VERSION 5.8 ;
BUSBITCHARS "[]" ;
DIVIDERCHAR "/" ;
UNITS
    DATABASE MICRONS 1000 ;
END UNITS

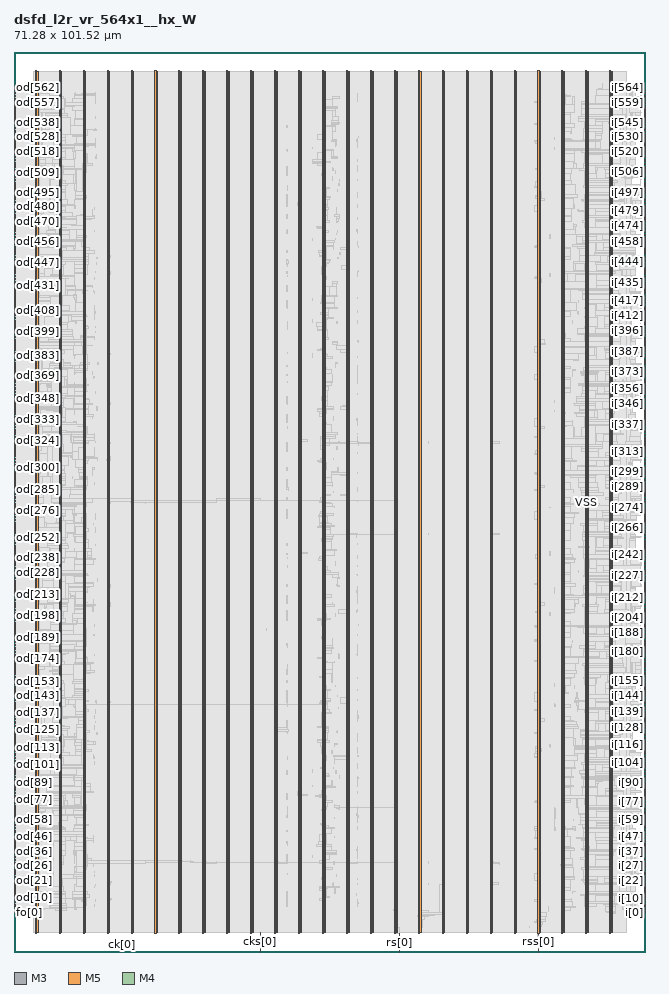
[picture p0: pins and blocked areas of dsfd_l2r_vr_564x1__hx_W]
MACRO dsfd_l2r_vr_564x1__hx_W
  FOREIGN dsfd_l2r_vr_564x1__hx_W 0 0 ;
  CLASS BLOCK ;
  SIZE 71.28 BY 101.52 ;
  PIN ck[0]
    DIRECTION INPUT ;
    USE SIGNAL ;
    PORT
      LAYER M3 ;
        RECT  12.132 0 12.15 0.144 ;
    END
    PORT
      LAYER M3 ;
        RECT  12.132 0.108 12.15 0.173 ;
    END
  END ck[0]
  PIN cks[0]
    DIRECTION INPUT ;
    USE SIGNAL ;
    PORT
      LAYER M5 ;
        RECT  27.792 0 27.816 0.192 ;
    END
    PORT
      LAYER M5 ;
        RECT  27.792 0.144 27.816 2.151 ;
    END
  END cks[0]
  PIN fo[0]
    DIRECTION OUTPUT ;
    USE SIGNAL ;
    PORT
      LAYER M4 ;
        RECT  0 4.416 0.192 4.44 ;
    END
  END fo[0]
  PIN i[0]
    DIRECTION INPUT ;
    USE SIGNAL ;
    PORT
      LAYER M4 ;
        RECT  71.088 4.416 71.28 4.44 ;
    END
  END i[0]
  PIN i[100]
    DIRECTION INPUT ;
    USE SIGNAL ;
    PORT
      LAYER M4 ;
        RECT  71.088 20.784 71.28 20.808 ;
    END
  END i[100]
  PIN i[101]
    DIRECTION INPUT ;
    USE SIGNAL ;
    PORT
      LAYER M4 ;
        RECT  71.088 20.928 71.28 20.952 ;
    END
  END i[101]
  PIN i[102]
    DIRECTION INPUT ;
    USE SIGNAL ;
    PORT
      LAYER M4 ;
        RECT  71.088 21.072 71.28 21.096 ;
    END
  END i[102]
  PIN i[103]
    DIRECTION INPUT ;
    USE SIGNAL ;
    PORT
      LAYER M4 ;
        RECT  71.088 21.264 71.28 21.288 ;
    END
  END i[103]
  PIN i[104]
    DIRECTION INPUT ;
    USE SIGNAL ;
    PORT
      LAYER M4 ;
        RECT  71.088 21.408 71.28 21.432 ;
    END
  END i[104]
  PIN i[105]
    DIRECTION INPUT ;
    USE SIGNAL ;
    PORT
      LAYER M4 ;
        RECT  71.088 21.6 71.28 21.624 ;
    END
  END i[105]
  PIN i[106]
    DIRECTION INPUT ;
    USE SIGNAL ;
    PORT
      LAYER M4 ;
        RECT  71.088 21.744 71.28 21.768 ;
    END
  END i[106]
  PIN i[107]
    DIRECTION INPUT ;
    USE SIGNAL ;
    PORT
      LAYER M4 ;
        RECT  71.088 21.888 71.28 21.912 ;
    END
  END i[107]
  PIN i[108]
    DIRECTION INPUT ;
    USE SIGNAL ;
    PORT
      LAYER M4 ;
        RECT  71.088 22.08 71.28 22.104 ;
    END
  END i[108]
  PIN i[109]
    DIRECTION INPUT ;
    USE SIGNAL ;
    PORT
      LAYER M4 ;
        RECT  71.088 22.224 71.28 22.248 ;
    END
  END i[109]
  PIN i[10]
    DIRECTION INPUT ;
    USE SIGNAL ;
    PORT
      LAYER M4 ;
        RECT  71.088 6.048 71.28 6.072 ;
    END
  END i[10]
  PIN i[110]
    DIRECTION INPUT ;
    USE SIGNAL ;
    PORT
      LAYER M4 ;
        RECT  71.088 22.416 71.28 22.44 ;
    END
  END i[110]
  PIN i[111]
    DIRECTION INPUT ;
    USE SIGNAL ;
    PORT
      LAYER M4 ;
        RECT  71.088 22.56 71.28 22.584 ;
    END
  END i[111]
  PIN i[112]
    DIRECTION INPUT ;
    USE SIGNAL ;
    PORT
      LAYER M4 ;
        RECT  71.088 22.752 71.28 22.776 ;
    END
  END i[112]
  PIN i[113]
    DIRECTION INPUT ;
    USE SIGNAL ;
    PORT
      LAYER M4 ;
        RECT  71.088 22.896 71.28 22.92 ;
    END
  END i[113]
  PIN i[114]
    DIRECTION INPUT ;
    USE SIGNAL ;
    PORT
      LAYER M4 ;
        RECT  71.088 23.04 71.28 23.064 ;
    END
  END i[114]
  PIN i[115]
    DIRECTION INPUT ;
    USE SIGNAL ;
    PORT
      LAYER M4 ;
        RECT  71.088 23.232 71.28 23.256 ;
    END
  END i[115]
  PIN i[116]
    DIRECTION INPUT ;
    USE SIGNAL ;
    PORT
      LAYER M4 ;
        RECT  71.088 23.376 71.28 23.4 ;
    END
  END i[116]
  PIN i[117]
    DIRECTION INPUT ;
    USE SIGNAL ;
    PORT
      LAYER M4 ;
        RECT  71.088 23.568 71.28 23.592 ;
    END
  END i[117]
  PIN i[118]
    DIRECTION INPUT ;
    USE SIGNAL ;
    PORT
      LAYER M4 ;
        RECT  71.088 23.712 71.28 23.736 ;
    END
  END i[118]
  PIN i[119]
    DIRECTION INPUT ;
    USE SIGNAL ;
    PORT
      LAYER M4 ;
        RECT  71.088 23.856 71.28 23.88 ;
    END
  END i[119]
  PIN i[11]
    DIRECTION INPUT ;
    USE SIGNAL ;
    PORT
      LAYER M4 ;
        RECT  71.088 6.192 71.28 6.216 ;
    END
  END i[11]
  PIN i[120]
    DIRECTION INPUT ;
    USE SIGNAL ;
    PORT
      LAYER M4 ;
        RECT  71.088 24.048 71.28 24.072 ;
    END
  END i[120]
  PIN i[121]
    DIRECTION INPUT ;
    USE SIGNAL ;
    PORT
      LAYER M4 ;
        RECT  71.088 24.192 71.28 24.216 ;
    END
  END i[121]
  PIN i[122]
    DIRECTION INPUT ;
    USE SIGNAL ;
    PORT
      LAYER M4 ;
        RECT  71.088 24.384 71.28 24.408 ;
    END
  END i[122]
  PIN i[123]
    DIRECTION INPUT ;
    USE SIGNAL ;
    PORT
      LAYER M4 ;
        RECT  71.088 24.528 71.28 24.552 ;
    END
  END i[123]
  PIN i[124]
    DIRECTION INPUT ;
    USE SIGNAL ;
    PORT
      LAYER M4 ;
        RECT  71.088 24.672 71.28 24.696 ;
    END
  END i[124]
  PIN i[125]
    DIRECTION INPUT ;
    USE SIGNAL ;
    PORT
      LAYER M4 ;
        RECT  71.088 24.864 71.28 24.888 ;
    END
  END i[125]
  PIN i[126]
    DIRECTION INPUT ;
    USE SIGNAL ;
    PORT
      LAYER M4 ;
        RECT  71.088 25.008 71.28 25.032 ;
    END
  END i[126]
  PIN i[127]
    DIRECTION INPUT ;
    USE SIGNAL ;
    PORT
      LAYER M4 ;
        RECT  71.088 25.2 71.28 25.224 ;
    END
  END i[127]
  PIN i[128]
    DIRECTION INPUT ;
    USE SIGNAL ;
    PORT
      LAYER M4 ;
        RECT  71.088 25.344 71.28 25.368 ;
    END
  END i[128]
  PIN i[129]
    DIRECTION INPUT ;
    USE SIGNAL ;
    PORT
      LAYER M4 ;
        RECT  71.088 25.488 71.28 25.512 ;
    END
  END i[129]
  PIN i[12]
    DIRECTION INPUT ;
    USE SIGNAL ;
    PORT
      LAYER M4 ;
        RECT  71.088 6.384 71.28 6.408 ;
    END
  END i[12]
  PIN i[130]
    DIRECTION INPUT ;
    USE SIGNAL ;
    PORT
      LAYER M4 ;
        RECT  71.088 25.68 71.28 25.704 ;
    END
  END i[130]
  PIN i[131]
    DIRECTION INPUT ;
    USE SIGNAL ;
    PORT
      LAYER M4 ;
        RECT  71.088 25.824 71.28 25.848 ;
    END
  END i[131]
  PIN i[132]
    DIRECTION INPUT ;
    USE SIGNAL ;
    PORT
      LAYER M4 ;
        RECT  71.088 26.016 71.28 26.04 ;
    END
  END i[132]
  PIN i[133]
    DIRECTION INPUT ;
    USE SIGNAL ;
    PORT
      LAYER M4 ;
        RECT  71.088 26.16 71.28 26.184 ;
    END
  END i[133]
  PIN i[134]
    DIRECTION INPUT ;
    USE SIGNAL ;
    PORT
      LAYER M4 ;
        RECT  71.088 26.304 71.28 26.328 ;
    END
  END i[134]
  PIN i[135]
    DIRECTION INPUT ;
    USE SIGNAL ;
    PORT
      LAYER M4 ;
        RECT  71.088 26.496 71.28 26.52 ;
    END
  END i[135]
  PIN i[136]
    DIRECTION INPUT ;
    USE SIGNAL ;
    PORT
      LAYER M4 ;
        RECT  71.088 26.64 71.28 26.664 ;
    END
  END i[136]
  PIN i[137]
    DIRECTION INPUT ;
    USE SIGNAL ;
    PORT
      LAYER M4 ;
        RECT  71.088 26.832 71.28 26.856 ;
    END
  END i[137]
  PIN i[138]
    DIRECTION INPUT ;
    USE SIGNAL ;
    PORT
      LAYER M4 ;
        RECT  71.088 26.976 71.28 27 ;
    END
  END i[138]
  PIN i[139]
    DIRECTION INPUT ;
    USE SIGNAL ;
    PORT
      LAYER M4 ;
        RECT  71.088 27.12 71.28 27.144 ;
    END
  END i[139]
  PIN i[13]
    DIRECTION INPUT ;
    USE SIGNAL ;
    PORT
      LAYER M4 ;
        RECT  71.088 6.528 71.28 6.552 ;
    END
  END i[13]
  PIN i[140]
    DIRECTION INPUT ;
    USE SIGNAL ;
    PORT
      LAYER M4 ;
        RECT  71.088 27.312 71.28 27.336 ;
    END
  END i[140]
  PIN i[141]
    DIRECTION INPUT ;
    USE SIGNAL ;
    PORT
      LAYER M4 ;
        RECT  71.088 27.456 71.28 27.48 ;
    END
  END i[141]
  PIN i[142]
    DIRECTION INPUT ;
    USE SIGNAL ;
    PORT
      LAYER M4 ;
        RECT  71.088 27.648 71.28 27.672 ;
    END
  END i[142]
  PIN i[143]
    DIRECTION INPUT ;
    USE SIGNAL ;
    PORT
      LAYER M4 ;
        RECT  71.088 27.792 71.28 27.816 ;
    END
  END i[143]
  PIN i[144]
    DIRECTION INPUT ;
    USE SIGNAL ;
    PORT
      LAYER M4 ;
        RECT  71.088 27.984 71.28 28.008 ;
    END
  END i[144]
  PIN i[145]
    DIRECTION INPUT ;
    USE SIGNAL ;
    PORT
      LAYER M4 ;
        RECT  71.088 28.128 71.28 28.152 ;
    END
  END i[145]
  PIN i[146]
    DIRECTION INPUT ;
    USE SIGNAL ;
    PORT
      LAYER M4 ;
        RECT  71.088 28.272 71.28 28.296 ;
    END
  END i[146]
  PIN i[147]
    DIRECTION INPUT ;
    USE SIGNAL ;
    PORT
      LAYER M4 ;
        RECT  71.088 28.464 71.28 28.488 ;
    END
  END i[147]
  PIN i[148]
    DIRECTION INPUT ;
    USE SIGNAL ;
    PORT
      LAYER M4 ;
        RECT  71.088 28.608 71.28 28.632 ;
    END
  END i[148]
  PIN i[149]
    DIRECTION INPUT ;
    USE SIGNAL ;
    PORT
      LAYER M4 ;
        RECT  71.088 28.8 71.28 28.824 ;
    END
  END i[149]
  PIN i[14]
    DIRECTION INPUT ;
    USE SIGNAL ;
    PORT
      LAYER M4 ;
        RECT  71.088 6.72 71.28 6.744 ;
    END
  END i[14]
  PIN i[150]
    DIRECTION INPUT ;
    USE SIGNAL ;
    PORT
      LAYER M4 ;
        RECT  71.088 28.944 71.28 28.968 ;
    END
  END i[150]
  PIN i[151]
    DIRECTION INPUT ;
    USE SIGNAL ;
    PORT
      LAYER M4 ;
        RECT  71.088 29.088 71.28 29.112 ;
    END
  END i[151]
  PIN i[152]
    DIRECTION INPUT ;
    USE SIGNAL ;
    PORT
      LAYER M4 ;
        RECT  71.088 29.28 71.28 29.304 ;
    END
  END i[152]
  PIN i[153]
    DIRECTION INPUT ;
    USE SIGNAL ;
    PORT
      LAYER M4 ;
        RECT  71.088 29.424 71.28 29.448 ;
    END
  END i[153]
  PIN i[154]
    DIRECTION INPUT ;
    USE SIGNAL ;
    PORT
      LAYER M4 ;
        RECT  71.088 29.616 71.28 29.64 ;
    END
  END i[154]
  PIN i[155]
    DIRECTION INPUT ;
    USE SIGNAL ;
    PORT
      LAYER M4 ;
        RECT  71.088 29.76 71.28 29.784 ;
    END
  END i[155]
  PIN i[156]
    DIRECTION INPUT ;
    USE SIGNAL ;
    PORT
      LAYER M4 ;
        RECT  71.088 29.904 71.28 29.928 ;
    END
  END i[156]
  PIN i[157]
    DIRECTION INPUT ;
    USE SIGNAL ;
    PORT
      LAYER M4 ;
        RECT  71.088 30.096 71.28 30.12 ;
    END
  END i[157]
  PIN i[158]
    DIRECTION INPUT ;
    USE SIGNAL ;
    PORT
      LAYER M4 ;
        RECT  71.088 30.24 71.28 30.264 ;
    END
  END i[158]
  PIN i[159]
    DIRECTION INPUT ;
    USE SIGNAL ;
    PORT
      LAYER M4 ;
        RECT  71.088 30.432 71.28 30.456 ;
    END
  END i[159]
  PIN i[15]
    DIRECTION INPUT ;
    USE SIGNAL ;
    PORT
      LAYER M4 ;
        RECT  71.088 6.864 71.28 6.888 ;
    END
  END i[15]
  PIN i[160]
    DIRECTION INPUT ;
    USE SIGNAL ;
    PORT
      LAYER M4 ;
        RECT  71.088 30.576 71.28 30.6 ;
    END
  END i[160]
  PIN i[161]
    DIRECTION INPUT ;
    USE SIGNAL ;
    PORT
      LAYER M4 ;
        RECT  71.088 30.72 71.28 30.744 ;
    END
  END i[161]
  PIN i[162]
    DIRECTION INPUT ;
    USE SIGNAL ;
    PORT
      LAYER M4 ;
        RECT  71.088 30.912 71.28 30.936 ;
    END
  END i[162]
  PIN i[163]
    DIRECTION INPUT ;
    USE SIGNAL ;
    PORT
      LAYER M4 ;
        RECT  71.088 31.056 71.28 31.08 ;
    END
  END i[163]
  PIN i[164]
    DIRECTION INPUT ;
    USE SIGNAL ;
    PORT
      LAYER M4 ;
        RECT  71.088 31.248 71.28 31.272 ;
    END
  END i[164]
  PIN i[165]
    DIRECTION INPUT ;
    USE SIGNAL ;
    PORT
      LAYER M4 ;
        RECT  71.088 31.392 71.28 31.416 ;
    END
  END i[165]
  PIN i[166]
    DIRECTION INPUT ;
    USE SIGNAL ;
    PORT
      LAYER M4 ;
        RECT  71.088 31.536 71.28 31.56 ;
    END
  END i[166]
  PIN i[167]
    DIRECTION INPUT ;
    USE SIGNAL ;
    PORT
      LAYER M4 ;
        RECT  71.088 31.728 71.28 31.752 ;
    END
  END i[167]
  PIN i[168]
    DIRECTION INPUT ;
    USE SIGNAL ;
    PORT
      LAYER M4 ;
        RECT  71.088 31.872 71.28 31.896 ;
    END
  END i[168]
  PIN i[169]
    DIRECTION INPUT ;
    USE SIGNAL ;
    PORT
      LAYER M4 ;
        RECT  71.088 32.064 71.28 32.088 ;
    END
  END i[169]
  PIN i[16]
    DIRECTION INPUT ;
    USE SIGNAL ;
    PORT
      LAYER M4 ;
        RECT  71.088 7.008 71.28 7.032 ;
    END
  END i[16]
  PIN i[170]
    DIRECTION INPUT ;
    USE SIGNAL ;
    PORT
      LAYER M4 ;
        RECT  71.088 32.208 71.28 32.232 ;
    END
  END i[170]
  PIN i[171]
    DIRECTION INPUT ;
    USE SIGNAL ;
    PORT
      LAYER M4 ;
        RECT  71.088 32.352 71.28 32.376 ;
    END
  END i[171]
  PIN i[172]
    DIRECTION INPUT ;
    USE SIGNAL ;
    PORT
      LAYER M4 ;
        RECT  71.088 32.544 71.28 32.568 ;
    END
  END i[172]
  PIN i[173]
    DIRECTION INPUT ;
    USE SIGNAL ;
    PORT
      LAYER M4 ;
        RECT  71.088 32.688 71.28 32.712 ;
    END
  END i[173]
  PIN i[174]
    DIRECTION INPUT ;
    USE SIGNAL ;
    PORT
      LAYER M4 ;
        RECT  71.088 32.88 71.28 32.904 ;
    END
  END i[174]
  PIN i[175]
    DIRECTION INPUT ;
    USE SIGNAL ;
    PORT
      LAYER M4 ;
        RECT  71.088 33.024 71.28 33.048 ;
    END
  END i[175]
  PIN i[176]
    DIRECTION INPUT ;
    USE SIGNAL ;
    PORT
      LAYER M4 ;
        RECT  71.088 33.216 71.28 33.24 ;
    END
  END i[176]
  PIN i[177]
    DIRECTION INPUT ;
    USE SIGNAL ;
    PORT
      LAYER M4 ;
        RECT  71.088 33.36 71.28 33.384 ;
    END
  END i[177]
  PIN i[178]
    DIRECTION INPUT ;
    USE SIGNAL ;
    PORT
      LAYER M4 ;
        RECT  71.088 33.504 71.28 33.528 ;
    END
  END i[178]
  PIN i[179]
    DIRECTION INPUT ;
    USE SIGNAL ;
    PORT
      LAYER M4 ;
        RECT  71.088 33.696 71.28 33.72 ;
    END
  END i[179]
  PIN i[17]
    DIRECTION INPUT ;
    USE SIGNAL ;
    PORT
      LAYER M4 ;
        RECT  71.088 7.2 71.28 7.224 ;
    END
  END i[17]
  PIN i[180]
    DIRECTION INPUT ;
    USE SIGNAL ;
    PORT
      LAYER M4 ;
        RECT  71.088 33.84 71.28 33.864 ;
    END
  END i[180]
  PIN i[181]
    DIRECTION INPUT ;
    USE SIGNAL ;
    PORT
      LAYER M4 ;
        RECT  71.088 34.032 71.28 34.056 ;
    END
  END i[181]
  PIN i[182]
    DIRECTION INPUT ;
    USE SIGNAL ;
    PORT
      LAYER M4 ;
        RECT  71.088 34.176 71.28 34.2 ;
    END
  END i[182]
  PIN i[183]
    DIRECTION INPUT ;
    USE SIGNAL ;
    PORT
      LAYER M4 ;
        RECT  71.088 34.32 71.28 34.344 ;
    END
  END i[183]
  PIN i[184]
    DIRECTION INPUT ;
    USE SIGNAL ;
    PORT
      LAYER M4 ;
        RECT  71.088 34.512 71.28 34.536 ;
    END
  END i[184]
  PIN i[185]
    DIRECTION INPUT ;
    USE SIGNAL ;
    PORT
      LAYER M4 ;
        RECT  71.088 34.656 71.28 34.68 ;
    END
  END i[185]
  PIN i[186]
    DIRECTION INPUT ;
    USE SIGNAL ;
    PORT
      LAYER M4 ;
        RECT  71.088 34.848 71.28 34.872 ;
    END
  END i[186]
  PIN i[187]
    DIRECTION INPUT ;
    USE SIGNAL ;
    PORT
      LAYER M4 ;
        RECT  71.088 34.992 71.28 35.016 ;
    END
  END i[187]
  PIN i[188]
    DIRECTION INPUT ;
    USE SIGNAL ;
    PORT
      LAYER M4 ;
        RECT  71.088 35.136 71.28 35.16 ;
    END
  END i[188]
  PIN i[189]
    DIRECTION INPUT ;
    USE SIGNAL ;
    PORT
      LAYER M4 ;
        RECT  71.088 35.328 71.28 35.352 ;
    END
  END i[189]
  PIN i[18]
    DIRECTION INPUT ;
    USE SIGNAL ;
    PORT
      LAYER M4 ;
        RECT  71.088 7.344 71.28 7.368 ;
    END
  END i[18]
  PIN i[190]
    DIRECTION INPUT ;
    USE SIGNAL ;
    PORT
      LAYER M4 ;
        RECT  71.088 35.472 71.28 35.496 ;
    END
  END i[190]
  PIN i[191]
    DIRECTION INPUT ;
    USE SIGNAL ;
    PORT
      LAYER M4 ;
        RECT  71.088 35.664 71.28 35.688 ;
    END
  END i[191]
  PIN i[192]
    DIRECTION INPUT ;
    USE SIGNAL ;
    PORT
      LAYER M4 ;
        RECT  71.088 35.808 71.28 35.832 ;
    END
  END i[192]
  PIN i[193]
    DIRECTION INPUT ;
    USE SIGNAL ;
    PORT
      LAYER M4 ;
        RECT  71.088 35.952 71.28 35.976 ;
    END
  END i[193]
  PIN i[194]
    DIRECTION INPUT ;
    USE SIGNAL ;
    PORT
      LAYER M4 ;
        RECT  71.088 36.144 71.28 36.168 ;
    END
  END i[194]
  PIN i[195]
    DIRECTION INPUT ;
    USE SIGNAL ;
    PORT
      LAYER M4 ;
        RECT  71.088 36.288 71.28 36.312 ;
    END
  END i[195]
  PIN i[196]
    DIRECTION INPUT ;
    USE SIGNAL ;
    PORT
      LAYER M4 ;
        RECT  71.088 36.48 71.28 36.504 ;
    END
  END i[196]
  PIN i[197]
    DIRECTION INPUT ;
    USE SIGNAL ;
    PORT
      LAYER M4 ;
        RECT  71.088 36.624 71.28 36.648 ;
    END
  END i[197]
  PIN i[198]
    DIRECTION INPUT ;
    USE SIGNAL ;
    PORT
      LAYER M4 ;
        RECT  71.088 36.768 71.28 36.792 ;
    END
  END i[198]
  PIN i[199]
    DIRECTION INPUT ;
    USE SIGNAL ;
    PORT
      LAYER M4 ;
        RECT  71.088 36.96 71.28 36.984 ;
    END
  END i[199]
  PIN i[19]
    DIRECTION INPUT ;
    USE SIGNAL ;
    PORT
      LAYER M4 ;
        RECT  71.088 7.536 71.28 7.56 ;
    END
  END i[19]
  PIN i[1]
    DIRECTION INPUT ;
    USE SIGNAL ;
    PORT
      LAYER M4 ;
        RECT  71.088 4.56 71.28 4.584 ;
    END
  END i[1]
  PIN i[200]
    DIRECTION INPUT ;
    USE SIGNAL ;
    PORT
      LAYER M4 ;
        RECT  71.088 37.104 71.28 37.128 ;
    END
  END i[200]
  PIN i[201]
    DIRECTION INPUT ;
    USE SIGNAL ;
    PORT
      LAYER M4 ;
        RECT  71.088 37.296 71.28 37.32 ;
    END
  END i[201]
  PIN i[202]
    DIRECTION INPUT ;
    USE SIGNAL ;
    PORT
      LAYER M4 ;
        RECT  71.088 37.44 71.28 37.464 ;
    END
  END i[202]
  PIN i[203]
    DIRECTION INPUT ;
    USE SIGNAL ;
    PORT
      LAYER M4 ;
        RECT  71.088 37.632 71.28 37.656 ;
    END
  END i[203]
  PIN i[204]
    DIRECTION INPUT ;
    USE SIGNAL ;
    PORT
      LAYER M4 ;
        RECT  71.088 37.776 71.28 37.8 ;
    END
  END i[204]
  PIN i[205]
    DIRECTION INPUT ;
    USE SIGNAL ;
    PORT
      LAYER M4 ;
        RECT  71.088 37.92 71.28 37.944 ;
    END
  END i[205]
  PIN i[206]
    DIRECTION INPUT ;
    USE SIGNAL ;
    PORT
      LAYER M4 ;
        RECT  71.088 38.112 71.28 38.136 ;
    END
  END i[206]
  PIN i[207]
    DIRECTION INPUT ;
    USE SIGNAL ;
    PORT
      LAYER M4 ;
        RECT  71.088 38.256 71.28 38.28 ;
    END
  END i[207]
  PIN i[208]
    DIRECTION INPUT ;
    USE SIGNAL ;
    PORT
      LAYER M4 ;
        RECT  71.088 38.448 71.28 38.472 ;
    END
  END i[208]
  PIN i[209]
    DIRECTION INPUT ;
    USE SIGNAL ;
    PORT
      LAYER M4 ;
        RECT  71.088 38.592 71.28 38.616 ;
    END
  END i[209]
  PIN i[20]
    DIRECTION INPUT ;
    USE SIGNAL ;
    PORT
      LAYER M4 ;
        RECT  71.088 7.68 71.28 7.704 ;
    END
  END i[20]
  PIN i[210]
    DIRECTION INPUT ;
    USE SIGNAL ;
    PORT
      LAYER M4 ;
        RECT  71.088 38.736 71.28 38.76 ;
    END
  END i[210]
  PIN i[211]
    DIRECTION INPUT ;
    USE SIGNAL ;
    PORT
      LAYER M4 ;
        RECT  71.088 38.928 71.28 38.952 ;
    END
  END i[211]
  PIN i[212]
    DIRECTION INPUT ;
    USE SIGNAL ;
    PORT
      LAYER M4 ;
        RECT  71.088 39.072 71.28 39.096 ;
    END
  END i[212]
  PIN i[213]
    DIRECTION INPUT ;
    USE SIGNAL ;
    PORT
      LAYER M4 ;
        RECT  71.088 39.264 71.28 39.288 ;
    END
  END i[213]
  PIN i[214]
    DIRECTION INPUT ;
    USE SIGNAL ;
    PORT
      LAYER M4 ;
        RECT  71.088 39.408 71.28 39.432 ;
    END
  END i[214]
  PIN i[215]
    DIRECTION INPUT ;
    USE SIGNAL ;
    PORT
      LAYER M4 ;
        RECT  71.088 39.552 71.28 39.576 ;
    END
  END i[215]
  PIN i[216]
    DIRECTION INPUT ;
    USE SIGNAL ;
    PORT
      LAYER M4 ;
        RECT  71.088 39.744 71.28 39.768 ;
    END
  END i[216]
  PIN i[217]
    DIRECTION INPUT ;
    USE SIGNAL ;
    PORT
      LAYER M4 ;
        RECT  71.088 39.888 71.28 39.912 ;
    END
  END i[217]
  PIN i[218]
    DIRECTION INPUT ;
    USE SIGNAL ;
    PORT
      LAYER M4 ;
        RECT  71.088 40.08 71.28 40.104 ;
    END
  END i[218]
  PIN i[219]
    DIRECTION INPUT ;
    USE SIGNAL ;
    PORT
      LAYER M4 ;
        RECT  71.088 40.224 71.28 40.248 ;
    END
  END i[219]
  PIN i[21]
    DIRECTION INPUT ;
    USE SIGNAL ;
    PORT
      LAYER M4 ;
        RECT  71.088 7.824 71.28 7.848 ;
    END
  END i[21]
  PIN i[220]
    DIRECTION INPUT ;
    USE SIGNAL ;
    PORT
      LAYER M4 ;
        RECT  71.088 40.368 71.28 40.392 ;
    END
  END i[220]
  PIN i[221]
    DIRECTION INPUT ;
    USE SIGNAL ;
    PORT
      LAYER M4 ;
        RECT  71.088 40.56 71.28 40.584 ;
    END
  END i[221]
  PIN i[222]
    DIRECTION INPUT ;
    USE SIGNAL ;
    PORT
      LAYER M4 ;
        RECT  71.088 40.704 71.28 40.728 ;
    END
  END i[222]
  PIN i[223]
    DIRECTION INPUT ;
    USE SIGNAL ;
    PORT
      LAYER M4 ;
        RECT  71.088 40.896 71.28 40.92 ;
    END
  END i[223]
  PIN i[224]
    DIRECTION INPUT ;
    USE SIGNAL ;
    PORT
      LAYER M4 ;
        RECT  71.088 41.04 71.28 41.064 ;
    END
  END i[224]
  PIN i[225]
    DIRECTION INPUT ;
    USE SIGNAL ;
    PORT
      LAYER M4 ;
        RECT  71.088 41.184 71.28 41.208 ;
    END
  END i[225]
  PIN i[226]
    DIRECTION INPUT ;
    USE SIGNAL ;
    PORT
      LAYER M4 ;
        RECT  71.088 41.376 71.28 41.4 ;
    END
  END i[226]
  PIN i[227]
    DIRECTION INPUT ;
    USE SIGNAL ;
    PORT
      LAYER M4 ;
        RECT  71.088 41.52 71.28 41.544 ;
    END
  END i[227]
  PIN i[228]
    DIRECTION INPUT ;
    USE SIGNAL ;
    PORT
      LAYER M4 ;
        RECT  71.088 41.712 71.28 41.736 ;
    END
  END i[228]
  PIN i[229]
    DIRECTION INPUT ;
    USE SIGNAL ;
    PORT
      LAYER M4 ;
        RECT  71.088 41.856 71.28 41.88 ;
    END
  END i[229]
  PIN i[22]
    DIRECTION INPUT ;
    USE SIGNAL ;
    PORT
      LAYER M4 ;
        RECT  71.088 8.016 71.28 8.04 ;
    END
  END i[22]
  PIN i[230]
    DIRECTION INPUT ;
    USE SIGNAL ;
    PORT
      LAYER M4 ;
        RECT  71.088 42 71.28 42.024 ;
    END
  END i[230]
  PIN i[231]
    DIRECTION INPUT ;
    USE SIGNAL ;
    PORT
      LAYER M4 ;
        RECT  71.088 42.192 71.28 42.216 ;
    END
  END i[231]
  PIN i[232]
    DIRECTION INPUT ;
    USE SIGNAL ;
    PORT
      LAYER M4 ;
        RECT  71.088 42.336 71.28 42.36 ;
    END
  END i[232]
  PIN i[233]
    DIRECTION INPUT ;
    USE SIGNAL ;
    PORT
      LAYER M4 ;
        RECT  71.088 42.528 71.28 42.552 ;
    END
  END i[233]
  PIN i[234]
    DIRECTION INPUT ;
    USE SIGNAL ;
    PORT
      LAYER M4 ;
        RECT  71.088 42.672 71.28 42.696 ;
    END
  END i[234]
  PIN i[235]
    DIRECTION INPUT ;
    USE SIGNAL ;
    PORT
      LAYER M4 ;
        RECT  71.088 42.864 71.28 42.888 ;
    END
  END i[235]
  PIN i[236]
    DIRECTION INPUT ;
    USE SIGNAL ;
    PORT
      LAYER M4 ;
        RECT  71.088 43.008 71.28 43.032 ;
    END
  END i[236]
  PIN i[237]
    DIRECTION INPUT ;
    USE SIGNAL ;
    PORT
      LAYER M4 ;
        RECT  71.088 43.152 71.28 43.176 ;
    END
  END i[237]
  PIN i[238]
    DIRECTION INPUT ;
    USE SIGNAL ;
    PORT
      LAYER M4 ;
        RECT  71.088 43.344 71.28 43.368 ;
    END
  END i[238]
  PIN i[239]
    DIRECTION INPUT ;
    USE SIGNAL ;
    PORT
      LAYER M4 ;
        RECT  71.088 43.488 71.28 43.512 ;
    END
  END i[239]
  PIN i[23]
    DIRECTION INPUT ;
    USE SIGNAL ;
    PORT
      LAYER M4 ;
        RECT  71.088 8.16 71.28 8.184 ;
    END
  END i[23]
  PIN i[240]
    DIRECTION INPUT ;
    USE SIGNAL ;
    PORT
      LAYER M4 ;
        RECT  71.088 43.68 71.28 43.704 ;
    END
  END i[240]
  PIN i[241]
    DIRECTION INPUT ;
    USE SIGNAL ;
    PORT
      LAYER M4 ;
        RECT  71.088 43.824 71.28 43.848 ;
    END
  END i[241]
  PIN i[242]
    DIRECTION INPUT ;
    USE SIGNAL ;
    PORT
      LAYER M4 ;
        RECT  71.088 43.968 71.28 43.992 ;
    END
  END i[242]
  PIN i[243]
    DIRECTION INPUT ;
    USE SIGNAL ;
    PORT
      LAYER M4 ;
        RECT  71.088 44.16 71.28 44.184 ;
    END
  END i[243]
  PIN i[244]
    DIRECTION INPUT ;
    USE SIGNAL ;
    PORT
      LAYER M4 ;
        RECT  71.088 44.304 71.28 44.328 ;
    END
  END i[244]
  PIN i[245]
    DIRECTION INPUT ;
    USE SIGNAL ;
    PORT
      LAYER M4 ;
        RECT  71.088 44.496 71.28 44.52 ;
    END
  END i[245]
  PIN i[246]
    DIRECTION INPUT ;
    USE SIGNAL ;
    PORT
      LAYER M4 ;
        RECT  71.088 44.64 71.28 44.664 ;
    END
  END i[246]
  PIN i[247]
    DIRECTION INPUT ;
    USE SIGNAL ;
    PORT
      LAYER M4 ;
        RECT  71.088 44.784 71.28 44.808 ;
    END
  END i[247]
  PIN i[248]
    DIRECTION INPUT ;
    USE SIGNAL ;
    PORT
      LAYER M4 ;
        RECT  71.088 44.976 71.28 45 ;
    END
  END i[248]
  PIN i[249]
    DIRECTION INPUT ;
    USE SIGNAL ;
    PORT
      LAYER M4 ;
        RECT  71.088 45.12 71.28 45.144 ;
    END
  END i[249]
  PIN i[24]
    DIRECTION INPUT ;
    USE SIGNAL ;
    PORT
      LAYER M4 ;
        RECT  71.088 8.352 71.28 8.376 ;
    END
  END i[24]
  PIN i[250]
    DIRECTION INPUT ;
    USE SIGNAL ;
    PORT
      LAYER M4 ;
        RECT  71.088 45.312 71.28 45.336 ;
    END
  END i[250]
  PIN i[251]
    DIRECTION INPUT ;
    USE SIGNAL ;
    PORT
      LAYER M4 ;
        RECT  71.088 45.456 71.28 45.48 ;
    END
  END i[251]
  PIN i[252]
    DIRECTION INPUT ;
    USE SIGNAL ;
    PORT
      LAYER M4 ;
        RECT  71.088 45.6 71.28 45.624 ;
    END
  END i[252]
  PIN i[253]
    DIRECTION INPUT ;
    USE SIGNAL ;
    PORT
      LAYER M4 ;
        RECT  71.088 45.792 71.28 45.816 ;
    END
  END i[253]
  PIN i[254]
    DIRECTION INPUT ;
    USE SIGNAL ;
    PORT
      LAYER M4 ;
        RECT  71.088 45.936 71.28 45.96 ;
    END
  END i[254]
  PIN i[255]
    DIRECTION INPUT ;
    USE SIGNAL ;
    PORT
      LAYER M4 ;
        RECT  71.088 46.128 71.28 46.152 ;
    END
  END i[255]
  PIN i[256]
    DIRECTION INPUT ;
    USE SIGNAL ;
    PORT
      LAYER M4 ;
        RECT  71.088 46.272 71.28 46.296 ;
    END
  END i[256]
  PIN i[257]
    DIRECTION INPUT ;
    USE SIGNAL ;
    PORT
      LAYER M4 ;
        RECT  71.088 46.416 71.28 46.44 ;
    END
  END i[257]
  PIN i[258]
    DIRECTION INPUT ;
    USE SIGNAL ;
    PORT
      LAYER M4 ;
        RECT  71.088 46.608 71.28 46.632 ;
    END
  END i[258]
  PIN i[259]
    DIRECTION INPUT ;
    USE SIGNAL ;
    PORT
      LAYER M4 ;
        RECT  71.088 46.752 71.28 46.776 ;
    END
  END i[259]
  PIN i[25]
    DIRECTION INPUT ;
    USE SIGNAL ;
    PORT
      LAYER M4 ;
        RECT  71.088 8.496 71.28 8.52 ;
    END
  END i[25]
  PIN i[260]
    DIRECTION INPUT ;
    USE SIGNAL ;
    PORT
      LAYER M4 ;
        RECT  71.088 46.944 71.28 46.968 ;
    END
  END i[260]
  PIN i[261]
    DIRECTION INPUT ;
    USE SIGNAL ;
    PORT
      LAYER M4 ;
        RECT  71.088 47.088 71.28 47.112 ;
    END
  END i[261]
  PIN i[262]
    DIRECTION INPUT ;
    USE SIGNAL ;
    PORT
      LAYER M4 ;
        RECT  71.088 47.28 71.28 47.304 ;
    END
  END i[262]
  PIN i[263]
    DIRECTION INPUT ;
    USE SIGNAL ;
    PORT
      LAYER M4 ;
        RECT  71.088 47.424 71.28 47.448 ;
    END
  END i[263]
  PIN i[264]
    DIRECTION INPUT ;
    USE SIGNAL ;
    PORT
      LAYER M4 ;
        RECT  71.088 47.568 71.28 47.592 ;
    END
  END i[264]
  PIN i[265]
    DIRECTION INPUT ;
    USE SIGNAL ;
    PORT
      LAYER M4 ;
        RECT  71.088 47.76 71.28 47.784 ;
    END
  END i[265]
  PIN i[266]
    DIRECTION INPUT ;
    USE SIGNAL ;
    PORT
      LAYER M4 ;
        RECT  71.088 47.904 71.28 47.928 ;
    END
  END i[266]
  PIN i[267]
    DIRECTION INPUT ;
    USE SIGNAL ;
    PORT
      LAYER M4 ;
        RECT  71.088 48.096 71.28 48.12 ;
    END
  END i[267]
  PIN i[268]
    DIRECTION INPUT ;
    USE SIGNAL ;
    PORT
      LAYER M4 ;
        RECT  71.088 48.24 71.28 48.264 ;
    END
  END i[268]
  PIN i[269]
    DIRECTION INPUT ;
    USE SIGNAL ;
    PORT
      LAYER M4 ;
        RECT  71.088 48.384 71.28 48.408 ;
    END
  END i[269]
  PIN i[26]
    DIRECTION INPUT ;
    USE SIGNAL ;
    PORT
      LAYER M4 ;
        RECT  71.088 8.688 71.28 8.712 ;
    END
  END i[26]
  PIN i[270]
    DIRECTION INPUT ;
    USE SIGNAL ;
    PORT
      LAYER M4 ;
        RECT  71.088 48.576 71.28 48.6 ;
    END
  END i[270]
  PIN i[271]
    DIRECTION INPUT ;
    USE SIGNAL ;
    PORT
      LAYER M4 ;
        RECT  71.088 48.72 71.28 48.744 ;
    END
  END i[271]
  PIN i[272]
    DIRECTION INPUT ;
    USE SIGNAL ;
    PORT
      LAYER M4 ;
        RECT  71.088 48.912 71.28 48.936 ;
    END
  END i[272]
  PIN i[273]
    DIRECTION INPUT ;
    USE SIGNAL ;
    PORT
      LAYER M4 ;
        RECT  71.088 49.056 71.28 49.08 ;
    END
  END i[273]
  PIN i[274]
    DIRECTION INPUT ;
    USE SIGNAL ;
    PORT
      LAYER M4 ;
        RECT  71.088 49.2 71.28 49.224 ;
    END
  END i[274]
  PIN i[275]
    DIRECTION INPUT ;
    USE SIGNAL ;
    PORT
      LAYER M4 ;
        RECT  71.088 49.392 71.28 49.416 ;
    END
  END i[275]
  PIN i[276]
    DIRECTION INPUT ;
    USE SIGNAL ;
    PORT
      LAYER M4 ;
        RECT  71.088 49.536 71.28 49.56 ;
    END
  END i[276]
  PIN i[277]
    DIRECTION INPUT ;
    USE SIGNAL ;
    PORT
      LAYER M4 ;
        RECT  71.088 49.728 71.28 49.752 ;
    END
  END i[277]
  PIN i[278]
    DIRECTION INPUT ;
    USE SIGNAL ;
    PORT
      LAYER M4 ;
        RECT  71.088 49.872 71.28 49.896 ;
    END
  END i[278]
  PIN i[279]
    DIRECTION INPUT ;
    USE SIGNAL ;
    PORT
      LAYER M4 ;
        RECT  71.088 50.016 71.28 50.04 ;
    END
  END i[279]
  PIN i[27]
    DIRECTION INPUT ;
    USE SIGNAL ;
    PORT
      LAYER M4 ;
        RECT  71.088 8.832 71.28 8.856 ;
    END
  END i[27]
  PIN i[280]
    DIRECTION INPUT ;
    USE SIGNAL ;
    PORT
      LAYER M4 ;
        RECT  71.088 50.208 71.28 50.232 ;
    END
  END i[280]
  PIN i[281]
    DIRECTION INPUT ;
    USE SIGNAL ;
    PORT
      LAYER M4 ;
        RECT  71.088 50.352 71.28 50.376 ;
    END
  END i[281]
  PIN i[282]
    DIRECTION INPUT ;
    USE SIGNAL ;
    PORT
      LAYER M4 ;
        RECT  71.088 50.544 71.28 50.568 ;
    END
  END i[282]
  PIN i[283]
    DIRECTION INPUT ;
    USE SIGNAL ;
    PORT
      LAYER M4 ;
        RECT  71.088 50.688 71.28 50.712 ;
    END
  END i[283]
  PIN i[284]
    DIRECTION INPUT ;
    USE SIGNAL ;
    PORT
      LAYER M4 ;
        RECT  71.088 50.832 71.28 50.856 ;
    END
  END i[284]
  PIN i[285]
    DIRECTION INPUT ;
    USE SIGNAL ;
    PORT
      LAYER M4 ;
        RECT  71.088 51.024 71.28 51.048 ;
    END
  END i[285]
  PIN i[286]
    DIRECTION INPUT ;
    USE SIGNAL ;
    PORT
      LAYER M4 ;
        RECT  71.088 51.168 71.28 51.192 ;
    END
  END i[286]
  PIN i[287]
    DIRECTION INPUT ;
    USE SIGNAL ;
    PORT
      LAYER M4 ;
        RECT  71.088 51.36 71.28 51.384 ;
    END
  END i[287]
  PIN i[288]
    DIRECTION INPUT ;
    USE SIGNAL ;
    PORT
      LAYER M4 ;
        RECT  71.088 51.504 71.28 51.528 ;
    END
  END i[288]
  PIN i[289]
    DIRECTION INPUT ;
    USE SIGNAL ;
    PORT
      LAYER M4 ;
        RECT  71.088 51.648 71.28 51.672 ;
    END
  END i[289]
  PIN i[28]
    DIRECTION INPUT ;
    USE SIGNAL ;
    PORT
      LAYER M4 ;
        RECT  71.088 8.976 71.28 9 ;
    END
  END i[28]
  PIN i[290]
    DIRECTION INPUT ;
    USE SIGNAL ;
    PORT
      LAYER M4 ;
        RECT  71.088 51.84 71.28 51.864 ;
    END
  END i[290]
  PIN i[291]
    DIRECTION INPUT ;
    USE SIGNAL ;
    PORT
      LAYER M4 ;
        RECT  71.088 51.984 71.28 52.008 ;
    END
  END i[291]
  PIN i[292]
    DIRECTION INPUT ;
    USE SIGNAL ;
    PORT
      LAYER M4 ;
        RECT  71.088 52.176 71.28 52.2 ;
    END
  END i[292]
  PIN i[293]
    DIRECTION INPUT ;
    USE SIGNAL ;
    PORT
      LAYER M4 ;
        RECT  71.088 52.32 71.28 52.344 ;
    END
  END i[293]
  PIN i[294]
    DIRECTION INPUT ;
    USE SIGNAL ;
    PORT
      LAYER M4 ;
        RECT  71.088 52.512 71.28 52.536 ;
    END
  END i[294]
  PIN i[295]
    DIRECTION INPUT ;
    USE SIGNAL ;
    PORT
      LAYER M4 ;
        RECT  71.088 52.656 71.28 52.68 ;
    END
  END i[295]
  PIN i[296]
    DIRECTION INPUT ;
    USE SIGNAL ;
    PORT
      LAYER M4 ;
        RECT  71.088 52.8 71.28 52.824 ;
    END
  END i[296]
  PIN i[297]
    DIRECTION INPUT ;
    USE SIGNAL ;
    PORT
      LAYER M4 ;
        RECT  71.088 52.992 71.28 53.016 ;
    END
  END i[297]
  PIN i[298]
    DIRECTION INPUT ;
    USE SIGNAL ;
    PORT
      LAYER M4 ;
        RECT  71.088 53.136 71.28 53.16 ;
    END
  END i[298]
  PIN i[299]
    DIRECTION INPUT ;
    USE SIGNAL ;
    PORT
      LAYER M4 ;
        RECT  71.088 53.328 71.28 53.352 ;
    END
  END i[299]
  PIN i[29]
    DIRECTION INPUT ;
    USE SIGNAL ;
    PORT
      LAYER M4 ;
        RECT  71.088 9.168 71.28 9.192 ;
    END
  END i[29]
  PIN i[2]
    DIRECTION INPUT ;
    USE SIGNAL ;
    PORT
      LAYER M4 ;
        RECT  71.088 4.752 71.28 4.776 ;
    END
  END i[2]
  PIN i[300]
    DIRECTION INPUT ;
    USE SIGNAL ;
    PORT
      LAYER M4 ;
        RECT  71.088 53.472 71.28 53.496 ;
    END
  END i[300]
  PIN i[301]
    DIRECTION INPUT ;
    USE SIGNAL ;
    PORT
      LAYER M4 ;
        RECT  71.088 53.616 71.28 53.64 ;
    END
  END i[301]
  PIN i[302]
    DIRECTION INPUT ;
    USE SIGNAL ;
    PORT
      LAYER M4 ;
        RECT  71.088 53.808 71.28 53.832 ;
    END
  END i[302]
  PIN i[303]
    DIRECTION INPUT ;
    USE SIGNAL ;
    PORT
      LAYER M4 ;
        RECT  71.088 53.952 71.28 53.976 ;
    END
  END i[303]
  PIN i[304]
    DIRECTION INPUT ;
    USE SIGNAL ;
    PORT
      LAYER M4 ;
        RECT  71.088 54.144 71.28 54.168 ;
    END
  END i[304]
  PIN i[305]
    DIRECTION INPUT ;
    USE SIGNAL ;
    PORT
      LAYER M4 ;
        RECT  71.088 54.288 71.28 54.312 ;
    END
  END i[305]
  PIN i[306]
    DIRECTION INPUT ;
    USE SIGNAL ;
    PORT
      LAYER M4 ;
        RECT  71.088 54.432 71.28 54.456 ;
    END
  END i[306]
  PIN i[307]
    DIRECTION INPUT ;
    USE SIGNAL ;
    PORT
      LAYER M4 ;
        RECT  71.088 54.624 71.28 54.648 ;
    END
  END i[307]
  PIN i[308]
    DIRECTION INPUT ;
    USE SIGNAL ;
    PORT
      LAYER M4 ;
        RECT  71.088 54.768 71.28 54.792 ;
    END
  END i[308]
  PIN i[309]
    DIRECTION INPUT ;
    USE SIGNAL ;
    PORT
      LAYER M4 ;
        RECT  71.088 54.96 71.28 54.984 ;
    END
  END i[309]
  PIN i[30]
    DIRECTION INPUT ;
    USE SIGNAL ;
    PORT
      LAYER M4 ;
        RECT  71.088 9.312 71.28 9.336 ;
    END
  END i[30]
  PIN i[310]
    DIRECTION INPUT ;
    USE SIGNAL ;
    PORT
      LAYER M4 ;
        RECT  71.088 55.104 71.28 55.128 ;
    END
  END i[310]
  PIN i[311]
    DIRECTION INPUT ;
    USE SIGNAL ;
    PORT
      LAYER M4 ;
        RECT  71.088 55.248 71.28 55.272 ;
    END
  END i[311]
  PIN i[312]
    DIRECTION INPUT ;
    USE SIGNAL ;
    PORT
      LAYER M4 ;
        RECT  71.088 55.44 71.28 55.464 ;
    END
  END i[312]
  PIN i[313]
    DIRECTION INPUT ;
    USE SIGNAL ;
    PORT
      LAYER M4 ;
        RECT  71.088 55.584 71.28 55.608 ;
    END
  END i[313]
  PIN i[314]
    DIRECTION INPUT ;
    USE SIGNAL ;
    PORT
      LAYER M4 ;
        RECT  71.088 55.776 71.28 55.8 ;
    END
  END i[314]
  PIN i[315]
    DIRECTION INPUT ;
    USE SIGNAL ;
    PORT
      LAYER M4 ;
        RECT  71.088 55.92 71.28 55.944 ;
    END
  END i[315]
  PIN i[316]
    DIRECTION INPUT ;
    USE SIGNAL ;
    PORT
      LAYER M4 ;
        RECT  71.088 56.064 71.28 56.088 ;
    END
  END i[316]
  PIN i[317]
    DIRECTION INPUT ;
    USE SIGNAL ;
    PORT
      LAYER M4 ;
        RECT  71.088 56.256 71.28 56.28 ;
    END
  END i[317]
  PIN i[318]
    DIRECTION INPUT ;
    USE SIGNAL ;
    PORT
      LAYER M4 ;
        RECT  71.088 56.4 71.28 56.424 ;
    END
  END i[318]
  PIN i[319]
    DIRECTION INPUT ;
    USE SIGNAL ;
    PORT
      LAYER M4 ;
        RECT  71.088 56.592 71.28 56.616 ;
    END
  END i[319]
  PIN i[31]
    DIRECTION INPUT ;
    USE SIGNAL ;
    PORT
      LAYER M4 ;
        RECT  71.088 9.504 71.28 9.528 ;
    END
  END i[31]
  PIN i[320]
    DIRECTION INPUT ;
    USE SIGNAL ;
    PORT
      LAYER M4 ;
        RECT  71.088 56.736 71.28 56.76 ;
    END
  END i[320]
  PIN i[321]
    DIRECTION INPUT ;
    USE SIGNAL ;
    PORT
      LAYER M4 ;
        RECT  71.088 56.928 71.28 56.952 ;
    END
  END i[321]
  PIN i[322]
    DIRECTION INPUT ;
    USE SIGNAL ;
    PORT
      LAYER M4 ;
        RECT  71.088 57.072 71.28 57.096 ;
    END
  END i[322]
  PIN i[323]
    DIRECTION INPUT ;
    USE SIGNAL ;
    PORT
      LAYER M4 ;
        RECT  71.088 57.216 71.28 57.24 ;
    END
  END i[323]
  PIN i[324]
    DIRECTION INPUT ;
    USE SIGNAL ;
    PORT
      LAYER M4 ;
        RECT  71.088 57.408 71.28 57.432 ;
    END
  END i[324]
  PIN i[325]
    DIRECTION INPUT ;
    USE SIGNAL ;
    PORT
      LAYER M4 ;
        RECT  71.088 57.552 71.28 57.576 ;
    END
  END i[325]
  PIN i[326]
    DIRECTION INPUT ;
    USE SIGNAL ;
    PORT
      LAYER M4 ;
        RECT  71.088 57.744 71.28 57.768 ;
    END
  END i[326]
  PIN i[327]
    DIRECTION INPUT ;
    USE SIGNAL ;
    PORT
      LAYER M4 ;
        RECT  71.088 57.888 71.28 57.912 ;
    END
  END i[327]
  PIN i[328]
    DIRECTION INPUT ;
    USE SIGNAL ;
    PORT
      LAYER M4 ;
        RECT  71.088 58.032 71.28 58.056 ;
    END
  END i[328]
  PIN i[329]
    DIRECTION INPUT ;
    USE SIGNAL ;
    PORT
      LAYER M4 ;
        RECT  71.088 58.224 71.28 58.248 ;
    END
  END i[329]
  PIN i[32]
    DIRECTION INPUT ;
    USE SIGNAL ;
    PORT
      LAYER M4 ;
        RECT  71.088 9.648 71.28 9.672 ;
    END
  END i[32]
  PIN i[330]
    DIRECTION INPUT ;
    USE SIGNAL ;
    PORT
      LAYER M4 ;
        RECT  71.088 58.368 71.28 58.392 ;
    END
  END i[330]
  PIN i[331]
    DIRECTION INPUT ;
    USE SIGNAL ;
    PORT
      LAYER M4 ;
        RECT  71.088 58.56 71.28 58.584 ;
    END
  END i[331]
  PIN i[332]
    DIRECTION INPUT ;
    USE SIGNAL ;
    PORT
      LAYER M4 ;
        RECT  71.088 58.704 71.28 58.728 ;
    END
  END i[332]
  PIN i[333]
    DIRECTION INPUT ;
    USE SIGNAL ;
    PORT
      LAYER M4 ;
        RECT  71.088 58.848 71.28 58.872 ;
    END
  END i[333]
  PIN i[334]
    DIRECTION INPUT ;
    USE SIGNAL ;
    PORT
      LAYER M4 ;
        RECT  71.088 59.04 71.28 59.064 ;
    END
  END i[334]
  PIN i[335]
    DIRECTION INPUT ;
    USE SIGNAL ;
    PORT
      LAYER M4 ;
        RECT  71.088 59.184 71.28 59.208 ;
    END
  END i[335]
  PIN i[336]
    DIRECTION INPUT ;
    USE SIGNAL ;
    PORT
      LAYER M4 ;
        RECT  71.088 59.376 71.28 59.4 ;
    END
  END i[336]
  PIN i[337]
    DIRECTION INPUT ;
    USE SIGNAL ;
    PORT
      LAYER M4 ;
        RECT  71.088 59.52 71.28 59.544 ;
    END
  END i[337]
  PIN i[338]
    DIRECTION INPUT ;
    USE SIGNAL ;
    PORT
      LAYER M4 ;
        RECT  71.088 59.664 71.28 59.688 ;
    END
  END i[338]
  PIN i[339]
    DIRECTION INPUT ;
    USE SIGNAL ;
    PORT
      LAYER M4 ;
        RECT  71.088 59.856 71.28 59.88 ;
    END
  END i[339]
  PIN i[33]
    DIRECTION INPUT ;
    USE SIGNAL ;
    PORT
      LAYER M4 ;
        RECT  71.088 9.792 71.28 9.816 ;
    END
  END i[33]
  PIN i[340]
    DIRECTION INPUT ;
    USE SIGNAL ;
    PORT
      LAYER M4 ;
        RECT  71.088 60 71.28 60.024 ;
    END
  END i[340]
  PIN i[341]
    DIRECTION INPUT ;
    USE SIGNAL ;
    PORT
      LAYER M4 ;
        RECT  71.088 60.192 71.28 60.216 ;
    END
  END i[341]
  PIN i[342]
    DIRECTION INPUT ;
    USE SIGNAL ;
    PORT
      LAYER M4 ;
        RECT  71.088 60.336 71.28 60.36 ;
    END
  END i[342]
  PIN i[343]
    DIRECTION INPUT ;
    USE SIGNAL ;
    PORT
      LAYER M4 ;
        RECT  71.088 60.48 71.28 60.504 ;
    END
  END i[343]
  PIN i[344]
    DIRECTION INPUT ;
    USE SIGNAL ;
    PORT
      LAYER M4 ;
        RECT  71.088 60.672 71.28 60.696 ;
    END
  END i[344]
  PIN i[345]
    DIRECTION INPUT ;
    USE SIGNAL ;
    PORT
      LAYER M4 ;
        RECT  71.088 60.816 71.28 60.84 ;
    END
  END i[345]
  PIN i[346]
    DIRECTION INPUT ;
    USE SIGNAL ;
    PORT
      LAYER M4 ;
        RECT  71.088 61.008 71.28 61.032 ;
    END
  END i[346]
  PIN i[347]
    DIRECTION INPUT ;
    USE SIGNAL ;
    PORT
      LAYER M4 ;
        RECT  71.088 61.152 71.28 61.176 ;
    END
  END i[347]
  PIN i[348]
    DIRECTION INPUT ;
    USE SIGNAL ;
    PORT
      LAYER M4 ;
        RECT  71.088 61.296 71.28 61.32 ;
    END
  END i[348]
  PIN i[349]
    DIRECTION INPUT ;
    USE SIGNAL ;
    PORT
      LAYER M4 ;
        RECT  71.088 61.488 71.28 61.512 ;
    END
  END i[349]
  PIN i[34]
    DIRECTION INPUT ;
    USE SIGNAL ;
    PORT
      LAYER M4 ;
        RECT  71.088 9.984 71.28 10.008 ;
    END
  END i[34]
  PIN i[350]
    DIRECTION INPUT ;
    USE SIGNAL ;
    PORT
      LAYER M4 ;
        RECT  71.088 61.632 71.28 61.656 ;
    END
  END i[350]
  PIN i[351]
    DIRECTION INPUT ;
    USE SIGNAL ;
    PORT
      LAYER M4 ;
        RECT  71.088 61.824 71.28 61.848 ;
    END
  END i[351]
  PIN i[352]
    DIRECTION INPUT ;
    USE SIGNAL ;
    PORT
      LAYER M4 ;
        RECT  71.088 61.968 71.28 61.992 ;
    END
  END i[352]
  PIN i[353]
    DIRECTION INPUT ;
    USE SIGNAL ;
    PORT
      LAYER M4 ;
        RECT  71.088 62.16 71.28 62.184 ;
    END
  END i[353]
  PIN i[354]
    DIRECTION INPUT ;
    USE SIGNAL ;
    PORT
      LAYER M4 ;
        RECT  71.088 62.304 71.28 62.328 ;
    END
  END i[354]
  PIN i[355]
    DIRECTION INPUT ;
    USE SIGNAL ;
    PORT
      LAYER M4 ;
        RECT  71.088 62.448 71.28 62.472 ;
    END
  END i[355]
  PIN i[356]
    DIRECTION INPUT ;
    USE SIGNAL ;
    PORT
      LAYER M4 ;
        RECT  71.088 62.64 71.28 62.664 ;
    END
  END i[356]
  PIN i[357]
    DIRECTION INPUT ;
    USE SIGNAL ;
    PORT
      LAYER M4 ;
        RECT  71.088 62.784 71.28 62.808 ;
    END
  END i[357]
  PIN i[358]
    DIRECTION INPUT ;
    USE SIGNAL ;
    PORT
      LAYER M4 ;
        RECT  71.088 62.976 71.28 63 ;
    END
  END i[358]
  PIN i[359]
    DIRECTION INPUT ;
    USE SIGNAL ;
    PORT
      LAYER M4 ;
        RECT  71.088 63.12 71.28 63.144 ;
    END
  END i[359]
  PIN i[35]
    DIRECTION INPUT ;
    USE SIGNAL ;
    PORT
      LAYER M4 ;
        RECT  71.088 10.128 71.28 10.152 ;
    END
  END i[35]
  PIN i[360]
    DIRECTION INPUT ;
    USE SIGNAL ;
    PORT
      LAYER M4 ;
        RECT  71.088 63.264 71.28 63.288 ;
    END
  END i[360]
  PIN i[361]
    DIRECTION INPUT ;
    USE SIGNAL ;
    PORT
      LAYER M4 ;
        RECT  71.088 63.456 71.28 63.48 ;
    END
  END i[361]
  PIN i[362]
    DIRECTION INPUT ;
    USE SIGNAL ;
    PORT
      LAYER M4 ;
        RECT  71.088 63.6 71.28 63.624 ;
    END
  END i[362]
  PIN i[363]
    DIRECTION INPUT ;
    USE SIGNAL ;
    PORT
      LAYER M4 ;
        RECT  71.088 63.792 71.28 63.816 ;
    END
  END i[363]
  PIN i[364]
    DIRECTION INPUT ;
    USE SIGNAL ;
    PORT
      LAYER M4 ;
        RECT  71.088 63.936 71.28 63.96 ;
    END
  END i[364]
  PIN i[365]
    DIRECTION INPUT ;
    USE SIGNAL ;
    PORT
      LAYER M4 ;
        RECT  71.088 64.08 71.28 64.104 ;
    END
  END i[365]
  PIN i[366]
    DIRECTION INPUT ;
    USE SIGNAL ;
    PORT
      LAYER M4 ;
        RECT  71.088 64.272 71.28 64.296 ;
    END
  END i[366]
  PIN i[367]
    DIRECTION INPUT ;
    USE SIGNAL ;
    PORT
      LAYER M4 ;
        RECT  71.088 64.416 71.28 64.44 ;
    END
  END i[367]
  PIN i[368]
    DIRECTION INPUT ;
    USE SIGNAL ;
    PORT
      LAYER M4 ;
        RECT  71.088 64.608 71.28 64.632 ;
    END
  END i[368]
  PIN i[369]
    DIRECTION INPUT ;
    USE SIGNAL ;
    PORT
      LAYER M4 ;
        RECT  71.088 64.752 71.28 64.776 ;
    END
  END i[369]
  PIN i[36]
    DIRECTION INPUT ;
    USE SIGNAL ;
    PORT
      LAYER M4 ;
        RECT  71.088 10.32 71.28 10.344 ;
    END
  END i[36]
  PIN i[370]
    DIRECTION INPUT ;
    USE SIGNAL ;
    PORT
      LAYER M4 ;
        RECT  71.088 64.896 71.28 64.92 ;
    END
  END i[370]
  PIN i[371]
    DIRECTION INPUT ;
    USE SIGNAL ;
    PORT
      LAYER M4 ;
        RECT  71.088 65.088 71.28 65.112 ;
    END
  END i[371]
  PIN i[372]
    DIRECTION INPUT ;
    USE SIGNAL ;
    PORT
      LAYER M4 ;
        RECT  71.088 65.232 71.28 65.256 ;
    END
  END i[372]
  PIN i[373]
    DIRECTION INPUT ;
    USE SIGNAL ;
    PORT
      LAYER M4 ;
        RECT  71.088 65.424 71.28 65.448 ;
    END
  END i[373]
  PIN i[374]
    DIRECTION INPUT ;
    USE SIGNAL ;
    PORT
      LAYER M4 ;
        RECT  71.088 65.568 71.28 65.592 ;
    END
  END i[374]
  PIN i[375]
    DIRECTION INPUT ;
    USE SIGNAL ;
    PORT
      LAYER M4 ;
        RECT  71.088 65.712 71.28 65.736 ;
    END
  END i[375]
  PIN i[376]
    DIRECTION INPUT ;
    USE SIGNAL ;
    PORT
      LAYER M4 ;
        RECT  71.088 65.904 71.28 65.928 ;
    END
  END i[376]
  PIN i[377]
    DIRECTION INPUT ;
    USE SIGNAL ;
    PORT
      LAYER M4 ;
        RECT  71.088 66.048 71.28 66.072 ;
    END
  END i[377]
  PIN i[378]
    DIRECTION INPUT ;
    USE SIGNAL ;
    PORT
      LAYER M4 ;
        RECT  71.088 66.24 71.28 66.264 ;
    END
  END i[378]
  PIN i[379]
    DIRECTION INPUT ;
    USE SIGNAL ;
    PORT
      LAYER M4 ;
        RECT  71.088 66.384 71.28 66.408 ;
    END
  END i[379]
  PIN i[37]
    DIRECTION INPUT ;
    USE SIGNAL ;
    PORT
      LAYER M4 ;
        RECT  71.088 10.464 71.28 10.488 ;
    END
  END i[37]
  PIN i[380]
    DIRECTION INPUT ;
    USE SIGNAL ;
    PORT
      LAYER M4 ;
        RECT  71.088 66.528 71.28 66.552 ;
    END
  END i[380]
  PIN i[381]
    DIRECTION INPUT ;
    USE SIGNAL ;
    PORT
      LAYER M4 ;
        RECT  71.088 66.72 71.28 66.744 ;
    END
  END i[381]
  PIN i[382]
    DIRECTION INPUT ;
    USE SIGNAL ;
    PORT
      LAYER M4 ;
        RECT  71.088 66.864 71.28 66.888 ;
    END
  END i[382]
  PIN i[383]
    DIRECTION INPUT ;
    USE SIGNAL ;
    PORT
      LAYER M4 ;
        RECT  71.088 67.056 71.28 67.08 ;
    END
  END i[383]
  PIN i[384]
    DIRECTION INPUT ;
    USE SIGNAL ;
    PORT
      LAYER M4 ;
        RECT  71.088 67.2 71.28 67.224 ;
    END
  END i[384]
  PIN i[385]
    DIRECTION INPUT ;
    USE SIGNAL ;
    PORT
      LAYER M4 ;
        RECT  71.088 67.392 71.28 67.416 ;
    END
  END i[385]
  PIN i[386]
    DIRECTION INPUT ;
    USE SIGNAL ;
    PORT
      LAYER M4 ;
        RECT  71.088 67.536 71.28 67.56 ;
    END
  END i[386]
  PIN i[387]
    DIRECTION INPUT ;
    USE SIGNAL ;
    PORT
      LAYER M4 ;
        RECT  71.088 67.68 71.28 67.704 ;
    END
  END i[387]
  PIN i[388]
    DIRECTION INPUT ;
    USE SIGNAL ;
    PORT
      LAYER M4 ;
        RECT  71.088 67.872 71.28 67.896 ;
    END
  END i[388]
  PIN i[389]
    DIRECTION INPUT ;
    USE SIGNAL ;
    PORT
      LAYER M4 ;
        RECT  71.088 68.016 71.28 68.04 ;
    END
  END i[389]
  PIN i[38]
    DIRECTION INPUT ;
    USE SIGNAL ;
    PORT
      LAYER M4 ;
        RECT  71.088 10.608 71.28 10.632 ;
    END
  END i[38]
  PIN i[390]
    DIRECTION INPUT ;
    USE SIGNAL ;
    PORT
      LAYER M4 ;
        RECT  71.088 68.208 71.28 68.232 ;
    END
  END i[390]
  PIN i[391]
    DIRECTION INPUT ;
    USE SIGNAL ;
    PORT
      LAYER M4 ;
        RECT  71.088 68.352 71.28 68.376 ;
    END
  END i[391]
  PIN i[392]
    DIRECTION INPUT ;
    USE SIGNAL ;
    PORT
      LAYER M4 ;
        RECT  71.088 68.496 71.28 68.52 ;
    END
  END i[392]
  PIN i[393]
    DIRECTION INPUT ;
    USE SIGNAL ;
    PORT
      LAYER M4 ;
        RECT  71.088 68.688 71.28 68.712 ;
    END
  END i[393]
  PIN i[394]
    DIRECTION INPUT ;
    USE SIGNAL ;
    PORT
      LAYER M4 ;
        RECT  71.088 68.832 71.28 68.856 ;
    END
  END i[394]
  PIN i[395]
    DIRECTION INPUT ;
    USE SIGNAL ;
    PORT
      LAYER M4 ;
        RECT  71.088 69.024 71.28 69.048 ;
    END
  END i[395]
  PIN i[396]
    DIRECTION INPUT ;
    USE SIGNAL ;
    PORT
      LAYER M4 ;
        RECT  71.088 69.168 71.28 69.192 ;
    END
  END i[396]
  PIN i[397]
    DIRECTION INPUT ;
    USE SIGNAL ;
    PORT
      LAYER M4 ;
        RECT  71.088 69.312 71.28 69.336 ;
    END
  END i[397]
  PIN i[398]
    DIRECTION INPUT ;
    USE SIGNAL ;
    PORT
      LAYER M4 ;
        RECT  71.088 69.504 71.28 69.528 ;
    END
  END i[398]
  PIN i[399]
    DIRECTION INPUT ;
    USE SIGNAL ;
    PORT
      LAYER M4 ;
        RECT  71.088 69.648 71.28 69.672 ;
    END
  END i[399]
  PIN i[39]
    DIRECTION INPUT ;
    USE SIGNAL ;
    PORT
      LAYER M4 ;
        RECT  71.088 10.8 71.28 10.824 ;
    END
  END i[39]
  PIN i[3]
    DIRECTION INPUT ;
    USE SIGNAL ;
    PORT
      LAYER M4 ;
        RECT  71.088 4.896 71.28 4.92 ;
    END
  END i[3]
  PIN i[400]
    DIRECTION INPUT ;
    USE SIGNAL ;
    PORT
      LAYER M4 ;
        RECT  71.088 69.84 71.28 69.864 ;
    END
  END i[400]
  PIN i[401]
    DIRECTION INPUT ;
    USE SIGNAL ;
    PORT
      LAYER M4 ;
        RECT  71.088 69.984 71.28 70.008 ;
    END
  END i[401]
  PIN i[402]
    DIRECTION INPUT ;
    USE SIGNAL ;
    PORT
      LAYER M4 ;
        RECT  71.088 70.128 71.28 70.152 ;
    END
  END i[402]
  PIN i[403]
    DIRECTION INPUT ;
    USE SIGNAL ;
    PORT
      LAYER M4 ;
        RECT  71.088 70.32 71.28 70.344 ;
    END
  END i[403]
  PIN i[404]
    DIRECTION INPUT ;
    USE SIGNAL ;
    PORT
      LAYER M4 ;
        RECT  71.088 70.464 71.28 70.488 ;
    END
  END i[404]
  PIN i[405]
    DIRECTION INPUT ;
    USE SIGNAL ;
    PORT
      LAYER M4 ;
        RECT  71.088 70.656 71.28 70.68 ;
    END
  END i[405]
  PIN i[406]
    DIRECTION INPUT ;
    USE SIGNAL ;
    PORT
      LAYER M4 ;
        RECT  71.088 70.8 71.28 70.824 ;
    END
  END i[406]
  PIN i[407]
    DIRECTION INPUT ;
    USE SIGNAL ;
    PORT
      LAYER M4 ;
        RECT  71.088 70.944 71.28 70.968 ;
    END
  END i[407]
  PIN i[408]
    DIRECTION INPUT ;
    USE SIGNAL ;
    PORT
      LAYER M4 ;
        RECT  71.088 71.136 71.28 71.16 ;
    END
  END i[408]
  PIN i[409]
    DIRECTION INPUT ;
    USE SIGNAL ;
    PORT
      LAYER M4 ;
        RECT  71.088 71.28 71.28 71.304 ;
    END
  END i[409]
  PIN i[40]
    DIRECTION INPUT ;
    USE SIGNAL ;
    PORT
      LAYER M4 ;
        RECT  71.088 10.944 71.28 10.968 ;
    END
  END i[40]
  PIN i[410]
    DIRECTION INPUT ;
    USE SIGNAL ;
    PORT
      LAYER M4 ;
        RECT  71.088 71.472 71.28 71.496 ;
    END
  END i[410]
  PIN i[411]
    DIRECTION INPUT ;
    USE SIGNAL ;
    PORT
      LAYER M4 ;
        RECT  71.088 71.616 71.28 71.64 ;
    END
  END i[411]
  PIN i[412]
    DIRECTION INPUT ;
    USE SIGNAL ;
    PORT
      LAYER M4 ;
        RECT  71.088 71.808 71.28 71.832 ;
    END
  END i[412]
  PIN i[413]
    DIRECTION INPUT ;
    USE SIGNAL ;
    PORT
      LAYER M4 ;
        RECT  71.088 71.952 71.28 71.976 ;
    END
  END i[413]
  PIN i[414]
    DIRECTION INPUT ;
    USE SIGNAL ;
    PORT
      LAYER M4 ;
        RECT  71.088 72.096 71.28 72.12 ;
    END
  END i[414]
  PIN i[415]
    DIRECTION INPUT ;
    USE SIGNAL ;
    PORT
      LAYER M4 ;
        RECT  71.088 72.288 71.28 72.312 ;
    END
  END i[415]
  PIN i[416]
    DIRECTION INPUT ;
    USE SIGNAL ;
    PORT
      LAYER M4 ;
        RECT  71.088 72.432 71.28 72.456 ;
    END
  END i[416]
  PIN i[417]
    DIRECTION INPUT ;
    USE SIGNAL ;
    PORT
      LAYER M4 ;
        RECT  71.088 72.624 71.28 72.648 ;
    END
  END i[417]
  PIN i[418]
    DIRECTION INPUT ;
    USE SIGNAL ;
    PORT
      LAYER M4 ;
        RECT  71.088 72.768 71.28 72.792 ;
    END
  END i[418]
  PIN i[419]
    DIRECTION INPUT ;
    USE SIGNAL ;
    PORT
      LAYER M4 ;
        RECT  71.088 72.912 71.28 72.936 ;
    END
  END i[419]
  PIN i[41]
    DIRECTION INPUT ;
    USE SIGNAL ;
    PORT
      LAYER M4 ;
        RECT  71.088 11.136 71.28 11.16 ;
    END
  END i[41]
  PIN i[420]
    DIRECTION INPUT ;
    USE SIGNAL ;
    PORT
      LAYER M4 ;
        RECT  71.088 73.104 71.28 73.128 ;
    END
  END i[420]
  PIN i[421]
    DIRECTION INPUT ;
    USE SIGNAL ;
    PORT
      LAYER M4 ;
        RECT  71.088 73.248 71.28 73.272 ;
    END
  END i[421]
  PIN i[422]
    DIRECTION INPUT ;
    USE SIGNAL ;
    PORT
      LAYER M4 ;
        RECT  71.088 73.44 71.28 73.464 ;
    END
  END i[422]
  PIN i[423]
    DIRECTION INPUT ;
    USE SIGNAL ;
    PORT
      LAYER M4 ;
        RECT  71.088 73.584 71.28 73.608 ;
    END
  END i[423]
  PIN i[424]
    DIRECTION INPUT ;
    USE SIGNAL ;
    PORT
      LAYER M4 ;
        RECT  71.088 73.728 71.28 73.752 ;
    END
  END i[424]
  PIN i[425]
    DIRECTION INPUT ;
    USE SIGNAL ;
    PORT
      LAYER M4 ;
        RECT  71.088 73.92 71.28 73.944 ;
    END
  END i[425]
  PIN i[426]
    DIRECTION INPUT ;
    USE SIGNAL ;
    PORT
      LAYER M4 ;
        RECT  71.088 74.064 71.28 74.088 ;
    END
  END i[426]
  PIN i[427]
    DIRECTION INPUT ;
    USE SIGNAL ;
    PORT
      LAYER M4 ;
        RECT  71.088 74.256 71.28 74.28 ;
    END
  END i[427]
  PIN i[428]
    DIRECTION INPUT ;
    USE SIGNAL ;
    PORT
      LAYER M4 ;
        RECT  71.088 74.4 71.28 74.424 ;
    END
  END i[428]
  PIN i[429]
    DIRECTION INPUT ;
    USE SIGNAL ;
    PORT
      LAYER M4 ;
        RECT  71.088 74.544 71.28 74.568 ;
    END
  END i[429]
  PIN i[42]
    DIRECTION INPUT ;
    USE SIGNAL ;
    PORT
      LAYER M4 ;
        RECT  71.088 11.28 71.28 11.304 ;
    END
  END i[42]
  PIN i[430]
    DIRECTION INPUT ;
    USE SIGNAL ;
    PORT
      LAYER M4 ;
        RECT  71.088 74.736 71.28 74.76 ;
    END
  END i[430]
  PIN i[431]
    DIRECTION INPUT ;
    USE SIGNAL ;
    PORT
      LAYER M4 ;
        RECT  71.088 74.88 71.28 74.904 ;
    END
  END i[431]
  PIN i[432]
    DIRECTION INPUT ;
    USE SIGNAL ;
    PORT
      LAYER M4 ;
        RECT  71.088 75.072 71.28 75.096 ;
    END
  END i[432]
  PIN i[433]
    DIRECTION INPUT ;
    USE SIGNAL ;
    PORT
      LAYER M4 ;
        RECT  71.088 75.216 71.28 75.24 ;
    END
  END i[433]
  PIN i[434]
    DIRECTION INPUT ;
    USE SIGNAL ;
    PORT
      LAYER M4 ;
        RECT  71.088 75.36 71.28 75.384 ;
    END
  END i[434]
  PIN i[435]
    DIRECTION INPUT ;
    USE SIGNAL ;
    PORT
      LAYER M4 ;
        RECT  71.088 75.552 71.28 75.576 ;
    END
  END i[435]
  PIN i[436]
    DIRECTION INPUT ;
    USE SIGNAL ;
    PORT
      LAYER M4 ;
        RECT  71.088 75.696 71.28 75.72 ;
    END
  END i[436]
  PIN i[437]
    DIRECTION INPUT ;
    USE SIGNAL ;
    PORT
      LAYER M4 ;
        RECT  71.088 75.888 71.28 75.912 ;
    END
  END i[437]
  PIN i[438]
    DIRECTION INPUT ;
    USE SIGNAL ;
    PORT
      LAYER M4 ;
        RECT  71.088 76.032 71.28 76.056 ;
    END
  END i[438]
  PIN i[439]
    DIRECTION INPUT ;
    USE SIGNAL ;
    PORT
      LAYER M4 ;
        RECT  71.088 76.176 71.28 76.2 ;
    END
  END i[439]
  PIN i[43]
    DIRECTION INPUT ;
    USE SIGNAL ;
    PORT
      LAYER M4 ;
        RECT  71.088 11.424 71.28 11.448 ;
    END
  END i[43]
  PIN i[440]
    DIRECTION INPUT ;
    USE SIGNAL ;
    PORT
      LAYER M4 ;
        RECT  71.088 76.368 71.28 76.392 ;
    END
  END i[440]
  PIN i[441]
    DIRECTION INPUT ;
    USE SIGNAL ;
    PORT
      LAYER M4 ;
        RECT  71.088 76.512 71.28 76.536 ;
    END
  END i[441]
  PIN i[442]
    DIRECTION INPUT ;
    USE SIGNAL ;
    PORT
      LAYER M4 ;
        RECT  71.088 76.704 71.28 76.728 ;
    END
  END i[442]
  PIN i[443]
    DIRECTION INPUT ;
    USE SIGNAL ;
    PORT
      LAYER M4 ;
        RECT  71.088 76.848 71.28 76.872 ;
    END
  END i[443]
  PIN i[444]
    DIRECTION INPUT ;
    USE SIGNAL ;
    PORT
      LAYER M4 ;
        RECT  71.088 77.04 71.28 77.064 ;
    END
  END i[444]
  PIN i[445]
    DIRECTION INPUT ;
    USE SIGNAL ;
    PORT
      LAYER M4 ;
        RECT  71.088 77.184 71.28 77.208 ;
    END
  END i[445]
  PIN i[446]
    DIRECTION INPUT ;
    USE SIGNAL ;
    PORT
      LAYER M4 ;
        RECT  71.088 77.328 71.28 77.352 ;
    END
  END i[446]
  PIN i[447]
    DIRECTION INPUT ;
    USE SIGNAL ;
    PORT
      LAYER M4 ;
        RECT  71.088 77.52 71.28 77.544 ;
    END
  END i[447]
  PIN i[448]
    DIRECTION INPUT ;
    USE SIGNAL ;
    PORT
      LAYER M4 ;
        RECT  71.088 77.664 71.28 77.688 ;
    END
  END i[448]
  PIN i[449]
    DIRECTION INPUT ;
    USE SIGNAL ;
    PORT
      LAYER M4 ;
        RECT  71.088 77.856 71.28 77.88 ;
    END
  END i[449]
  PIN i[44]
    DIRECTION INPUT ;
    USE SIGNAL ;
    PORT
      LAYER M4 ;
        RECT  71.088 11.616 71.28 11.64 ;
    END
  END i[44]
  PIN i[450]
    DIRECTION INPUT ;
    USE SIGNAL ;
    PORT
      LAYER M4 ;
        RECT  71.088 78 71.28 78.024 ;
    END
  END i[450]
  PIN i[451]
    DIRECTION INPUT ;
    USE SIGNAL ;
    PORT
      LAYER M4 ;
        RECT  71.088 78.144 71.28 78.168 ;
    END
  END i[451]
  PIN i[452]
    DIRECTION INPUT ;
    USE SIGNAL ;
    PORT
      LAYER M4 ;
        RECT  71.088 78.336 71.28 78.36 ;
    END
  END i[452]
  PIN i[453]
    DIRECTION INPUT ;
    USE SIGNAL ;
    PORT
      LAYER M4 ;
        RECT  71.088 78.48 71.28 78.504 ;
    END
  END i[453]
  PIN i[454]
    DIRECTION INPUT ;
    USE SIGNAL ;
    PORT
      LAYER M4 ;
        RECT  71.088 78.672 71.28 78.696 ;
    END
  END i[454]
  PIN i[455]
    DIRECTION INPUT ;
    USE SIGNAL ;
    PORT
      LAYER M4 ;
        RECT  71.088 78.816 71.28 78.84 ;
    END
  END i[455]
  PIN i[456]
    DIRECTION INPUT ;
    USE SIGNAL ;
    PORT
      LAYER M4 ;
        RECT  71.088 78.96 71.28 78.984 ;
    END
  END i[456]
  PIN i[457]
    DIRECTION INPUT ;
    USE SIGNAL ;
    PORT
      LAYER M4 ;
        RECT  71.088 79.152 71.28 79.176 ;
    END
  END i[457]
  PIN i[458]
    DIRECTION INPUT ;
    USE SIGNAL ;
    PORT
      LAYER M4 ;
        RECT  71.088 79.296 71.28 79.32 ;
    END
  END i[458]
  PIN i[459]
    DIRECTION INPUT ;
    USE SIGNAL ;
    PORT
      LAYER M4 ;
        RECT  71.088 79.488 71.28 79.512 ;
    END
  END i[459]
  PIN i[45]
    DIRECTION INPUT ;
    USE SIGNAL ;
    PORT
      LAYER M4 ;
        RECT  71.088 11.76 71.28 11.784 ;
    END
  END i[45]
  PIN i[460]
    DIRECTION INPUT ;
    USE SIGNAL ;
    PORT
      LAYER M4 ;
        RECT  71.088 79.632 71.28 79.656 ;
    END
  END i[460]
  PIN i[461]
    DIRECTION INPUT ;
    USE SIGNAL ;
    PORT
      LAYER M4 ;
        RECT  71.088 79.776 71.28 79.8 ;
    END
  END i[461]
  PIN i[462]
    DIRECTION INPUT ;
    USE SIGNAL ;
    PORT
      LAYER M4 ;
        RECT  71.088 79.968 71.28 79.992 ;
    END
  END i[462]
  PIN i[463]
    DIRECTION INPUT ;
    USE SIGNAL ;
    PORT
      LAYER M4 ;
        RECT  71.088 80.112 71.28 80.136 ;
    END
  END i[463]
  PIN i[464]
    DIRECTION INPUT ;
    USE SIGNAL ;
    PORT
      LAYER M4 ;
        RECT  71.088 80.304 71.28 80.328 ;
    END
  END i[464]
  PIN i[465]
    DIRECTION INPUT ;
    USE SIGNAL ;
    PORT
      LAYER M4 ;
        RECT  71.088 80.448 71.28 80.472 ;
    END
  END i[465]
  PIN i[466]
    DIRECTION INPUT ;
    USE SIGNAL ;
    PORT
      LAYER M4 ;
        RECT  71.088 80.592 71.28 80.616 ;
    END
  END i[466]
  PIN i[467]
    DIRECTION INPUT ;
    USE SIGNAL ;
    PORT
      LAYER M4 ;
        RECT  71.088 80.784 71.28 80.808 ;
    END
  END i[467]
  PIN i[468]
    DIRECTION INPUT ;
    USE SIGNAL ;
    PORT
      LAYER M4 ;
        RECT  71.088 80.928 71.28 80.952 ;
    END
  END i[468]
  PIN i[469]
    DIRECTION INPUT ;
    USE SIGNAL ;
    PORT
      LAYER M4 ;
        RECT  71.088 81.12 71.28 81.144 ;
    END
  END i[469]
  PIN i[46]
    DIRECTION INPUT ;
    USE SIGNAL ;
    PORT
      LAYER M4 ;
        RECT  71.088 11.952 71.28 11.976 ;
    END
  END i[46]
  PIN i[470]
    DIRECTION INPUT ;
    USE SIGNAL ;
    PORT
      LAYER M4 ;
        RECT  71.088 81.264 71.28 81.288 ;
    END
  END i[470]
  PIN i[471]
    DIRECTION INPUT ;
    USE SIGNAL ;
    PORT
      LAYER M4 ;
        RECT  71.088 81.456 71.28 81.48 ;
    END
  END i[471]
  PIN i[472]
    DIRECTION INPUT ;
    USE SIGNAL ;
    PORT
      LAYER M4 ;
        RECT  71.088 81.6 71.28 81.624 ;
    END
  END i[472]
  PIN i[473]
    DIRECTION INPUT ;
    USE SIGNAL ;
    PORT
      LAYER M4 ;
        RECT  71.088 81.744 71.28 81.768 ;
    END
  END i[473]
  PIN i[474]
    DIRECTION INPUT ;
    USE SIGNAL ;
    PORT
      LAYER M4 ;
        RECT  71.088 81.936 71.28 81.96 ;
    END
  END i[474]
  PIN i[475]
    DIRECTION INPUT ;
    USE SIGNAL ;
    PORT
      LAYER M4 ;
        RECT  71.088 82.08 71.28 82.104 ;
    END
  END i[475]
  PIN i[476]
    DIRECTION INPUT ;
    USE SIGNAL ;
    PORT
      LAYER M4 ;
        RECT  71.088 82.272 71.28 82.296 ;
    END
  END i[476]
  PIN i[477]
    DIRECTION INPUT ;
    USE SIGNAL ;
    PORT
      LAYER M4 ;
        RECT  71.088 82.416 71.28 82.44 ;
    END
  END i[477]
  PIN i[478]
    DIRECTION INPUT ;
    USE SIGNAL ;
    PORT
      LAYER M4 ;
        RECT  71.088 82.56 71.28 82.584 ;
    END
  END i[478]
  PIN i[479]
    DIRECTION INPUT ;
    USE SIGNAL ;
    PORT
      LAYER M4 ;
        RECT  71.088 82.752 71.28 82.776 ;
    END
  END i[479]
  PIN i[47]
    DIRECTION INPUT ;
    USE SIGNAL ;
    PORT
      LAYER M4 ;
        RECT  71.088 12.096 71.28 12.12 ;
    END
  END i[47]
  PIN i[480]
    DIRECTION INPUT ;
    USE SIGNAL ;
    PORT
      LAYER M4 ;
        RECT  71.088 82.896 71.28 82.92 ;
    END
  END i[480]
  PIN i[481]
    DIRECTION INPUT ;
    USE SIGNAL ;
    PORT
      LAYER M4 ;
        RECT  71.088 83.088 71.28 83.112 ;
    END
  END i[481]
  PIN i[482]
    DIRECTION INPUT ;
    USE SIGNAL ;
    PORT
      LAYER M4 ;
        RECT  71.088 83.232 71.28 83.256 ;
    END
  END i[482]
  PIN i[483]
    DIRECTION INPUT ;
    USE SIGNAL ;
    PORT
      LAYER M4 ;
        RECT  71.088 83.376 71.28 83.4 ;
    END
  END i[483]
  PIN i[484]
    DIRECTION INPUT ;
    USE SIGNAL ;
    PORT
      LAYER M4 ;
        RECT  71.088 83.568 71.28 83.592 ;
    END
  END i[484]
  PIN i[485]
    DIRECTION INPUT ;
    USE SIGNAL ;
    PORT
      LAYER M4 ;
        RECT  71.088 83.712 71.28 83.736 ;
    END
  END i[485]
  PIN i[486]
    DIRECTION INPUT ;
    USE SIGNAL ;
    PORT
      LAYER M4 ;
        RECT  71.088 83.904 71.28 83.928 ;
    END
  END i[486]
  PIN i[487]
    DIRECTION INPUT ;
    USE SIGNAL ;
    PORT
      LAYER M4 ;
        RECT  71.088 84.048 71.28 84.072 ;
    END
  END i[487]
  PIN i[488]
    DIRECTION INPUT ;
    USE SIGNAL ;
    PORT
      LAYER M4 ;
        RECT  71.088 84.192 71.28 84.216 ;
    END
  END i[488]
  PIN i[489]
    DIRECTION INPUT ;
    USE SIGNAL ;
    PORT
      LAYER M4 ;
        RECT  71.088 84.384 71.28 84.408 ;
    END
  END i[489]
  PIN i[48]
    DIRECTION INPUT ;
    USE SIGNAL ;
    PORT
      LAYER M4 ;
        RECT  71.088 12.24 71.28 12.264 ;
    END
  END i[48]
  PIN i[490]
    DIRECTION INPUT ;
    USE SIGNAL ;
    PORT
      LAYER M4 ;
        RECT  71.088 84.528 71.28 84.552 ;
    END
  END i[490]
  PIN i[491]
    DIRECTION INPUT ;
    USE SIGNAL ;
    PORT
      LAYER M4 ;
        RECT  71.088 84.72 71.28 84.744 ;
    END
  END i[491]
  PIN i[492]
    DIRECTION INPUT ;
    USE SIGNAL ;
    PORT
      LAYER M4 ;
        RECT  71.088 84.864 71.28 84.888 ;
    END
  END i[492]
  PIN i[493]
    DIRECTION INPUT ;
    USE SIGNAL ;
    PORT
      LAYER M4 ;
        RECT  71.088 85.008 71.28 85.032 ;
    END
  END i[493]
  PIN i[494]
    DIRECTION INPUT ;
    USE SIGNAL ;
    PORT
      LAYER M4 ;
        RECT  71.088 85.2 71.28 85.224 ;
    END
  END i[494]
  PIN i[495]
    DIRECTION INPUT ;
    USE SIGNAL ;
    PORT
      LAYER M4 ;
        RECT  71.088 85.344 71.28 85.368 ;
    END
  END i[495]
  PIN i[496]
    DIRECTION INPUT ;
    USE SIGNAL ;
    PORT
      LAYER M4 ;
        RECT  71.088 85.536 71.28 85.56 ;
    END
  END i[496]
  PIN i[497]
    DIRECTION INPUT ;
    USE SIGNAL ;
    PORT
      LAYER M4 ;
        RECT  71.088 85.68 71.28 85.704 ;
    END
  END i[497]
  PIN i[498]
    DIRECTION INPUT ;
    USE SIGNAL ;
    PORT
      LAYER M4 ;
        RECT  71.088 85.824 71.28 85.848 ;
    END
  END i[498]
  PIN i[499]
    DIRECTION INPUT ;
    USE SIGNAL ;
    PORT
      LAYER M4 ;
        RECT  71.088 86.016 71.28 86.04 ;
    END
  END i[499]
  PIN i[49]
    DIRECTION INPUT ;
    USE SIGNAL ;
    PORT
      LAYER M4 ;
        RECT  71.088 12.432 71.28 12.456 ;
    END
  END i[49]
  PIN i[4]
    DIRECTION INPUT ;
    USE SIGNAL ;
    PORT
      LAYER M4 ;
        RECT  71.088 5.088 71.28 5.112 ;
    END
  END i[4]
  PIN i[500]
    DIRECTION INPUT ;
    USE SIGNAL ;
    PORT
      LAYER M4 ;
        RECT  71.088 86.16 71.28 86.184 ;
    END
  END i[500]
  PIN i[501]
    DIRECTION INPUT ;
    USE SIGNAL ;
    PORT
      LAYER M4 ;
        RECT  71.088 86.352 71.28 86.376 ;
    END
  END i[501]
  PIN i[502]
    DIRECTION INPUT ;
    USE SIGNAL ;
    PORT
      LAYER M4 ;
        RECT  71.088 86.496 71.28 86.52 ;
    END
  END i[502]
  PIN i[503]
    DIRECTION INPUT ;
    USE SIGNAL ;
    PORT
      LAYER M4 ;
        RECT  71.088 86.688 71.28 86.712 ;
    END
  END i[503]
  PIN i[504]
    DIRECTION INPUT ;
    USE SIGNAL ;
    PORT
      LAYER M4 ;
        RECT  71.088 86.832 71.28 86.856 ;
    END
  END i[504]
  PIN i[505]
    DIRECTION INPUT ;
    USE SIGNAL ;
    PORT
      LAYER M4 ;
        RECT  71.088 86.976 71.28 87 ;
    END
  END i[505]
  PIN i[506]
    DIRECTION INPUT ;
    USE SIGNAL ;
    PORT
      LAYER M4 ;
        RECT  71.088 87.168 71.28 87.192 ;
    END
  END i[506]
  PIN i[507]
    DIRECTION INPUT ;
    USE SIGNAL ;
    PORT
      LAYER M4 ;
        RECT  71.088 87.312 71.28 87.336 ;
    END
  END i[507]
  PIN i[508]
    DIRECTION INPUT ;
    USE SIGNAL ;
    PORT
      LAYER M4 ;
        RECT  71.088 87.504 71.28 87.528 ;
    END
  END i[508]
  PIN i[509]
    DIRECTION INPUT ;
    USE SIGNAL ;
    PORT
      LAYER M4 ;
        RECT  71.088 87.648 71.28 87.672 ;
    END
  END i[509]
  PIN i[50]
    DIRECTION INPUT ;
    USE SIGNAL ;
    PORT
      LAYER M4 ;
        RECT  71.088 12.576 71.28 12.6 ;
    END
  END i[50]
  PIN i[510]
    DIRECTION INPUT ;
    USE SIGNAL ;
    PORT
      LAYER M4 ;
        RECT  71.088 87.792 71.28 87.816 ;
    END
  END i[510]
  PIN i[511]
    DIRECTION INPUT ;
    USE SIGNAL ;
    PORT
      LAYER M4 ;
        RECT  71.088 87.984 71.28 88.008 ;
    END
  END i[511]
  PIN i[512]
    DIRECTION INPUT ;
    USE SIGNAL ;
    PORT
      LAYER M4 ;
        RECT  71.088 88.128 71.28 88.152 ;
    END
  END i[512]
  PIN i[513]
    DIRECTION INPUT ;
    USE SIGNAL ;
    PORT
      LAYER M4 ;
        RECT  71.088 88.32 71.28 88.344 ;
    END
  END i[513]
  PIN i[514]
    DIRECTION INPUT ;
    USE SIGNAL ;
    PORT
      LAYER M4 ;
        RECT  71.088 88.464 71.28 88.488 ;
    END
  END i[514]
  PIN i[515]
    DIRECTION INPUT ;
    USE SIGNAL ;
    PORT
      LAYER M4 ;
        RECT  71.088 88.608 71.28 88.632 ;
    END
  END i[515]
  PIN i[516]
    DIRECTION INPUT ;
    USE SIGNAL ;
    PORT
      LAYER M4 ;
        RECT  71.088 88.8 71.28 88.824 ;
    END
  END i[516]
  PIN i[517]
    DIRECTION INPUT ;
    USE SIGNAL ;
    PORT
      LAYER M4 ;
        RECT  71.088 88.944 71.28 88.968 ;
    END
  END i[517]
  PIN i[518]
    DIRECTION INPUT ;
    USE SIGNAL ;
    PORT
      LAYER M4 ;
        RECT  71.088 89.136 71.28 89.16 ;
    END
  END i[518]
  PIN i[519]
    DIRECTION INPUT ;
    USE SIGNAL ;
    PORT
      LAYER M4 ;
        RECT  71.088 89.28 71.28 89.304 ;
    END
  END i[519]
  PIN i[51]
    DIRECTION INPUT ;
    USE SIGNAL ;
    PORT
      LAYER M4 ;
        RECT  71.088 12.768 71.28 12.792 ;
    END
  END i[51]
  PIN i[520]
    DIRECTION INPUT ;
    USE SIGNAL ;
    PORT
      LAYER M4 ;
        RECT  71.088 89.424 71.28 89.448 ;
    END
  END i[520]
  PIN i[521]
    DIRECTION INPUT ;
    USE SIGNAL ;
    PORT
      LAYER M4 ;
        RECT  71.088 89.616 71.28 89.64 ;
    END
  END i[521]
  PIN i[522]
    DIRECTION INPUT ;
    USE SIGNAL ;
    PORT
      LAYER M4 ;
        RECT  71.088 89.76 71.28 89.784 ;
    END
  END i[522]
  PIN i[523]
    DIRECTION INPUT ;
    USE SIGNAL ;
    PORT
      LAYER M4 ;
        RECT  71.088 89.952 71.28 89.976 ;
    END
  END i[523]
  PIN i[524]
    DIRECTION INPUT ;
    USE SIGNAL ;
    PORT
      LAYER M4 ;
        RECT  71.088 90.096 71.28 90.12 ;
    END
  END i[524]
  PIN i[525]
    DIRECTION INPUT ;
    USE SIGNAL ;
    PORT
      LAYER M4 ;
        RECT  71.088 90.24 71.28 90.264 ;
    END
  END i[525]
  PIN i[526]
    DIRECTION INPUT ;
    USE SIGNAL ;
    PORT
      LAYER M4 ;
        RECT  71.088 90.432 71.28 90.456 ;
    END
  END i[526]
  PIN i[527]
    DIRECTION INPUT ;
    USE SIGNAL ;
    PORT
      LAYER M4 ;
        RECT  71.088 90.576 71.28 90.6 ;
    END
  END i[527]
  PIN i[528]
    DIRECTION INPUT ;
    USE SIGNAL ;
    PORT
      LAYER M4 ;
        RECT  71.088 90.768 71.28 90.792 ;
    END
  END i[528]
  PIN i[529]
    DIRECTION INPUT ;
    USE SIGNAL ;
    PORT
      LAYER M4 ;
        RECT  71.088 90.912 71.28 90.936 ;
    END
  END i[529]
  PIN i[52]
    DIRECTION INPUT ;
    USE SIGNAL ;
    PORT
      LAYER M4 ;
        RECT  71.088 12.912 71.28 12.936 ;
    END
  END i[52]
  PIN i[530]
    DIRECTION INPUT ;
    USE SIGNAL ;
    PORT
      LAYER M4 ;
        RECT  71.088 91.056 71.28 91.08 ;
    END
  END i[530]
  PIN i[531]
    DIRECTION INPUT ;
    USE SIGNAL ;
    PORT
      LAYER M4 ;
        RECT  71.088 91.248 71.28 91.272 ;
    END
  END i[531]
  PIN i[532]
    DIRECTION INPUT ;
    USE SIGNAL ;
    PORT
      LAYER M4 ;
        RECT  71.088 91.392 71.28 91.416 ;
    END
  END i[532]
  PIN i[533]
    DIRECTION INPUT ;
    USE SIGNAL ;
    PORT
      LAYER M4 ;
        RECT  71.088 91.584 71.28 91.608 ;
    END
  END i[533]
  PIN i[534]
    DIRECTION INPUT ;
    USE SIGNAL ;
    PORT
      LAYER M4 ;
        RECT  71.088 91.728 71.28 91.752 ;
    END
  END i[534]
  PIN i[535]
    DIRECTION INPUT ;
    USE SIGNAL ;
    PORT
      LAYER M4 ;
        RECT  71.088 91.92 71.28 91.944 ;
    END
  END i[535]
  PIN i[536]
    DIRECTION INPUT ;
    USE SIGNAL ;
    PORT
      LAYER M4 ;
        RECT  71.088 92.064 71.28 92.088 ;
    END
  END i[536]
  PIN i[537]
    DIRECTION INPUT ;
    USE SIGNAL ;
    PORT
      LAYER M4 ;
        RECT  71.088 92.208 71.28 92.232 ;
    END
  END i[537]
  PIN i[538]
    DIRECTION INPUT ;
    USE SIGNAL ;
    PORT
      LAYER M4 ;
        RECT  71.088 92.4 71.28 92.424 ;
    END
  END i[538]
  PIN i[539]
    DIRECTION INPUT ;
    USE SIGNAL ;
    PORT
      LAYER M4 ;
        RECT  71.088 92.544 71.28 92.568 ;
    END
  END i[539]
  PIN i[53]
    DIRECTION INPUT ;
    USE SIGNAL ;
    PORT
      LAYER M4 ;
        RECT  71.088 13.104 71.28 13.128 ;
    END
  END i[53]
  PIN i[540]
    DIRECTION INPUT ;
    USE SIGNAL ;
    PORT
      LAYER M4 ;
        RECT  71.088 92.736 71.28 92.76 ;
    END
  END i[540]
  PIN i[541]
    DIRECTION INPUT ;
    USE SIGNAL ;
    PORT
      LAYER M4 ;
        RECT  71.088 92.88 71.28 92.904 ;
    END
  END i[541]
  PIN i[542]
    DIRECTION INPUT ;
    USE SIGNAL ;
    PORT
      LAYER M4 ;
        RECT  71.088 93.024 71.28 93.048 ;
    END
  END i[542]
  PIN i[543]
    DIRECTION INPUT ;
    USE SIGNAL ;
    PORT
      LAYER M4 ;
        RECT  71.088 93.216 71.28 93.24 ;
    END
  END i[543]
  PIN i[544]
    DIRECTION INPUT ;
    USE SIGNAL ;
    PORT
      LAYER M4 ;
        RECT  71.088 93.36 71.28 93.384 ;
    END
  END i[544]
  PIN i[545]
    DIRECTION INPUT ;
    USE SIGNAL ;
    PORT
      LAYER M4 ;
        RECT  71.088 93.552 71.28 93.576 ;
    END
  END i[545]
  PIN i[546]
    DIRECTION INPUT ;
    USE SIGNAL ;
    PORT
      LAYER M4 ;
        RECT  71.088 93.696 71.28 93.72 ;
    END
  END i[546]
  PIN i[547]
    DIRECTION INPUT ;
    USE SIGNAL ;
    PORT
      LAYER M4 ;
        RECT  71.088 93.84 71.28 93.864 ;
    END
  END i[547]
  PIN i[548]
    DIRECTION INPUT ;
    USE SIGNAL ;
    PORT
      LAYER M4 ;
        RECT  71.088 94.032 71.28 94.056 ;
    END
  END i[548]
  PIN i[549]
    DIRECTION INPUT ;
    USE SIGNAL ;
    PORT
      LAYER M4 ;
        RECT  71.088 94.176 71.28 94.2 ;
    END
  END i[549]
  PIN i[54]
    DIRECTION INPUT ;
    USE SIGNAL ;
    PORT
      LAYER M4 ;
        RECT  71.088 13.248 71.28 13.272 ;
    END
  END i[54]
  PIN i[550]
    DIRECTION INPUT ;
    USE SIGNAL ;
    PORT
      LAYER M4 ;
        RECT  71.088 94.368 71.28 94.392 ;
    END
  END i[550]
  PIN i[551]
    DIRECTION INPUT ;
    USE SIGNAL ;
    PORT
      LAYER M4 ;
        RECT  71.088 94.512 71.28 94.536 ;
    END
  END i[551]
  PIN i[552]
    DIRECTION INPUT ;
    USE SIGNAL ;
    PORT
      LAYER M4 ;
        RECT  71.088 94.656 71.28 94.68 ;
    END
  END i[552]
  PIN i[553]
    DIRECTION INPUT ;
    USE SIGNAL ;
    PORT
      LAYER M4 ;
        RECT  71.088 94.848 71.28 94.872 ;
    END
  END i[553]
  PIN i[554]
    DIRECTION INPUT ;
    USE SIGNAL ;
    PORT
      LAYER M4 ;
        RECT  71.088 94.992 71.28 95.016 ;
    END
  END i[554]
  PIN i[555]
    DIRECTION INPUT ;
    USE SIGNAL ;
    PORT
      LAYER M4 ;
        RECT  71.088 95.184 71.28 95.208 ;
    END
  END i[555]
  PIN i[556]
    DIRECTION INPUT ;
    USE SIGNAL ;
    PORT
      LAYER M4 ;
        RECT  71.088 95.328 71.28 95.352 ;
    END
  END i[556]
  PIN i[557]
    DIRECTION INPUT ;
    USE SIGNAL ;
    PORT
      LAYER M4 ;
        RECT  71.088 95.472 71.28 95.496 ;
    END
  END i[557]
  PIN i[558]
    DIRECTION INPUT ;
    USE SIGNAL ;
    PORT
      LAYER M4 ;
        RECT  71.088 95.664 71.28 95.688 ;
    END
  END i[558]
  PIN i[559]
    DIRECTION INPUT ;
    USE SIGNAL ;
    PORT
      LAYER M4 ;
        RECT  71.088 95.808 71.28 95.832 ;
    END
  END i[559]
  PIN i[55]
    DIRECTION INPUT ;
    USE SIGNAL ;
    PORT
      LAYER M4 ;
        RECT  71.088 13.392 71.28 13.416 ;
    END
  END i[55]
  PIN i[560]
    DIRECTION INPUT ;
    USE SIGNAL ;
    PORT
      LAYER M4 ;
        RECT  71.088 96 71.28 96.024 ;
    END
  END i[560]
  PIN i[561]
    DIRECTION INPUT ;
    USE SIGNAL ;
    PORT
      LAYER M4 ;
        RECT  71.088 96.144 71.28 96.168 ;
    END
  END i[561]
  PIN i[562]
    DIRECTION INPUT ;
    USE SIGNAL ;
    PORT
      LAYER M4 ;
        RECT  71.088 96.336 71.28 96.36 ;
    END
  END i[562]
  PIN i[563]
    DIRECTION INPUT ;
    USE SIGNAL ;
    PORT
      LAYER M4 ;
        RECT  71.088 96.48 71.28 96.504 ;
    END
  END i[563]
  PIN i[564]
    DIRECTION INPUT ;
    USE SIGNAL ;
    PORT
      LAYER M4 ;
        RECT  71.088 96.624 71.28 96.648 ;
    END
  END i[564]
  PIN i[56]
    DIRECTION INPUT ;
    USE SIGNAL ;
    PORT
      LAYER M4 ;
        RECT  71.088 13.584 71.28 13.608 ;
    END
  END i[56]
  PIN i[57]
    DIRECTION INPUT ;
    USE SIGNAL ;
    PORT
      LAYER M4 ;
        RECT  71.088 13.728 71.28 13.752 ;
    END
  END i[57]
  PIN i[58]
    DIRECTION INPUT ;
    USE SIGNAL ;
    PORT
      LAYER M4 ;
        RECT  71.088 13.92 71.28 13.944 ;
    END
  END i[58]
  PIN i[59]
    DIRECTION INPUT ;
    USE SIGNAL ;
    PORT
      LAYER M4 ;
        RECT  71.088 14.064 71.28 14.088 ;
    END
  END i[59]
  PIN i[5]
    DIRECTION INPUT ;
    USE SIGNAL ;
    PORT
      LAYER M4 ;
        RECT  71.088 5.232 71.28 5.256 ;
    END
  END i[5]
  PIN i[60]
    DIRECTION INPUT ;
    USE SIGNAL ;
    PORT
      LAYER M4 ;
        RECT  71.088 14.208 71.28 14.232 ;
    END
  END i[60]
  PIN i[61]
    DIRECTION INPUT ;
    USE SIGNAL ;
    PORT
      LAYER M4 ;
        RECT  71.088 14.4 71.28 14.424 ;
    END
  END i[61]
  PIN i[62]
    DIRECTION INPUT ;
    USE SIGNAL ;
    PORT
      LAYER M4 ;
        RECT  71.088 14.544 71.28 14.568 ;
    END
  END i[62]
  PIN i[63]
    DIRECTION INPUT ;
    USE SIGNAL ;
    PORT
      LAYER M4 ;
        RECT  71.088 14.736 71.28 14.76 ;
    END
  END i[63]
  PIN i[64]
    DIRECTION INPUT ;
    USE SIGNAL ;
    PORT
      LAYER M4 ;
        RECT  71.088 14.88 71.28 14.904 ;
    END
  END i[64]
  PIN i[65]
    DIRECTION INPUT ;
    USE SIGNAL ;
    PORT
      LAYER M4 ;
        RECT  71.088 15.024 71.28 15.048 ;
    END
  END i[65]
  PIN i[66]
    DIRECTION INPUT ;
    USE SIGNAL ;
    PORT
      LAYER M4 ;
        RECT  71.088 15.216 71.28 15.24 ;
    END
  END i[66]
  PIN i[67]
    DIRECTION INPUT ;
    USE SIGNAL ;
    PORT
      LAYER M4 ;
        RECT  71.088 15.36 71.28 15.384 ;
    END
  END i[67]
  PIN i[68]
    DIRECTION INPUT ;
    USE SIGNAL ;
    PORT
      LAYER M4 ;
        RECT  71.088 15.552 71.28 15.576 ;
    END
  END i[68]
  PIN i[69]
    DIRECTION INPUT ;
    USE SIGNAL ;
    PORT
      LAYER M4 ;
        RECT  71.088 15.696 71.28 15.72 ;
    END
  END i[69]
  PIN i[6]
    DIRECTION INPUT ;
    USE SIGNAL ;
    PORT
      LAYER M4 ;
        RECT  71.088 5.376 71.28 5.4 ;
    END
  END i[6]
  PIN i[70]
    DIRECTION INPUT ;
    USE SIGNAL ;
    PORT
      LAYER M4 ;
        RECT  71.088 15.84 71.28 15.864 ;
    END
  END i[70]
  PIN i[71]
    DIRECTION INPUT ;
    USE SIGNAL ;
    PORT
      LAYER M4 ;
        RECT  71.088 16.032 71.28 16.056 ;
    END
  END i[71]
  PIN i[72]
    DIRECTION INPUT ;
    USE SIGNAL ;
    PORT
      LAYER M4 ;
        RECT  71.088 16.176 71.28 16.2 ;
    END
  END i[72]
  PIN i[73]
    DIRECTION INPUT ;
    USE SIGNAL ;
    PORT
      LAYER M4 ;
        RECT  71.088 16.368 71.28 16.392 ;
    END
  END i[73]
  PIN i[74]
    DIRECTION INPUT ;
    USE SIGNAL ;
    PORT
      LAYER M4 ;
        RECT  71.088 16.512 71.28 16.536 ;
    END
  END i[74]
  PIN i[75]
    DIRECTION INPUT ;
    USE SIGNAL ;
    PORT
      LAYER M4 ;
        RECT  71.088 16.656 71.28 16.68 ;
    END
  END i[75]
  PIN i[76]
    DIRECTION INPUT ;
    USE SIGNAL ;
    PORT
      LAYER M4 ;
        RECT  71.088 16.848 71.28 16.872 ;
    END
  END i[76]
  PIN i[77]
    DIRECTION INPUT ;
    USE SIGNAL ;
    PORT
      LAYER M4 ;
        RECT  71.088 16.992 71.28 17.016 ;
    END
  END i[77]
  PIN i[78]
    DIRECTION INPUT ;
    USE SIGNAL ;
    PORT
      LAYER M4 ;
        RECT  71.088 17.184 71.28 17.208 ;
    END
  END i[78]
  PIN i[79]
    DIRECTION INPUT ;
    USE SIGNAL ;
    PORT
      LAYER M4 ;
        RECT  71.088 17.328 71.28 17.352 ;
    END
  END i[79]
  PIN i[7]
    DIRECTION INPUT ;
    USE SIGNAL ;
    PORT
      LAYER M4 ;
        RECT  71.088 5.568 71.28 5.592 ;
    END
  END i[7]
  PIN i[80]
    DIRECTION INPUT ;
    USE SIGNAL ;
    PORT
      LAYER M4 ;
        RECT  71.088 17.472 71.28 17.496 ;
    END
  END i[80]
  PIN i[81]
    DIRECTION INPUT ;
    USE SIGNAL ;
    PORT
      LAYER M4 ;
        RECT  71.088 17.664 71.28 17.688 ;
    END
  END i[81]
  PIN i[82]
    DIRECTION INPUT ;
    USE SIGNAL ;
    PORT
      LAYER M4 ;
        RECT  71.088 17.808 71.28 17.832 ;
    END
  END i[82]
  PIN i[83]
    DIRECTION INPUT ;
    USE SIGNAL ;
    PORT
      LAYER M4 ;
        RECT  71.088 18 71.28 18.024 ;
    END
  END i[83]
  PIN i[84]
    DIRECTION INPUT ;
    USE SIGNAL ;
    PORT
      LAYER M4 ;
        RECT  71.088 18.144 71.28 18.168 ;
    END
  END i[84]
  PIN i[85]
    DIRECTION INPUT ;
    USE SIGNAL ;
    PORT
      LAYER M4 ;
        RECT  71.088 18.336 71.28 18.36 ;
    END
  END i[85]
  PIN i[86]
    DIRECTION INPUT ;
    USE SIGNAL ;
    PORT
      LAYER M4 ;
        RECT  71.088 18.48 71.28 18.504 ;
    END
  END i[86]
  PIN i[87]
    DIRECTION INPUT ;
    USE SIGNAL ;
    PORT
      LAYER M4 ;
        RECT  71.088 18.624 71.28 18.648 ;
    END
  END i[87]
  PIN i[88]
    DIRECTION INPUT ;
    USE SIGNAL ;
    PORT
      LAYER M4 ;
        RECT  71.088 18.816 71.28 18.84 ;
    END
  END i[88]
  PIN i[89]
    DIRECTION INPUT ;
    USE SIGNAL ;
    PORT
      LAYER M4 ;
        RECT  71.088 18.96 71.28 18.984 ;
    END
  END i[89]
  PIN i[8]
    DIRECTION INPUT ;
    USE SIGNAL ;
    PORT
      LAYER M4 ;
        RECT  71.088 5.712 71.28 5.736 ;
    END
  END i[8]
  PIN i[90]
    DIRECTION INPUT ;
    USE SIGNAL ;
    PORT
      LAYER M4 ;
        RECT  71.088 19.152 71.28 19.176 ;
    END
  END i[90]
  PIN i[91]
    DIRECTION INPUT ;
    USE SIGNAL ;
    PORT
      LAYER M4 ;
        RECT  71.088 19.296 71.28 19.32 ;
    END
  END i[91]
  PIN i[92]
    DIRECTION INPUT ;
    USE SIGNAL ;
    PORT
      LAYER M4 ;
        RECT  71.088 19.44 71.28 19.464 ;
    END
  END i[92]
  PIN i[93]
    DIRECTION INPUT ;
    USE SIGNAL ;
    PORT
      LAYER M4 ;
        RECT  71.088 19.632 71.28 19.656 ;
    END
  END i[93]
  PIN i[94]
    DIRECTION INPUT ;
    USE SIGNAL ;
    PORT
      LAYER M4 ;
        RECT  71.088 19.776 71.28 19.8 ;
    END
  END i[94]
  PIN i[95]
    DIRECTION INPUT ;
    USE SIGNAL ;
    PORT
      LAYER M4 ;
        RECT  71.088 19.968 71.28 19.992 ;
    END
  END i[95]
  PIN i[96]
    DIRECTION INPUT ;
    USE SIGNAL ;
    PORT
      LAYER M4 ;
        RECT  71.088 20.112 71.28 20.136 ;
    END
  END i[96]
  PIN i[97]
    DIRECTION INPUT ;
    USE SIGNAL ;
    PORT
      LAYER M4 ;
        RECT  71.088 20.256 71.28 20.28 ;
    END
  END i[97]
  PIN i[98]
    DIRECTION INPUT ;
    USE SIGNAL ;
    PORT
      LAYER M4 ;
        RECT  71.088 20.448 71.28 20.472 ;
    END
  END i[98]
  PIN i[99]
    DIRECTION INPUT ;
    USE SIGNAL ;
    PORT
      LAYER M4 ;
        RECT  71.088 20.592 71.28 20.616 ;
    END
  END i[99]
  PIN i[9]
    DIRECTION INPUT ;
    USE SIGNAL ;
    PORT
      LAYER M4 ;
        RECT  71.088 5.904 71.28 5.928 ;
    END
  END i[9]
  PIN od[0]
    DIRECTION OUTPUT ;
    USE SIGNAL ;
    PORT
      LAYER M4 ;
        RECT  0 4.56 0.192 4.584 ;
    END
  END od[0]
  PIN od[100]
    DIRECTION OUTPUT ;
    USE SIGNAL ;
    PORT
      LAYER M4 ;
        RECT  0 20.976 0.192 21 ;
    END
  END od[100]
  PIN od[101]
    DIRECTION OUTPUT ;
    USE SIGNAL ;
    PORT
      LAYER M4 ;
        RECT  0 21.12 0.192 21.144 ;
    END
  END od[101]
  PIN od[102]
    DIRECTION OUTPUT ;
    USE SIGNAL ;
    PORT
      LAYER M4 ;
        RECT  0 21.264 0.192 21.288 ;
    END
  END od[102]
  PIN od[103]
    DIRECTION OUTPUT ;
    USE SIGNAL ;
    PORT
      LAYER M4 ;
        RECT  0 21.456 0.192 21.48 ;
    END
  END od[103]
  PIN od[104]
    DIRECTION OUTPUT ;
    USE SIGNAL ;
    PORT
      LAYER M4 ;
        RECT  0 21.6 0.192 21.624 ;
    END
  END od[104]
  PIN od[105]
    DIRECTION OUTPUT ;
    USE SIGNAL ;
    PORT
      LAYER M4 ;
        RECT  0 21.792 0.192 21.816 ;
    END
  END od[105]
  PIN od[106]
    DIRECTION OUTPUT ;
    USE SIGNAL ;
    PORT
      LAYER M4 ;
        RECT  0 21.936 0.192 21.96 ;
    END
  END od[106]
  PIN od[107]
    DIRECTION OUTPUT ;
    USE SIGNAL ;
    PORT
      LAYER M4 ;
        RECT  0 22.128 0.192 22.152 ;
    END
  END od[107]
  PIN od[108]
    DIRECTION OUTPUT ;
    USE SIGNAL ;
    PORT
      LAYER M4 ;
        RECT  0 22.272 0.192 22.296 ;
    END
  END od[108]
  PIN od[109]
    DIRECTION OUTPUT ;
    USE SIGNAL ;
    PORT
      LAYER M4 ;
        RECT  0 22.416 0.192 22.44 ;
    END
  END od[109]
  PIN od[10]
    DIRECTION OUTPUT ;
    USE SIGNAL ;
    PORT
      LAYER M4 ;
        RECT  0 6.192 0.192 6.216 ;
    END
  END od[10]
  PIN od[110]
    DIRECTION OUTPUT ;
    USE SIGNAL ;
    PORT
      LAYER M4 ;
        RECT  0 22.608 0.192 22.632 ;
    END
  END od[110]
  PIN od[111]
    DIRECTION OUTPUT ;
    USE SIGNAL ;
    PORT
      LAYER M4 ;
        RECT  0 22.752 0.192 22.776 ;
    END
  END od[111]
  PIN od[112]
    DIRECTION OUTPUT ;
    USE SIGNAL ;
    PORT
      LAYER M4 ;
        RECT  0 22.944 0.192 22.968 ;
    END
  END od[112]
  PIN od[113]
    DIRECTION OUTPUT ;
    USE SIGNAL ;
    PORT
      LAYER M4 ;
        RECT  0 23.088 0.192 23.112 ;
    END
  END od[113]
  PIN od[114]
    DIRECTION OUTPUT ;
    USE SIGNAL ;
    PORT
      LAYER M4 ;
        RECT  0 23.232 0.192 23.256 ;
    END
  END od[114]
  PIN od[115]
    DIRECTION OUTPUT ;
    USE SIGNAL ;
    PORT
      LAYER M4 ;
        RECT  0 23.424 0.192 23.448 ;
    END
  END od[115]
  PIN od[116]
    DIRECTION OUTPUT ;
    USE SIGNAL ;
    PORT
      LAYER M4 ;
        RECT  0 23.568 0.192 23.592 ;
    END
  END od[116]
  PIN od[117]
    DIRECTION OUTPUT ;
    USE SIGNAL ;
    PORT
      LAYER M4 ;
        RECT  0 23.76 0.192 23.784 ;
    END
  END od[117]
  PIN od[118]
    DIRECTION OUTPUT ;
    USE SIGNAL ;
    PORT
      LAYER M4 ;
        RECT  0 23.904 0.192 23.928 ;
    END
  END od[118]
  PIN od[119]
    DIRECTION OUTPUT ;
    USE SIGNAL ;
    PORT
      LAYER M4 ;
        RECT  0 24.048 0.192 24.072 ;
    END
  END od[119]
  PIN od[11]
    DIRECTION OUTPUT ;
    USE SIGNAL ;
    PORT
      LAYER M4 ;
        RECT  0 6.384 0.192 6.408 ;
    END
  END od[11]
  PIN od[120]
    DIRECTION OUTPUT ;
    USE SIGNAL ;
    PORT
      LAYER M4 ;
        RECT  0 24.24 0.192 24.264 ;
    END
  END od[120]
  PIN od[121]
    DIRECTION OUTPUT ;
    USE SIGNAL ;
    PORT
      LAYER M4 ;
        RECT  0 24.384 0.192 24.408 ;
    END
  END od[121]
  PIN od[122]
    DIRECTION OUTPUT ;
    USE SIGNAL ;
    PORT
      LAYER M4 ;
        RECT  0 24.576 0.192 24.6 ;
    END
  END od[122]
  PIN od[123]
    DIRECTION OUTPUT ;
    USE SIGNAL ;
    PORT
      LAYER M4 ;
        RECT  0 24.72 0.192 24.744 ;
    END
  END od[123]
  PIN od[124]
    DIRECTION OUTPUT ;
    USE SIGNAL ;
    PORT
      LAYER M4 ;
        RECT  0 24.912 0.192 24.936 ;
    END
  END od[124]
  PIN od[125]
    DIRECTION OUTPUT ;
    USE SIGNAL ;
    PORT
      LAYER M4 ;
        RECT  0 25.056 0.192 25.08 ;
    END
  END od[125]
  PIN od[126]
    DIRECTION OUTPUT ;
    USE SIGNAL ;
    PORT
      LAYER M4 ;
        RECT  0 25.2 0.192 25.224 ;
    END
  END od[126]
  PIN od[127]
    DIRECTION OUTPUT ;
    USE SIGNAL ;
    PORT
      LAYER M4 ;
        RECT  0 25.392 0.192 25.416 ;
    END
  END od[127]
  PIN od[128]
    DIRECTION OUTPUT ;
    USE SIGNAL ;
    PORT
      LAYER M4 ;
        RECT  0 25.536 0.192 25.56 ;
    END
  END od[128]
  PIN od[129]
    DIRECTION OUTPUT ;
    USE SIGNAL ;
    PORT
      LAYER M4 ;
        RECT  0 25.728 0.192 25.752 ;
    END
  END od[129]
  PIN od[12]
    DIRECTION OUTPUT ;
    USE SIGNAL ;
    PORT
      LAYER M4 ;
        RECT  0 6.528 0.192 6.552 ;
    END
  END od[12]
  PIN od[130]
    DIRECTION OUTPUT ;
    USE SIGNAL ;
    PORT
      LAYER M4 ;
        RECT  0 25.872 0.192 25.896 ;
    END
  END od[130]
  PIN od[131]
    DIRECTION OUTPUT ;
    USE SIGNAL ;
    PORT
      LAYER M4 ;
        RECT  0 26.016 0.192 26.04 ;
    END
  END od[131]
  PIN od[132]
    DIRECTION OUTPUT ;
    USE SIGNAL ;
    PORT
      LAYER M4 ;
        RECT  0 26.208 0.192 26.232 ;
    END
  END od[132]
  PIN od[133]
    DIRECTION OUTPUT ;
    USE SIGNAL ;
    PORT
      LAYER M4 ;
        RECT  0 26.352 0.192 26.376 ;
    END
  END od[133]
  PIN od[134]
    DIRECTION OUTPUT ;
    USE SIGNAL ;
    PORT
      LAYER M4 ;
        RECT  0 26.544 0.192 26.568 ;
    END
  END od[134]
  PIN od[135]
    DIRECTION OUTPUT ;
    USE SIGNAL ;
    PORT
      LAYER M4 ;
        RECT  0 26.688 0.192 26.712 ;
    END
  END od[135]
  PIN od[136]
    DIRECTION OUTPUT ;
    USE SIGNAL ;
    PORT
      LAYER M4 ;
        RECT  0 26.832 0.192 26.856 ;
    END
  END od[136]
  PIN od[137]
    DIRECTION OUTPUT ;
    USE SIGNAL ;
    PORT
      LAYER M4 ;
        RECT  0 27.024 0.192 27.048 ;
    END
  END od[137]
  PIN od[138]
    DIRECTION OUTPUT ;
    USE SIGNAL ;
    PORT
      LAYER M4 ;
        RECT  0 27.168 0.192 27.192 ;
    END
  END od[138]
  PIN od[139]
    DIRECTION OUTPUT ;
    USE SIGNAL ;
    PORT
      LAYER M4 ;
        RECT  0 27.36 0.192 27.384 ;
    END
  END od[139]
  PIN od[13]
    DIRECTION OUTPUT ;
    USE SIGNAL ;
    PORT
      LAYER M4 ;
        RECT  0 6.72 0.192 6.744 ;
    END
  END od[13]
  PIN od[140]
    DIRECTION OUTPUT ;
    USE SIGNAL ;
    PORT
      LAYER M4 ;
        RECT  0 27.504 0.192 27.528 ;
    END
  END od[140]
  PIN od[141]
    DIRECTION OUTPUT ;
    USE SIGNAL ;
    PORT
      LAYER M4 ;
        RECT  0 27.696 0.192 27.72 ;
    END
  END od[141]
  PIN od[142]
    DIRECTION OUTPUT ;
    USE SIGNAL ;
    PORT
      LAYER M4 ;
        RECT  0 27.84 0.192 27.864 ;
    END
  END od[142]
  PIN od[143]
    DIRECTION OUTPUT ;
    USE SIGNAL ;
    PORT
      LAYER M4 ;
        RECT  0 27.984 0.192 28.008 ;
    END
  END od[143]
  PIN od[144]
    DIRECTION OUTPUT ;
    USE SIGNAL ;
    PORT
      LAYER M4 ;
        RECT  0 28.176 0.192 28.2 ;
    END
  END od[144]
  PIN od[145]
    DIRECTION OUTPUT ;
    USE SIGNAL ;
    PORT
      LAYER M4 ;
        RECT  0 28.32 0.192 28.344 ;
    END
  END od[145]
  PIN od[146]
    DIRECTION OUTPUT ;
    USE SIGNAL ;
    PORT
      LAYER M4 ;
        RECT  0 28.512 0.192 28.536 ;
    END
  END od[146]
  PIN od[147]
    DIRECTION OUTPUT ;
    USE SIGNAL ;
    PORT
      LAYER M4 ;
        RECT  0 28.656 0.192 28.68 ;
    END
  END od[147]
  PIN od[148]
    DIRECTION OUTPUT ;
    USE SIGNAL ;
    PORT
      LAYER M4 ;
        RECT  0 28.8 0.192 28.824 ;
    END
  END od[148]
  PIN od[149]
    DIRECTION OUTPUT ;
    USE SIGNAL ;
    PORT
      LAYER M4 ;
        RECT  0 28.992 0.192 29.016 ;
    END
  END od[149]
  PIN od[14]
    DIRECTION OUTPUT ;
    USE SIGNAL ;
    PORT
      LAYER M4 ;
        RECT  0 6.864 0.192 6.888 ;
    END
  END od[14]
  PIN od[150]
    DIRECTION OUTPUT ;
    USE SIGNAL ;
    PORT
      LAYER M4 ;
        RECT  0 29.136 0.192 29.16 ;
    END
  END od[150]
  PIN od[151]
    DIRECTION OUTPUT ;
    USE SIGNAL ;
    PORT
      LAYER M4 ;
        RECT  0 29.328 0.192 29.352 ;
    END
  END od[151]
  PIN od[152]
    DIRECTION OUTPUT ;
    USE SIGNAL ;
    PORT
      LAYER M4 ;
        RECT  0 29.472 0.192 29.496 ;
    END
  END od[152]
  PIN od[153]
    DIRECTION OUTPUT ;
    USE SIGNAL ;
    PORT
      LAYER M4 ;
        RECT  0 29.664 0.192 29.688 ;
    END
  END od[153]
  PIN od[154]
    DIRECTION OUTPUT ;
    USE SIGNAL ;
    PORT
      LAYER M4 ;
        RECT  0 29.808 0.192 29.832 ;
    END
  END od[154]
  PIN od[155]
    DIRECTION OUTPUT ;
    USE SIGNAL ;
    PORT
      LAYER M4 ;
        RECT  0 29.952 0.192 29.976 ;
    END
  END od[155]
  PIN od[156]
    DIRECTION OUTPUT ;
    USE SIGNAL ;
    PORT
      LAYER M4 ;
        RECT  0 30.144 0.192 30.168 ;
    END
  END od[156]
  PIN od[157]
    DIRECTION OUTPUT ;
    USE SIGNAL ;
    PORT
      LAYER M4 ;
        RECT  0 30.288 0.192 30.312 ;
    END
  END od[157]
  PIN od[158]
    DIRECTION OUTPUT ;
    USE SIGNAL ;
    PORT
      LAYER M4 ;
        RECT  0 30.48 0.192 30.504 ;
    END
  END od[158]
  PIN od[159]
    DIRECTION OUTPUT ;
    USE SIGNAL ;
    PORT
      LAYER M4 ;
        RECT  0 30.624 0.192 30.648 ;
    END
  END od[159]
  PIN od[15]
    DIRECTION OUTPUT ;
    USE SIGNAL ;
    PORT
      LAYER M4 ;
        RECT  0 7.056 0.192 7.08 ;
    END
  END od[15]
  PIN od[160]
    DIRECTION OUTPUT ;
    USE SIGNAL ;
    PORT
      LAYER M4 ;
        RECT  0 30.768 0.192 30.792 ;
    END
  END od[160]
  PIN od[161]
    DIRECTION OUTPUT ;
    USE SIGNAL ;
    PORT
      LAYER M4 ;
        RECT  0 30.96 0.192 30.984 ;
    END
  END od[161]
  PIN od[162]
    DIRECTION OUTPUT ;
    USE SIGNAL ;
    PORT
      LAYER M4 ;
        RECT  0 31.104 0.192 31.128 ;
    END
  END od[162]
  PIN od[163]
    DIRECTION OUTPUT ;
    USE SIGNAL ;
    PORT
      LAYER M4 ;
        RECT  0 31.296 0.192 31.32 ;
    END
  END od[163]
  PIN od[164]
    DIRECTION OUTPUT ;
    USE SIGNAL ;
    PORT
      LAYER M4 ;
        RECT  0 31.44 0.192 31.464 ;
    END
  END od[164]
  PIN od[165]
    DIRECTION OUTPUT ;
    USE SIGNAL ;
    PORT
      LAYER M4 ;
        RECT  0 31.584 0.192 31.608 ;
    END
  END od[165]
  PIN od[166]
    DIRECTION OUTPUT ;
    USE SIGNAL ;
    PORT
      LAYER M4 ;
        RECT  0 31.776 0.192 31.8 ;
    END
  END od[166]
  PIN od[167]
    DIRECTION OUTPUT ;
    USE SIGNAL ;
    PORT
      LAYER M4 ;
        RECT  0 31.92 0.192 31.944 ;
    END
  END od[167]
  PIN od[168]
    DIRECTION OUTPUT ;
    USE SIGNAL ;
    PORT
      LAYER M4 ;
        RECT  0 32.112 0.192 32.136 ;
    END
  END od[168]
  PIN od[169]
    DIRECTION OUTPUT ;
    USE SIGNAL ;
    PORT
      LAYER M4 ;
        RECT  0 32.256 0.192 32.28 ;
    END
  END od[169]
  PIN od[16]
    DIRECTION OUTPUT ;
    USE SIGNAL ;
    PORT
      LAYER M4 ;
        RECT  0 7.2 0.192 7.224 ;
    END
  END od[16]
  PIN od[170]
    DIRECTION OUTPUT ;
    USE SIGNAL ;
    PORT
      LAYER M4 ;
        RECT  0 32.448 0.192 32.472 ;
    END
  END od[170]
  PIN od[171]
    DIRECTION OUTPUT ;
    USE SIGNAL ;
    PORT
      LAYER M4 ;
        RECT  0 32.592 0.192 32.616 ;
    END
  END od[171]
  PIN od[172]
    DIRECTION OUTPUT ;
    USE SIGNAL ;
    PORT
      LAYER M4 ;
        RECT  0 32.736 0.192 32.76 ;
    END
  END od[172]
  PIN od[173]
    DIRECTION OUTPUT ;
    USE SIGNAL ;
    PORT
      LAYER M4 ;
        RECT  0 32.928 0.192 32.952 ;
    END
  END od[173]
  PIN od[174]
    DIRECTION OUTPUT ;
    USE SIGNAL ;
    PORT
      LAYER M4 ;
        RECT  0 33.072 0.192 33.096 ;
    END
  END od[174]
  PIN od[175]
    DIRECTION OUTPUT ;
    USE SIGNAL ;
    PORT
      LAYER M4 ;
        RECT  0 33.264 0.192 33.288 ;
    END
  END od[175]
  PIN od[176]
    DIRECTION OUTPUT ;
    USE SIGNAL ;
    PORT
      LAYER M4 ;
        RECT  0 33.408 0.192 33.432 ;
    END
  END od[176]
  PIN od[177]
    DIRECTION OUTPUT ;
    USE SIGNAL ;
    PORT
      LAYER M4 ;
        RECT  0 33.552 0.192 33.576 ;
    END
  END od[177]
  PIN od[178]
    DIRECTION OUTPUT ;
    USE SIGNAL ;
    PORT
      LAYER M4 ;
        RECT  0 33.744 0.192 33.768 ;
    END
  END od[178]
  PIN od[179]
    DIRECTION OUTPUT ;
    USE SIGNAL ;
    PORT
      LAYER M4 ;
        RECT  0 33.888 0.192 33.912 ;
    END
  END od[179]
  PIN od[17]
    DIRECTION OUTPUT ;
    USE SIGNAL ;
    PORT
      LAYER M4 ;
        RECT  0 7.344 0.192 7.368 ;
    END
  END od[17]
  PIN od[180]
    DIRECTION OUTPUT ;
    USE SIGNAL ;
    PORT
      LAYER M4 ;
        RECT  0 34.08 0.192 34.104 ;
    END
  END od[180]
  PIN od[181]
    DIRECTION OUTPUT ;
    USE SIGNAL ;
    PORT
      LAYER M4 ;
        RECT  0 34.224 0.192 34.248 ;
    END
  END od[181]
  PIN od[182]
    DIRECTION OUTPUT ;
    USE SIGNAL ;
    PORT
      LAYER M4 ;
        RECT  0 34.368 0.192 34.392 ;
    END
  END od[182]
  PIN od[183]
    DIRECTION OUTPUT ;
    USE SIGNAL ;
    PORT
      LAYER M4 ;
        RECT  0 34.56 0.192 34.584 ;
    END
  END od[183]
  PIN od[184]
    DIRECTION OUTPUT ;
    USE SIGNAL ;
    PORT
      LAYER M4 ;
        RECT  0 34.704 0.192 34.728 ;
    END
  END od[184]
  PIN od[185]
    DIRECTION OUTPUT ;
    USE SIGNAL ;
    PORT
      LAYER M4 ;
        RECT  0 34.896 0.192 34.92 ;
    END
  END od[185]
  PIN od[186]
    DIRECTION OUTPUT ;
    USE SIGNAL ;
    PORT
      LAYER M4 ;
        RECT  0 35.04 0.192 35.064 ;
    END
  END od[186]
  PIN od[187]
    DIRECTION OUTPUT ;
    USE SIGNAL ;
    PORT
      LAYER M4 ;
        RECT  0 35.232 0.192 35.256 ;
    END
  END od[187]
  PIN od[188]
    DIRECTION OUTPUT ;
    USE SIGNAL ;
    PORT
      LAYER M4 ;
        RECT  0 35.376 0.192 35.4 ;
    END
  END od[188]
  PIN od[189]
    DIRECTION OUTPUT ;
    USE SIGNAL ;
    PORT
      LAYER M4 ;
        RECT  0 35.52 0.192 35.544 ;
    END
  END od[189]
  PIN od[18]
    DIRECTION OUTPUT ;
    USE SIGNAL ;
    PORT
      LAYER M4 ;
        RECT  0 7.536 0.192 7.56 ;
    END
  END od[18]
  PIN od[190]
    DIRECTION OUTPUT ;
    USE SIGNAL ;
    PORT
      LAYER M4 ;
        RECT  0 35.712 0.192 35.736 ;
    END
  END od[190]
  PIN od[191]
    DIRECTION OUTPUT ;
    USE SIGNAL ;
    PORT
      LAYER M4 ;
        RECT  0 35.856 0.192 35.88 ;
    END
  END od[191]
  PIN od[192]
    DIRECTION OUTPUT ;
    USE SIGNAL ;
    PORT
      LAYER M4 ;
        RECT  0 36.048 0.192 36.072 ;
    END
  END od[192]
  PIN od[193]
    DIRECTION OUTPUT ;
    USE SIGNAL ;
    PORT
      LAYER M4 ;
        RECT  0 36.192 0.192 36.216 ;
    END
  END od[193]
  PIN od[194]
    DIRECTION OUTPUT ;
    USE SIGNAL ;
    PORT
      LAYER M4 ;
        RECT  0 36.336 0.192 36.36 ;
    END
  END od[194]
  PIN od[195]
    DIRECTION OUTPUT ;
    USE SIGNAL ;
    PORT
      LAYER M4 ;
        RECT  0 36.528 0.192 36.552 ;
    END
  END od[195]
  PIN od[196]
    DIRECTION OUTPUT ;
    USE SIGNAL ;
    PORT
      LAYER M4 ;
        RECT  0 36.672 0.192 36.696 ;
    END
  END od[196]
  PIN od[197]
    DIRECTION OUTPUT ;
    USE SIGNAL ;
    PORT
      LAYER M4 ;
        RECT  0 36.864 0.192 36.888 ;
    END
  END od[197]
  PIN od[198]
    DIRECTION OUTPUT ;
    USE SIGNAL ;
    PORT
      LAYER M4 ;
        RECT  0 37.008 0.192 37.032 ;
    END
  END od[198]
  PIN od[199]
    DIRECTION OUTPUT ;
    USE SIGNAL ;
    PORT
      LAYER M4 ;
        RECT  0 37.152 0.192 37.176 ;
    END
  END od[199]
  PIN od[19]
    DIRECTION OUTPUT ;
    USE SIGNAL ;
    PORT
      LAYER M4 ;
        RECT  0 7.68 0.192 7.704 ;
    END
  END od[19]
  PIN od[1]
    DIRECTION OUTPUT ;
    USE SIGNAL ;
    PORT
      LAYER M4 ;
        RECT  0 4.752 0.192 4.776 ;
    END
  END od[1]
  PIN od[200]
    DIRECTION OUTPUT ;
    USE SIGNAL ;
    PORT
      LAYER M4 ;
        RECT  0 37.344 0.192 37.368 ;
    END
  END od[200]
  PIN od[201]
    DIRECTION OUTPUT ;
    USE SIGNAL ;
    PORT
      LAYER M4 ;
        RECT  0 37.488 0.192 37.512 ;
    END
  END od[201]
  PIN od[202]
    DIRECTION OUTPUT ;
    USE SIGNAL ;
    PORT
      LAYER M4 ;
        RECT  0 37.68 0.192 37.704 ;
    END
  END od[202]
  PIN od[203]
    DIRECTION OUTPUT ;
    USE SIGNAL ;
    PORT
      LAYER M4 ;
        RECT  0 37.824 0.192 37.848 ;
    END
  END od[203]
  PIN od[204]
    DIRECTION OUTPUT ;
    USE SIGNAL ;
    PORT
      LAYER M4 ;
        RECT  0 38.016 0.192 38.04 ;
    END
  END od[204]
  PIN od[205]
    DIRECTION OUTPUT ;
    USE SIGNAL ;
    PORT
      LAYER M4 ;
        RECT  0 38.16 0.192 38.184 ;
    END
  END od[205]
  PIN od[206]
    DIRECTION OUTPUT ;
    USE SIGNAL ;
    PORT
      LAYER M4 ;
        RECT  0 38.304 0.192 38.328 ;
    END
  END od[206]
  PIN od[207]
    DIRECTION OUTPUT ;
    USE SIGNAL ;
    PORT
      LAYER M4 ;
        RECT  0 38.496 0.192 38.52 ;
    END
  END od[207]
  PIN od[208]
    DIRECTION OUTPUT ;
    USE SIGNAL ;
    PORT
      LAYER M4 ;
        RECT  0 38.64 0.192 38.664 ;
    END
  END od[208]
  PIN od[209]
    DIRECTION OUTPUT ;
    USE SIGNAL ;
    PORT
      LAYER M4 ;
        RECT  0 38.832 0.192 38.856 ;
    END
  END od[209]
  PIN od[20]
    DIRECTION OUTPUT ;
    USE SIGNAL ;
    PORT
      LAYER M4 ;
        RECT  0 7.872 0.192 7.896 ;
    END
  END od[20]
  PIN od[210]
    DIRECTION OUTPUT ;
    USE SIGNAL ;
    PORT
      LAYER M4 ;
        RECT  0 38.976 0.192 39 ;
    END
  END od[210]
  PIN od[211]
    DIRECTION OUTPUT ;
    USE SIGNAL ;
    PORT
      LAYER M4 ;
        RECT  0 39.12 0.192 39.144 ;
    END
  END od[211]
  PIN od[212]
    DIRECTION OUTPUT ;
    USE SIGNAL ;
    PORT
      LAYER M4 ;
        RECT  0 39.312 0.192 39.336 ;
    END
  END od[212]
  PIN od[213]
    DIRECTION OUTPUT ;
    USE SIGNAL ;
    PORT
      LAYER M4 ;
        RECT  0 39.456 0.192 39.48 ;
    END
  END od[213]
  PIN od[214]
    DIRECTION OUTPUT ;
    USE SIGNAL ;
    PORT
      LAYER M4 ;
        RECT  0 39.648 0.192 39.672 ;
    END
  END od[214]
  PIN od[215]
    DIRECTION OUTPUT ;
    USE SIGNAL ;
    PORT
      LAYER M4 ;
        RECT  0 39.792 0.192 39.816 ;
    END
  END od[215]
  PIN od[216]
    DIRECTION OUTPUT ;
    USE SIGNAL ;
    PORT
      LAYER M4 ;
        RECT  0 39.984 0.192 40.008 ;
    END
  END od[216]
  PIN od[217]
    DIRECTION OUTPUT ;
    USE SIGNAL ;
    PORT
      LAYER M4 ;
        RECT  0 40.128 0.192 40.152 ;
    END
  END od[217]
  PIN od[218]
    DIRECTION OUTPUT ;
    USE SIGNAL ;
    PORT
      LAYER M4 ;
        RECT  0 40.272 0.192 40.296 ;
    END
  END od[218]
  PIN od[219]
    DIRECTION OUTPUT ;
    USE SIGNAL ;
    PORT
      LAYER M4 ;
        RECT  0 40.464 0.192 40.488 ;
    END
  END od[219]
  PIN od[21]
    DIRECTION OUTPUT ;
    USE SIGNAL ;
    PORT
      LAYER M4 ;
        RECT  0 8.016 0.192 8.04 ;
    END
  END od[21]
  PIN od[220]
    DIRECTION OUTPUT ;
    USE SIGNAL ;
    PORT
      LAYER M4 ;
        RECT  0 40.608 0.192 40.632 ;
    END
  END od[220]
  PIN od[221]
    DIRECTION OUTPUT ;
    USE SIGNAL ;
    PORT
      LAYER M4 ;
        RECT  0 40.8 0.192 40.824 ;
    END
  END od[221]
  PIN od[222]
    DIRECTION OUTPUT ;
    USE SIGNAL ;
    PORT
      LAYER M4 ;
        RECT  0 40.944 0.192 40.968 ;
    END
  END od[222]
  PIN od[223]
    DIRECTION OUTPUT ;
    USE SIGNAL ;
    PORT
      LAYER M4 ;
        RECT  0 41.088 0.192 41.112 ;
    END
  END od[223]
  PIN od[224]
    DIRECTION OUTPUT ;
    USE SIGNAL ;
    PORT
      LAYER M4 ;
        RECT  0 41.28 0.192 41.304 ;
    END
  END od[224]
  PIN od[225]
    DIRECTION OUTPUT ;
    USE SIGNAL ;
    PORT
      LAYER M4 ;
        RECT  0 41.424 0.192 41.448 ;
    END
  END od[225]
  PIN od[226]
    DIRECTION OUTPUT ;
    USE SIGNAL ;
    PORT
      LAYER M4 ;
        RECT  0 41.616 0.192 41.64 ;
    END
  END od[226]
  PIN od[227]
    DIRECTION OUTPUT ;
    USE SIGNAL ;
    PORT
      LAYER M4 ;
        RECT  0 41.76 0.192 41.784 ;
    END
  END od[227]
  PIN od[228]
    DIRECTION OUTPUT ;
    USE SIGNAL ;
    PORT
      LAYER M4 ;
        RECT  0 41.904 0.192 41.928 ;
    END
  END od[228]
  PIN od[229]
    DIRECTION OUTPUT ;
    USE SIGNAL ;
    PORT
      LAYER M4 ;
        RECT  0 42.096 0.192 42.12 ;
    END
  END od[229]
  PIN od[22]
    DIRECTION OUTPUT ;
    USE SIGNAL ;
    PORT
      LAYER M4 ;
        RECT  0 8.16 0.192 8.184 ;
    END
  END od[22]
  PIN od[230]
    DIRECTION OUTPUT ;
    USE SIGNAL ;
    PORT
      LAYER M4 ;
        RECT  0 42.24 0.192 42.264 ;
    END
  END od[230]
  PIN od[231]
    DIRECTION OUTPUT ;
    USE SIGNAL ;
    PORT
      LAYER M4 ;
        RECT  0 42.432 0.192 42.456 ;
    END
  END od[231]
  PIN od[232]
    DIRECTION OUTPUT ;
    USE SIGNAL ;
    PORT
      LAYER M4 ;
        RECT  0 42.576 0.192 42.6 ;
    END
  END od[232]
  PIN od[233]
    DIRECTION OUTPUT ;
    USE SIGNAL ;
    PORT
      LAYER M4 ;
        RECT  0 42.768 0.192 42.792 ;
    END
  END od[233]
  PIN od[234]
    DIRECTION OUTPUT ;
    USE SIGNAL ;
    PORT
      LAYER M4 ;
        RECT  0 42.912 0.192 42.936 ;
    END
  END od[234]
  PIN od[235]
    DIRECTION OUTPUT ;
    USE SIGNAL ;
    PORT
      LAYER M4 ;
        RECT  0 43.056 0.192 43.08 ;
    END
  END od[235]
  PIN od[236]
    DIRECTION OUTPUT ;
    USE SIGNAL ;
    PORT
      LAYER M4 ;
        RECT  0 43.248 0.192 43.272 ;
    END
  END od[236]
  PIN od[237]
    DIRECTION OUTPUT ;
    USE SIGNAL ;
    PORT
      LAYER M4 ;
        RECT  0 43.392 0.192 43.416 ;
    END
  END od[237]
  PIN od[238]
    DIRECTION OUTPUT ;
    USE SIGNAL ;
    PORT
      LAYER M4 ;
        RECT  0 43.584 0.192 43.608 ;
    END
  END od[238]
  PIN od[239]
    DIRECTION OUTPUT ;
    USE SIGNAL ;
    PORT
      LAYER M4 ;
        RECT  0 43.728 0.192 43.752 ;
    END
  END od[239]
  PIN od[23]
    DIRECTION OUTPUT ;
    USE SIGNAL ;
    PORT
      LAYER M4 ;
        RECT  0 8.352 0.192 8.376 ;
    END
  END od[23]
  PIN od[240]
    DIRECTION OUTPUT ;
    USE SIGNAL ;
    PORT
      LAYER M4 ;
        RECT  0 43.872 0.192 43.896 ;
    END
  END od[240]
  PIN od[241]
    DIRECTION OUTPUT ;
    USE SIGNAL ;
    PORT
      LAYER M4 ;
        RECT  0 44.064 0.192 44.088 ;
    END
  END od[241]
  PIN od[242]
    DIRECTION OUTPUT ;
    USE SIGNAL ;
    PORT
      LAYER M4 ;
        RECT  0 44.208 0.192 44.232 ;
    END
  END od[242]
  PIN od[243]
    DIRECTION OUTPUT ;
    USE SIGNAL ;
    PORT
      LAYER M4 ;
        RECT  0 44.4 0.192 44.424 ;
    END
  END od[243]
  PIN od[244]
    DIRECTION OUTPUT ;
    USE SIGNAL ;
    PORT
      LAYER M4 ;
        RECT  0 44.544 0.192 44.568 ;
    END
  END od[244]
  PIN od[245]
    DIRECTION OUTPUT ;
    USE SIGNAL ;
    PORT
      LAYER M4 ;
        RECT  0 44.688 0.192 44.712 ;
    END
  END od[245]
  PIN od[246]
    DIRECTION OUTPUT ;
    USE SIGNAL ;
    PORT
      LAYER M4 ;
        RECT  0 44.88 0.192 44.904 ;
    END
  END od[246]
  PIN od[247]
    DIRECTION OUTPUT ;
    USE SIGNAL ;
    PORT
      LAYER M4 ;
        RECT  0 45.024 0.192 45.048 ;
    END
  END od[247]
  PIN od[248]
    DIRECTION OUTPUT ;
    USE SIGNAL ;
    PORT
      LAYER M4 ;
        RECT  0 45.216 0.192 45.24 ;
    END
  END od[248]
  PIN od[249]
    DIRECTION OUTPUT ;
    USE SIGNAL ;
    PORT
      LAYER M4 ;
        RECT  0 45.36 0.192 45.384 ;
    END
  END od[249]
  PIN od[24]
    DIRECTION OUTPUT ;
    USE SIGNAL ;
    PORT
      LAYER M4 ;
        RECT  0 8.496 0.192 8.52 ;
    END
  END od[24]
  PIN od[250]
    DIRECTION OUTPUT ;
    USE SIGNAL ;
    PORT
      LAYER M4 ;
        RECT  0 45.552 0.192 45.576 ;
    END
  END od[250]
  PIN od[251]
    DIRECTION OUTPUT ;
    USE SIGNAL ;
    PORT
      LAYER M4 ;
        RECT  0 45.696 0.192 45.72 ;
    END
  END od[251]
  PIN od[252]
    DIRECTION OUTPUT ;
    USE SIGNAL ;
    PORT
      LAYER M4 ;
        RECT  0 45.84 0.192 45.864 ;
    END
  END od[252]
  PIN od[253]
    DIRECTION OUTPUT ;
    USE SIGNAL ;
    PORT
      LAYER M4 ;
        RECT  0 46.032 0.192 46.056 ;
    END
  END od[253]
  PIN od[254]
    DIRECTION OUTPUT ;
    USE SIGNAL ;
    PORT
      LAYER M4 ;
        RECT  0 46.176 0.192 46.2 ;
    END
  END od[254]
  PIN od[255]
    DIRECTION OUTPUT ;
    USE SIGNAL ;
    PORT
      LAYER M4 ;
        RECT  0 46.368 0.192 46.392 ;
    END
  END od[255]
  PIN od[256]
    DIRECTION OUTPUT ;
    USE SIGNAL ;
    PORT
      LAYER M4 ;
        RECT  0 46.512 0.192 46.536 ;
    END
  END od[256]
  PIN od[257]
    DIRECTION OUTPUT ;
    USE SIGNAL ;
    PORT
      LAYER M4 ;
        RECT  0 46.656 0.192 46.68 ;
    END
  END od[257]
  PIN od[258]
    DIRECTION OUTPUT ;
    USE SIGNAL ;
    PORT
      LAYER M4 ;
        RECT  0 46.848 0.192 46.872 ;
    END
  END od[258]
  PIN od[259]
    DIRECTION OUTPUT ;
    USE SIGNAL ;
    PORT
      LAYER M4 ;
        RECT  0 46.992 0.192 47.016 ;
    END
  END od[259]
  PIN od[25]
    DIRECTION OUTPUT ;
    USE SIGNAL ;
    PORT
      LAYER M4 ;
        RECT  0 8.688 0.192 8.712 ;
    END
  END od[25]
  PIN od[260]
    DIRECTION OUTPUT ;
    USE SIGNAL ;
    PORT
      LAYER M4 ;
        RECT  0 47.184 0.192 47.208 ;
    END
  END od[260]
  PIN od[261]
    DIRECTION OUTPUT ;
    USE SIGNAL ;
    PORT
      LAYER M4 ;
        RECT  0 47.328 0.192 47.352 ;
    END
  END od[261]
  PIN od[262]
    DIRECTION OUTPUT ;
    USE SIGNAL ;
    PORT
      LAYER M4 ;
        RECT  0 47.472 0.192 47.496 ;
    END
  END od[262]
  PIN od[263]
    DIRECTION OUTPUT ;
    USE SIGNAL ;
    PORT
      LAYER M4 ;
        RECT  0 47.664 0.192 47.688 ;
    END
  END od[263]
  PIN od[264]
    DIRECTION OUTPUT ;
    USE SIGNAL ;
    PORT
      LAYER M4 ;
        RECT  0 47.808 0.192 47.832 ;
    END
  END od[264]
  PIN od[265]
    DIRECTION OUTPUT ;
    USE SIGNAL ;
    PORT
      LAYER M4 ;
        RECT  0 48 0.192 48.024 ;
    END
  END od[265]
  PIN od[266]
    DIRECTION OUTPUT ;
    USE SIGNAL ;
    PORT
      LAYER M4 ;
        RECT  0 48.144 0.192 48.168 ;
    END
  END od[266]
  PIN od[267]
    DIRECTION OUTPUT ;
    USE SIGNAL ;
    PORT
      LAYER M4 ;
        RECT  0 48.336 0.192 48.36 ;
    END
  END od[267]
  PIN od[268]
    DIRECTION OUTPUT ;
    USE SIGNAL ;
    PORT
      LAYER M4 ;
        RECT  0 48.48 0.192 48.504 ;
    END
  END od[268]
  PIN od[269]
    DIRECTION OUTPUT ;
    USE SIGNAL ;
    PORT
      LAYER M4 ;
        RECT  0 48.624 0.192 48.648 ;
    END
  END od[269]
  PIN od[26]
    DIRECTION OUTPUT ;
    USE SIGNAL ;
    PORT
      LAYER M4 ;
        RECT  0 8.832 0.192 8.856 ;
    END
  END od[26]
  PIN od[270]
    DIRECTION OUTPUT ;
    USE SIGNAL ;
    PORT
      LAYER M4 ;
        RECT  0 48.816 0.192 48.84 ;
    END
  END od[270]
  PIN od[271]
    DIRECTION OUTPUT ;
    USE SIGNAL ;
    PORT
      LAYER M4 ;
        RECT  0 48.96 0.192 48.984 ;
    END
  END od[271]
  PIN od[272]
    DIRECTION OUTPUT ;
    USE SIGNAL ;
    PORT
      LAYER M4 ;
        RECT  0 49.152 0.192 49.176 ;
    END
  END od[272]
  PIN od[273]
    DIRECTION OUTPUT ;
    USE SIGNAL ;
    PORT
      LAYER M4 ;
        RECT  0 49.296 0.192 49.32 ;
    END
  END od[273]
  PIN od[274]
    DIRECTION OUTPUT ;
    USE SIGNAL ;
    PORT
      LAYER M4 ;
        RECT  0 49.44 0.192 49.464 ;
    END
  END od[274]
  PIN od[275]
    DIRECTION OUTPUT ;
    USE SIGNAL ;
    PORT
      LAYER M4 ;
        RECT  0 49.632 0.192 49.656 ;
    END
  END od[275]
  PIN od[276]
    DIRECTION OUTPUT ;
    USE SIGNAL ;
    PORT
      LAYER M4 ;
        RECT  0 49.776 0.192 49.8 ;
    END
  END od[276]
  PIN od[277]
    DIRECTION OUTPUT ;
    USE SIGNAL ;
    PORT
      LAYER M4 ;
        RECT  0 49.968 0.192 49.992 ;
    END
  END od[277]
  PIN od[278]
    DIRECTION OUTPUT ;
    USE SIGNAL ;
    PORT
      LAYER M4 ;
        RECT  0 50.112 0.192 50.136 ;
    END
  END od[278]
  PIN od[279]
    DIRECTION OUTPUT ;
    USE SIGNAL ;
    PORT
      LAYER M4 ;
        RECT  0 50.304 0.192 50.328 ;
    END
  END od[279]
  PIN od[27]
    DIRECTION OUTPUT ;
    USE SIGNAL ;
    PORT
      LAYER M4 ;
        RECT  0 9.024 0.192 9.048 ;
    END
  END od[27]
  PIN od[280]
    DIRECTION OUTPUT ;
    USE SIGNAL ;
    PORT
      LAYER M4 ;
        RECT  0 50.448 0.192 50.472 ;
    END
  END od[280]
  PIN od[281]
    DIRECTION OUTPUT ;
    USE SIGNAL ;
    PORT
      LAYER M4 ;
        RECT  0 50.592 0.192 50.616 ;
    END
  END od[281]
  PIN od[282]
    DIRECTION OUTPUT ;
    USE SIGNAL ;
    PORT
      LAYER M4 ;
        RECT  0 50.784 0.192 50.808 ;
    END
  END od[282]
  PIN od[283]
    DIRECTION OUTPUT ;
    USE SIGNAL ;
    PORT
      LAYER M4 ;
        RECT  0 50.928 0.192 50.952 ;
    END
  END od[283]
  PIN od[284]
    DIRECTION OUTPUT ;
    USE SIGNAL ;
    PORT
      LAYER M4 ;
        RECT  0 51.12 0.192 51.144 ;
    END
  END od[284]
  PIN od[285]
    DIRECTION OUTPUT ;
    USE SIGNAL ;
    PORT
      LAYER M4 ;
        RECT  0 51.264 0.192 51.288 ;
    END
  END od[285]
  PIN od[286]
    DIRECTION OUTPUT ;
    USE SIGNAL ;
    PORT
      LAYER M4 ;
        RECT  0 51.408 0.192 51.432 ;
    END
  END od[286]
  PIN od[287]
    DIRECTION OUTPUT ;
    USE SIGNAL ;
    PORT
      LAYER M4 ;
        RECT  0 51.6 0.192 51.624 ;
    END
  END od[287]
  PIN od[288]
    DIRECTION OUTPUT ;
    USE SIGNAL ;
    PORT
      LAYER M4 ;
        RECT  0 51.744 0.192 51.768 ;
    END
  END od[288]
  PIN od[289]
    DIRECTION OUTPUT ;
    USE SIGNAL ;
    PORT
      LAYER M4 ;
        RECT  0 51.936 0.192 51.96 ;
    END
  END od[289]
  PIN od[28]
    DIRECTION OUTPUT ;
    USE SIGNAL ;
    PORT
      LAYER M4 ;
        RECT  0 9.168 0.192 9.192 ;
    END
  END od[28]
  PIN od[290]
    DIRECTION OUTPUT ;
    USE SIGNAL ;
    PORT
      LAYER M4 ;
        RECT  0 52.08 0.192 52.104 ;
    END
  END od[290]
  PIN od[291]
    DIRECTION OUTPUT ;
    USE SIGNAL ;
    PORT
      LAYER M4 ;
        RECT  0 52.224 0.192 52.248 ;
    END
  END od[291]
  PIN od[292]
    DIRECTION OUTPUT ;
    USE SIGNAL ;
    PORT
      LAYER M4 ;
        RECT  0 52.416 0.192 52.44 ;
    END
  END od[292]
  PIN od[293]
    DIRECTION OUTPUT ;
    USE SIGNAL ;
    PORT
      LAYER M4 ;
        RECT  0 52.56 0.192 52.584 ;
    END
  END od[293]
  PIN od[294]
    DIRECTION OUTPUT ;
    USE SIGNAL ;
    PORT
      LAYER M4 ;
        RECT  0 52.752 0.192 52.776 ;
    END
  END od[294]
  PIN od[295]
    DIRECTION OUTPUT ;
    USE SIGNAL ;
    PORT
      LAYER M4 ;
        RECT  0 52.896 0.192 52.92 ;
    END
  END od[295]
  PIN od[296]
    DIRECTION OUTPUT ;
    USE SIGNAL ;
    PORT
      LAYER M4 ;
        RECT  0 53.088 0.192 53.112 ;
    END
  END od[296]
  PIN od[297]
    DIRECTION OUTPUT ;
    USE SIGNAL ;
    PORT
      LAYER M4 ;
        RECT  0 53.232 0.192 53.256 ;
    END
  END od[297]
  PIN od[298]
    DIRECTION OUTPUT ;
    USE SIGNAL ;
    PORT
      LAYER M4 ;
        RECT  0 53.376 0.192 53.4 ;
    END
  END od[298]
  PIN od[299]
    DIRECTION OUTPUT ;
    USE SIGNAL ;
    PORT
      LAYER M4 ;
        RECT  0 53.568 0.192 53.592 ;
    END
  END od[299]
  PIN od[29]
    DIRECTION OUTPUT ;
    USE SIGNAL ;
    PORT
      LAYER M4 ;
        RECT  0 9.312 0.192 9.336 ;
    END
  END od[29]
  PIN od[2]
    DIRECTION OUTPUT ;
    USE SIGNAL ;
    PORT
      LAYER M4 ;
        RECT  0 4.896 0.192 4.92 ;
    END
  END od[2]
  PIN od[300]
    DIRECTION OUTPUT ;
    USE SIGNAL ;
    PORT
      LAYER M4 ;
        RECT  0 53.712 0.192 53.736 ;
    END
  END od[300]
  PIN od[301]
    DIRECTION OUTPUT ;
    USE SIGNAL ;
    PORT
      LAYER M4 ;
        RECT  0 53.904 0.192 53.928 ;
    END
  END od[301]
  PIN od[302]
    DIRECTION OUTPUT ;
    USE SIGNAL ;
    PORT
      LAYER M4 ;
        RECT  0 54.048 0.192 54.072 ;
    END
  END od[302]
  PIN od[303]
    DIRECTION OUTPUT ;
    USE SIGNAL ;
    PORT
      LAYER M4 ;
        RECT  0 54.192 0.192 54.216 ;
    END
  END od[303]
  PIN od[304]
    DIRECTION OUTPUT ;
    USE SIGNAL ;
    PORT
      LAYER M4 ;
        RECT  0 54.384 0.192 54.408 ;
    END
  END od[304]
  PIN od[305]
    DIRECTION OUTPUT ;
    USE SIGNAL ;
    PORT
      LAYER M4 ;
        RECT  0 54.528 0.192 54.552 ;
    END
  END od[305]
  PIN od[306]
    DIRECTION OUTPUT ;
    USE SIGNAL ;
    PORT
      LAYER M4 ;
        RECT  0 54.72 0.192 54.744 ;
    END
  END od[306]
  PIN od[307]
    DIRECTION OUTPUT ;
    USE SIGNAL ;
    PORT
      LAYER M4 ;
        RECT  0 54.864 0.192 54.888 ;
    END
  END od[307]
  PIN od[308]
    DIRECTION OUTPUT ;
    USE SIGNAL ;
    PORT
      LAYER M4 ;
        RECT  0 55.008 0.192 55.032 ;
    END
  END od[308]
  PIN od[309]
    DIRECTION OUTPUT ;
    USE SIGNAL ;
    PORT
      LAYER M4 ;
        RECT  0 55.2 0.192 55.224 ;
    END
  END od[309]
  PIN od[30]
    DIRECTION OUTPUT ;
    USE SIGNAL ;
    PORT
      LAYER M4 ;
        RECT  0 9.504 0.192 9.528 ;
    END
  END od[30]
  PIN od[310]
    DIRECTION OUTPUT ;
    USE SIGNAL ;
    PORT
      LAYER M4 ;
        RECT  0 55.344 0.192 55.368 ;
    END
  END od[310]
  PIN od[311]
    DIRECTION OUTPUT ;
    USE SIGNAL ;
    PORT
      LAYER M4 ;
        RECT  0 55.536 0.192 55.56 ;
    END
  END od[311]
  PIN od[312]
    DIRECTION OUTPUT ;
    USE SIGNAL ;
    PORT
      LAYER M4 ;
        RECT  0 55.68 0.192 55.704 ;
    END
  END od[312]
  PIN od[313]
    DIRECTION OUTPUT ;
    USE SIGNAL ;
    PORT
      LAYER M4 ;
        RECT  0 55.872 0.192 55.896 ;
    END
  END od[313]
  PIN od[314]
    DIRECTION OUTPUT ;
    USE SIGNAL ;
    PORT
      LAYER M4 ;
        RECT  0 56.016 0.192 56.04 ;
    END
  END od[314]
  PIN od[315]
    DIRECTION OUTPUT ;
    USE SIGNAL ;
    PORT
      LAYER M4 ;
        RECT  0 56.16 0.192 56.184 ;
    END
  END od[315]
  PIN od[316]
    DIRECTION OUTPUT ;
    USE SIGNAL ;
    PORT
      LAYER M4 ;
        RECT  0 56.352 0.192 56.376 ;
    END
  END od[316]
  PIN od[317]
    DIRECTION OUTPUT ;
    USE SIGNAL ;
    PORT
      LAYER M4 ;
        RECT  0 56.496 0.192 56.52 ;
    END
  END od[317]
  PIN od[318]
    DIRECTION OUTPUT ;
    USE SIGNAL ;
    PORT
      LAYER M4 ;
        RECT  0 56.688 0.192 56.712 ;
    END
  END od[318]
  PIN od[319]
    DIRECTION OUTPUT ;
    USE SIGNAL ;
    PORT
      LAYER M4 ;
        RECT  0 56.832 0.192 56.856 ;
    END
  END od[319]
  PIN od[31]
    DIRECTION OUTPUT ;
    USE SIGNAL ;
    PORT
      LAYER M4 ;
        RECT  0 9.648 0.192 9.672 ;
    END
  END od[31]
  PIN od[320]
    DIRECTION OUTPUT ;
    USE SIGNAL ;
    PORT
      LAYER M4 ;
        RECT  0 56.976 0.192 57 ;
    END
  END od[320]
  PIN od[321]
    DIRECTION OUTPUT ;
    USE SIGNAL ;
    PORT
      LAYER M4 ;
        RECT  0 57.168 0.192 57.192 ;
    END
  END od[321]
  PIN od[322]
    DIRECTION OUTPUT ;
    USE SIGNAL ;
    PORT
      LAYER M4 ;
        RECT  0 57.312 0.192 57.336 ;
    END
  END od[322]
  PIN od[323]
    DIRECTION OUTPUT ;
    USE SIGNAL ;
    PORT
      LAYER M4 ;
        RECT  0 57.504 0.192 57.528 ;
    END
  END od[323]
  PIN od[324]
    DIRECTION OUTPUT ;
    USE SIGNAL ;
    PORT
      LAYER M4 ;
        RECT  0 57.648 0.192 57.672 ;
    END
  END od[324]
  PIN od[325]
    DIRECTION OUTPUT ;
    USE SIGNAL ;
    PORT
      LAYER M4 ;
        RECT  0 57.792 0.192 57.816 ;
    END
  END od[325]
  PIN od[326]
    DIRECTION OUTPUT ;
    USE SIGNAL ;
    PORT
      LAYER M4 ;
        RECT  0 57.984 0.192 58.008 ;
    END
  END od[326]
  PIN od[327]
    DIRECTION OUTPUT ;
    USE SIGNAL ;
    PORT
      LAYER M4 ;
        RECT  0 58.128 0.192 58.152 ;
    END
  END od[327]
  PIN od[328]
    DIRECTION OUTPUT ;
    USE SIGNAL ;
    PORT
      LAYER M4 ;
        RECT  0 58.32 0.192 58.344 ;
    END
  END od[328]
  PIN od[329]
    DIRECTION OUTPUT ;
    USE SIGNAL ;
    PORT
      LAYER M4 ;
        RECT  0 58.464 0.192 58.488 ;
    END
  END od[329]
  PIN od[32]
    DIRECTION OUTPUT ;
    USE SIGNAL ;
    PORT
      LAYER M4 ;
        RECT  0 9.84 0.192 9.864 ;
    END
  END od[32]
  PIN od[330]
    DIRECTION OUTPUT ;
    USE SIGNAL ;
    PORT
      LAYER M4 ;
        RECT  0 58.656 0.192 58.68 ;
    END
  END od[330]
  PIN od[331]
    DIRECTION OUTPUT ;
    USE SIGNAL ;
    PORT
      LAYER M4 ;
        RECT  0 58.8 0.192 58.824 ;
    END
  END od[331]
  PIN od[332]
    DIRECTION OUTPUT ;
    USE SIGNAL ;
    PORT
      LAYER M4 ;
        RECT  0 58.944 0.192 58.968 ;
    END
  END od[332]
  PIN od[333]
    DIRECTION OUTPUT ;
    USE SIGNAL ;
    PORT
      LAYER M4 ;
        RECT  0 59.136 0.192 59.16 ;
    END
  END od[333]
  PIN od[334]
    DIRECTION OUTPUT ;
    USE SIGNAL ;
    PORT
      LAYER M4 ;
        RECT  0 59.28 0.192 59.304 ;
    END
  END od[334]
  PIN od[335]
    DIRECTION OUTPUT ;
    USE SIGNAL ;
    PORT
      LAYER M4 ;
        RECT  0 59.472 0.192 59.496 ;
    END
  END od[335]
  PIN od[336]
    DIRECTION OUTPUT ;
    USE SIGNAL ;
    PORT
      LAYER M4 ;
        RECT  0 59.616 0.192 59.64 ;
    END
  END od[336]
  PIN od[337]
    DIRECTION OUTPUT ;
    USE SIGNAL ;
    PORT
      LAYER M4 ;
        RECT  0 59.76 0.192 59.784 ;
    END
  END od[337]
  PIN od[338]
    DIRECTION OUTPUT ;
    USE SIGNAL ;
    PORT
      LAYER M4 ;
        RECT  0 59.952 0.192 59.976 ;
    END
  END od[338]
  PIN od[339]
    DIRECTION OUTPUT ;
    USE SIGNAL ;
    PORT
      LAYER M4 ;
        RECT  0 60.096 0.192 60.12 ;
    END
  END od[339]
  PIN od[33]
    DIRECTION OUTPUT ;
    USE SIGNAL ;
    PORT
      LAYER M4 ;
        RECT  0 9.984 0.192 10.008 ;
    END
  END od[33]
  PIN od[340]
    DIRECTION OUTPUT ;
    USE SIGNAL ;
    PORT
      LAYER M4 ;
        RECT  0 60.288 0.192 60.312 ;
    END
  END od[340]
  PIN od[341]
    DIRECTION OUTPUT ;
    USE SIGNAL ;
    PORT
      LAYER M4 ;
        RECT  0 60.432 0.192 60.456 ;
    END
  END od[341]
  PIN od[342]
    DIRECTION OUTPUT ;
    USE SIGNAL ;
    PORT
      LAYER M4 ;
        RECT  0 60.624 0.192 60.648 ;
    END
  END od[342]
  PIN od[343]
    DIRECTION OUTPUT ;
    USE SIGNAL ;
    PORT
      LAYER M4 ;
        RECT  0 60.768 0.192 60.792 ;
    END
  END od[343]
  PIN od[344]
    DIRECTION OUTPUT ;
    USE SIGNAL ;
    PORT
      LAYER M4 ;
        RECT  0 60.912 0.192 60.936 ;
    END
  END od[344]
  PIN od[345]
    DIRECTION OUTPUT ;
    USE SIGNAL ;
    PORT
      LAYER M4 ;
        RECT  0 61.104 0.192 61.128 ;
    END
  END od[345]
  PIN od[346]
    DIRECTION OUTPUT ;
    USE SIGNAL ;
    PORT
      LAYER M4 ;
        RECT  0 61.248 0.192 61.272 ;
    END
  END od[346]
  PIN od[347]
    DIRECTION OUTPUT ;
    USE SIGNAL ;
    PORT
      LAYER M4 ;
        RECT  0 61.44 0.192 61.464 ;
    END
  END od[347]
  PIN od[348]
    DIRECTION OUTPUT ;
    USE SIGNAL ;
    PORT
      LAYER M4 ;
        RECT  0 61.584 0.192 61.608 ;
    END
  END od[348]
  PIN od[349]
    DIRECTION OUTPUT ;
    USE SIGNAL ;
    PORT
      LAYER M4 ;
        RECT  0 61.728 0.192 61.752 ;
    END
  END od[349]
  PIN od[34]
    DIRECTION OUTPUT ;
    USE SIGNAL ;
    PORT
      LAYER M4 ;
        RECT  0 10.128 0.192 10.152 ;
    END
  END od[34]
  PIN od[350]
    DIRECTION OUTPUT ;
    USE SIGNAL ;
    PORT
      LAYER M4 ;
        RECT  0 61.92 0.192 61.944 ;
    END
  END od[350]
  PIN od[351]
    DIRECTION OUTPUT ;
    USE SIGNAL ;
    PORT
      LAYER M4 ;
        RECT  0 62.064 0.192 62.088 ;
    END
  END od[351]
  PIN od[352]
    DIRECTION OUTPUT ;
    USE SIGNAL ;
    PORT
      LAYER M4 ;
        RECT  0 62.256 0.192 62.28 ;
    END
  END od[352]
  PIN od[353]
    DIRECTION OUTPUT ;
    USE SIGNAL ;
    PORT
      LAYER M4 ;
        RECT  0 62.4 0.192 62.424 ;
    END
  END od[353]
  PIN od[354]
    DIRECTION OUTPUT ;
    USE SIGNAL ;
    PORT
      LAYER M4 ;
        RECT  0 62.544 0.192 62.568 ;
    END
  END od[354]
  PIN od[355]
    DIRECTION OUTPUT ;
    USE SIGNAL ;
    PORT
      LAYER M4 ;
        RECT  0 62.736 0.192 62.76 ;
    END
  END od[355]
  PIN od[356]
    DIRECTION OUTPUT ;
    USE SIGNAL ;
    PORT
      LAYER M4 ;
        RECT  0 62.88 0.192 62.904 ;
    END
  END od[356]
  PIN od[357]
    DIRECTION OUTPUT ;
    USE SIGNAL ;
    PORT
      LAYER M4 ;
        RECT  0 63.072 0.192 63.096 ;
    END
  END od[357]
  PIN od[358]
    DIRECTION OUTPUT ;
    USE SIGNAL ;
    PORT
      LAYER M4 ;
        RECT  0 63.216 0.192 63.24 ;
    END
  END od[358]
  PIN od[359]
    DIRECTION OUTPUT ;
    USE SIGNAL ;
    PORT
      LAYER M4 ;
        RECT  0 63.408 0.192 63.432 ;
    END
  END od[359]
  PIN od[35]
    DIRECTION OUTPUT ;
    USE SIGNAL ;
    PORT
      LAYER M4 ;
        RECT  0 10.32 0.192 10.344 ;
    END
  END od[35]
  PIN od[360]
    DIRECTION OUTPUT ;
    USE SIGNAL ;
    PORT
      LAYER M4 ;
        RECT  0 63.552 0.192 63.576 ;
    END
  END od[360]
  PIN od[361]
    DIRECTION OUTPUT ;
    USE SIGNAL ;
    PORT
      LAYER M4 ;
        RECT  0 63.696 0.192 63.72 ;
    END
  END od[361]
  PIN od[362]
    DIRECTION OUTPUT ;
    USE SIGNAL ;
    PORT
      LAYER M4 ;
        RECT  0 63.888 0.192 63.912 ;
    END
  END od[362]
  PIN od[363]
    DIRECTION OUTPUT ;
    USE SIGNAL ;
    PORT
      LAYER M4 ;
        RECT  0 64.032 0.192 64.056 ;
    END
  END od[363]
  PIN od[364]
    DIRECTION OUTPUT ;
    USE SIGNAL ;
    PORT
      LAYER M4 ;
        RECT  0 64.224 0.192 64.248 ;
    END
  END od[364]
  PIN od[365]
    DIRECTION OUTPUT ;
    USE SIGNAL ;
    PORT
      LAYER M4 ;
        RECT  0 64.368 0.192 64.392 ;
    END
  END od[365]
  PIN od[366]
    DIRECTION OUTPUT ;
    USE SIGNAL ;
    PORT
      LAYER M4 ;
        RECT  0 64.512 0.192 64.536 ;
    END
  END od[366]
  PIN od[367]
    DIRECTION OUTPUT ;
    USE SIGNAL ;
    PORT
      LAYER M4 ;
        RECT  0 64.704 0.192 64.728 ;
    END
  END od[367]
  PIN od[368]
    DIRECTION OUTPUT ;
    USE SIGNAL ;
    PORT
      LAYER M4 ;
        RECT  0 64.848 0.192 64.872 ;
    END
  END od[368]
  PIN od[369]
    DIRECTION OUTPUT ;
    USE SIGNAL ;
    PORT
      LAYER M4 ;
        RECT  0 65.04 0.192 65.064 ;
    END
  END od[369]
  PIN od[36]
    DIRECTION OUTPUT ;
    USE SIGNAL ;
    PORT
      LAYER M4 ;
        RECT  0 10.464 0.192 10.488 ;
    END
  END od[36]
  PIN od[370]
    DIRECTION OUTPUT ;
    USE SIGNAL ;
    PORT
      LAYER M4 ;
        RECT  0 65.184 0.192 65.208 ;
    END
  END od[370]
  PIN od[371]
    DIRECTION OUTPUT ;
    USE SIGNAL ;
    PORT
      LAYER M4 ;
        RECT  0 65.328 0.192 65.352 ;
    END
  END od[371]
  PIN od[372]
    DIRECTION OUTPUT ;
    USE SIGNAL ;
    PORT
      LAYER M4 ;
        RECT  0 65.52 0.192 65.544 ;
    END
  END od[372]
  PIN od[373]
    DIRECTION OUTPUT ;
    USE SIGNAL ;
    PORT
      LAYER M4 ;
        RECT  0 65.664 0.192 65.688 ;
    END
  END od[373]
  PIN od[374]
    DIRECTION OUTPUT ;
    USE SIGNAL ;
    PORT
      LAYER M4 ;
        RECT  0 65.856 0.192 65.88 ;
    END
  END od[374]
  PIN od[375]
    DIRECTION OUTPUT ;
    USE SIGNAL ;
    PORT
      LAYER M4 ;
        RECT  0 66 0.192 66.024 ;
    END
  END od[375]
  PIN od[376]
    DIRECTION OUTPUT ;
    USE SIGNAL ;
    PORT
      LAYER M4 ;
        RECT  0 66.192 0.192 66.216 ;
    END
  END od[376]
  PIN od[377]
    DIRECTION OUTPUT ;
    USE SIGNAL ;
    PORT
      LAYER M4 ;
        RECT  0 66.336 0.192 66.36 ;
    END
  END od[377]
  PIN od[378]
    DIRECTION OUTPUT ;
    USE SIGNAL ;
    PORT
      LAYER M4 ;
        RECT  0 66.48 0.192 66.504 ;
    END
  END od[378]
  PIN od[379]
    DIRECTION OUTPUT ;
    USE SIGNAL ;
    PORT
      LAYER M4 ;
        RECT  0 66.672 0.192 66.696 ;
    END
  END od[379]
  PIN od[37]
    DIRECTION OUTPUT ;
    USE SIGNAL ;
    PORT
      LAYER M4 ;
        RECT  0 10.656 0.192 10.68 ;
    END
  END od[37]
  PIN od[380]
    DIRECTION OUTPUT ;
    USE SIGNAL ;
    PORT
      LAYER M4 ;
        RECT  0 66.816 0.192 66.84 ;
    END
  END od[380]
  PIN od[381]
    DIRECTION OUTPUT ;
    USE SIGNAL ;
    PORT
      LAYER M4 ;
        RECT  0 67.008 0.192 67.032 ;
    END
  END od[381]
  PIN od[382]
    DIRECTION OUTPUT ;
    USE SIGNAL ;
    PORT
      LAYER M4 ;
        RECT  0 67.152 0.192 67.176 ;
    END
  END od[382]
  PIN od[383]
    DIRECTION OUTPUT ;
    USE SIGNAL ;
    PORT
      LAYER M4 ;
        RECT  0 67.296 0.192 67.32 ;
    END
  END od[383]
  PIN od[384]
    DIRECTION OUTPUT ;
    USE SIGNAL ;
    PORT
      LAYER M4 ;
        RECT  0 67.488 0.192 67.512 ;
    END
  END od[384]
  PIN od[385]
    DIRECTION OUTPUT ;
    USE SIGNAL ;
    PORT
      LAYER M4 ;
        RECT  0 67.632 0.192 67.656 ;
    END
  END od[385]
  PIN od[386]
    DIRECTION OUTPUT ;
    USE SIGNAL ;
    PORT
      LAYER M4 ;
        RECT  0 67.824 0.192 67.848 ;
    END
  END od[386]
  PIN od[387]
    DIRECTION OUTPUT ;
    USE SIGNAL ;
    PORT
      LAYER M4 ;
        RECT  0 67.968 0.192 67.992 ;
    END
  END od[387]
  PIN od[388]
    DIRECTION OUTPUT ;
    USE SIGNAL ;
    PORT
      LAYER M4 ;
        RECT  0 68.112 0.192 68.136 ;
    END
  END od[388]
  PIN od[389]
    DIRECTION OUTPUT ;
    USE SIGNAL ;
    PORT
      LAYER M4 ;
        RECT  0 68.304 0.192 68.328 ;
    END
  END od[389]
  PIN od[38]
    DIRECTION OUTPUT ;
    USE SIGNAL ;
    PORT
      LAYER M4 ;
        RECT  0 10.8 0.192 10.824 ;
    END
  END od[38]
  PIN od[390]
    DIRECTION OUTPUT ;
    USE SIGNAL ;
    PORT
      LAYER M4 ;
        RECT  0 68.448 0.192 68.472 ;
    END
  END od[390]
  PIN od[391]
    DIRECTION OUTPUT ;
    USE SIGNAL ;
    PORT
      LAYER M4 ;
        RECT  0 68.64 0.192 68.664 ;
    END
  END od[391]
  PIN od[392]
    DIRECTION OUTPUT ;
    USE SIGNAL ;
    PORT
      LAYER M4 ;
        RECT  0 68.784 0.192 68.808 ;
    END
  END od[392]
  PIN od[393]
    DIRECTION OUTPUT ;
    USE SIGNAL ;
    PORT
      LAYER M4 ;
        RECT  0 68.976 0.192 69 ;
    END
  END od[393]
  PIN od[394]
    DIRECTION OUTPUT ;
    USE SIGNAL ;
    PORT
      LAYER M4 ;
        RECT  0 69.12 0.192 69.144 ;
    END
  END od[394]
  PIN od[395]
    DIRECTION OUTPUT ;
    USE SIGNAL ;
    PORT
      LAYER M4 ;
        RECT  0 69.264 0.192 69.288 ;
    END
  END od[395]
  PIN od[396]
    DIRECTION OUTPUT ;
    USE SIGNAL ;
    PORT
      LAYER M4 ;
        RECT  0 69.456 0.192 69.48 ;
    END
  END od[396]
  PIN od[397]
    DIRECTION OUTPUT ;
    USE SIGNAL ;
    PORT
      LAYER M4 ;
        RECT  0 69.6 0.192 69.624 ;
    END
  END od[397]
  PIN od[398]
    DIRECTION OUTPUT ;
    USE SIGNAL ;
    PORT
      LAYER M4 ;
        RECT  0 69.792 0.192 69.816 ;
    END
  END od[398]
  PIN od[399]
    DIRECTION OUTPUT ;
    USE SIGNAL ;
    PORT
      LAYER M4 ;
        RECT  0 69.936 0.192 69.96 ;
    END
  END od[399]
  PIN od[39]
    DIRECTION OUTPUT ;
    USE SIGNAL ;
    PORT
      LAYER M4 ;
        RECT  0 10.944 0.192 10.968 ;
    END
  END od[39]
  PIN od[3]
    DIRECTION OUTPUT ;
    USE SIGNAL ;
    PORT
      LAYER M4 ;
        RECT  0 5.088 0.192 5.112 ;
    END
  END od[3]
  PIN od[400]
    DIRECTION OUTPUT ;
    USE SIGNAL ;
    PORT
      LAYER M4 ;
        RECT  0 70.08 0.192 70.104 ;
    END
  END od[400]
  PIN od[401]
    DIRECTION OUTPUT ;
    USE SIGNAL ;
    PORT
      LAYER M4 ;
        RECT  0 70.272 0.192 70.296 ;
    END
  END od[401]
  PIN od[402]
    DIRECTION OUTPUT ;
    USE SIGNAL ;
    PORT
      LAYER M4 ;
        RECT  0 70.416 0.192 70.44 ;
    END
  END od[402]
  PIN od[403]
    DIRECTION OUTPUT ;
    USE SIGNAL ;
    PORT
      LAYER M4 ;
        RECT  0 70.608 0.192 70.632 ;
    END
  END od[403]
  PIN od[404]
    DIRECTION OUTPUT ;
    USE SIGNAL ;
    PORT
      LAYER M4 ;
        RECT  0 70.752 0.192 70.776 ;
    END
  END od[404]
  PIN od[405]
    DIRECTION OUTPUT ;
    USE SIGNAL ;
    PORT
      LAYER M4 ;
        RECT  0 70.944 0.192 70.968 ;
    END
  END od[405]
  PIN od[406]
    DIRECTION OUTPUT ;
    USE SIGNAL ;
    PORT
      LAYER M4 ;
        RECT  0 71.088 0.192 71.112 ;
    END
  END od[406]
  PIN od[407]
    DIRECTION OUTPUT ;
    USE SIGNAL ;
    PORT
      LAYER M4 ;
        RECT  0 71.232 0.192 71.256 ;
    END
  END od[407]
  PIN od[408]
    DIRECTION OUTPUT ;
    USE SIGNAL ;
    PORT
      LAYER M4 ;
        RECT  0 71.424 0.192 71.448 ;
    END
  END od[408]
  PIN od[409]
    DIRECTION OUTPUT ;
    USE SIGNAL ;
    PORT
      LAYER M4 ;
        RECT  0 71.568 0.192 71.592 ;
    END
  END od[409]
  PIN od[40]
    DIRECTION OUTPUT ;
    USE SIGNAL ;
    PORT
      LAYER M4 ;
        RECT  0 11.136 0.192 11.16 ;
    END
  END od[40]
  PIN od[410]
    DIRECTION OUTPUT ;
    USE SIGNAL ;
    PORT
      LAYER M4 ;
        RECT  0 71.76 0.192 71.784 ;
    END
  END od[410]
  PIN od[411]
    DIRECTION OUTPUT ;
    USE SIGNAL ;
    PORT
      LAYER M4 ;
        RECT  0 71.904 0.192 71.928 ;
    END
  END od[411]
  PIN od[412]
    DIRECTION OUTPUT ;
    USE SIGNAL ;
    PORT
      LAYER M4 ;
        RECT  0 72.048 0.192 72.072 ;
    END
  END od[412]
  PIN od[413]
    DIRECTION OUTPUT ;
    USE SIGNAL ;
    PORT
      LAYER M4 ;
        RECT  0 72.24 0.192 72.264 ;
    END
  END od[413]
  PIN od[414]
    DIRECTION OUTPUT ;
    USE SIGNAL ;
    PORT
      LAYER M4 ;
        RECT  0 72.384 0.192 72.408 ;
    END
  END od[414]
  PIN od[415]
    DIRECTION OUTPUT ;
    USE SIGNAL ;
    PORT
      LAYER M4 ;
        RECT  0 72.576 0.192 72.6 ;
    END
  END od[415]
  PIN od[416]
    DIRECTION OUTPUT ;
    USE SIGNAL ;
    PORT
      LAYER M4 ;
        RECT  0 72.72 0.192 72.744 ;
    END
  END od[416]
  PIN od[417]
    DIRECTION OUTPUT ;
    USE SIGNAL ;
    PORT
      LAYER M4 ;
        RECT  0 72.864 0.192 72.888 ;
    END
  END od[417]
  PIN od[418]
    DIRECTION OUTPUT ;
    USE SIGNAL ;
    PORT
      LAYER M4 ;
        RECT  0 73.056 0.192 73.08 ;
    END
  END od[418]
  PIN od[419]
    DIRECTION OUTPUT ;
    USE SIGNAL ;
    PORT
      LAYER M4 ;
        RECT  0 73.2 0.192 73.224 ;
    END
  END od[419]
  PIN od[41]
    DIRECTION OUTPUT ;
    USE SIGNAL ;
    PORT
      LAYER M4 ;
        RECT  0 11.28 0.192 11.304 ;
    END
  END od[41]
  PIN od[420]
    DIRECTION OUTPUT ;
    USE SIGNAL ;
    PORT
      LAYER M4 ;
        RECT  0 73.392 0.192 73.416 ;
    END
  END od[420]
  PIN od[421]
    DIRECTION OUTPUT ;
    USE SIGNAL ;
    PORT
      LAYER M4 ;
        RECT  0 73.536 0.192 73.56 ;
    END
  END od[421]
  PIN od[422]
    DIRECTION OUTPUT ;
    USE SIGNAL ;
    PORT
      LAYER M4 ;
        RECT  0 73.728 0.192 73.752 ;
    END
  END od[422]
  PIN od[423]
    DIRECTION OUTPUT ;
    USE SIGNAL ;
    PORT
      LAYER M4 ;
        RECT  0 73.872 0.192 73.896 ;
    END
  END od[423]
  PIN od[424]
    DIRECTION OUTPUT ;
    USE SIGNAL ;
    PORT
      LAYER M4 ;
        RECT  0 74.016 0.192 74.04 ;
    END
  END od[424]
  PIN od[425]
    DIRECTION OUTPUT ;
    USE SIGNAL ;
    PORT
      LAYER M4 ;
        RECT  0 74.208 0.192 74.232 ;
    END
  END od[425]
  PIN od[426]
    DIRECTION OUTPUT ;
    USE SIGNAL ;
    PORT
      LAYER M4 ;
        RECT  0 74.352 0.192 74.376 ;
    END
  END od[426]
  PIN od[427]
    DIRECTION OUTPUT ;
    USE SIGNAL ;
    PORT
      LAYER M4 ;
        RECT  0 74.544 0.192 74.568 ;
    END
  END od[427]
  PIN od[428]
    DIRECTION OUTPUT ;
    USE SIGNAL ;
    PORT
      LAYER M4 ;
        RECT  0 74.688 0.192 74.712 ;
    END
  END od[428]
  PIN od[429]
    DIRECTION OUTPUT ;
    USE SIGNAL ;
    PORT
      LAYER M4 ;
        RECT  0 74.832 0.192 74.856 ;
    END
  END od[429]
  PIN od[42]
    DIRECTION OUTPUT ;
    USE SIGNAL ;
    PORT
      LAYER M4 ;
        RECT  0 11.472 0.192 11.496 ;
    END
  END od[42]
  PIN od[430]
    DIRECTION OUTPUT ;
    USE SIGNAL ;
    PORT
      LAYER M4 ;
        RECT  0 75.024 0.192 75.048 ;
    END
  END od[430]
  PIN od[431]
    DIRECTION OUTPUT ;
    USE SIGNAL ;
    PORT
      LAYER M4 ;
        RECT  0 75.168 0.192 75.192 ;
    END
  END od[431]
  PIN od[432]
    DIRECTION OUTPUT ;
    USE SIGNAL ;
    PORT
      LAYER M4 ;
        RECT  0 75.36 0.192 75.384 ;
    END
  END od[432]
  PIN od[433]
    DIRECTION OUTPUT ;
    USE SIGNAL ;
    PORT
      LAYER M4 ;
        RECT  0 75.504 0.192 75.528 ;
    END
  END od[433]
  PIN od[434]
    DIRECTION OUTPUT ;
    USE SIGNAL ;
    PORT
      LAYER M4 ;
        RECT  0 75.648 0.192 75.672 ;
    END
  END od[434]
  PIN od[435]
    DIRECTION OUTPUT ;
    USE SIGNAL ;
    PORT
      LAYER M4 ;
        RECT  0 75.84 0.192 75.864 ;
    END
  END od[435]
  PIN od[436]
    DIRECTION OUTPUT ;
    USE SIGNAL ;
    PORT
      LAYER M4 ;
        RECT  0 75.984 0.192 76.008 ;
    END
  END od[436]
  PIN od[437]
    DIRECTION OUTPUT ;
    USE SIGNAL ;
    PORT
      LAYER M4 ;
        RECT  0 76.176 0.192 76.2 ;
    END
  END od[437]
  PIN od[438]
    DIRECTION OUTPUT ;
    USE SIGNAL ;
    PORT
      LAYER M4 ;
        RECT  0 76.32 0.192 76.344 ;
    END
  END od[438]
  PIN od[439]
    DIRECTION OUTPUT ;
    USE SIGNAL ;
    PORT
      LAYER M4 ;
        RECT  0 76.512 0.192 76.536 ;
    END
  END od[439]
  PIN od[43]
    DIRECTION OUTPUT ;
    USE SIGNAL ;
    PORT
      LAYER M4 ;
        RECT  0 11.616 0.192 11.64 ;
    END
  END od[43]
  PIN od[440]
    DIRECTION OUTPUT ;
    USE SIGNAL ;
    PORT
      LAYER M4 ;
        RECT  0 76.656 0.192 76.68 ;
    END
  END od[440]
  PIN od[441]
    DIRECTION OUTPUT ;
    USE SIGNAL ;
    PORT
      LAYER M4 ;
        RECT  0 76.8 0.192 76.824 ;
    END
  END od[441]
  PIN od[442]
    DIRECTION OUTPUT ;
    USE SIGNAL ;
    PORT
      LAYER M4 ;
        RECT  0 76.992 0.192 77.016 ;
    END
  END od[442]
  PIN od[443]
    DIRECTION OUTPUT ;
    USE SIGNAL ;
    PORT
      LAYER M4 ;
        RECT  0 77.136 0.192 77.16 ;
    END
  END od[443]
  PIN od[444]
    DIRECTION OUTPUT ;
    USE SIGNAL ;
    PORT
      LAYER M4 ;
        RECT  0 77.328 0.192 77.352 ;
    END
  END od[444]
  PIN od[445]
    DIRECTION OUTPUT ;
    USE SIGNAL ;
    PORT
      LAYER M4 ;
        RECT  0 77.472 0.192 77.496 ;
    END
  END od[445]
  PIN od[446]
    DIRECTION OUTPUT ;
    USE SIGNAL ;
    PORT
      LAYER M4 ;
        RECT  0 77.616 0.192 77.64 ;
    END
  END od[446]
  PIN od[447]
    DIRECTION OUTPUT ;
    USE SIGNAL ;
    PORT
      LAYER M4 ;
        RECT  0 77.808 0.192 77.832 ;
    END
  END od[447]
  PIN od[448]
    DIRECTION OUTPUT ;
    USE SIGNAL ;
    PORT
      LAYER M4 ;
        RECT  0 77.952 0.192 77.976 ;
    END
  END od[448]
  PIN od[449]
    DIRECTION OUTPUT ;
    USE SIGNAL ;
    PORT
      LAYER M4 ;
        RECT  0 78.144 0.192 78.168 ;
    END
  END od[449]
  PIN od[44]
    DIRECTION OUTPUT ;
    USE SIGNAL ;
    PORT
      LAYER M4 ;
        RECT  0 11.808 0.192 11.832 ;
    END
  END od[44]
  PIN od[450]
    DIRECTION OUTPUT ;
    USE SIGNAL ;
    PORT
      LAYER M4 ;
        RECT  0 78.288 0.192 78.312 ;
    END
  END od[450]
  PIN od[451]
    DIRECTION OUTPUT ;
    USE SIGNAL ;
    PORT
      LAYER M4 ;
        RECT  0 78.432 0.192 78.456 ;
    END
  END od[451]
  PIN od[452]
    DIRECTION OUTPUT ;
    USE SIGNAL ;
    PORT
      LAYER M4 ;
        RECT  0 78.624 0.192 78.648 ;
    END
  END od[452]
  PIN od[453]
    DIRECTION OUTPUT ;
    USE SIGNAL ;
    PORT
      LAYER M4 ;
        RECT  0 78.768 0.192 78.792 ;
    END
  END od[453]
  PIN od[454]
    DIRECTION OUTPUT ;
    USE SIGNAL ;
    PORT
      LAYER M4 ;
        RECT  0 78.96 0.192 78.984 ;
    END
  END od[454]
  PIN od[455]
    DIRECTION OUTPUT ;
    USE SIGNAL ;
    PORT
      LAYER M4 ;
        RECT  0 79.104 0.192 79.128 ;
    END
  END od[455]
  PIN od[456]
    DIRECTION OUTPUT ;
    USE SIGNAL ;
    PORT
      LAYER M4 ;
        RECT  0 79.296 0.192 79.32 ;
    END
  END od[456]
  PIN od[457]
    DIRECTION OUTPUT ;
    USE SIGNAL ;
    PORT
      LAYER M4 ;
        RECT  0 79.44 0.192 79.464 ;
    END
  END od[457]
  PIN od[458]
    DIRECTION OUTPUT ;
    USE SIGNAL ;
    PORT
      LAYER M4 ;
        RECT  0 79.584 0.192 79.608 ;
    END
  END od[458]
  PIN od[459]
    DIRECTION OUTPUT ;
    USE SIGNAL ;
    PORT
      LAYER M4 ;
        RECT  0 79.776 0.192 79.8 ;
    END
  END od[459]
  PIN od[45]
    DIRECTION OUTPUT ;
    USE SIGNAL ;
    PORT
      LAYER M4 ;
        RECT  0 11.952 0.192 11.976 ;
    END
  END od[45]
  PIN od[460]
    DIRECTION OUTPUT ;
    USE SIGNAL ;
    PORT
      LAYER M4 ;
        RECT  0 79.92 0.192 79.944 ;
    END
  END od[460]
  PIN od[461]
    DIRECTION OUTPUT ;
    USE SIGNAL ;
    PORT
      LAYER M4 ;
        RECT  0 80.112 0.192 80.136 ;
    END
  END od[461]
  PIN od[462]
    DIRECTION OUTPUT ;
    USE SIGNAL ;
    PORT
      LAYER M4 ;
        RECT  0 80.256 0.192 80.28 ;
    END
  END od[462]
  PIN od[463]
    DIRECTION OUTPUT ;
    USE SIGNAL ;
    PORT
      LAYER M4 ;
        RECT  0 80.4 0.192 80.424 ;
    END
  END od[463]
  PIN od[464]
    DIRECTION OUTPUT ;
    USE SIGNAL ;
    PORT
      LAYER M4 ;
        RECT  0 80.592 0.192 80.616 ;
    END
  END od[464]
  PIN od[465]
    DIRECTION OUTPUT ;
    USE SIGNAL ;
    PORT
      LAYER M4 ;
        RECT  0 80.736 0.192 80.76 ;
    END
  END od[465]
  PIN od[466]
    DIRECTION OUTPUT ;
    USE SIGNAL ;
    PORT
      LAYER M4 ;
        RECT  0 80.928 0.192 80.952 ;
    END
  END od[466]
  PIN od[467]
    DIRECTION OUTPUT ;
    USE SIGNAL ;
    PORT
      LAYER M4 ;
        RECT  0 81.072 0.192 81.096 ;
    END
  END od[467]
  PIN od[468]
    DIRECTION OUTPUT ;
    USE SIGNAL ;
    PORT
      LAYER M4 ;
        RECT  0 81.264 0.192 81.288 ;
    END
  END od[468]
  PIN od[469]
    DIRECTION OUTPUT ;
    USE SIGNAL ;
    PORT
      LAYER M4 ;
        RECT  0 81.408 0.192 81.432 ;
    END
  END od[469]
  PIN od[46]
    DIRECTION OUTPUT ;
    USE SIGNAL ;
    PORT
      LAYER M4 ;
        RECT  0 12.096 0.192 12.12 ;
    END
  END od[46]
  PIN od[470]
    DIRECTION OUTPUT ;
    USE SIGNAL ;
    PORT
      LAYER M4 ;
        RECT  0 81.552 0.192 81.576 ;
    END
  END od[470]
  PIN od[471]
    DIRECTION OUTPUT ;
    USE SIGNAL ;
    PORT
      LAYER M4 ;
        RECT  0 81.744 0.192 81.768 ;
    END
  END od[471]
  PIN od[472]
    DIRECTION OUTPUT ;
    USE SIGNAL ;
    PORT
      LAYER M4 ;
        RECT  0 81.888 0.192 81.912 ;
    END
  END od[472]
  PIN od[473]
    DIRECTION OUTPUT ;
    USE SIGNAL ;
    PORT
      LAYER M4 ;
        RECT  0 82.08 0.192 82.104 ;
    END
  END od[473]
  PIN od[474]
    DIRECTION OUTPUT ;
    USE SIGNAL ;
    PORT
      LAYER M4 ;
        RECT  0 82.224 0.192 82.248 ;
    END
  END od[474]
  PIN od[475]
    DIRECTION OUTPUT ;
    USE SIGNAL ;
    PORT
      LAYER M4 ;
        RECT  0 82.368 0.192 82.392 ;
    END
  END od[475]
  PIN od[476]
    DIRECTION OUTPUT ;
    USE SIGNAL ;
    PORT
      LAYER M4 ;
        RECT  0 82.56 0.192 82.584 ;
    END
  END od[476]
  PIN od[477]
    DIRECTION OUTPUT ;
    USE SIGNAL ;
    PORT
      LAYER M4 ;
        RECT  0 82.704 0.192 82.728 ;
    END
  END od[477]
  PIN od[478]
    DIRECTION OUTPUT ;
    USE SIGNAL ;
    PORT
      LAYER M4 ;
        RECT  0 82.896 0.192 82.92 ;
    END
  END od[478]
  PIN od[479]
    DIRECTION OUTPUT ;
    USE SIGNAL ;
    PORT
      LAYER M4 ;
        RECT  0 83.04 0.192 83.064 ;
    END
  END od[479]
  PIN od[47]
    DIRECTION OUTPUT ;
    USE SIGNAL ;
    PORT
      LAYER M4 ;
        RECT  0 12.288 0.192 12.312 ;
    END
  END od[47]
  PIN od[480]
    DIRECTION OUTPUT ;
    USE SIGNAL ;
    PORT
      LAYER M4 ;
        RECT  0 83.184 0.192 83.208 ;
    END
  END od[480]
  PIN od[481]
    DIRECTION OUTPUT ;
    USE SIGNAL ;
    PORT
      LAYER M4 ;
        RECT  0 83.376 0.192 83.4 ;
    END
  END od[481]
  PIN od[482]
    DIRECTION OUTPUT ;
    USE SIGNAL ;
    PORT
      LAYER M4 ;
        RECT  0 83.52 0.192 83.544 ;
    END
  END od[482]
  PIN od[483]
    DIRECTION OUTPUT ;
    USE SIGNAL ;
    PORT
      LAYER M4 ;
        RECT  0 83.712 0.192 83.736 ;
    END
  END od[483]
  PIN od[484]
    DIRECTION OUTPUT ;
    USE SIGNAL ;
    PORT
      LAYER M4 ;
        RECT  0 83.856 0.192 83.88 ;
    END
  END od[484]
  PIN od[485]
    DIRECTION OUTPUT ;
    USE SIGNAL ;
    PORT
      LAYER M4 ;
        RECT  0 84.048 0.192 84.072 ;
    END
  END od[485]
  PIN od[486]
    DIRECTION OUTPUT ;
    USE SIGNAL ;
    PORT
      LAYER M4 ;
        RECT  0 84.192 0.192 84.216 ;
    END
  END od[486]
  PIN od[487]
    DIRECTION OUTPUT ;
    USE SIGNAL ;
    PORT
      LAYER M4 ;
        RECT  0 84.336 0.192 84.36 ;
    END
  END od[487]
  PIN od[488]
    DIRECTION OUTPUT ;
    USE SIGNAL ;
    PORT
      LAYER M4 ;
        RECT  0 84.528 0.192 84.552 ;
    END
  END od[488]
  PIN od[489]
    DIRECTION OUTPUT ;
    USE SIGNAL ;
    PORT
      LAYER M4 ;
        RECT  0 84.672 0.192 84.696 ;
    END
  END od[489]
  PIN od[48]
    DIRECTION OUTPUT ;
    USE SIGNAL ;
    PORT
      LAYER M4 ;
        RECT  0 12.432 0.192 12.456 ;
    END
  END od[48]
  PIN od[490]
    DIRECTION OUTPUT ;
    USE SIGNAL ;
    PORT
      LAYER M4 ;
        RECT  0 84.864 0.192 84.888 ;
    END
  END od[490]
  PIN od[491]
    DIRECTION OUTPUT ;
    USE SIGNAL ;
    PORT
      LAYER M4 ;
        RECT  0 85.008 0.192 85.032 ;
    END
  END od[491]
  PIN od[492]
    DIRECTION OUTPUT ;
    USE SIGNAL ;
    PORT
      LAYER M4 ;
        RECT  0 85.152 0.192 85.176 ;
    END
  END od[492]
  PIN od[493]
    DIRECTION OUTPUT ;
    USE SIGNAL ;
    PORT
      LAYER M4 ;
        RECT  0 85.344 0.192 85.368 ;
    END
  END od[493]
  PIN od[494]
    DIRECTION OUTPUT ;
    USE SIGNAL ;
    PORT
      LAYER M4 ;
        RECT  0 85.488 0.192 85.512 ;
    END
  END od[494]
  PIN od[495]
    DIRECTION OUTPUT ;
    USE SIGNAL ;
    PORT
      LAYER M4 ;
        RECT  0 85.68 0.192 85.704 ;
    END
  END od[495]
  PIN od[496]
    DIRECTION OUTPUT ;
    USE SIGNAL ;
    PORT
      LAYER M4 ;
        RECT  0 85.824 0.192 85.848 ;
    END
  END od[496]
  PIN od[497]
    DIRECTION OUTPUT ;
    USE SIGNAL ;
    PORT
      LAYER M4 ;
        RECT  0 85.968 0.192 85.992 ;
    END
  END od[497]
  PIN od[498]
    DIRECTION OUTPUT ;
    USE SIGNAL ;
    PORT
      LAYER M4 ;
        RECT  0 86.16 0.192 86.184 ;
    END
  END od[498]
  PIN od[499]
    DIRECTION OUTPUT ;
    USE SIGNAL ;
    PORT
      LAYER M4 ;
        RECT  0 86.304 0.192 86.328 ;
    END
  END od[499]
  PIN od[49]
    DIRECTION OUTPUT ;
    USE SIGNAL ;
    PORT
      LAYER M4 ;
        RECT  0 12.624 0.192 12.648 ;
    END
  END od[49]
  PIN od[4]
    DIRECTION OUTPUT ;
    USE SIGNAL ;
    PORT
      LAYER M4 ;
        RECT  0 5.232 0.192 5.256 ;
    END
  END od[4]
  PIN od[500]
    DIRECTION OUTPUT ;
    USE SIGNAL ;
    PORT
      LAYER M4 ;
        RECT  0 86.496 0.192 86.52 ;
    END
  END od[500]
  PIN od[501]
    DIRECTION OUTPUT ;
    USE SIGNAL ;
    PORT
      LAYER M4 ;
        RECT  0 86.64 0.192 86.664 ;
    END
  END od[501]
  PIN od[502]
    DIRECTION OUTPUT ;
    USE SIGNAL ;
    PORT
      LAYER M4 ;
        RECT  0 86.832 0.192 86.856 ;
    END
  END od[502]
  PIN od[503]
    DIRECTION OUTPUT ;
    USE SIGNAL ;
    PORT
      LAYER M4 ;
        RECT  0 86.976 0.192 87 ;
    END
  END od[503]
  PIN od[504]
    DIRECTION OUTPUT ;
    USE SIGNAL ;
    PORT
      LAYER M4 ;
        RECT  0 87.12 0.192 87.144 ;
    END
  END od[504]
  PIN od[505]
    DIRECTION OUTPUT ;
    USE SIGNAL ;
    PORT
      LAYER M4 ;
        RECT  0 87.312 0.192 87.336 ;
    END
  END od[505]
  PIN od[506]
    DIRECTION OUTPUT ;
    USE SIGNAL ;
    PORT
      LAYER M4 ;
        RECT  0 87.456 0.192 87.48 ;
    END
  END od[506]
  PIN od[507]
    DIRECTION OUTPUT ;
    USE SIGNAL ;
    PORT
      LAYER M4 ;
        RECT  0 87.648 0.192 87.672 ;
    END
  END od[507]
  PIN od[508]
    DIRECTION OUTPUT ;
    USE SIGNAL ;
    PORT
      LAYER M4 ;
        RECT  0 87.792 0.192 87.816 ;
    END
  END od[508]
  PIN od[509]
    DIRECTION OUTPUT ;
    USE SIGNAL ;
    PORT
      LAYER M4 ;
        RECT  0 87.936 0.192 87.96 ;
    END
  END od[509]
  PIN od[50]
    DIRECTION OUTPUT ;
    USE SIGNAL ;
    PORT
      LAYER M4 ;
        RECT  0 12.768 0.192 12.792 ;
    END
  END od[50]
  PIN od[510]
    DIRECTION OUTPUT ;
    USE SIGNAL ;
    PORT
      LAYER M4 ;
        RECT  0 88.128 0.192 88.152 ;
    END
  END od[510]
  PIN od[511]
    DIRECTION OUTPUT ;
    USE SIGNAL ;
    PORT
      LAYER M4 ;
        RECT  0 88.272 0.192 88.296 ;
    END
  END od[511]
  PIN od[512]
    DIRECTION OUTPUT ;
    USE SIGNAL ;
    PORT
      LAYER M4 ;
        RECT  0 88.464 0.192 88.488 ;
    END
  END od[512]
  PIN od[513]
    DIRECTION OUTPUT ;
    USE SIGNAL ;
    PORT
      LAYER M4 ;
        RECT  0 88.608 0.192 88.632 ;
    END
  END od[513]
  PIN od[514]
    DIRECTION OUTPUT ;
    USE SIGNAL ;
    PORT
      LAYER M4 ;
        RECT  0 88.752 0.192 88.776 ;
    END
  END od[514]
  PIN od[515]
    DIRECTION OUTPUT ;
    USE SIGNAL ;
    PORT
      LAYER M4 ;
        RECT  0 88.944 0.192 88.968 ;
    END
  END od[515]
  PIN od[516]
    DIRECTION OUTPUT ;
    USE SIGNAL ;
    PORT
      LAYER M4 ;
        RECT  0 89.088 0.192 89.112 ;
    END
  END od[516]
  PIN od[517]
    DIRECTION OUTPUT ;
    USE SIGNAL ;
    PORT
      LAYER M4 ;
        RECT  0 89.28 0.192 89.304 ;
    END
  END od[517]
  PIN od[518]
    DIRECTION OUTPUT ;
    USE SIGNAL ;
    PORT
      LAYER M4 ;
        RECT  0 89.424 0.192 89.448 ;
    END
  END od[518]
  PIN od[519]
    DIRECTION OUTPUT ;
    USE SIGNAL ;
    PORT
      LAYER M4 ;
        RECT  0 89.616 0.192 89.64 ;
    END
  END od[519]
  PIN od[51]
    DIRECTION OUTPUT ;
    USE SIGNAL ;
    PORT
      LAYER M4 ;
        RECT  0 12.912 0.192 12.936 ;
    END
  END od[51]
  PIN od[520]
    DIRECTION OUTPUT ;
    USE SIGNAL ;
    PORT
      LAYER M4 ;
        RECT  0 89.76 0.192 89.784 ;
    END
  END od[520]
  PIN od[521]
    DIRECTION OUTPUT ;
    USE SIGNAL ;
    PORT
      LAYER M4 ;
        RECT  0 89.904 0.192 89.928 ;
    END
  END od[521]
  PIN od[522]
    DIRECTION OUTPUT ;
    USE SIGNAL ;
    PORT
      LAYER M4 ;
        RECT  0 90.096 0.192 90.12 ;
    END
  END od[522]
  PIN od[523]
    DIRECTION OUTPUT ;
    USE SIGNAL ;
    PORT
      LAYER M4 ;
        RECT  0 90.24 0.192 90.264 ;
    END
  END od[523]
  PIN od[524]
    DIRECTION OUTPUT ;
    USE SIGNAL ;
    PORT
      LAYER M4 ;
        RECT  0 90.432 0.192 90.456 ;
    END
  END od[524]
  PIN od[525]
    DIRECTION OUTPUT ;
    USE SIGNAL ;
    PORT
      LAYER M4 ;
        RECT  0 90.576 0.192 90.6 ;
    END
  END od[525]
  PIN od[526]
    DIRECTION OUTPUT ;
    USE SIGNAL ;
    PORT
      LAYER M4 ;
        RECT  0 90.72 0.192 90.744 ;
    END
  END od[526]
  PIN od[527]
    DIRECTION OUTPUT ;
    USE SIGNAL ;
    PORT
      LAYER M4 ;
        RECT  0 90.912 0.192 90.936 ;
    END
  END od[527]
  PIN od[528]
    DIRECTION OUTPUT ;
    USE SIGNAL ;
    PORT
      LAYER M4 ;
        RECT  0 91.056 0.192 91.08 ;
    END
  END od[528]
  PIN od[529]
    DIRECTION OUTPUT ;
    USE SIGNAL ;
    PORT
      LAYER M4 ;
        RECT  0 91.248 0.192 91.272 ;
    END
  END od[529]
  PIN od[52]
    DIRECTION OUTPUT ;
    USE SIGNAL ;
    PORT
      LAYER M4 ;
        RECT  0 13.104 0.192 13.128 ;
    END
  END od[52]
  PIN od[530]
    DIRECTION OUTPUT ;
    USE SIGNAL ;
    PORT
      LAYER M4 ;
        RECT  0 91.392 0.192 91.416 ;
    END
  END od[530]
  PIN od[531]
    DIRECTION OUTPUT ;
    USE SIGNAL ;
    PORT
      LAYER M4 ;
        RECT  0 91.584 0.192 91.608 ;
    END
  END od[531]
  PIN od[532]
    DIRECTION OUTPUT ;
    USE SIGNAL ;
    PORT
      LAYER M4 ;
        RECT  0 91.728 0.192 91.752 ;
    END
  END od[532]
  PIN od[533]
    DIRECTION OUTPUT ;
    USE SIGNAL ;
    PORT
      LAYER M4 ;
        RECT  0 91.872 0.192 91.896 ;
    END
  END od[533]
  PIN od[534]
    DIRECTION OUTPUT ;
    USE SIGNAL ;
    PORT
      LAYER M4 ;
        RECT  0 92.064 0.192 92.088 ;
    END
  END od[534]
  PIN od[535]
    DIRECTION OUTPUT ;
    USE SIGNAL ;
    PORT
      LAYER M4 ;
        RECT  0 92.208 0.192 92.232 ;
    END
  END od[535]
  PIN od[536]
    DIRECTION OUTPUT ;
    USE SIGNAL ;
    PORT
      LAYER M4 ;
        RECT  0 92.4 0.192 92.424 ;
    END
  END od[536]
  PIN od[537]
    DIRECTION OUTPUT ;
    USE SIGNAL ;
    PORT
      LAYER M4 ;
        RECT  0 92.544 0.192 92.568 ;
    END
  END od[537]
  PIN od[538]
    DIRECTION OUTPUT ;
    USE SIGNAL ;
    PORT
      LAYER M4 ;
        RECT  0 92.688 0.192 92.712 ;
    END
  END od[538]
  PIN od[539]
    DIRECTION OUTPUT ;
    USE SIGNAL ;
    PORT
      LAYER M4 ;
        RECT  0 92.88 0.192 92.904 ;
    END
  END od[539]
  PIN od[53]
    DIRECTION OUTPUT ;
    USE SIGNAL ;
    PORT
      LAYER M4 ;
        RECT  0 13.248 0.192 13.272 ;
    END
  END od[53]
  PIN od[540]
    DIRECTION OUTPUT ;
    USE SIGNAL ;
    PORT
      LAYER M4 ;
        RECT  0 93.024 0.192 93.048 ;
    END
  END od[540]
  PIN od[541]
    DIRECTION OUTPUT ;
    USE SIGNAL ;
    PORT
      LAYER M4 ;
        RECT  0 93.216 0.192 93.24 ;
    END
  END od[541]
  PIN od[542]
    DIRECTION OUTPUT ;
    USE SIGNAL ;
    PORT
      LAYER M4 ;
        RECT  0 93.36 0.192 93.384 ;
    END
  END od[542]
  PIN od[543]
    DIRECTION OUTPUT ;
    USE SIGNAL ;
    PORT
      LAYER M4 ;
        RECT  0 93.504 0.192 93.528 ;
    END
  END od[543]
  PIN od[544]
    DIRECTION OUTPUT ;
    USE SIGNAL ;
    PORT
      LAYER M4 ;
        RECT  0 93.696 0.192 93.72 ;
    END
  END od[544]
  PIN od[545]
    DIRECTION OUTPUT ;
    USE SIGNAL ;
    PORT
      LAYER M4 ;
        RECT  0 93.84 0.192 93.864 ;
    END
  END od[545]
  PIN od[546]
    DIRECTION OUTPUT ;
    USE SIGNAL ;
    PORT
      LAYER M4 ;
        RECT  0 94.032 0.192 94.056 ;
    END
  END od[546]
  PIN od[547]
    DIRECTION OUTPUT ;
    USE SIGNAL ;
    PORT
      LAYER M4 ;
        RECT  0 94.176 0.192 94.2 ;
    END
  END od[547]
  PIN od[548]
    DIRECTION OUTPUT ;
    USE SIGNAL ;
    PORT
      LAYER M4 ;
        RECT  0 94.368 0.192 94.392 ;
    END
  END od[548]
  PIN od[549]
    DIRECTION OUTPUT ;
    USE SIGNAL ;
    PORT
      LAYER M4 ;
        RECT  0 94.512 0.192 94.536 ;
    END
  END od[549]
  PIN od[54]
    DIRECTION OUTPUT ;
    USE SIGNAL ;
    PORT
      LAYER M4 ;
        RECT  0 13.44 0.192 13.464 ;
    END
  END od[54]
  PIN od[550]
    DIRECTION OUTPUT ;
    USE SIGNAL ;
    PORT
      LAYER M4 ;
        RECT  0 94.656 0.192 94.68 ;
    END
  END od[550]
  PIN od[551]
    DIRECTION OUTPUT ;
    USE SIGNAL ;
    PORT
      LAYER M4 ;
        RECT  0 94.848 0.192 94.872 ;
    END
  END od[551]
  PIN od[552]
    DIRECTION OUTPUT ;
    USE SIGNAL ;
    PORT
      LAYER M4 ;
        RECT  0 94.992 0.192 95.016 ;
    END
  END od[552]
  PIN od[553]
    DIRECTION OUTPUT ;
    USE SIGNAL ;
    PORT
      LAYER M4 ;
        RECT  0 95.184 0.192 95.208 ;
    END
  END od[553]
  PIN od[554]
    DIRECTION OUTPUT ;
    USE SIGNAL ;
    PORT
      LAYER M4 ;
        RECT  0 95.328 0.192 95.352 ;
    END
  END od[554]
  PIN od[555]
    DIRECTION OUTPUT ;
    USE SIGNAL ;
    PORT
      LAYER M4 ;
        RECT  0 95.472 0.192 95.496 ;
    END
  END od[555]
  PIN od[556]
    DIRECTION OUTPUT ;
    USE SIGNAL ;
    PORT
      LAYER M4 ;
        RECT  0 95.664 0.192 95.688 ;
    END
  END od[556]
  PIN od[557]
    DIRECTION OUTPUT ;
    USE SIGNAL ;
    PORT
      LAYER M4 ;
        RECT  0 95.808 0.192 95.832 ;
    END
  END od[557]
  PIN od[558]
    DIRECTION OUTPUT ;
    USE SIGNAL ;
    PORT
      LAYER M4 ;
        RECT  0 96 0.192 96.024 ;
    END
  END od[558]
  PIN od[559]
    DIRECTION OUTPUT ;
    USE SIGNAL ;
    PORT
      LAYER M4 ;
        RECT  0 96.144 0.192 96.168 ;
    END
  END od[559]
  PIN od[55]
    DIRECTION OUTPUT ;
    USE SIGNAL ;
    PORT
      LAYER M4 ;
        RECT  0 13.584 0.192 13.608 ;
    END
  END od[55]
  PIN od[560]
    DIRECTION OUTPUT ;
    USE SIGNAL ;
    PORT
      LAYER M4 ;
        RECT  0 96.288 0.192 96.312 ;
    END
  END od[560]
  PIN od[561]
    DIRECTION OUTPUT ;
    USE SIGNAL ;
    PORT
      LAYER M4 ;
        RECT  0 96.48 0.192 96.504 ;
    END
  END od[561]
  PIN od[562]
    DIRECTION OUTPUT ;
    USE SIGNAL ;
    PORT
      LAYER M4 ;
        RECT  0 96.624 0.192 96.648 ;
    END
  END od[562]
  PIN od[563]
    DIRECTION OUTPUT ;
    USE SIGNAL ;
    PORT
      LAYER M4 ;
        RECT  0 96.816 0.192 96.84 ;
    END
  END od[563]
  PIN od[564]
    DIRECTION OUTPUT ;
    USE SIGNAL ;
    PORT
      LAYER M4 ;
        RECT  0 96.96 0.192 96.984 ;
    END
  END od[564]
  PIN od[565]
    DIRECTION OUTPUT ;
    USE SIGNAL ;
    PORT
      LAYER M4 ;
        RECT  0 97.152 0.192 97.176 ;
    END
  END od[565]
  PIN od[56]
    DIRECTION OUTPUT ;
    USE SIGNAL ;
    PORT
      LAYER M4 ;
        RECT  0 13.728 0.192 13.752 ;
    END
  END od[56]
  PIN od[57]
    DIRECTION OUTPUT ;
    USE SIGNAL ;
    PORT
      LAYER M4 ;
        RECT  0 13.92 0.192 13.944 ;
    END
  END od[57]
  PIN od[58]
    DIRECTION OUTPUT ;
    USE SIGNAL ;
    PORT
      LAYER M4 ;
        RECT  0 14.064 0.192 14.088 ;
    END
  END od[58]
  PIN od[59]
    DIRECTION OUTPUT ;
    USE SIGNAL ;
    PORT
      LAYER M4 ;
        RECT  0 14.256 0.192 14.28 ;
    END
  END od[59]
  PIN od[5]
    DIRECTION OUTPUT ;
    USE SIGNAL ;
    PORT
      LAYER M4 ;
        RECT  0 5.376 0.192 5.4 ;
    END
  END od[5]
  PIN od[60]
    DIRECTION OUTPUT ;
    USE SIGNAL ;
    PORT
      LAYER M4 ;
        RECT  0 14.4 0.192 14.424 ;
    END
  END od[60]
  PIN od[61]
    DIRECTION OUTPUT ;
    USE SIGNAL ;
    PORT
      LAYER M4 ;
        RECT  0 14.592 0.192 14.616 ;
    END
  END od[61]
  PIN od[62]
    DIRECTION OUTPUT ;
    USE SIGNAL ;
    PORT
      LAYER M4 ;
        RECT  0 14.736 0.192 14.76 ;
    END
  END od[62]
  PIN od[63]
    DIRECTION OUTPUT ;
    USE SIGNAL ;
    PORT
      LAYER M4 ;
        RECT  0 14.88 0.192 14.904 ;
    END
  END od[63]
  PIN od[64]
    DIRECTION OUTPUT ;
    USE SIGNAL ;
    PORT
      LAYER M4 ;
        RECT  0 15.072 0.192 15.096 ;
    END
  END od[64]
  PIN od[65]
    DIRECTION OUTPUT ;
    USE SIGNAL ;
    PORT
      LAYER M4 ;
        RECT  0 15.216 0.192 15.24 ;
    END
  END od[65]
  PIN od[66]
    DIRECTION OUTPUT ;
    USE SIGNAL ;
    PORT
      LAYER M4 ;
        RECT  0 15.408 0.192 15.432 ;
    END
  END od[66]
  PIN od[67]
    DIRECTION OUTPUT ;
    USE SIGNAL ;
    PORT
      LAYER M4 ;
        RECT  0 15.552 0.192 15.576 ;
    END
  END od[67]
  PIN od[68]
    DIRECTION OUTPUT ;
    USE SIGNAL ;
    PORT
      LAYER M4 ;
        RECT  0 15.696 0.192 15.72 ;
    END
  END od[68]
  PIN od[69]
    DIRECTION OUTPUT ;
    USE SIGNAL ;
    PORT
      LAYER M4 ;
        RECT  0 15.888 0.192 15.912 ;
    END
  END od[69]
  PIN od[6]
    DIRECTION OUTPUT ;
    USE SIGNAL ;
    PORT
      LAYER M4 ;
        RECT  0 5.568 0.192 5.592 ;
    END
  END od[6]
  PIN od[70]
    DIRECTION OUTPUT ;
    USE SIGNAL ;
    PORT
      LAYER M4 ;
        RECT  0 16.032 0.192 16.056 ;
    END
  END od[70]
  PIN od[71]
    DIRECTION OUTPUT ;
    USE SIGNAL ;
    PORT
      LAYER M4 ;
        RECT  0 16.224 0.192 16.248 ;
    END
  END od[71]
  PIN od[72]
    DIRECTION OUTPUT ;
    USE SIGNAL ;
    PORT
      LAYER M4 ;
        RECT  0 16.368 0.192 16.392 ;
    END
  END od[72]
  PIN od[73]
    DIRECTION OUTPUT ;
    USE SIGNAL ;
    PORT
      LAYER M4 ;
        RECT  0 16.512 0.192 16.536 ;
    END
  END od[73]
  PIN od[74]
    DIRECTION OUTPUT ;
    USE SIGNAL ;
    PORT
      LAYER M4 ;
        RECT  0 16.704 0.192 16.728 ;
    END
  END od[74]
  PIN od[75]
    DIRECTION OUTPUT ;
    USE SIGNAL ;
    PORT
      LAYER M4 ;
        RECT  0 16.848 0.192 16.872 ;
    END
  END od[75]
  PIN od[76]
    DIRECTION OUTPUT ;
    USE SIGNAL ;
    PORT
      LAYER M4 ;
        RECT  0 17.04 0.192 17.064 ;
    END
  END od[76]
  PIN od[77]
    DIRECTION OUTPUT ;
    USE SIGNAL ;
    PORT
      LAYER M4 ;
        RECT  0 17.184 0.192 17.208 ;
    END
  END od[77]
  PIN od[78]
    DIRECTION OUTPUT ;
    USE SIGNAL ;
    PORT
      LAYER M4 ;
        RECT  0 17.376 0.192 17.4 ;
    END
  END od[78]
  PIN od[79]
    DIRECTION OUTPUT ;
    USE SIGNAL ;
    PORT
      LAYER M4 ;
        RECT  0 17.52 0.192 17.544 ;
    END
  END od[79]
  PIN od[7]
    DIRECTION OUTPUT ;
    USE SIGNAL ;
    PORT
      LAYER M4 ;
        RECT  0 5.712 0.192 5.736 ;
    END
  END od[7]
  PIN od[80]
    DIRECTION OUTPUT ;
    USE SIGNAL ;
    PORT
      LAYER M4 ;
        RECT  0 17.664 0.192 17.688 ;
    END
  END od[80]
  PIN od[81]
    DIRECTION OUTPUT ;
    USE SIGNAL ;
    PORT
      LAYER M4 ;
        RECT  0 17.856 0.192 17.88 ;
    END
  END od[81]
  PIN od[82]
    DIRECTION OUTPUT ;
    USE SIGNAL ;
    PORT
      LAYER M4 ;
        RECT  0 18 0.192 18.024 ;
    END
  END od[82]
  PIN od[83]
    DIRECTION OUTPUT ;
    USE SIGNAL ;
    PORT
      LAYER M4 ;
        RECT  0 18.192 0.192 18.216 ;
    END
  END od[83]
  PIN od[84]
    DIRECTION OUTPUT ;
    USE SIGNAL ;
    PORT
      LAYER M4 ;
        RECT  0 18.336 0.192 18.36 ;
    END
  END od[84]
  PIN od[85]
    DIRECTION OUTPUT ;
    USE SIGNAL ;
    PORT
      LAYER M4 ;
        RECT  0 18.48 0.192 18.504 ;
    END
  END od[85]
  PIN od[86]
    DIRECTION OUTPUT ;
    USE SIGNAL ;
    PORT
      LAYER M4 ;
        RECT  0 18.672 0.192 18.696 ;
    END
  END od[86]
  PIN od[87]
    DIRECTION OUTPUT ;
    USE SIGNAL ;
    PORT
      LAYER M4 ;
        RECT  0 18.816 0.192 18.84 ;
    END
  END od[87]
  PIN od[88]
    DIRECTION OUTPUT ;
    USE SIGNAL ;
    PORT
      LAYER M4 ;
        RECT  0 19.008 0.192 19.032 ;
    END
  END od[88]
  PIN od[89]
    DIRECTION OUTPUT ;
    USE SIGNAL ;
    PORT
      LAYER M4 ;
        RECT  0 19.152 0.192 19.176 ;
    END
  END od[89]
  PIN od[8]
    DIRECTION OUTPUT ;
    USE SIGNAL ;
    PORT
      LAYER M4 ;
        RECT  0 5.904 0.192 5.928 ;
    END
  END od[8]
  PIN od[90]
    DIRECTION OUTPUT ;
    USE SIGNAL ;
    PORT
      LAYER M4 ;
        RECT  0 19.344 0.192 19.368 ;
    END
  END od[90]
  PIN od[91]
    DIRECTION OUTPUT ;
    USE SIGNAL ;
    PORT
      LAYER M4 ;
        RECT  0 19.488 0.192 19.512 ;
    END
  END od[91]
  PIN od[92]
    DIRECTION OUTPUT ;
    USE SIGNAL ;
    PORT
      LAYER M4 ;
        RECT  0 19.632 0.192 19.656 ;
    END
  END od[92]
  PIN od[93]
    DIRECTION OUTPUT ;
    USE SIGNAL ;
    PORT
      LAYER M4 ;
        RECT  0 19.824 0.192 19.848 ;
    END
  END od[93]
  PIN od[94]
    DIRECTION OUTPUT ;
    USE SIGNAL ;
    PORT
      LAYER M4 ;
        RECT  0 19.968 0.192 19.992 ;
    END
  END od[94]
  PIN od[95]
    DIRECTION OUTPUT ;
    USE SIGNAL ;
    PORT
      LAYER M4 ;
        RECT  0 20.16 0.192 20.184 ;
    END
  END od[95]
  PIN od[96]
    DIRECTION OUTPUT ;
    USE SIGNAL ;
    PORT
      LAYER M4 ;
        RECT  0 20.304 0.192 20.328 ;
    END
  END od[96]
  PIN od[97]
    DIRECTION OUTPUT ;
    USE SIGNAL ;
    PORT
      LAYER M4 ;
        RECT  0 20.448 0.192 20.472 ;
    END
  END od[97]
  PIN od[98]
    DIRECTION OUTPUT ;
    USE SIGNAL ;
    PORT
      LAYER M4 ;
        RECT  0 20.64 0.192 20.664 ;
    END
  END od[98]
  PIN od[99]
    DIRECTION OUTPUT ;
    USE SIGNAL ;
    PORT
      LAYER M4 ;
        RECT  0 20.784 0.192 20.808 ;
    END
  END od[99]
  PIN od[9]
    DIRECTION OUTPUT ;
    USE SIGNAL ;
    PORT
      LAYER M4 ;
        RECT  0 6.048 0.192 6.072 ;
    END
  END od[9]
  PIN rs[0]
    DIRECTION INPUT ;
    USE SIGNAL ;
    PORT
      LAYER M3 ;
        RECT  43.452 0 43.47 0.144 ;
    END
    PORT
      LAYER M3 ;
        RECT  43.452 0.108 43.47 2.143 ;
    END
  END rs[0]
  PIN rss[0]
    DIRECTION INPUT ;
    USE SIGNAL ;
    PORT
      LAYER M5 ;
        RECT  59.136 0 59.16 0.192 ;
    END
    PORT
      LAYER M5 ;
        RECT  59.136 0.144 59.16 2.137 ;
    END
  END rss[0]
  PIN st[0]
    DIRECTION OUTPUT ;
    USE SIGNAL ;
    PORT
      LAYER M4 ;
        RECT  71.088 96.816 71.28 96.84 ;
    END
  END st[0]
  PIN st[1]
    DIRECTION OUTPUT ;
    USE SIGNAL ;
    PORT
      LAYER M4 ;
        RECT  71.088 96.96 71.28 96.984 ;
    END
  END st[1]
  PIN st[2]
    DIRECTION OUTPUT ;
    USE SIGNAL ;
    PORT
      LAYER M4 ;
        RECT  71.088 97.152 71.28 97.176 ;
    END
  END st[2]
  PIN VDD
    DIRECTION INOUT ;
    USE POWER ;
    PORT
      LAYER M5 ;
        RECT  67.392 2.151 67.512 99.369 ;
        RECT  64.692 2.151 64.812 99.369 ;
        RECT  61.992 2.151 62.112 99.369 ;
        RECT  59.292 2.151 59.412 99.369 ;
        RECT  56.592 2.151 56.712 99.369 ;
        RECT  53.892 2.151 54.012 99.369 ;
        RECT  51.192 2.151 51.312 99.369 ;
        RECT  48.492 2.151 48.612 99.369 ;
        RECT  45.792 2.151 45.912 99.369 ;
        RECT  43.092 2.151 43.212 99.369 ;
        RECT  40.392 2.151 40.512 99.369 ;
        RECT  37.692 2.151 37.812 99.369 ;
        RECT  34.992 2.151 35.112 99.369 ;
        RECT  32.292 2.151 32.412 99.369 ;
        RECT  29.592 2.151 29.712 99.369 ;
        RECT  26.892 2.151 27.012 99.369 ;
        RECT  24.192 2.151 24.312 99.369 ;
        RECT  21.492 2.151 21.612 99.369 ;
        RECT  18.792 2.151 18.912 99.369 ;
        RECT  16.092 2.151 16.212 99.369 ;
        RECT  13.392 2.151 13.512 99.369 ;
        RECT  10.692 2.151 10.812 99.369 ;
        RECT  7.992 2.151 8.112 99.369 ;
        RECT  5.292 2.151 5.412 99.369 ;
        RECT  2.592 2.151 2.712 99.369 ;
    END
  END VDD
  PIN VSS
    DIRECTION INOUT ;
    USE GROUND ;
    PORT
      LAYER M5 ;
        RECT  67.2 2.137 67.32 99.383 ;
        RECT  64.5 2.137 64.62 99.383 ;
        RECT  61.8 2.137 61.92 99.383 ;
        RECT  59.1 2.137 59.22 99.383 ;
        RECT  56.4 2.137 56.52 99.383 ;
        RECT  53.7 2.137 53.82 99.383 ;
        RECT  51 2.137 51.12 99.383 ;
        RECT  48.3 2.137 48.42 99.383 ;
        RECT  45.6 2.137 45.72 99.383 ;
        RECT  42.9 2.137 43.02 99.383 ;
        RECT  40.2 2.137 40.32 99.383 ;
        RECT  37.5 2.137 37.62 99.383 ;
        RECT  34.8 2.137 34.92 99.383 ;
        RECT  32.1 2.137 32.22 99.383 ;
        RECT  29.4 2.137 29.52 99.383 ;
        RECT  26.7 2.137 26.82 99.383 ;
        RECT  24 2.137 24.12 99.383 ;
        RECT  21.3 2.137 21.42 99.383 ;
        RECT  18.6 2.137 18.72 99.383 ;
        RECT  15.9 2.137 16.02 99.383 ;
        RECT  13.2 2.137 13.32 99.383 ;
        RECT  10.5 2.137 10.62 99.383 ;
        RECT  7.8 2.137 7.92 99.383 ;
        RECT  5.1 2.137 5.22 99.383 ;
        RECT  2.4 2.137 2.52 99.383 ;
    END
  END VSS
  # OT_OBS_CLOSED layer=M5 d_um=1.536 added=87
  OBS
    LAYER RVTN ;
     RECT  2.16 2.16 69.12 2.295 ;
     RECT  2.16 2.565 69.12 2.835 ;
     RECT  2.16 3.105 69.12 3.375 ;
     RECT  2.16 3.645 69.12 3.915 ;
     RECT  2.16 4.185 69.12 4.455 ;
     RECT  2.16 4.725 69.12 4.995 ;
     RECT  2.16 5.265 69.12 5.535 ;
     RECT  2.16 5.805 69.12 6.075 ;
     RECT  2.16 6.345 69.12 6.615 ;
     RECT  2.16 6.885 69.12 7.155 ;
     RECT  2.16 7.425 69.12 7.695 ;
     RECT  2.16 7.965 69.12 8.235 ;
     RECT  2.16 8.505 69.12 8.775 ;
     RECT  2.16 9.045 69.12 9.315 ;
     RECT  2.16 9.585 69.12 9.855 ;
     RECT  2.16 10.125 69.12 10.395 ;
     RECT  2.16 10.665 69.12 10.935 ;
     RECT  2.16 11.205 69.12 11.475 ;
     RECT  2.16 11.745 69.12 12.015 ;
     RECT  2.16 12.285 69.12 12.555 ;
     RECT  2.16 12.825 69.12 13.095 ;
     RECT  2.16 13.365 69.12 13.635 ;
     RECT  2.16 13.905 69.12 14.175 ;
     RECT  2.16 14.445 69.12 14.715 ;
     RECT  2.16 14.985 69.12 15.255 ;
     RECT  2.16 15.525 69.12 15.795 ;
     RECT  2.16 16.065 69.12 16.335 ;
     RECT  2.16 16.605 69.12 16.875 ;
     RECT  2.16 17.145 69.12 17.415 ;
     RECT  2.16 17.685 69.12 17.955 ;
     RECT  2.16 18.225 69.12 18.495 ;
     RECT  2.16 18.765 69.12 19.035 ;
     RECT  2.16 19.305 69.12 19.575 ;
     RECT  2.16 19.845 69.12 20.115 ;
     RECT  2.16 20.385 69.12 20.655 ;
     RECT  2.16 20.925 69.12 21.195 ;
     RECT  2.16 21.465 69.12 21.735 ;
     RECT  2.16 22.005 69.12 22.275 ;
     RECT  2.16 22.545 69.12 22.815 ;
     RECT  2.16 23.085 69.12 23.355 ;
     RECT  2.16 23.625 69.12 23.895 ;
     RECT  2.16 24.165 69.12 24.435 ;
     RECT  2.16 24.705 69.12 24.975 ;
     RECT  2.16 25.245 69.12 25.515 ;
     RECT  2.16 25.785 69.12 26.055 ;
     RECT  2.16 26.325 69.12 26.595 ;
     RECT  2.16 26.865 69.12 27.135 ;
     RECT  2.16 27.405 69.12 27.675 ;
     RECT  2.16 27.945 69.12 28.215 ;
     RECT  2.16 28.485 69.12 28.755 ;
     RECT  2.16 29.025 69.12 29.295 ;
     RECT  2.16 29.565 69.12 29.835 ;
     RECT  2.16 30.105 69.12 30.375 ;
     RECT  2.16 30.645 69.12 30.915 ;
     RECT  2.16 31.185 69.12 31.455 ;
     RECT  2.16 31.725 69.12 31.995 ;
     RECT  2.16 32.265 69.12 32.535 ;
     RECT  2.16 32.805 69.12 33.075 ;
     RECT  2.16 33.345 69.12 33.615 ;
     RECT  2.16 33.885 69.12 34.155 ;
     RECT  2.16 34.425 69.12 34.695 ;
     RECT  2.16 34.965 69.12 35.235 ;
     RECT  2.16 35.505 69.12 35.775 ;
     RECT  2.16 36.045 69.12 36.315 ;
     RECT  2.16 36.585 69.12 36.855 ;
     RECT  2.16 37.125 69.12 37.395 ;
     RECT  2.16 37.665 69.12 37.935 ;
     RECT  2.16 38.205 69.12 38.475 ;
     RECT  2.16 38.745 69.12 39.015 ;
     RECT  2.16 39.285 69.12 39.555 ;
     RECT  2.16 39.825 69.12 40.095 ;
     RECT  2.16 40.365 69.12 40.635 ;
     RECT  2.16 40.905 69.12 41.175 ;
     RECT  2.16 41.445 69.12 41.715 ;
     RECT  2.16 41.985 69.12 42.255 ;
     RECT  2.16 42.525 69.12 42.795 ;
     RECT  2.16 43.065 69.12 43.335 ;
     RECT  2.16 43.605 69.12 43.875 ;
     RECT  2.16 44.145 69.12 44.415 ;
     RECT  2.16 44.685 69.12 44.955 ;
     RECT  2.16 45.225 69.12 45.495 ;
     RECT  2.16 45.765 69.12 46.035 ;
     RECT  2.16 46.305 69.12 46.575 ;
     RECT  2.16 46.845 69.12 47.115 ;
     RECT  2.16 47.385 69.12 47.655 ;
     RECT  2.16 47.925 69.12 48.195 ;
     RECT  2.16 48.465 69.12 48.735 ;
     RECT  2.16 49.005 69.12 49.275 ;
     RECT  2.16 49.545 69.12 49.815 ;
     RECT  2.16 50.085 69.12 50.355 ;
     RECT  2.16 50.625 69.12 50.895 ;
     RECT  2.16 51.165 69.12 51.435 ;
     RECT  2.16 51.705 69.12 51.975 ;
     RECT  2.16 52.245 69.12 52.515 ;
     RECT  2.16 52.785 69.12 53.055 ;
     RECT  2.16 53.325 69.12 53.595 ;
     RECT  2.16 53.865 69.12 54.135 ;
     RECT  2.16 54.405 69.12 54.675 ;
     RECT  2.16 54.945 69.12 55.215 ;
     RECT  2.16 55.485 69.12 55.755 ;
     RECT  2.16 56.025 69.12 56.295 ;
     RECT  2.16 56.565 69.12 56.835 ;
     RECT  2.16 57.105 69.12 57.375 ;
     RECT  2.16 57.645 69.12 57.915 ;
     RECT  2.16 58.185 69.12 58.455 ;
     RECT  2.16 58.725 69.12 58.995 ;
     RECT  2.16 59.265 69.12 59.535 ;
     RECT  2.16 59.805 69.12 60.075 ;
     RECT  2.16 60.345 69.12 60.615 ;
     RECT  2.16 60.885 69.12 61.155 ;
     RECT  2.16 61.425 69.12 61.695 ;
     RECT  2.16 61.965 69.12 62.235 ;
     RECT  2.16 62.505 69.12 62.775 ;
     RECT  2.16 63.045 69.12 63.315 ;
     RECT  2.16 63.585 69.12 63.855 ;
     RECT  2.16 64.125 69.12 64.395 ;
     RECT  2.16 64.665 69.12 64.935 ;
     RECT  2.16 65.205 69.12 65.475 ;
     RECT  2.16 65.745 69.12 66.015 ;
     RECT  2.16 66.285 69.12 66.555 ;
     RECT  2.16 66.825 69.12 67.095 ;
     RECT  2.16 67.365 69.12 67.635 ;
     RECT  2.16 67.905 69.12 68.175 ;
     RECT  2.16 68.445 69.12 68.715 ;
     RECT  2.16 68.985 69.12 69.255 ;
     RECT  2.16 69.525 69.12 69.795 ;
     RECT  2.16 70.065 69.12 70.335 ;
     RECT  2.16 70.605 69.12 70.875 ;
     RECT  2.16 71.145 69.12 71.415 ;
     RECT  2.16 71.685 69.12 71.955 ;
     RECT  2.16 72.225 69.12 72.495 ;
     RECT  2.16 72.765 69.12 73.035 ;
     RECT  2.16 73.305 69.12 73.575 ;
     RECT  2.16 73.845 69.12 74.115 ;
     RECT  2.16 74.385 69.12 74.655 ;
     RECT  2.16 74.925 69.12 75.195 ;
     RECT  2.16 75.465 69.12 75.735 ;
     RECT  2.16 76.005 69.12 76.275 ;
     RECT  2.16 76.545 69.12 76.815 ;
     RECT  2.16 77.085 69.12 77.355 ;
     RECT  2.16 77.625 69.12 77.895 ;
     RECT  2.16 78.165 69.12 78.435 ;
     RECT  2.16 78.705 69.12 78.975 ;
     RECT  2.16 79.245 69.12 79.515 ;
     RECT  2.16 79.785 69.12 80.055 ;
     RECT  2.16 80.325 69.12 80.595 ;
     RECT  2.16 80.865 69.12 81.135 ;
     RECT  2.16 81.405 69.12 81.675 ;
     RECT  2.16 81.945 69.12 82.215 ;
     RECT  2.16 82.485 69.12 82.755 ;
     RECT  2.16 83.025 69.12 83.295 ;
     RECT  2.16 83.565 69.12 83.835 ;
     RECT  2.16 84.105 69.12 84.375 ;
     RECT  2.16 84.645 69.12 84.915 ;
     RECT  2.16 85.185 69.12 85.455 ;
     RECT  2.16 85.725 69.12 85.995 ;
     RECT  2.16 86.265 69.12 86.535 ;
     RECT  2.16 86.805 69.12 87.075 ;
     RECT  2.16 87.345 69.12 87.615 ;
     RECT  2.16 87.885 69.12 88.155 ;
     RECT  2.16 88.425 69.12 88.695 ;
     RECT  2.16 88.965 69.12 89.235 ;
     RECT  2.16 89.505 69.12 89.775 ;
     RECT  2.16 90.045 69.12 90.315 ;
     RECT  2.16 90.585 69.12 90.855 ;
     RECT  2.16 91.125 69.12 91.395 ;
     RECT  2.16 91.665 69.12 91.935 ;
     RECT  2.16 92.205 69.12 92.475 ;
     RECT  2.16 92.745 69.12 93.015 ;
     RECT  2.16 93.285 69.12 93.555 ;
     RECT  2.16 93.825 69.12 94.095 ;
     RECT  2.16 94.365 69.12 94.635 ;
     RECT  2.16 94.905 69.12 95.175 ;
     RECT  2.16 95.445 69.12 95.715 ;
     RECT  2.16 95.985 69.12 96.255 ;
     RECT  2.16 96.525 69.12 96.795 ;
     RECT  2.16 97.065 69.12 97.335 ;
     RECT  2.16 97.605 69.12 97.875 ;
     RECT  2.16 98.145 69.12 98.415 ;
     RECT  2.16 98.685 69.12 98.955 ;
     RECT  2.16 99.225 69.12 99.36 ;
    LAYER RVTP ;
     RECT  2.16 2.295 69.12 2.565 ;
     RECT  2.16 2.835 69.12 3.105 ;
     RECT  2.16 3.375 69.12 3.645 ;
     RECT  2.16 3.915 69.12 4.185 ;
     RECT  2.16 4.455 69.12 4.725 ;
     RECT  2.16 4.995 69.12 5.265 ;
     RECT  2.16 5.535 69.12 5.805 ;
     RECT  2.16 6.075 69.12 6.345 ;
     RECT  2.16 6.615 69.12 6.885 ;
     RECT  2.16 7.155 69.12 7.425 ;
     RECT  2.16 7.695 69.12 7.965 ;
     RECT  2.16 8.235 69.12 8.505 ;
     RECT  2.16 8.775 69.12 9.045 ;
     RECT  2.16 9.315 69.12 9.585 ;
     RECT  2.16 9.855 69.12 10.125 ;
     RECT  2.16 10.395 69.12 10.665 ;
     RECT  2.16 10.935 69.12 11.205 ;
     RECT  2.16 11.475 69.12 11.745 ;
     RECT  2.16 12.015 69.12 12.285 ;
     RECT  2.16 12.555 69.12 12.825 ;
     RECT  2.16 13.095 69.12 13.365 ;
     RECT  2.16 13.635 69.12 13.905 ;
     RECT  2.16 14.175 69.12 14.445 ;
     RECT  2.16 14.715 69.12 14.985 ;
     RECT  2.16 15.255 69.12 15.525 ;
     RECT  2.16 15.795 69.12 16.065 ;
     RECT  2.16 16.335 69.12 16.605 ;
     RECT  2.16 16.875 69.12 17.145 ;
     RECT  2.16 17.415 69.12 17.685 ;
     RECT  2.16 17.955 69.12 18.225 ;
     RECT  2.16 18.495 69.12 18.765 ;
     RECT  2.16 19.035 69.12 19.305 ;
     RECT  2.16 19.575 69.12 19.845 ;
     RECT  2.16 20.115 69.12 20.385 ;
     RECT  2.16 20.655 69.12 20.925 ;
     RECT  2.16 21.195 69.12 21.465 ;
     RECT  2.16 21.735 69.12 22.005 ;
     RECT  2.16 22.275 69.12 22.545 ;
     RECT  2.16 22.815 69.12 23.085 ;
     RECT  2.16 23.355 69.12 23.625 ;
     RECT  2.16 23.895 69.12 24.165 ;
     RECT  2.16 24.435 69.12 24.705 ;
     RECT  2.16 24.975 69.12 25.245 ;
     RECT  2.16 25.515 69.12 25.785 ;
     RECT  2.16 26.055 69.12 26.325 ;
     RECT  2.16 26.595 69.12 26.865 ;
     RECT  2.16 27.135 69.12 27.405 ;
     RECT  2.16 27.675 69.12 27.945 ;
     RECT  2.16 28.215 69.12 28.485 ;
     RECT  2.16 28.755 69.12 29.025 ;
     RECT  2.16 29.295 69.12 29.565 ;
     RECT  2.16 29.835 69.12 30.105 ;
     RECT  2.16 30.375 69.12 30.645 ;
     RECT  2.16 30.915 69.12 31.185 ;
     RECT  2.16 31.455 69.12 31.725 ;
     RECT  2.16 31.995 69.12 32.265 ;
     RECT  2.16 32.535 69.12 32.805 ;
     RECT  2.16 33.075 69.12 33.345 ;
     RECT  2.16 33.615 69.12 33.885 ;
     RECT  2.16 34.155 69.12 34.425 ;
     RECT  2.16 34.695 69.12 34.965 ;
     RECT  2.16 35.235 69.12 35.505 ;
     RECT  2.16 35.775 69.12 36.045 ;
     RECT  2.16 36.315 69.12 36.585 ;
     RECT  2.16 36.855 69.12 37.125 ;
     RECT  2.16 37.395 69.12 37.665 ;
     RECT  2.16 37.935 69.12 38.205 ;
     RECT  2.16 38.475 69.12 38.745 ;
     RECT  2.16 39.015 69.12 39.285 ;
     RECT  2.16 39.555 69.12 39.825 ;
     RECT  2.16 40.095 69.12 40.365 ;
     RECT  2.16 40.635 69.12 40.905 ;
     RECT  2.16 41.175 69.12 41.445 ;
     RECT  2.16 41.715 69.12 41.985 ;
     RECT  2.16 42.255 69.12 42.525 ;
     RECT  2.16 42.795 69.12 43.065 ;
     RECT  2.16 43.335 69.12 43.605 ;
     RECT  2.16 43.875 69.12 44.145 ;
     RECT  2.16 44.415 69.12 44.685 ;
     RECT  2.16 44.955 69.12 45.225 ;
     RECT  2.16 45.495 69.12 45.765 ;
     RECT  2.16 46.035 69.12 46.305 ;
     RECT  2.16 46.575 69.12 46.845 ;
     RECT  2.16 47.115 69.12 47.385 ;
     RECT  2.16 47.655 69.12 47.925 ;
     RECT  2.16 48.195 69.12 48.465 ;
     RECT  2.16 48.735 69.12 49.005 ;
     RECT  2.16 49.275 69.12 49.545 ;
     RECT  2.16 49.815 69.12 50.085 ;
     RECT  2.16 50.355 69.12 50.625 ;
     RECT  2.16 50.895 69.12 51.165 ;
     RECT  2.16 51.435 69.12 51.705 ;
     RECT  2.16 51.975 69.12 52.245 ;
     RECT  2.16 52.515 69.12 52.785 ;
     RECT  2.16 53.055 69.12 53.325 ;
     RECT  2.16 53.595 69.12 53.865 ;
     RECT  2.16 54.135 69.12 54.405 ;
     RECT  2.16 54.675 69.12 54.945 ;
     RECT  2.16 55.215 69.12 55.485 ;
     RECT  2.16 55.755 69.12 56.025 ;
     RECT  2.16 56.295 69.12 56.565 ;
     RECT  2.16 56.835 69.12 57.105 ;
     RECT  2.16 57.375 69.12 57.645 ;
     RECT  2.16 57.915 69.12 58.185 ;
     RECT  2.16 58.455 69.12 58.725 ;
     RECT  2.16 58.995 69.12 59.265 ;
     RECT  2.16 59.535 69.12 59.805 ;
     RECT  2.16 60.075 69.12 60.345 ;
     RECT  2.16 60.615 69.12 60.885 ;
     RECT  2.16 61.155 69.12 61.425 ;
     RECT  2.16 61.695 69.12 61.965 ;
     RECT  2.16 62.235 69.12 62.505 ;
     RECT  2.16 62.775 69.12 63.045 ;
     RECT  2.16 63.315 69.12 63.585 ;
     RECT  2.16 63.855 69.12 64.125 ;
     RECT  2.16 64.395 69.12 64.665 ;
     RECT  2.16 64.935 69.12 65.205 ;
     RECT  2.16 65.475 69.12 65.745 ;
     RECT  2.16 66.015 69.12 66.285 ;
     RECT  2.16 66.555 69.12 66.825 ;
     RECT  2.16 67.095 69.12 67.365 ;
     RECT  2.16 67.635 69.12 67.905 ;
     RECT  2.16 68.175 69.12 68.445 ;
     RECT  2.16 68.715 69.12 68.985 ;
     RECT  2.16 69.255 69.12 69.525 ;
     RECT  2.16 69.795 69.12 70.065 ;
     RECT  2.16 70.335 69.12 70.605 ;
     RECT  2.16 70.875 69.12 71.145 ;
     RECT  2.16 71.415 69.12 71.685 ;
     RECT  2.16 71.955 69.12 72.225 ;
     RECT  2.16 72.495 69.12 72.765 ;
     RECT  2.16 73.035 69.12 73.305 ;
     RECT  2.16 73.575 69.12 73.845 ;
     RECT  2.16 74.115 69.12 74.385 ;
     RECT  2.16 74.655 69.12 74.925 ;
     RECT  2.16 75.195 69.12 75.465 ;
     RECT  2.16 75.735 69.12 76.005 ;
     RECT  2.16 76.275 69.12 76.545 ;
     RECT  2.16 76.815 69.12 77.085 ;
     RECT  2.16 77.355 69.12 77.625 ;
     RECT  2.16 77.895 69.12 78.165 ;
     RECT  2.16 78.435 69.12 78.705 ;
     RECT  2.16 78.975 69.12 79.245 ;
     RECT  2.16 79.515 69.12 79.785 ;
     RECT  2.16 80.055 69.12 80.325 ;
     RECT  2.16 80.595 69.12 80.865 ;
     RECT  2.16 81.135 69.12 81.405 ;
     RECT  2.16 81.675 69.12 81.945 ;
     RECT  2.16 82.215 69.12 82.485 ;
     RECT  2.16 82.755 69.12 83.025 ;
     RECT  2.16 83.295 69.12 83.565 ;
     RECT  2.16 83.835 69.12 84.105 ;
     RECT  2.16 84.375 69.12 84.645 ;
     RECT  2.16 84.915 69.12 85.185 ;
     RECT  2.16 85.455 69.12 85.725 ;
     RECT  2.16 85.995 69.12 86.265 ;
     RECT  2.16 86.535 69.12 86.805 ;
     RECT  2.16 87.075 69.12 87.345 ;
     RECT  2.16 87.615 69.12 87.885 ;
     RECT  2.16 88.155 69.12 88.425 ;
     RECT  2.16 88.695 69.12 88.965 ;
     RECT  2.16 89.235 69.12 89.505 ;
     RECT  2.16 89.775 69.12 90.045 ;
     RECT  2.16 90.315 69.12 90.585 ;
     RECT  2.16 90.855 69.12 91.125 ;
     RECT  2.16 91.395 69.12 91.665 ;
     RECT  2.16 91.935 69.12 92.205 ;
     RECT  2.16 92.475 69.12 92.745 ;
     RECT  2.16 93.015 69.12 93.285 ;
     RECT  2.16 93.555 69.12 93.825 ;
     RECT  2.16 94.095 69.12 94.365 ;
     RECT  2.16 94.635 69.12 94.905 ;
     RECT  2.16 95.175 69.12 95.445 ;
     RECT  2.16 95.715 69.12 95.985 ;
     RECT  2.16 96.255 69.12 96.525 ;
     RECT  2.16 96.795 69.12 97.065 ;
     RECT  2.16 97.335 69.12 97.605 ;
     RECT  2.16 97.875 69.12 98.145 ;
     RECT  2.16 98.415 69.12 98.685 ;
     RECT  2.16 98.955 69.12 99.225 ;
    LAYER M1 ;
     RECT  2.16 2.151 69.12 99.369 ;
    LAYER M2 ;
     RECT  0.499 22.05 0.535 22.068 ;
     RECT  0.211 42.696 0.535 42.714 ;
     RECT  0.211 51.984 0.535 52.002 ;
     RECT  0.211 62.676 0.535 62.694 ;
     RECT  0.211 79.146 0.535 79.164 ;
     RECT  0.211 94.536 0.535 94.554 ;
     RECT  0.535 6.156 2.16 6.606 ;
     RECT  0.535 8.406 2.16 8.424 ;
     RECT  0.535 11.286 2.16 11.304 ;
     RECT  0.535 12.996 2.16 13.014 ;
     RECT  0.211 14.886 2.16 14.904 ;
     RECT  0.535 16.416 2.16 16.434 ;
     RECT  0.211 17.586 2.16 17.604 ;
     RECT  0.535 19.584 2.16 19.602 ;
     RECT  0.535 22.05 2.16 22.194 ;
     RECT  0.535 25.416 2.16 25.434 ;
     RECT  0.535 26.676 2.16 26.694 ;
     RECT  0.535 31.806 2.16 32.454 ;
     RECT  0.535 41.958 2.16 42.714 ;
     RECT  0.535 47.124 2.16 47.142 ;
     RECT  0.211 48.366 2.16 48.384 ;
     RECT  0.535 49.554 2.16 49.572 ;
     RECT  0.535 50.526 2.16 52.002 ;
     RECT  0.535 59.778 2.16 59.796 ;
     RECT  0.535 62.676 2.16 63.036 ;
     RECT  0.535 68.256 2.16 68.814 ;
     RECT  0.535 72.81 2.16 73.224 ;
     RECT  0.211 74.016 2.16 74.574 ;
     RECT  0.211 77.796 2.16 77.814 ;
     RECT  0.535 79.146 2.16 79.704 ;
     RECT  0.535 81.216 2.16 81.234 ;
     RECT  0.535 83.106 2.16 83.124 ;
     RECT  0.535 85.968 2.16 85.986 ;
     RECT  0.535 93.456 2.16 93.474 ;
     RECT  0.535 94.536 2.16 95.004 ;
     RECT  2.16 2.151 69.12 99.369 ;
     RECT  69.12 4.5 69.539 97.632 ;
     RECT  69.539 4.5 69.575 78.66 ;
     RECT  69.575 4.662 69.611 78.534 ;
     RECT  69.611 4.662 69.683 24.228 ;
     RECT  69.611 25.02 69.683 78.534 ;
     RECT  69.539 79.488 69.683 97.632 ;
     RECT  69.683 4.662 69.719 18.756 ;
     RECT  69.683 19.548 69.719 24.228 ;
     RECT  69.683 25.02 69.719 30.636 ;
     RECT  69.683 31.428 69.719 70.596 ;
     RECT  69.683 71.388 69.719 78.534 ;
     RECT  69.683 79.488 69.719 86.526 ;
     RECT  69.683 92.718 69.719 97.632 ;
     RECT  69.719 31.428 69.755 54.666 ;
     RECT  69.719 74.088 69.755 78.534 ;
     RECT  69.719 4.662 69.971 13.896 ;
     RECT  69.755 36.828 69.971 54.666 ;
     RECT  69.971 48.168 70.079 54.666 ;
     RECT  69.971 4.662 70.115 7.146 ;
     RECT  69.971 7.938 70.115 13.896 ;
     RECT  69.719 14.994 70.115 18.756 ;
     RECT  69.719 19.548 70.115 23.958 ;
     RECT  69.719 25.218 70.115 30.636 ;
     RECT  69.755 31.428 70.115 36.072 ;
     RECT  69.971 36.828 70.115 47.106 ;
     RECT  70.079 48.168 70.115 54.396 ;
     RECT  69.719 55.458 70.115 60.876 ;
     RECT  69.719 62.208 70.115 66.816 ;
     RECT  69.719 67.608 70.115 70.596 ;
     RECT  69.719 71.388 70.115 73.062 ;
     RECT  69.755 74.088 70.115 76.266 ;
     RECT  69.755 77.058 70.115 78.534 ;
     RECT  69.719 79.488 70.115 81.126 ;
     RECT  69.719 81.918 70.115 86.526 ;
     RECT  69.683 87.354 70.115 91.764 ;
     RECT  69.719 92.718 70.115 95.706 ;
     RECT  69.719 96.498 70.115 97.632 ;
     RECT  70.115 12.222 70.151 12.24 ;
     RECT  70.115 46.818 70.151 46.908 ;
     RECT  70.115 48.168 70.187 48.42 ;
     RECT  70.115 27.882 70.655 29.664 ;
     RECT  70.115 19.548 70.691 20.718 ;
     RECT  70.115 42.3 70.691 45.288 ;
     RECT  70.115 55.458 70.691 57.708 ;
     RECT  70.115 58.464 70.691 59.058 ;
     RECT  70.115 80.91 70.691 80.928 ;
     RECT  70.115 96.966 70.691 97.632 ;
     RECT  70.115 4.662 70.727 6.408 ;
     RECT  70.115 8.82 70.727 11.466 ;
     RECT  70.115 13.176 70.727 13.194 ;
     RECT  70.115 14.994 70.727 16.938 ;
     RECT  70.115 18.036 70.727 18.054 ;
     RECT  70.691 19.548 70.727 20.646 ;
     RECT  70.115 21.708 70.727 21.726 ;
     RECT  70.115 22.518 70.727 22.536 ;
     RECT  70.115 23.94 70.727 23.958 ;
     RECT  70.115 25.218 70.727 26.892 ;
     RECT  70.655 27.882 70.727 28.746 ;
     RECT  70.655 29.646 70.727 29.664 ;
     RECT  70.115 31.428 70.727 35.298 ;
     RECT  70.115 36.054 70.727 36.072 ;
     RECT  70.115 37.17 70.727 37.188 ;
     RECT  70.115 39.024 70.727 39.384 ;
     RECT  70.115 40.14 70.727 40.392 ;
     RECT  70.115 41.22 70.727 41.508 ;
     RECT  70.691 42.3 70.727 42.624 ;
     RECT  70.691 43.65 70.727 45.288 ;
     RECT  70.151 46.818 70.727 46.836 ;
     RECT  70.187 48.168 70.727 48.294 ;
     RECT  70.115 49.518 70.727 49.536 ;
     RECT  70.115 50.904 70.727 52.506 ;
     RECT  70.115 53.874 70.727 54.198 ;
     RECT  70.691 55.458 70.727 56.124 ;
     RECT  70.691 57.078 70.727 57.708 ;
     RECT  70.691 58.464 70.727 58.986 ;
     RECT  70.115 62.82 70.727 63.414 ;
     RECT  70.115 64.476 70.727 66.348 ;
     RECT  70.115 67.644 70.727 68.202 ;
     RECT  70.115 69.228 70.727 70.596 ;
     RECT  70.115 71.46 70.727 73.062 ;
     RECT  70.115 74.466 70.727 74.484 ;
     RECT  70.115 75.438 70.727 75.456 ;
     RECT  70.115 77.598 70.727 78.534 ;
     RECT  70.115 82.458 70.727 82.782 ;
     RECT  70.115 84.078 70.727 85.212 ;
     RECT  70.115 86.31 70.727 86.328 ;
     RECT  70.115 87.354 70.727 87.444 ;
     RECT  70.115 88.236 70.727 88.488 ;
     RECT  70.115 91.746 70.727 91.764 ;
     RECT  70.115 93.33 70.727 93.348 ;
     RECT  70.115 94.68 70.727 94.698 ;
     RECT  70.115 95.454 70.727 95.472 ;
     RECT  70.691 97.308 70.727 97.632 ;
     RECT  70.727 11.178 70.763 11.196 ;
     RECT  70.727 15.264 70.763 15.894 ;
     RECT  70.727 27.882 70.763 27.9 ;
     RECT  70.727 32.31 70.763 32.328 ;
     RECT  70.727 34.506 70.763 34.524 ;
     RECT  70.727 45.27 70.763 45.288 ;
     RECT  70.727 51.408 70.763 51.426 ;
     RECT  70.727 56.07 70.763 56.088 ;
     RECT  70.727 58.968 70.763 58.986 ;
     RECT  70.727 66.33 70.763 66.348 ;
     RECT  70.727 67.878 70.763 67.896 ;
     RECT  70.727 78.516 70.763 78.534 ;
     RECT  70.727 82.458 70.763 82.476 ;
     RECT  70.727 87.426 70.763 87.444 ;
     RECT  70.727 88.47 70.763 88.488 ;
     RECT  70.727 97.308 70.763 97.326 ;
     RECT  70.763 15.606 70.799 15.624 ;
    LAYER M3 ;
     RECT  59.076 1.723 59.094 2.143 ;
     RECT  2.415 2.143 2.505 2.413 ;
     RECT  5.115 2.143 5.205 2.413 ;
     RECT  7.815 2.143 7.905 2.413 ;
     RECT  10.515 2.143 10.605 2.413 ;
     RECT  13.215 2.143 13.305 2.413 ;
     RECT  15.915 2.143 16.005 2.413 ;
     RECT  18.615 2.143 18.705 2.413 ;
     RECT  21.315 2.143 21.405 2.413 ;
     RECT  24.015 2.143 24.105 2.413 ;
     RECT  26.715 2.143 26.805 2.413 ;
     RECT  29.415 2.143 29.505 2.413 ;
     RECT  32.115 2.143 32.205 2.413 ;
     RECT  34.815 2.143 34.905 2.413 ;
     RECT  37.515 2.143 37.605 2.413 ;
     RECT  40.215 2.143 40.305 2.413 ;
     RECT  45.615 2.143 45.705 2.413 ;
     RECT  48.315 2.143 48.405 2.413 ;
     RECT  51.015 2.143 51.105 2.413 ;
     RECT  53.715 2.143 53.805 2.413 ;
     RECT  56.415 2.143 56.505 2.413 ;
     RECT  59.076 2.143 59.205 2.413 ;
     RECT  61.815 2.143 61.905 2.413 ;
     RECT  64.515 2.143 64.605 2.413 ;
     RECT  67.215 2.143 67.305 2.413 ;
     RECT  42.915 2.143 43.47 2.795 ;
     RECT  45.615 2.413 45.897 2.803 ;
     RECT  59.076 2.413 59.397 2.858 ;
     RECT  58.176 2.803 58.194 2.861 ;
     RECT  59.04 2.858 59.397 2.911 ;
     RECT  59.04 2.911 59.49 3.145 ;
     RECT  59.04 3.145 59.598 3.379 ;
     RECT  58.716 3.379 59.598 3.437 ;
     RECT  58.896 3.437 59.598 3.451 ;
     RECT  58.896 3.451 59.994 3.677 ;
     RECT  45.615 2.803 46.098 3.685 ;
     RECT  45.615 3.685 46.278 3.955 ;
     RECT  45.504 3.955 46.278 3.991 ;
     RECT  59.115 3.677 59.994 3.991 ;
     RECT  45.504 3.991 46.782 4.117 ;
     RECT  45.504 4.117 47.394 4.157 ;
     RECT  45.615 4.157 47.394 4.261 ;
     RECT  48.315 2.413 48.597 4.261 ;
     RECT  2.415 2.413 2.697 4.351 ;
     RECT  67.215 2.413 67.497 4.351 ;
     RECT  45.615 4.261 48.597 4.415 ;
     RECT  59.115 3.991 60.03 4.415 ;
     RECT  67.215 4.351 67.878 4.451 ;
     RECT  2.304 4.351 2.697 4.495 ;
     RECT  67.215 4.451 67.842 4.495 ;
     RECT  64.515 2.413 64.797 4.621 ;
     RECT  66.888 4.495 67.842 4.621 ;
     RECT  45.615 4.415 46.782 4.649 ;
     RECT  5.115 2.413 5.397 4.693 ;
     RECT  42.915 2.795 43.197 4.693 ;
     RECT  61.815 2.413 62.097 4.693 ;
     RECT  64.476 4.621 64.797 4.693 ;
     RECT  46.764 4.649 46.782 4.721 ;
     RECT  5.115 4.693 5.922 4.729 ;
     RECT  61.815 4.693 62.73 4.729 ;
     RECT  69.552 4.411 69.57 4.747 ;
     RECT  70.704 4.555 70.722 4.747 ;
     RECT  2.304 4.495 2.898 4.765 ;
     RECT  42.804 4.693 43.197 4.829 ;
     RECT  2.304 4.765 3.402 4.891 ;
     RECT  68.688 4.801 68.706 4.891 ;
     RECT  6.804 4.801 7.074 4.919 ;
     RECT  68.616 4.891 68.706 4.919 ;
     RECT  2.232 4.891 3.402 4.939 ;
     RECT  4.68 4.729 5.922 4.939 ;
     RECT  69.552 4.747 70.722 4.991 ;
     RECT  2.232 4.939 5.922 5.063 ;
     RECT  61.815 4.729 62.802 5.071 ;
     RECT  64.44 4.693 64.797 5.083 ;
     RECT  6.804 4.919 6.894 5.099 ;
     RECT  60.264 4.531 60.282 5.099 ;
     RECT  68.616 4.919 68.634 5.099 ;
     RECT  61.815 5.071 63.306 5.117 ;
     RECT  64.332 5.083 64.797 5.161 ;
     RECT  65.664 5.131 65.682 5.161 ;
     RECT  66.708 4.621 67.842 5.161 ;
     RECT  2.268 5.063 5.922 5.213 ;
     RECT  69.552 4.991 69.678 5.227 ;
     RECT  30.78 5.161 30.798 5.233 ;
     RECT  7.815 2.413 8.097 5.269 ;
     RECT  69.516 5.227 69.678 5.297 ;
     RECT  9.036 5.161 9.054 5.333 ;
     RECT  30.78 5.233 30.87 5.333 ;
     RECT  66.672 5.161 67.842 5.341 ;
     RECT  38.736 5.161 38.754 5.369 ;
     RECT  69.588 5.297 69.678 5.405 ;
     RECT  66.492 5.341 68.13 5.431 ;
     RECT  66.42 5.431 68.13 5.459 ;
     RECT  2.304 5.213 5.922 5.495 ;
     RECT  64.332 5.161 65.682 5.503 ;
     RECT  66.42 5.459 67.698 5.503 ;
     RECT  38.772 5.467 38.826 5.639 ;
     RECT  59.115 4.415 59.397 5.701 ;
     RECT  64.332 5.503 67.698 5.729 ;
     RECT  7.815 5.269 8.154 5.737 ;
     RECT  61.815 5.117 63.054 5.741 ;
     RECT  7.668 5.737 8.154 5.809 ;
     RECT  10.515 2.413 10.797 5.809 ;
     RECT  34.815 2.413 35.097 5.845 ;
     RECT  9.216 5.701 9.234 5.873 ;
     RECT  6.876 5.099 6.894 5.881 ;
     RECT  7.632 5.809 8.154 5.881 ;
     RECT  10.515 5.809 10.926 5.881 ;
     RECT  69.66 5.405 69.678 5.899 ;
     RECT  70.704 4.991 70.722 5.899 ;
     RECT  38.772 5.639 38.79 5.909 ;
     RECT  58.716 5.701 59.397 5.909 ;
     RECT  61.815 5.741 62.874 5.909 ;
     RECT  34.416 5.845 35.097 5.999 ;
     RECT  62.856 5.909 62.874 5.999 ;
     RECT  10.515 5.881 10.998 6.035 ;
     RECT  34.776 5.999 35.097 6.107 ;
     RECT  6.552 5.881 8.226 6.151 ;
     RECT  34.815 6.107 35.097 6.151 ;
     RECT  34.815 6.151 35.622 6.305 ;
     RECT  69.66 5.899 70.722 6.379 ;
     RECT  69.444 6.379 70.722 6.413 ;
     RECT  64.332 5.729 64.797 6.421 ;
     RECT  65.556 5.729 67.698 6.421 ;
     RECT  6.552 6.151 8.55 6.449 ;
     RECT  2.304 5.495 5.778 6.511 ;
     RECT  63.936 6.421 64.797 6.511 ;
     RECT  65.556 6.421 68.31 6.511 ;
     RECT  63.936 6.511 68.31 6.539 ;
     RECT  30.78 5.333 30.798 6.583 ;
     RECT  38.664 6.349 38.682 6.611 ;
     RECT  64.44 6.539 68.31 6.619 ;
     RECT  69.444 6.413 70.11 6.619 ;
     RECT  2.304 6.511 5.814 6.62 ;
     RECT  30.78 6.583 30.87 6.683 ;
     RECT  63 6.655 63.018 6.781 ;
     RECT  2.304 6.62 5.778 6.809 ;
     RECT  6.552 6.449 8.262 6.809 ;
     RECT  64.44 6.619 70.11 6.809 ;
     RECT  30.78 6.683 30.798 6.845 ;
     RECT  63 6.781 63.306 6.845 ;
     RECT  0.54 6.151 0.558 6.893 ;
     RECT  61.815 5.909 62.097 6.925 ;
     RECT  34.815 6.305 35.226 6.961 ;
     RECT  34.416 6.961 35.226 7.123 ;
     RECT  34.416 7.123 35.37 7.231 ;
     RECT  36.144 6.547 36.27 7.231 ;
     RECT  61.815 6.925 62.802 7.259 ;
     RECT  2.304 6.809 5.598 7.349 ;
     RECT  9.108 7.231 9.126 7.349 ;
     RECT  34.416 7.231 36.702 7.349 ;
     RECT  9.144 7.465 9.162 7.619 ;
     RECT  47.988 4.415 48.597 7.619 ;
     RECT  64.44 6.809 64.797 7.627 ;
     RECT  6.84 6.809 8.097 7.655 ;
     RECT  10.515 6.035 10.797 7.663 ;
     RECT  53.715 2.413 53.997 7.663 ;
     RECT  64.404 7.627 64.797 7.663 ;
     RECT  65.628 6.809 68.346 7.663 ;
     RECT  35.892 7.349 36.054 7.691 ;
     RECT  38.772 7.591 38.79 7.691 ;
     RECT  46.764 7.591 46.782 7.691 ;
     RECT  64.404 7.663 68.346 7.699 ;
     RECT  64.404 7.699 68.526 7.763 ;
     RECT  10.515 7.663 10.854 7.771 ;
     RECT  53.715 7.663 54.702 7.799 ;
     RECT  64.404 7.763 65.826 7.819 ;
     RECT  66.6 7.763 68.526 7.819 ;
     RECT  10.515 7.771 10.926 7.861 ;
     RECT  36.036 7.691 36.054 7.889 ;
     RECT  10.515 7.861 10.998 7.961 ;
     RECT  59.115 5.909 59.397 8.041 ;
     RECT  64.26 7.819 65.826 8.041 ;
     RECT  61.815 7.259 62.73 8.155 ;
     RECT  64.044 8.041 65.826 8.159 ;
     RECT  34.776 7.349 35.097 8.203 ;
     RECT  61.815 8.155 63.126 8.203 ;
     RECT  2.304 7.349 5.454 8.311 ;
     RECT  66.6 7.819 68.706 8.311 ;
     RECT  69.516 6.809 70.11 8.311 ;
     RECT  38.736 8.131 38.754 8.339 ;
     RECT  34.632 8.203 35.097 8.401 ;
     RECT  2.304 8.311 6.102 8.429 ;
     RECT  34.632 8.401 35.154 8.429 ;
     RECT  61.815 8.203 63.27 8.429 ;
     RECT  66.6 8.311 70.11 8.491 ;
     RECT  66.6 8.491 70.722 8.501 ;
     RECT  61.815 8.429 63.234 8.525 ;
     RECT  68.256 8.501 70.722 8.537 ;
     RECT  64.26 8.159 65.826 8.539 ;
     RECT  66.6 8.501 67.497 8.539 ;
     RECT  7.092 7.655 8.097 8.545 ;
     RECT  36.324 8.545 36.342 8.699 ;
     RECT  0.54 8.401 0.558 8.717 ;
     RECT  2.304 8.429 5.598 8.717 ;
     RECT  6.588 8.545 8.097 8.735 ;
     RECT  9.036 8.545 9.054 8.735 ;
     RECT  4.032 8.717 5.598 8.771 ;
     RECT  6.66 8.735 8.097 8.771 ;
     RECT  68.868 8.537 70.722 8.771 ;
     RECT  30.852 8.707 30.87 8.843 ;
     RECT  58.716 8.041 59.397 8.879 ;
     RECT  68.868 8.771 69.57 8.969 ;
     RECT  6.768 8.771 8.097 9.005 ;
     RECT  6.768 9.005 7.074 9.041 ;
     RECT  9.108 8.941 9.126 9.113 ;
     RECT  2.304 8.717 3.258 9.239 ;
     RECT  7.815 9.005 8.097 9.283 ;
     RECT  34.776 8.429 35.154 9.283 ;
     RECT  64.26 8.539 67.497 9.319 ;
     RECT  34.776 9.283 35.55 9.355 ;
     RECT  64.044 9.319 67.497 9.481 ;
     RECT  69.372 8.969 69.57 9.499 ;
     RECT  6.876 9.041 7.074 9.509 ;
     RECT  34.776 9.355 35.91 9.509 ;
     RECT  64.044 9.481 67.554 9.509 ;
     RECT  61.815 8.525 63.126 9.545 ;
     RECT  2.412 9.239 3.258 9.547 ;
     RECT  64.296 9.509 67.554 9.581 ;
     RECT  69.372 9.499 69.714 9.653 ;
     RECT  0.252 9.547 0.27 9.677 ;
     RECT  6.876 9.509 6.894 9.677 ;
     RECT  64.296 9.581 67.497 9.677 ;
     RECT  2.412 9.547 3.294 9.751 ;
     RECT  4.032 8.771 5.397 9.751 ;
     RECT  2.412 9.751 5.397 9.779 ;
     RECT  61.815 9.545 63.018 9.787 ;
     RECT  8.964 9.661 8.982 9.851 ;
     RECT  61.668 9.787 63.018 9.851 ;
     RECT  61.812 9.851 63.018 9.869 ;
     RECT  3.78 9.779 5.397 9.895 ;
     RECT  2.412 9.779 2.862 9.979 ;
     RECT  34.776 9.509 35.097 10.021 ;
     RECT  21.315 2.413 21.597 10.027 ;
     RECT  29.415 2.413 29.697 10.027 ;
     RECT  37.515 2.413 37.797 10.027 ;
     RECT  45.615 4.649 45.897 10.027 ;
     RECT  53.715 7.799 53.997 10.027 ;
     RECT  54.72 9.883 54.738 10.027 ;
     RECT  3.78 9.895 5.634 10.049 ;
     RECT  53.715 10.027 54.738 10.061 ;
     RECT  18.615 2.413 18.897 10.123 ;
     RECT  69.408 9.653 69.714 10.123 ;
     RECT  70.704 8.771 70.722 10.123 ;
     RECT  20.16 10.123 20.178 10.129 ;
     RECT  14.832 10.027 14.85 10.157 ;
     RECT  21.315 10.027 21.69 10.157 ;
     RECT  22.824 10.027 22.842 10.157 ;
     RECT  29.415 10.027 29.79 10.157 ;
     RECT  37.515 10.027 37.89 10.157 ;
     RECT  38.772 10.027 38.79 10.157 ;
     RECT  45.615 10.027 45.99 10.157 ;
     RECT  46.764 10.027 46.782 10.157 ;
     RECT  53.715 10.061 54.09 10.157 ;
     RECT  69.408 10.123 70.722 10.157 ;
     RECT  36 9.895 36.198 10.193 ;
     RECT  69.552 10.157 70.722 10.193 ;
     RECT  18.252 10.123 18.897 10.229 ;
     RECT  19.944 10.129 20.25 10.229 ;
     RECT  7.815 9.283 8.19 10.291 ;
     RECT  19.944 10.229 19.962 10.319 ;
     RECT  34.416 10.021 35.097 10.319 ;
     RECT  68.58 10.201 68.598 10.319 ;
     RECT  65.556 9.677 67.497 10.399 ;
     RECT  69.552 10.193 69.714 10.463 ;
     RECT  34.815 10.319 35.097 10.471 ;
     RECT  64.296 9.677 64.797 10.471 ;
     RECT  61.815 9.869 63.018 10.493 ;
     RECT  7.815 10.291 8.694 10.589 ;
     RECT  68.724 10.471 68.742 10.589 ;
     RECT  63.936 10.471 64.797 10.625 ;
     RECT  30.78 10.027 30.798 10.831 ;
     RECT  65.556 10.399 67.554 10.831 ;
     RECT  2.304 9.979 2.862 10.843 ;
     RECT  3.78 10.049 5.598 10.843 ;
     RECT  6.84 10.021 6.858 10.843 ;
     RECT  7.815 10.589 8.19 10.843 ;
     RECT  33.624 10.669 33.642 10.895 ;
     RECT  2.304 10.843 5.598 10.903 ;
     RECT  70.704 10.193 70.722 10.93 ;
     RECT  64.296 10.625 64.797 10.975 ;
     RECT  65.556 10.831 67.662 10.975 ;
     RECT  6.84 10.843 8.19 11.011 ;
     RECT  34.815 10.471 35.586 11.011 ;
     RECT  30.78 10.831 30.87 11.039 ;
     RECT  69.552 10.463 69.678 11.131 ;
     RECT  34.815 11.011 36.342 11.137 ;
     RECT  34.776 11.137 36.342 11.173 ;
     RECT  70.704 10.93 70.758 11.173 ;
     RECT  69.516 11.131 69.678 11.201 ;
     RECT  70.668 11.173 70.758 11.201 ;
     RECT  64.296 10.975 67.662 11.281 ;
     RECT  6.732 11.011 8.19 11.371 ;
     RECT  2.304 10.903 5.814 11.399 ;
     RECT  34.776 11.173 36.414 11.399 ;
     RECT  38.736 10.597 38.754 11.407 ;
     RECT  64.296 11.281 67.806 11.407 ;
     RECT  69.588 11.201 69.678 11.419 ;
     RECT  70.668 11.201 70.722 11.419 ;
     RECT  61.815 10.493 62.766 11.443 ;
     RECT  6.696 11.371 8.19 11.453 ;
     RECT  69.588 11.419 70.722 11.471 ;
     RECT  0.54 11.281 0.558 11.501 ;
     RECT  38.664 11.407 38.754 11.507 ;
     RECT  59.115 8.879 59.397 11.515 ;
     RECT  64.116 11.407 67.806 11.515 ;
     RECT  64.044 11.515 68.418 11.579 ;
     RECT  58.716 11.515 59.397 11.669 ;
     RECT  61.815 11.443 63.27 11.669 ;
     RECT  64.044 11.579 64.89 11.669 ;
     RECT  61.815 11.669 63.126 11.741 ;
     RECT  6.84 11.453 8.19 11.849 ;
     RECT  38.736 11.507 38.754 11.849 ;
     RECT  61.815 11.741 62.802 11.849 ;
     RECT  2.304 11.399 3.618 11.939 ;
     RECT  64.188 11.669 64.89 11.939 ;
     RECT  34.776 11.399 35.838 11.947 ;
     RECT  30.852 11.983 30.87 12.083 ;
     RECT  34.164 11.947 35.838 12.083 ;
     RECT  69.588 11.471 70.11 12.091 ;
     RECT  34.308 12.083 35.838 12.119 ;
     RECT  4.392 11.399 5.814 12.181 ;
     RECT  65.7 11.579 68.418 12.217 ;
     RECT  69.516 12.091 70.11 12.217 ;
     RECT  65.7 12.217 68.634 12.289 ;
     RECT  69.516 12.217 70.146 12.289 ;
     RECT  6.84 11.849 8.154 12.389 ;
     RECT  34.308 12.119 35.226 12.479 ;
     RECT  4.248 12.181 5.814 12.515 ;
     RECT  30.78 12.289 30.798 12.515 ;
     RECT  4.284 12.515 5.814 12.571 ;
     RECT  6.84 12.389 7.074 12.571 ;
     RECT  7.815 12.389 8.154 12.631 ;
     RECT  9 12.361 9.018 12.631 ;
     RECT  64.188 11.939 64.797 12.631 ;
     RECT  65.7 12.289 70.146 12.631 ;
     RECT  64.044 12.631 64.797 12.721 ;
     RECT  7.815 12.631 9.018 12.749 ;
     RECT  59.115 11.669 59.397 12.757 ;
     RECT  64.044 12.721 64.854 12.757 ;
     RECT  58.716 12.757 59.397 12.893 ;
     RECT  63.468 12.757 64.854 12.893 ;
     RECT  65.592 12.631 70.146 12.907 ;
     RECT  65.592 12.907 70.722 12.929 ;
     RECT  7.815 12.749 8.154 12.941 ;
     RECT  2.304 11.939 3.474 13.019 ;
     RECT  8.928 12.749 9.018 13.019 ;
     RECT  36.144 12.901 36.162 13.055 ;
     RECT  61.815 11.849 62.73 13.055 ;
     RECT  9 13.019 9.018 13.091 ;
     RECT  0.54 12.991 0.558 13.133 ;
     RECT  68.508 12.929 70.722 13.199 ;
     RECT  4.284 12.571 7.074 13.261 ;
     RECT  7.815 12.941 8.118 13.261 ;
     RECT  34.488 12.479 35.226 13.289 ;
     RECT  34.815 13.289 35.226 13.369 ;
     RECT  64.188 12.893 64.854 13.441 ;
     RECT  65.592 12.929 67.662 13.441 ;
     RECT  4.284 13.261 8.118 13.559 ;
     RECT  68.508 13.199 70.11 13.559 ;
     RECT  30.78 13.567 30.798 13.667 ;
     RECT  58.788 12.893 59.397 13.711 ;
     RECT  2.304 13.019 2.718 13.801 ;
     RECT  3.528 13.711 3.546 13.801 ;
     RECT  4.284 13.559 5.85 13.801 ;
     RECT  61.815 13.055 62.406 13.801 ;
     RECT  63.216 13.711 63.306 13.801 ;
     RECT  69.444 13.559 70.11 13.901 ;
     RECT  64.188 13.441 67.662 13.909 ;
     RECT  6.696 13.559 8.118 13.937 ;
     RECT  58.716 13.711 59.397 13.937 ;
     RECT  61.815 13.801 63.306 13.937 ;
     RECT  2.304 13.801 5.85 13.973 ;
     RECT  34.815 13.369 35.838 13.981 ;
     RECT  64.188 13.909 67.77 13.981 ;
     RECT  2.304 13.973 3.546 14.099 ;
     RECT  4.32 13.973 5.85 14.099 ;
     RECT  34.815 13.981 36.162 14.099 ;
     RECT  60.984 13.711 61.074 14.099 ;
     RECT  64.116 13.981 67.77 14.099 ;
     RECT  4.32 14.099 5.598 14.135 ;
     RECT  63 13.937 63.306 14.135 ;
     RECT  2.304 14.099 2.862 14.171 ;
     RECT  58.752 13.937 59.397 14.171 ;
     RECT  61.815 13.937 62.262 14.171 ;
     RECT  38.736 13.801 38.754 14.207 ;
     RECT  65.664 14.099 67.77 14.215 ;
     RECT  68.508 13.559 68.706 14.215 ;
     RECT  4.32 14.135 5.397 14.237 ;
     RECT  34.815 14.099 35.514 14.243 ;
     RECT  6.84 13.937 8.118 14.251 ;
     RECT  34.815 14.243 35.19 14.251 ;
     RECT  34.668 14.251 35.19 14.341 ;
     RECT  64.116 14.099 64.797 14.341 ;
     RECT  6.84 14.251 8.406 14.369 ;
     RECT  34.596 14.341 35.19 14.369 ;
     RECT  7.092 14.369 8.406 14.405 ;
     RECT  63.648 14.341 64.797 14.429 ;
     RECT  34.596 14.369 35.097 14.441 ;
     RECT  69.444 13.901 69.714 14.477 ;
     RECT  69.66 14.477 69.714 14.513 ;
     RECT  2.304 14.171 2.697 14.521 ;
     RECT  65.664 14.215 68.706 14.521 ;
     RECT  10.515 7.961 10.797 14.611 ;
     RECT  2.268 14.521 2.697 14.621 ;
     RECT  5.004 14.237 5.397 14.639 ;
     RECT  65.664 14.521 68.922 14.639 ;
     RECT  10.515 14.611 10.818 14.711 ;
     RECT  70.704 14.539 70.722 14.731 ;
     RECT  4.032 14.731 4.05 14.819 ;
     RECT  5.115 14.639 5.397 14.881 ;
     RECT  63.936 14.429 64.797 14.881 ;
     RECT  65.664 14.639 68.814 14.881 ;
     RECT  0.216 14.872 0.234 14.909 ;
     RECT  63.072 14.875 63.09 14.915 ;
     RECT  38.772 14.647 38.79 14.989 ;
     RECT  70.704 14.731 70.758 15.019 ;
     RECT  60.984 14.099 61.002 15.025 ;
     RECT  7.092 14.405 8.097 15.151 ;
     RECT  36.144 15.061 36.162 15.179 ;
     RECT  38.736 14.989 38.79 15.187 ;
     RECT  63.936 14.881 68.814 15.215 ;
     RECT  30.78 15.151 30.798 15.359 ;
     RECT  38.736 15.187 38.826 15.359 ;
     RECT  4.356 15.295 4.374 15.403 ;
     RECT  5.115 14.881 5.994 15.403 ;
     RECT  6.84 15.151 8.097 15.403 ;
     RECT  34.815 14.441 35.097 15.421 ;
     RECT  38.736 15.359 38.79 15.421 ;
     RECT  4.356 15.403 8.097 15.485 ;
     RECT  63.936 15.215 64.797 15.547 ;
     RECT  69.66 14.513 69.678 15.547 ;
     RECT  70.704 15.019 70.794 15.547 ;
     RECT  63.648 15.547 64.797 15.581 ;
     RECT  64.476 15.581 64.797 15.593 ;
     RECT  2.304 14.621 2.697 15.601 ;
     RECT  3.456 15.421 3.474 15.601 ;
     RECT  34.815 15.421 35.19 15.601 ;
     RECT  38.664 15.421 38.79 15.629 ;
     RECT  69.66 15.547 70.794 15.629 ;
     RECT  2.304 15.601 3.474 15.691 ;
     RECT  2.268 15.691 3.474 15.791 ;
     RECT  60.984 15.025 61.074 15.791 ;
     RECT  38.736 15.629 38.79 15.827 ;
     RECT  2.304 15.791 3.474 15.835 ;
     RECT  65.664 15.215 68.814 15.835 ;
     RECT  69.66 15.629 70.758 15.835 ;
     RECT  65.664 15.835 70.758 15.899 ;
     RECT  6.732 15.485 8.097 15.961 ;
     RECT  34.776 15.601 35.19 15.961 ;
     RECT  64.515 15.593 64.797 16.033 ;
     RECT  65.664 15.899 70.722 16.033 ;
     RECT  34.704 15.961 35.19 16.061 ;
     RECT  34.815 16.061 35.19 16.069 ;
     RECT  36.576 16.033 36.594 16.105 ;
     RECT  64.515 16.033 70.722 16.133 ;
     RECT  2.304 15.835 3.51 16.141 ;
     RECT  4.356 15.485 5.85 16.141 ;
     RECT  36.576 16.105 36.702 16.141 ;
     RECT  60.984 15.791 61.038 16.142 ;
     RECT  6.732 15.961 8.19 16.169 ;
     RECT  2.304 16.141 5.85 16.231 ;
     RECT  6.732 16.169 8.154 16.231 ;
     RECT  2.304 16.231 8.154 16.259 ;
     RECT  64.515 16.133 68.706 16.259 ;
     RECT  60.984 16.142 61.002 16.295 ;
     RECT  36.36 16.141 36.702 16.303 ;
     RECT  63.648 15.581 63.666 16.303 ;
     RECT  63.504 16.303 63.666 16.331 ;
     RECT  34.815 16.069 35.298 16.375 ;
     RECT  38.736 15.827 38.754 16.403 ;
     RECT  30.852 15.565 30.87 16.439 ;
     RECT  2.415 16.259 8.154 16.529 ;
     RECT  36.18 16.303 36.702 16.529 ;
     RECT  64.515 16.259 68.634 16.529 ;
     RECT  36.18 16.529 36.198 16.601 ;
     RECT  6.804 16.529 8.154 16.673 ;
     RECT  64.515 16.529 64.797 16.681 ;
     RECT  6.804 16.673 8.097 16.685 ;
     RECT  0.54 16.411 0.558 16.733 ;
     RECT  34.815 16.375 35.406 16.843 ;
     RECT  59.115 14.171 59.397 16.879 ;
     RECT  61.815 14.171 62.097 16.879 ;
     RECT  61.815 16.879 62.766 16.915 ;
     RECT  69.66 16.133 70.722 16.943 ;
     RECT  58.716 16.879 59.397 16.979 ;
     RECT  2.415 16.529 6.03 17.069 ;
     RECT  58.788 16.979 59.397 17.069 ;
     RECT  61.812 16.915 62.766 17.105 ;
     RECT  34.815 16.843 35.91 17.141 ;
     RECT  69.66 16.943 70.11 17.179 ;
     RECT  2.415 17.069 5.778 17.311 ;
     RECT  63.504 16.331 63.522 17.311 ;
     RECT  64.404 16.681 64.797 17.311 ;
     RECT  61.815 17.105 62.766 17.347 ;
     RECT  63.504 17.311 64.797 17.347 ;
     RECT  6.804 16.685 6.822 17.383 ;
     RECT  34.815 17.141 35.298 17.383 ;
     RECT  34.488 17.383 35.298 17.419 ;
     RECT  69.588 17.179 70.11 17.419 ;
     RECT  6.552 17.383 6.822 17.455 ;
     RECT  7.815 16.685 8.097 17.455 ;
     RECT  30.78 17.149 30.798 17.455 ;
     RECT  34.416 17.419 35.298 17.491 ;
     RECT  65.7 16.529 68.634 17.491 ;
     RECT  65.556 17.491 68.634 17.581 ;
     RECT  2.304 17.311 5.778 17.609 ;
     RECT  33.984 17.491 35.298 17.609 ;
     RECT  61.815 17.347 64.797 17.609 ;
     RECT  32.115 2.413 32.397 17.617 ;
     RECT  64.152 17.609 64.797 17.659 ;
     RECT  65.556 17.581 68.706 17.659 ;
     RECT  69.552 17.419 70.11 17.659 ;
     RECT  30.78 17.455 30.87 17.681 ;
     RECT  6.552 17.455 8.097 17.689 ;
     RECT  31.932 17.617 32.397 17.689 ;
     RECT  0.216 17.581 0.234 17.693 ;
     RECT  3.636 17.609 5.778 17.693 ;
     RECT  64.152 17.659 68.706 17.693 ;
     RECT  31.932 17.689 33.102 17.789 ;
     RECT  34.416 17.609 35.097 17.789 ;
     RECT  30.78 17.681 30.798 17.879 ;
     RECT  3.708 17.693 5.778 17.887 ;
     RECT  6.552 17.689 8.118 17.887 ;
     RECT  3.708 17.887 8.118 17.959 ;
     RECT  3.708 17.959 8.406 18.031 ;
     RECT  69.516 17.659 70.11 18.031 ;
     RECT  31.932 17.789 32.397 18.059 ;
     RECT  38.772 17.887 38.79 18.059 ;
     RECT  66.672 17.693 68.706 18.059 ;
     RECT  3.708 18.031 8.946 18.149 ;
     RECT  66.708 18.059 68.706 18.149 ;
     RECT  69.516 18.031 70.722 18.173 ;
     RECT  34.704 17.789 35.097 18.185 ;
     RECT  66.744 18.149 68.706 18.221 ;
     RECT  66.744 18.221 67.986 18.419 ;
     RECT  34.776 18.185 35.097 18.499 ;
     RECT  34.776 18.499 35.262 18.535 ;
     RECT  64.152 17.693 65.79 18.535 ;
     RECT  34.776 18.535 35.802 18.571 ;
     RECT  61.815 17.609 62.73 18.571 ;
     RECT  69.516 18.173 70.11 18.571 ;
     RECT  3.708 18.149 8.622 18.689 ;
     RECT  34.776 18.571 36.27 18.689 ;
     RECT  64.044 18.535 65.79 18.689 ;
     RECT  68.976 18.571 70.11 18.689 ;
     RECT  61.815 18.571 62.802 18.697 ;
     RECT  2.304 17.609 2.826 18.733 ;
     RECT  3.708 18.689 6.786 18.733 ;
     RECT  61.815 18.697 63.126 18.749 ;
     RECT  67.215 18.419 67.986 18.761 ;
     RECT  34.776 18.689 35.874 18.797 ;
     RECT  69.372 18.689 70.11 18.797 ;
     RECT  33.624 18.661 33.642 18.833 ;
     RECT  7.632 18.689 8.622 18.959 ;
     RECT  65.592 18.689 65.79 19.003 ;
     RECT  69.516 18.797 70.11 19.031 ;
     RECT  65.592 19.003 65.934 19.201 ;
     RECT  69.66 19.031 70.11 19.291 ;
     RECT  35.856 18.797 35.874 19.337 ;
     RECT  65.592 19.201 66.438 19.381 ;
     RECT  67.215 18.761 67.77 19.381 ;
     RECT  38.736 18.661 38.754 19.471 ;
     RECT  34.776 18.797 35.097 19.499 ;
     RECT  64.188 18.689 64.797 19.507 ;
     RECT  65.592 19.381 67.77 19.507 ;
     RECT  38.736 19.471 38.79 19.543 ;
     RECT  64.188 19.507 67.77 19.543 ;
     RECT  64.08 19.543 67.77 19.615 ;
     RECT  2.304 18.733 6.786 19.651 ;
     RECT  7.632 18.959 8.097 19.651 ;
     RECT  64.008 19.615 67.77 19.651 ;
     RECT  38.736 19.543 38.862 19.679 ;
     RECT  61.815 18.749 62.766 19.723 ;
     RECT  61.815 19.723 63.09 19.769 ;
     RECT  64.008 19.651 68.094 19.769 ;
     RECT  34.815 19.499 35.097 19.777 ;
     RECT  38.736 19.679 38.754 19.841 ;
     RECT  69.66 19.291 70.722 19.885 ;
     RECT  2.304 19.651 8.097 19.913 ;
     RECT  34.815 19.777 35.586 19.913 ;
     RECT  65.592 19.769 68.094 19.921 ;
     RECT  36.684 19.579 36.702 19.949 ;
     RECT  0.54 19.579 0.558 19.997 ;
     RECT  2.304 19.913 7.074 19.997 ;
     RECT  64.008 19.769 64.797 20.047 ;
     RECT  2.304 19.997 3.618 20.075 ;
     RECT  34.815 19.913 35.478 20.183 ;
     RECT  63.9 20.047 64.797 20.191 ;
     RECT  65.592 19.921 68.382 20.191 ;
     RECT  69.552 19.885 70.722 20.191 ;
     RECT  65.592 20.191 70.722 20.309 ;
     RECT  66.348 20.309 70.722 20.381 ;
     RECT  36.252 20.083 36.378 20.417 ;
     RECT  63.828 20.191 64.797 20.417 ;
     RECT  30.78 20.011 30.798 20.453 ;
     RECT  33.624 20.281 33.642 20.579 ;
     RECT  64.188 20.417 64.797 20.587 ;
     RECT  65.592 20.309 65.61 20.587 ;
     RECT  69.588 20.381 70.722 20.651 ;
     RECT  61.815 19.769 62.91 20.695 ;
     RECT  4.536 19.997 7.074 20.731 ;
     RECT  7.815 19.913 8.097 20.731 ;
     RECT  34.815 20.183 35.097 20.731 ;
     RECT  66.348 20.381 68.526 20.759 ;
     RECT  4.536 20.731 8.097 20.821 ;
     RECT  34.524 20.731 35.097 20.849 ;
     RECT  36 20.695 36.018 20.849 ;
     RECT  61.815 20.695 63.306 20.849 ;
     RECT  0.252 20.779 0.27 20.957 ;
     RECT  2.304 20.075 3.222 20.965 ;
     RECT  2.304 20.965 3.33 21.091 ;
     RECT  4.104 20.821 8.097 21.091 ;
     RECT  34.776 20.849 35.097 21.091 ;
     RECT  64.188 20.587 65.61 21.127 ;
     RECT  66.348 20.759 68.094 21.127 ;
     RECT  2.304 21.091 8.097 21.191 ;
     RECT  64.188 21.127 68.094 21.199 ;
     RECT  38.736 20.731 38.754 21.227 ;
     RECT  2.304 21.191 4.374 21.389 ;
     RECT  64.044 21.199 68.094 21.389 ;
     RECT  69.588 20.651 70.686 21.403 ;
     RECT  34.776 21.091 35.19 21.461 ;
     RECT  64.332 21.389 68.094 21.505 ;
     RECT  9.108 21.199 9.126 21.533 ;
     RECT  69.588 21.403 70.722 21.595 ;
     RECT  34.815 21.461 35.19 21.631 ;
     RECT  61.815 20.849 63.27 21.643 ;
     RECT  2.304 21.389 3.15 21.659 ;
     RECT  64.332 21.505 68.67 21.677 ;
     RECT  36.108 21.271 36.126 21.703 ;
     RECT  37.515 10.157 37.797 21.703 ;
     RECT  69.552 21.595 70.722 21.883 ;
     RECT  64.368 21.677 68.67 21.929 ;
     RECT  59.115 17.069 59.397 21.973 ;
     RECT  30.852 21.739 30.87 22.001 ;
     RECT  58.752 21.973 59.397 22.009 ;
     RECT  9 21.775 9.054 22.037 ;
     RECT  0.252 21.979 0.27 22.045 ;
     RECT  34.815 21.631 35.226 22.045 ;
     RECT  36.108 21.703 37.797 22.081 ;
     RECT  38.844 22.009 38.862 22.081 ;
     RECT  38.772 22.081 38.862 22.109 ;
     RECT  0.252 22.045 0.522 22.157 ;
     RECT  0.504 22.157 0.522 22.171 ;
     RECT  3.924 21.389 4.374 22.171 ;
     RECT  5.115 21.191 8.097 22.171 ;
     RECT  34.815 22.045 35.298 22.199 ;
     RECT  36.036 22.081 37.797 22.199 ;
     RECT  38.772 22.109 38.79 22.199 ;
     RECT  61.815 21.643 63.594 22.199 ;
     RECT  3.924 22.171 8.097 22.205 ;
     RECT  9 22.037 9.018 22.235 ;
     RECT  0.504 22.171 0.558 22.301 ;
     RECT  34.815 22.199 35.118 22.307 ;
     RECT  34.815 22.307 35.097 22.351 ;
     RECT  58.716 22.009 59.397 22.379 ;
     RECT  63.18 22.199 63.594 22.441 ;
     RECT  64.368 21.929 65.718 22.441 ;
     RECT  0.504 22.301 0.522 22.445 ;
     RECT  3.924 22.205 6.21 22.469 ;
     RECT  69.444 21.883 70.722 22.541 ;
     RECT  2.304 21.659 3.114 22.585 ;
     RECT  69.444 22.541 70.11 22.612 ;
     RECT  6.948 22.205 8.097 22.621 ;
     RECT  58.788 22.379 59.397 22.621 ;
     RECT  2.304 22.585 3.438 22.637 ;
     RECT  4.212 22.469 5.598 22.739 ;
     RECT  35.856 22.441 35.874 22.739 ;
     RECT  69.408 22.612 70.11 22.781 ;
     RECT  6.948 22.621 8.694 22.811 ;
     RECT  63.18 22.441 65.718 22.819 ;
     RECT  66.636 21.929 68.31 22.891 ;
     RECT  63.18 22.819 65.754 22.981 ;
     RECT  66.636 22.891 68.382 22.981 ;
     RECT  58.788 22.621 59.454 23.009 ;
     RECT  38.736 22.441 38.754 23.081 ;
     RECT  63.18 22.981 68.382 23.089 ;
     RECT  34.74 22.351 35.097 23.125 ;
     RECT  60.516 23.089 60.534 23.161 ;
     RECT  58.788 23.009 59.397 23.189 ;
     RECT  63.18 23.089 68.706 23.189 ;
     RECT  6.948 22.811 8.226 23.251 ;
     RECT  63.18 23.189 64.797 23.279 ;
     RECT  65.592 23.189 68.706 23.279 ;
     RECT  65.592 23.279 68.526 23.315 ;
     RECT  63.18 23.279 63.342 23.323 ;
     RECT  4.248 22.739 5.598 23.351 ;
     RECT  36.108 23.161 36.126 23.359 ;
     RECT  60.444 23.161 60.534 23.387 ;
     RECT  36.108 23.359 36.342 23.395 ;
     RECT  60.444 23.387 60.462 23.423 ;
     RECT  36.108 23.395 36.486 23.549 ;
     RECT  69.444 22.781 70.11 23.621 ;
     RECT  34.596 23.125 35.097 23.629 ;
     RECT  69.444 23.621 69.714 23.657 ;
     RECT  2.304 22.637 3.258 23.665 ;
     RECT  4.248 23.351 5.562 23.665 ;
     RECT  34.2 23.629 35.097 23.665 ;
     RECT  8.964 23.359 9.234 23.693 ;
     RECT  6.876 23.251 8.226 23.701 ;
     RECT  8.964 23.693 9.054 23.701 ;
     RECT  6.876 23.701 9.054 23.729 ;
     RECT  6.876 23.729 8.37 23.819 ;
     RECT  7.815 23.819 8.37 23.891 ;
     RECT  34.2 23.665 35.622 23.891 ;
     RECT  38.772 23.791 38.79 23.891 ;
     RECT  2.304 23.665 3.294 23.899 ;
     RECT  4.032 23.665 5.562 23.899 ;
     RECT  64.116 23.279 64.797 23.935 ;
     RECT  65.592 23.315 68.094 23.935 ;
     RECT  70.704 23.707 70.722 23.963 ;
     RECT  34.2 23.891 35.406 23.999 ;
     RECT  64.116 23.935 68.094 24.061 ;
     RECT  63.108 23.323 63.342 24.089 ;
     RECT  2.304 23.899 5.562 24.169 ;
     RECT  6.876 23.819 7.074 24.169 ;
     RECT  64.116 24.061 68.382 24.205 ;
     RECT  2.304 24.169 7.074 24.233 ;
     RECT  61.815 22.199 62.097 24.241 ;
     RECT  63.108 24.089 63.126 24.241 ;
     RECT  3.924 24.233 7.074 24.359 ;
     RECT  69.516 23.657 69.714 24.431 ;
     RECT  63.864 24.205 68.382 24.475 ;
     RECT  63.864 24.475 68.454 24.511 ;
     RECT  59.115 23.189 59.397 24.601 ;
     RECT  6.876 24.359 7.074 24.665 ;
     RECT  38.736 23.935 38.754 24.701 ;
     RECT  34.815 23.999 35.406 24.709 ;
     RECT  7.815 23.891 8.19 24.745 ;
     RECT  30.852 24.637 30.87 24.745 ;
     RECT  9.36 24.511 9.378 24.773 ;
     RECT  58.716 24.601 59.397 24.773 ;
     RECT  30.78 24.745 30.87 24.871 ;
     RECT  36.36 24.745 36.486 24.899 ;
     RECT  63.864 24.511 68.634 24.899 ;
     RECT  29.415 10.157 29.697 24.907 ;
     RECT  30.78 24.871 30.942 24.907 ;
     RECT  7.815 24.745 8.514 24.971 ;
     RECT  34.815 24.709 35.514 24.971 ;
     RECT  63.864 24.899 65.934 24.971 ;
     RECT  66.672 24.899 68.634 24.971 ;
     RECT  69.552 24.431 69.714 25.003 ;
     RECT  3.924 24.359 5.994 25.007 ;
     RECT  36.468 24.899 36.486 25.007 ;
     RECT  29.415 24.907 30.942 25.079 ;
     RECT  0.252 24.955 0.27 25.085 ;
     RECT  63.864 24.971 64.797 25.085 ;
     RECT  68.328 24.971 68.634 25.169 ;
     RECT  61.815 24.241 63.126 25.177 ;
     RECT  69.552 25.003 69.75 25.195 ;
     RECT  4.932 25.007 5.994 25.249 ;
     RECT  34.815 24.971 35.478 25.249 ;
     RECT  2.304 24.233 3.15 25.313 ;
     RECT  29.415 25.079 30.798 25.313 ;
     RECT  3.924 25.007 4.158 25.321 ;
     RECT  7.056 24.665 7.074 25.321 ;
     RECT  7.815 24.971 8.19 25.321 ;
     RECT  34.776 25.249 35.478 25.321 ;
     RECT  69.48 25.195 69.75 25.321 ;
     RECT  68.868 25.321 69.75 25.339 ;
     RECT  70.704 24.859 70.722 25.339 ;
     RECT  34.2 25.321 35.478 25.439 ;
     RECT  61.815 25.177 63.702 25.439 ;
     RECT  4.932 25.249 6.282 25.475 ;
     RECT  9.036 25.141 9.126 25.511 ;
     RECT  4.932 25.475 5.706 25.547 ;
     RECT  61.815 25.439 63.558 25.613 ;
     RECT  7.056 25.321 8.19 25.619 ;
     RECT  3.456 25.321 4.158 25.661 ;
     RECT  3.456 25.661 3.618 25.709 ;
     RECT  68.868 25.339 70.722 25.709 ;
     RECT  0.54 25.411 0.558 25.757 ;
     RECT  65.592 24.971 65.934 25.825 ;
     RECT  66.672 24.971 67.497 25.825 ;
     RECT  4.932 25.547 5.397 25.861 ;
     RECT  65.592 25.825 67.497 25.951 ;
     RECT  9.144 25.861 9.162 25.979 ;
     RECT  59.115 24.773 59.397 26.023 ;
     RECT  61.815 25.613 63.414 26.051 ;
     RECT  69.444 25.709 70.722 26.087 ;
     RECT  64.44 25.085 64.797 26.131 ;
     RECT  65.592 25.951 67.986 26.131 ;
     RECT  61.815 26.051 63.162 26.141 ;
     RECT  7.272 25.619 8.19 26.159 ;
     RECT  30.78 25.313 30.798 26.159 ;
     RECT  64.44 26.131 68.706 26.159 ;
     RECT  2.304 25.313 2.697 26.203 ;
     RECT  3.456 25.709 3.474 26.203 ;
     RECT  59.115 26.023 59.886 26.285 ;
     RECT  4.356 25.861 5.397 26.293 ;
     RECT  34.704 25.439 35.097 26.329 ;
     RECT  38.736 25.987 38.754 26.365 ;
     RECT  34.668 26.329 35.097 26.401 ;
     RECT  4.356 26.293 5.994 26.491 ;
     RECT  7.272 26.159 8.154 26.491 ;
     RECT  61.815 26.141 62.766 26.555 ;
     RECT  2.304 26.203 3.474 26.563 ;
     RECT  4.356 26.491 8.154 26.591 ;
     RECT  2.304 26.563 3.582 26.599 ;
     RECT  4.356 26.591 5.454 26.599 ;
     RECT  38.736 26.365 38.898 26.663 ;
     RECT  9.036 26.293 9.126 26.699 ;
     RECT  6.948 26.591 8.154 26.789 ;
     RECT  0.54 26.671 0.558 26.861 ;
     RECT  69.516 26.087 70.722 26.897 ;
     RECT  34.632 26.401 35.097 26.905 ;
     RECT  66.744 26.159 68.706 26.905 ;
     RECT  34.632 26.905 35.694 26.941 ;
     RECT  34.632 26.941 35.766 27.059 ;
     RECT  64.44 26.159 65.934 27.067 ;
     RECT  66.708 26.905 68.706 27.139 ;
     RECT  7.815 26.789 8.154 27.163 ;
     RECT  7.815 27.163 8.19 27.175 ;
     RECT  59.115 26.285 59.397 27.211 ;
     RECT  38.736 26.663 38.754 27.239 ;
     RECT  69.516 26.897 70.11 27.239 ;
     RECT  63.576 27.139 63.594 27.307 ;
     RECT  64.368 27.067 65.934 27.307 ;
     RECT  7.815 27.175 8.37 27.329 ;
     RECT  9.144 26.941 9.162 27.329 ;
     RECT  58.716 27.211 59.397 27.329 ;
     RECT  63.576 27.307 65.934 27.329 ;
     RECT  7.815 27.329 8.19 27.365 ;
     RECT  34.776 27.059 35.622 27.365 ;
     RECT  66.708 27.139 68.778 27.365 ;
     RECT  64.44 27.329 65.934 27.409 ;
     RECT  66.708 27.365 68.706 27.409 ;
     RECT  64.44 27.409 68.706 27.437 ;
     RECT  2.304 26.599 5.454 27.499 ;
     RECT  61.815 26.555 62.097 27.571 ;
     RECT  2.268 27.499 5.454 27.599 ;
     RECT  36.576 27.481 36.594 27.599 ;
     RECT  6.948 26.789 6.966 27.607 ;
     RECT  64.44 27.437 67.626 27.635 ;
     RECT  69.552 27.239 70.11 27.643 ;
     RECT  68.688 27.437 68.706 27.671 ;
     RECT  2.304 27.599 5.454 27.691 ;
     RECT  6.768 27.607 6.966 27.715 ;
     RECT  61.02 27.679 61.038 27.715 ;
     RECT  63.576 27.329 63.666 27.751 ;
     RECT  69.552 27.643 70.722 27.787 ;
     RECT  60.984 27.715 61.038 27.869 ;
     RECT  61.815 27.571 62.73 27.905 ;
     RECT  69.552 27.787 70.758 27.905 ;
     RECT  30.852 27.715 30.87 27.94 ;
     RECT  6.696 27.715 6.966 27.949 ;
     RECT  10.515 14.711 10.797 27.949 ;
     RECT  6.624 27.949 6.966 27.985 ;
     RECT  7.815 27.365 8.097 27.985 ;
     RECT  34.776 27.365 35.334 27.985 ;
     RECT  37.515 22.199 37.797 28.021 ;
     RECT  60.984 27.869 61.002 28.049 ;
     RECT  30.852 27.94 30.906 28.111 ;
     RECT  63.504 27.751 63.666 28.111 ;
     RECT  34.416 27.985 35.334 28.139 ;
     RECT  9.252 27.949 9.27 28.147 ;
     RECT  10.515 27.949 10.818 28.147 ;
     RECT  65.592 27.635 67.626 28.183 ;
     RECT  6.624 27.985 8.097 28.219 ;
     RECT  34.524 28.139 35.334 28.255 ;
     RECT  59.115 27.329 59.397 28.255 ;
     RECT  69.552 27.905 70.722 28.267 ;
     RECT  10.515 28.147 10.854 28.283 ;
     RECT  63.252 28.111 63.666 28.291 ;
     RECT  64.44 27.635 64.797 28.291 ;
     RECT  65.592 28.183 67.662 28.291 ;
     RECT  6.624 28.219 8.406 28.409 ;
     RECT  9.18 28.147 9.27 28.409 ;
     RECT  34.524 28.255 35.73 28.409 ;
     RECT  63.252 28.291 64.797 28.409 ;
     RECT  30.78 28.111 30.906 28.481 ;
     RECT  38.736 28.381 38.754 28.481 ;
     RECT  69.516 28.267 70.722 28.481 ;
     RECT  2.304 27.691 5.778 28.507 ;
     RECT  6.624 28.409 8.097 28.507 ;
     RECT  34.815 28.409 35.694 28.589 ;
     RECT  63.288 28.409 63.666 28.589 ;
     RECT  64.44 28.409 64.797 28.651 ;
     RECT  65.592 28.291 68.346 28.651 ;
     RECT  2.304 28.507 8.097 28.679 ;
     RECT  36.864 28.021 37.797 28.679 ;
     RECT  63.288 28.589 63.522 28.679 ;
     RECT  2.304 28.679 5.742 28.949 ;
     RECT  36.468 28.831 36.486 28.949 ;
     RECT  6.588 28.679 8.097 28.985 ;
     RECT  64.44 28.651 68.346 29.027 ;
     RECT  66.708 29.027 68.346 29.029 ;
     RECT  64.44 29.027 65.934 29.057 ;
     RECT  10.515 28.283 10.797 29.065 ;
     RECT  66.708 29.029 68.418 29.101 ;
     RECT  69.516 28.481 69.606 29.101 ;
     RECT  2.304 28.949 3.474 29.117 ;
     RECT  61.815 27.905 62.097 29.179 ;
     RECT  6.804 28.985 8.097 29.191 ;
     RECT  58.716 28.255 59.397 29.219 ;
     RECT  63.504 28.679 63.522 29.219 ;
     RECT  61.815 29.179 62.586 29.255 ;
     RECT  10.515 29.065 10.818 29.291 ;
     RECT  6.804 29.191 8.118 29.371 ;
     RECT  34.815 28.589 35.406 29.461 ;
     RECT  4.248 28.949 5.742 29.489 ;
     RECT  30.78 28.481 30.798 29.489 ;
     RECT  38.772 29.461 38.79 29.561 ;
     RECT  6.804 29.371 8.37 29.633 ;
     RECT  34.776 29.461 35.694 29.633 ;
     RECT  70.632 28.481 70.722 29.669 ;
     RECT  66.708 29.101 69.606 29.759 ;
     RECT  2.304 29.117 3.438 29.875 ;
     RECT  4.248 29.489 4.266 29.875 ;
     RECT  69.264 29.759 69.606 29.899 ;
     RECT  34.776 29.633 35.298 30.029 ;
     RECT  36.216 29.911 36.234 30.029 ;
     RECT  63.18 29.731 63.198 30.029 ;
     RECT  64.44 29.057 65.646 30.029 ;
     RECT  61.815 29.255 62.19 30.109 ;
     RECT  64.44 30.029 64.797 30.145 ;
     RECT  2.304 29.875 4.266 30.271 ;
     RECT  5.115 29.489 5.742 30.271 ;
     RECT  6.804 29.633 8.097 30.271 ;
     RECT  65.592 30.029 65.646 30.307 ;
     RECT  2.304 30.271 5.742 30.335 ;
     RECT  60.984 30.001 61.002 30.335 ;
     RECT  66.708 29.759 68.382 30.371 ;
     RECT  6.588 30.271 8.097 30.479 ;
     RECT  66.924 30.371 68.382 30.541 ;
     RECT  69.264 29.899 70.11 30.541 ;
     RECT  2.304 30.335 5.634 30.569 ;
     RECT  30.78 30.415 30.798 30.569 ;
     RECT  66.924 30.541 70.11 30.569 ;
     RECT  68.724 30.569 70.11 30.641 ;
     RECT  2.304 30.569 5.397 30.677 ;
     RECT  35.856 30.451 35.946 30.677 ;
     RECT  68.724 30.641 69.678 30.794 ;
     RECT  64.296 30.145 64.797 30.847 ;
     RECT  65.592 30.307 65.682 30.847 ;
     RECT  61.815 30.109 62.766 30.883 ;
     RECT  34.776 30.029 35.097 30.919 ;
     RECT  61.815 30.883 62.838 30.955 ;
     RECT  64.224 30.847 65.826 30.991 ;
     RECT  38.772 30.811 38.79 31.019 ;
     RECT  64.224 30.991 66.15 31.019 ;
     RECT  2.304 30.677 3.294 31.109 ;
     RECT  34.416 30.919 35.097 31.109 ;
     RECT  35.856 30.677 35.874 31.189 ;
     RECT  0.216 31.195 0.234 31.325 ;
     RECT  4.356 30.677 5.397 31.339 ;
     RECT  6.732 30.479 8.097 31.339 ;
     RECT  64.296 31.019 66.15 31.351 ;
     RECT  66.924 30.569 67.95 31.351 ;
     RECT  34.776 31.109 35.097 31.387 ;
     RECT  35.82 31.189 35.874 31.387 ;
     RECT  4.356 31.339 8.097 31.421 ;
     RECT  6.84 31.421 8.097 31.423 ;
     RECT  61.815 30.955 63.234 31.459 ;
     RECT  30.78 31.351 30.87 31.523 ;
     RECT  68.724 30.794 69.606 31.523 ;
     RECT  6.84 31.423 8.658 31.531 ;
     RECT  64.296 31.351 67.95 31.531 ;
     RECT  68.724 31.523 68.994 31.531 ;
     RECT  4.356 31.421 5.778 31.621 ;
     RECT  70.704 31.243 70.722 31.723 ;
     RECT  61.815 31.459 63.414 31.757 ;
     RECT  3.996 31.621 5.778 31.793 ;
     RECT  6.84 31.531 9.054 31.793 ;
     RECT  70.704 31.723 70.758 31.867 ;
     RECT  2.304 31.109 2.862 31.891 ;
     RECT  34.776 31.387 35.874 31.891 ;
     RECT  4.356 31.793 5.778 31.901 ;
     RECT  30.78 31.523 30.834 31.919 ;
     RECT  64.296 31.531 68.994 32.099 ;
     RECT  4.356 31.901 5.706 32.237 ;
     RECT  2.304 31.891 3.438 32.333 ;
     RECT  70.056 31.867 70.758 32.333 ;
     RECT  64.296 32.099 68.778 32.341 ;
     RECT  30.816 31.919 30.834 32.459 ;
     RECT  64.116 32.341 68.778 32.495 ;
     RECT  61.815 31.757 63.342 32.503 ;
     RECT  6.84 31.793 8.586 32.539 ;
     RECT  34.776 31.891 35.946 32.611 ;
     RECT  0.54 31.801 0.558 32.621 ;
     RECT  6.84 32.539 8.946 32.639 ;
     RECT  34.776 32.611 36.162 32.639 ;
     RECT  70.056 32.333 70.722 32.683 ;
     RECT  4.716 32.237 5.706 32.729 ;
     RECT  34.776 32.639 35.406 32.729 ;
     RECT  36.144 32.639 36.162 32.729 ;
     RECT  59.115 29.219 59.397 32.809 ;
     RECT  4.716 32.729 5.454 32.873 ;
     RECT  58.716 32.809 59.397 32.909 ;
     RECT  3.744 32.575 3.942 32.971 ;
     RECT  64.44 32.495 68.634 33.053 ;
     RECT  6.948 32.639 8.262 33.071 ;
     RECT  34.776 32.729 35.097 33.115 ;
     RECT  2.304 32.333 2.697 33.151 ;
     RECT  3.744 32.971 4.338 33.151 ;
     RECT  61.815 32.503 63.666 33.241 ;
     RECT  64.44 33.053 66.042 33.241 ;
     RECT  7.815 33.071 8.262 33.269 ;
     RECT  34.272 33.115 35.097 33.269 ;
     RECT  36.576 33.079 36.738 33.269 ;
     RECT  61.815 33.241 66.042 33.293 ;
     RECT  7.815 33.269 8.19 33.377 ;
     RECT  63.756 33.293 66.042 33.377 ;
     RECT  66.888 33.053 68.634 33.385 ;
     RECT  69.516 32.683 70.722 33.385 ;
     RECT  5.115 32.873 5.454 33.511 ;
     RECT  38.736 33.421 38.754 33.511 ;
     RECT  66.888 33.385 70.722 33.533 ;
     RECT  36.576 33.269 36.666 33.539 ;
     RECT  9.108 33.421 9.126 33.575 ;
     RECT  66.888 33.533 68.706 33.581 ;
     RECT  38.664 33.511 38.754 33.611 ;
     RECT  2.304 33.151 4.338 33.629 ;
     RECT  36.576 33.539 36.594 33.647 ;
     RECT  3.888 33.629 4.338 33.655 ;
     RECT  5.115 33.511 5.85 33.655 ;
     RECT  34.776 33.269 35.097 33.655 ;
     RECT  3.888 33.655 5.85 33.691 ;
     RECT  68.544 33.581 68.706 33.809 ;
     RECT  69.516 33.533 70.722 33.881 ;
     RECT  3.888 33.691 6.102 33.889 ;
     RECT  6.948 33.071 7.074 33.889 ;
     RECT  64.188 33.377 66.042 33.925 ;
     RECT  66.888 33.581 67.806 33.925 ;
     RECT  3.888 33.889 7.074 33.961 ;
     RECT  7.815 33.377 8.097 33.961 ;
     RECT  34.776 33.655 35.766 33.989 ;
     RECT  3.888 33.961 8.097 34.151 ;
     RECT  64.188 33.925 67.806 34.157 ;
     RECT  64.188 34.157 65.61 34.195 ;
     RECT  34.815 33.989 35.766 34.231 ;
     RECT  70.092 33.881 70.722 34.315 ;
     RECT  61.815 33.293 62.766 34.321 ;
     RECT  66.636 34.157 67.806 34.321 ;
     RECT  68.544 33.809 68.562 34.321 ;
     RECT  34.815 34.231 36.054 34.349 ;
     RECT  7.815 34.151 8.097 34.465 ;
     RECT  61.815 34.321 62.91 34.493 ;
     RECT  66.636 34.321 68.562 34.493 ;
     RECT  63.756 34.195 65.61 34.529 ;
     RECT  70.092 34.315 70.758 34.529 ;
     RECT  0.216 34.459 0.234 34.589 ;
     RECT  34.815 34.349 35.982 34.619 ;
     RECT  63.972 34.529 65.61 34.619 ;
     RECT  66.636 34.493 68.022 34.619 ;
     RECT  30.852 34.393 30.87 34.627 ;
     RECT  30.78 34.627 30.87 34.691 ;
     RECT  38.736 33.611 38.754 34.691 ;
     RECT  62.892 34.493 62.91 34.691 ;
     RECT  2.304 33.629 2.934 34.735 ;
     RECT  3.888 34.151 7.074 34.735 ;
     RECT  30.78 34.691 30.798 34.763 ;
     RECT  68.94 34.735 68.958 34.843 ;
     RECT  70.092 34.529 70.722 34.843 ;
     RECT  59.115 32.909 59.397 35.005 ;
     RECT  64.44 34.619 65.61 35.005 ;
     RECT  66.636 34.619 67.806 35.005 ;
     RECT  2.304 34.735 7.074 35.041 ;
     RECT  7.815 34.465 8.19 35.041 ;
     RECT  58.752 35.005 59.397 35.041 ;
     RECT  62.964 34.861 63.054 35.069 ;
     RECT  2.304 35.041 8.19 35.159 ;
     RECT  58.716 35.041 59.397 35.159 ;
     RECT  62.964 35.069 62.982 35.159 ;
     RECT  58.752 35.159 59.397 35.231 ;
     RECT  34.815 34.619 35.097 35.311 ;
     RECT  35.964 34.619 35.982 35.339 ;
     RECT  61.815 34.493 62.097 35.509 ;
     RECT  34.74 35.311 35.097 35.573 ;
     RECT  68.94 34.843 70.722 35.573 ;
     RECT  64.44 35.005 67.806 35.581 ;
     RECT  68.652 35.581 68.85 35.699 ;
     RECT  9.036 35.671 9.126 35.743 ;
     RECT  64.44 35.581 67.842 35.771 ;
     RECT  66.564 35.771 67.842 35.779 ;
     RECT  38.772 35.707 38.79 35.807 ;
     RECT  3.996 35.159 8.19 35.843 ;
     RECT  8.964 35.743 9.126 35.843 ;
     RECT  66.564 35.779 68.094 35.879 ;
     RECT  64.44 35.771 65.754 35.899 ;
     RECT  61.815 35.509 62.73 36.049 ;
     RECT  2.304 35.159 3.186 36.211 ;
     RECT  3.996 35.843 6.678 36.211 ;
     RECT  68.832 35.699 68.85 36.239 ;
     RECT  0.252 36.187 0.27 36.317 ;
     RECT  69.696 35.573 70.722 36.475 ;
     RECT  7.815 35.843 8.19 36.509 ;
     RECT  28.512 36.283 28.53 36.509 ;
     RECT  34.815 35.573 35.097 36.517 ;
     RECT  59.115 35.231 59.397 36.589 ;
     RECT  64.188 35.899 65.754 36.589 ;
     RECT  63.612 36.589 65.754 36.625 ;
     RECT  66.564 35.879 67.554 36.625 ;
     RECT  58.788 36.589 59.397 36.661 ;
     RECT  61.815 36.049 62.766 36.661 ;
     RECT  63.612 36.625 67.554 36.661 ;
     RECT  58.716 36.661 59.397 36.779 ;
     RECT  61.815 36.661 67.554 36.779 ;
     RECT  61.815 36.779 62.91 36.815 ;
     RECT  9.108 36.751 9.126 36.823 ;
     RECT  34.776 36.517 35.097 36.823 ;
     RECT  63.684 36.779 67.554 36.823 ;
     RECT  68.508 36.751 68.598 36.823 ;
     RECT  9.036 36.823 9.126 36.851 ;
     RECT  63.684 36.823 68.598 36.851 ;
     RECT  2.304 36.211 6.678 36.895 ;
     RECT  9.036 36.851 9.054 36.959 ;
     RECT  38.808 36.787 38.826 36.959 ;
     RECT  2.304 36.895 7.074 37.049 ;
     RECT  69.516 36.475 70.722 37.099 ;
     RECT  69.336 37.099 70.722 37.193 ;
     RECT  61.815 36.815 62.73 37.229 ;
     RECT  69.336 37.193 70.11 37.291 ;
     RECT  6.552 37.049 7.074 37.399 ;
     RECT  7.815 36.509 8.097 37.399 ;
     RECT  34.632 36.823 35.097 37.399 ;
     RECT  34.272 37.399 35.097 37.435 ;
     RECT  69.3 37.291 70.11 37.463 ;
     RECT  34.272 37.435 35.298 37.471 ;
     RECT  2.304 37.049 5.778 37.589 ;
     RECT  6.552 37.399 8.097 37.589 ;
     RECT  34.272 37.471 35.73 37.589 ;
     RECT  34.344 37.589 35.298 37.625 ;
     RECT  2.304 37.589 3.33 37.819 ;
     RECT  2.088 37.819 3.33 37.949 ;
     RECT  4.104 37.589 5.598 37.949 ;
     RECT  69.552 37.463 70.11 38.003 ;
     RECT  2.304 37.949 3.33 38.129 ;
     RECT  34.815 37.625 35.298 38.129 ;
     RECT  36.216 37.867 36.306 38.129 ;
     RECT  6.588 37.589 8.097 38.165 ;
     RECT  2.304 38.129 2.754 38.189 ;
     RECT  37.515 28.679 37.797 38.209 ;
     RECT  61.815 37.229 62.097 38.209 ;
     RECT  64.368 36.851 68.526 38.237 ;
     RECT  61.815 38.209 62.802 38.245 ;
     RECT  60.444 37.975 60.462 38.273 ;
     RECT  59.115 36.779 59.397 38.281 ;
     RECT  66.564 38.237 68.526 38.281 ;
     RECT  69.336 38.251 69.354 38.281 ;
     RECT  38.664 38.245 38.682 38.371 ;
     RECT  64.368 38.237 65.826 38.395 ;
     RECT  58.788 38.281 59.397 38.399 ;
     RECT  4.428 37.949 5.598 38.407 ;
     RECT  8.928 38.371 8.946 38.443 ;
     RECT  38.664 38.371 38.718 38.443 ;
     RECT  38.664 38.443 38.79 38.507 ;
     RECT  30.78 37.399 30.798 38.543 ;
     RECT  6.804 38.165 8.097 38.579 ;
     RECT  38.772 38.507 38.79 38.579 ;
     RECT  66.564 38.281 69.354 38.621 ;
     RECT  34.815 38.129 35.097 38.641 ;
     RECT  36.612 38.209 37.797 38.669 ;
     RECT  61.815 38.245 63.27 38.669 ;
     RECT  66.564 38.621 68.922 38.669 ;
     RECT  70.092 38.003 70.11 38.731 ;
     RECT  34.776 38.641 35.097 38.741 ;
     RECT  3.492 38.551 3.51 38.821 ;
     RECT  70.092 38.731 70.722 38.923 ;
     RECT  63.18 38.669 63.27 38.947 ;
     RECT  4.428 38.407 5.994 38.983 ;
     RECT  64.332 38.395 65.826 38.983 ;
     RECT  6.876 38.579 8.097 39.019 ;
     RECT  8.892 38.443 8.946 39.019 ;
     RECT  10.515 29.291 10.797 39.019 ;
     RECT  34.815 38.741 35.097 39.019 ;
     RECT  36.036 38.983 36.162 39.019 ;
     RECT  64.332 38.983 65.898 39.019 ;
     RECT  59.115 38.399 59.397 39.055 ;
     RECT  6.876 39.019 8.946 39.091 ;
     RECT  2.304 38.189 2.697 39.181 ;
     RECT  3.492 38.821 3.654 39.181 ;
     RECT  4.428 38.983 6.03 39.181 ;
     RECT  6.876 39.091 9.162 39.209 ;
     RECT  34.815 39.019 36.162 39.209 ;
     RECT  64.116 39.019 65.898 39.209 ;
     RECT  0.216 39.115 0.234 39.245 ;
     RECT  2.304 39.181 6.03 39.341 ;
     RECT  63.18 38.947 63.342 39.361 ;
     RECT  59.115 39.055 59.886 39.389 ;
     RECT  65.628 39.209 65.718 39.389 ;
     RECT  3.744 39.341 6.03 39.451 ;
     RECT  10.515 39.019 10.854 39.479 ;
     RECT  35.892 39.209 35.91 39.479 ;
     RECT  66.672 38.669 68.922 39.547 ;
     RECT  69.66 38.923 70.722 39.547 ;
     RECT  8.928 39.209 8.982 39.551 ;
     RECT  61.815 38.669 62.097 39.721 ;
     RECT  63.18 39.361 63.666 39.721 ;
     RECT  8.928 39.551 8.946 39.749 ;
     RECT  66.672 39.547 70.722 39.749 ;
     RECT  3.744 39.451 6.102 39.785 ;
     RECT  69.516 39.749 70.722 39.821 ;
     RECT  69.588 39.821 70.722 39.883 ;
     RECT  34.815 39.209 35.097 39.991 ;
     RECT  65.7 39.389 65.718 39.991 ;
     RECT  66.672 39.749 67.497 39.991 ;
     RECT  69.588 39.883 70.758 40.013 ;
     RECT  68.292 39.749 68.778 40.019 ;
     RECT  61.815 39.721 63.666 40.027 ;
     RECT  64.44 39.209 64.797 40.027 ;
     RECT  68.364 40.019 68.778 40.091 ;
     RECT  4.284 39.785 6.102 40.135 ;
     RECT  6.876 39.209 6.894 40.135 ;
     RECT  30.78 39.361 30.798 40.163 ;
     RECT  61.815 40.027 64.797 40.171 ;
     RECT  65.7 39.991 67.497 40.171 ;
     RECT  4.284 40.135 6.894 40.199 ;
     RECT  61.815 40.171 67.497 40.199 ;
     RECT  34.815 39.991 35.802 40.289 ;
     RECT  64.116 40.199 67.497 40.289 ;
     RECT  61.815 40.199 63.126 40.349 ;
     RECT  10.515 39.479 10.797 40.369 ;
     RECT  69.588 40.013 70.722 40.397 ;
     RECT  64.188 40.289 67.497 40.469 ;
     RECT  2.304 39.341 2.826 40.531 ;
     RECT  34.815 40.289 35.154 40.531 ;
     RECT  38.736 39.325 38.754 40.531 ;
     RECT  68.436 40.091 68.778 40.559 ;
     RECT  4.284 40.199 4.374 40.567 ;
     RECT  38.664 40.531 38.754 40.567 ;
     RECT  7.815 39.209 8.097 40.603 ;
     RECT  68.436 40.559 68.706 40.631 ;
     RECT  2.304 40.531 3.15 40.675 ;
     RECT  3.96 40.567 4.374 40.675 ;
     RECT  5.115 40.199 6.894 40.675 ;
     RECT  7.815 40.603 8.262 40.675 ;
     RECT  5.115 40.675 8.262 40.711 ;
     RECT  34.776 40.531 35.154 40.739 ;
     RECT  38.664 40.567 38.79 40.739 ;
     RECT  34.776 40.739 35.097 40.937 ;
     RECT  64.188 40.469 64.797 41.021 ;
     RECT  69.588 40.397 70.11 41.035 ;
     RECT  2.304 40.675 4.374 41.071 ;
     RECT  5.115 40.711 8.298 41.071 ;
     RECT  10.515 40.369 10.818 41.071 ;
     RECT  60.984 40.405 61.002 41.135 ;
     RECT  2.304 41.071 8.298 41.143 ;
     RECT  69.516 41.035 70.11 41.171 ;
     RECT  67.215 40.469 67.497 41.179 ;
     RECT  68.436 40.631 68.526 41.179 ;
     RECT  69.66 41.171 70.11 41.179 ;
     RECT  38.772 40.739 38.79 41.207 ;
     RECT  2.304 41.143 8.478 41.251 ;
     RECT  36.684 41.215 36.702 41.251 ;
     RECT  61.815 40.349 62.766 41.251 ;
     RECT  10.515 41.071 10.854 41.341 ;
     RECT  36.468 41.251 36.702 41.341 ;
     RECT  65.7 40.469 66.222 41.341 ;
     RECT  67.215 41.179 68.526 41.341 ;
     RECT  36.36 41.341 36.702 41.369 ;
     RECT  64.224 41.021 64.797 41.369 ;
     RECT  10.515 41.341 10.926 41.441 ;
     RECT  36.36 41.369 36.486 41.441 ;
     RECT  59.115 39.389 59.397 41.449 ;
     RECT  30.78 41.215 30.798 41.477 ;
     RECT  61.815 41.251 63.378 41.513 ;
     RECT  58.716 41.449 59.397 41.549 ;
     RECT  2.304 41.251 9.018 41.597 ;
     RECT  61.815 41.513 63.306 41.597 ;
     RECT  65.7 41.341 68.526 41.647 ;
     RECT  6.84 41.597 9.018 41.648 ;
     RECT  6.84 41.648 8.478 41.675 ;
     RECT  64.515 41.369 64.797 41.749 ;
     RECT  65.592 41.647 68.526 41.749 ;
     RECT  61.815 41.597 62.802 41.819 ;
     RECT  64.515 41.749 68.526 42.061 ;
     RECT  9.396 41.791 9.414 42.089 ;
     RECT  36.468 41.441 36.486 42.151 ;
     RECT  64.515 42.061 68.634 42.187 ;
     RECT  36.468 42.151 36.666 42.223 ;
     RECT  69.66 41.179 70.722 42.251 ;
     RECT  0.54 41.953 0.558 42.269 ;
     RECT  35.964 42.223 36.666 42.287 ;
     RECT  6.84 41.675 8.097 42.331 ;
     RECT  34.815 40.937 35.097 42.331 ;
     RECT  64.44 42.187 68.634 42.331 ;
     RECT  69.66 42.251 69.678 42.331 ;
     RECT  64.44 42.331 69.678 42.379 ;
     RECT  2.304 41.597 5.778 42.421 ;
     RECT  6.732 42.331 8.097 42.421 ;
     RECT  34.776 42.331 35.097 42.449 ;
     RECT  64.26 42.379 69.678 42.449 ;
     RECT  2.304 42.421 8.37 42.521 ;
     RECT  38.736 42.421 38.754 42.529 ;
     RECT  38.664 42.529 38.754 42.557 ;
     RECT  34.815 42.449 35.097 42.601 ;
     RECT  35.964 42.287 36.558 42.601 ;
     RECT  61.815 41.819 62.73 42.601 ;
     RECT  2.304 42.521 8.298 42.629 ;
     RECT  38.664 42.557 38.682 42.629 ;
     RECT  4.176 42.629 8.298 42.719 ;
     RECT  34.815 42.601 36.558 42.755 ;
     RECT  61.815 42.601 62.802 42.755 ;
     RECT  64.404 42.449 69.678 42.755 ;
     RECT  0.216 42.691 0.234 42.797 ;
     RECT  4.176 42.719 8.097 42.989 ;
     RECT  63.648 42.811 63.666 42.989 ;
     RECT  66.528 42.755 69.678 43.003 ;
     RECT  70.704 42.251 70.722 43.003 ;
     RECT  4.176 42.989 5.994 43.037 ;
     RECT  34.815 42.755 35.73 43.061 ;
     RECT  10.515 41.441 10.797 43.069 ;
     RECT  10.515 43.069 10.818 43.169 ;
     RECT  2.304 42.629 3.222 43.259 ;
     RECT  64.404 42.755 65.718 43.259 ;
     RECT  64.404 43.259 64.926 43.267 ;
     RECT  4.176 43.037 5.397 43.501 ;
     RECT  34.815 43.061 35.406 43.529 ;
     RECT  30.852 43.339 30.87 43.601 ;
     RECT  38.736 43.501 38.754 43.601 ;
     RECT  66.528 43.003 70.722 43.601 ;
     RECT  65.664 43.259 65.718 43.609 ;
     RECT  66.528 43.601 68.706 43.609 ;
     RECT  6.84 42.989 8.097 43.681 ;
     RECT  69.516 43.601 70.722 43.709 ;
     RECT  61.815 42.755 62.766 43.771 ;
     RECT  3.816 43.501 5.397 43.951 ;
     RECT  36.216 43.645 36.234 43.951 ;
     RECT  61.815 43.771 62.802 43.951 ;
     RECT  3.816 43.951 5.706 44.069 ;
     RECT  36.216 43.951 36.306 44.069 ;
     RECT  2.304 43.259 2.898 44.185 ;
     RECT  3.816 44.069 4.374 44.185 ;
     RECT  34.815 43.529 35.097 44.185 ;
     RECT  6.84 43.681 8.946 44.221 ;
     RECT  64.368 43.267 64.926 44.221 ;
     RECT  65.664 43.609 68.706 44.221 ;
     RECT  61.815 43.951 63.234 44.311 ;
     RECT  6.84 44.221 9.162 44.339 ;
     RECT  34.308 44.185 35.097 44.339 ;
     RECT  64.368 44.221 68.706 44.339 ;
     RECT  64.368 44.339 67.842 44.347 ;
     RECT  59.115 41.549 59.397 44.383 ;
     RECT  6.84 44.339 9.09 44.411 ;
     RECT  34.38 44.339 35.097 44.411 ;
     RECT  61.815 44.311 63.306 44.411 ;
     RECT  68.688 44.339 68.706 44.411 ;
     RECT  5.115 44.069 5.706 44.443 ;
     RECT  30.852 44.347 30.87 44.447 ;
     RECT  61.815 44.411 63.09 44.477 ;
     RECT  6.84 44.411 8.694 44.491 ;
     RECT  34.488 44.411 35.097 44.609 ;
     RECT  69.552 43.709 70.722 44.635 ;
     RECT  38.736 44.347 38.754 44.681 ;
     RECT  6.804 44.491 8.694 44.717 ;
     RECT  34.815 44.609 35.097 44.761 ;
     RECT  36.108 44.725 36.126 44.761 ;
     RECT  69.516 44.635 70.722 44.761 ;
     RECT  58.788 44.383 59.397 44.789 ;
     RECT  61.815 44.477 63.054 44.789 ;
     RECT  61.815 44.789 62.982 44.879 ;
     RECT  64.188 44.347 67.842 44.879 ;
     RECT  68.976 44.761 70.722 44.879 ;
     RECT  32.115 18.059 32.397 44.923 ;
     RECT  2.304 44.185 4.374 44.951 ;
     RECT  69.444 44.879 70.722 44.971 ;
     RECT  30.78 44.887 30.798 44.987 ;
     RECT  32.115 44.923 33.102 45.059 ;
     RECT  60.444 44.761 60.462 45.149 ;
     RECT  3.744 44.951 4.374 45.185 ;
     RECT  6.84 44.717 8.694 45.185 ;
     RECT  38.772 45.121 38.79 45.221 ;
     RECT  65.628 44.879 67.842 45.229 ;
     RECT  69.444 44.971 70.758 45.293 ;
     RECT  3.816 45.185 4.374 45.301 ;
     RECT  5.115 44.443 5.85 45.301 ;
     RECT  34.815 44.761 36.126 45.301 ;
     RECT  65.628 45.229 67.95 45.301 ;
     RECT  34.815 45.301 36.378 45.419 ;
     RECT  6.84 45.185 6.858 45.491 ;
     RECT  7.815 45.185 8.694 45.491 ;
     RECT  61.815 44.879 62.73 45.491 ;
     RECT  3.816 45.301 5.85 45.571 ;
     RECT  64.188 44.879 64.797 45.595 ;
     RECT  65.628 45.301 68.562 45.599 ;
     RECT  63.72 45.595 64.797 45.661 ;
     RECT  63.72 45.661 64.89 45.689 ;
     RECT  2.304 44.951 2.826 45.725 ;
     RECT  64.188 45.689 64.89 45.725 ;
     RECT  3.816 45.571 6.138 45.869 ;
     RECT  66.492 45.599 68.526 45.869 ;
     RECT  9.144 45.841 9.162 45.959 ;
     RECT  3.816 45.869 6.03 46.067 ;
     RECT  38.736 45.967 38.754 46.067 ;
     RECT  30.78 45.841 30.798 46.103 ;
     RECT  65.628 45.599 65.718 46.273 ;
     RECT  6.912 46.201 6.93 46.345 ;
     RECT  34.815 45.419 35.802 46.345 ;
     RECT  3.816 46.067 5.814 46.381 ;
     RECT  61.815 45.491 62.097 46.381 ;
     RECT  69.444 45.293 70.11 46.411 ;
     RECT  64.188 45.725 64.797 46.471 ;
     RECT  65.592 46.273 65.718 46.471 ;
     RECT  7.815 45.491 8.37 46.499 ;
     RECT  2.304 45.725 2.754 46.507 ;
     RECT  3.492 46.381 5.814 46.507 ;
     RECT  6.84 46.345 6.93 46.507 ;
     RECT  34.74 46.345 35.802 46.507 ;
     RECT  34.704 46.507 35.802 46.543 ;
     RECT  34.704 46.543 35.982 46.607 ;
     RECT  69.444 46.411 70.146 46.607 ;
     RECT  66.492 45.869 68.094 46.651 ;
     RECT  69.588 46.607 70.146 46.747 ;
     RECT  66.492 46.651 68.778 46.769 ;
     RECT  65.556 46.471 65.718 46.777 ;
     RECT  66.492 46.769 68.526 46.777 ;
     RECT  2.304 46.507 5.814 46.813 ;
     RECT  69.588 46.747 70.722 46.841 ;
     RECT  6.84 46.507 6.966 46.849 ;
     RECT  64.152 46.471 64.797 46.849 ;
     RECT  6.696 46.849 6.966 46.885 ;
     RECT  7.815 46.499 8.226 46.885 ;
     RECT  34.815 46.607 35.982 46.885 ;
     RECT  69.588 46.841 70.146 46.913 ;
     RECT  64.08 46.849 64.797 46.921 ;
     RECT  65.556 46.777 68.526 46.921 ;
     RECT  2.304 46.813 5.922 46.987 ;
     RECT  2.268 46.987 5.922 47.039 ;
     RECT  6.696 46.885 8.226 47.039 ;
     RECT  34.815 46.885 36.054 47.039 ;
     RECT  38.664 46.777 38.682 47.047 ;
     RECT  38.664 47.047 38.826 47.083 ;
     RECT  45.615 10.157 45.897 47.083 ;
     RECT  53.715 10.157 53.997 47.083 ;
     RECT  64.08 46.921 68.526 47.111 ;
     RECT  69.588 46.913 70.11 47.111 ;
     RECT  38.628 47.083 38.826 47.147 ;
     RECT  2.304 47.039 5.922 47.191 ;
     RECT  6.696 47.039 6.93 47.191 ;
     RECT  38.628 47.147 38.79 47.213 ;
     RECT  45.615 47.083 45.99 47.213 ;
     RECT  46.764 47.083 46.782 47.213 ;
     RECT  53.715 47.083 54.738 47.213 ;
     RECT  64.08 47.111 68.382 47.309 ;
     RECT  0.54 47.119 0.558 47.357 ;
     RECT  2.304 47.191 6.93 47.357 ;
     RECT  69.588 47.111 69.966 47.419 ;
     RECT  64.26 47.309 68.382 47.453 ;
     RECT  7.815 47.039 8.226 47.461 ;
     RECT  69.372 47.419 69.966 47.563 ;
     RECT  61.815 46.381 62.766 47.587 ;
     RECT  69.336 47.563 69.966 47.651 ;
     RECT  69.336 47.651 69.714 47.687 ;
     RECT  34.815 47.039 35.73 47.695 ;
     RECT  7.815 47.461 8.37 47.723 ;
     RECT  69.372 47.687 69.714 47.723 ;
     RECT  9.216 47.353 9.234 47.731 ;
     RECT  9.144 47.731 9.234 47.759 ;
     RECT  66.564 47.453 68.382 47.759 ;
     RECT  9.144 47.759 9.162 47.849 ;
     RECT  34.812 47.695 35.73 47.857 ;
     RECT  69.516 47.723 69.714 47.885 ;
     RECT  2.304 47.357 5.814 47.933 ;
     RECT  34.2 47.857 35.73 47.965 ;
     RECT  6.804 47.357 6.93 48.001 ;
     RECT  7.815 47.723 8.19 48.001 ;
     RECT  66.636 47.759 68.382 48.001 ;
     RECT  34.2 47.965 36.126 48.029 ;
     RECT  34.416 48.029 36.126 48.119 ;
     RECT  64.26 47.453 65.79 48.163 ;
     RECT  6.804 48.001 8.19 48.299 ;
     RECT  70.704 48.091 70.722 48.299 ;
     RECT  61.815 47.587 62.802 48.361 ;
     RECT  6.804 48.299 6.894 48.379 ;
     RECT  69.696 47.885 69.714 48.379 ;
     RECT  2.304 47.933 5.562 48.389 ;
     RECT  8.928 48.271 8.946 48.389 ;
     RECT  34.416 48.119 35.838 48.389 ;
     RECT  63.864 48.163 65.79 48.389 ;
     RECT  6.66 48.379 6.894 48.413 ;
     RECT  2.304 48.389 3.654 48.461 ;
     RECT  4.716 48.389 5.562 48.461 ;
     RECT  34.416 48.389 35.514 48.461 ;
     RECT  0.216 48.361 0.234 48.509 ;
     RECT  66.636 48.001 68.562 48.541 ;
     RECT  64.44 48.389 65.79 48.619 ;
     RECT  66.636 48.541 68.922 48.619 ;
     RECT  64.44 48.619 68.922 48.715 ;
     RECT  69.696 48.379 70.182 48.715 ;
     RECT  64.44 48.715 70.182 48.731 ;
     RECT  59.115 44.789 59.397 48.775 ;
     RECT  69.516 48.731 70.182 48.839 ;
     RECT  64.44 48.731 68.706 48.929 ;
     RECT  7.632 48.299 8.19 49.001 ;
     RECT  61.815 48.361 63.126 49.009 ;
     RECT  34.416 48.461 35.406 49.081 ;
     RECT  4.824 48.461 5.562 49.171 ;
     RECT  9.144 48.811 9.162 49.171 ;
     RECT  69.552 48.839 70.182 49.195 ;
     RECT  34.308 49.081 35.406 49.199 ;
     RECT  66.42 48.929 68.706 49.199 ;
     RECT  30.78 48.901 30.798 49.207 ;
     RECT  6.66 48.413 6.858 49.243 ;
     RECT  34.488 49.199 35.406 49.243 ;
     RECT  4.824 49.171 5.778 49.279 ;
     RECT  34.488 49.243 36.018 49.279 ;
     RECT  9.144 49.171 9.234 49.307 ;
     RECT  30.78 49.207 30.87 49.307 ;
     RECT  6.66 49.243 7.074 49.351 ;
     RECT  4.716 49.279 5.778 49.441 ;
     RECT  61.815 49.009 63.27 49.441 ;
     RECT  4.032 49.441 5.778 49.469 ;
     RECT  6.552 49.351 7.074 49.469 ;
     RECT  9.144 49.307 9.162 49.469 ;
     RECT  34.488 49.279 36.09 49.469 ;
     RECT  6.552 49.469 6.93 49.517 ;
     RECT  7.815 49.001 8.19 49.517 ;
     RECT  61.815 49.441 63.63 49.528 ;
     RECT  4.032 49.469 4.05 49.541 ;
     RECT  69.552 49.195 70.722 49.541 ;
     RECT  63.612 49.528 63.63 49.577 ;
     RECT  66.42 49.199 68.382 49.577 ;
     RECT  58.716 48.775 59.397 49.649 ;
     RECT  0.54 49.549 0.558 49.661 ;
     RECT  69.552 49.541 70.11 49.723 ;
     RECT  34.524 49.469 35.097 49.739 ;
     RECT  2.304 48.461 3.294 49.783 ;
     RECT  64.44 48.929 65.682 49.819 ;
     RECT  66.42 49.577 67.986 49.819 ;
     RECT  69.444 49.723 70.11 49.867 ;
     RECT  30.78 49.307 30.798 49.883 ;
     RECT  5.076 49.469 5.778 49.891 ;
     RECT  6.552 49.517 6.822 49.891 ;
     RECT  69.408 49.867 70.11 50.153 ;
     RECT  60.444 50.089 60.462 50.189 ;
     RECT  5.076 49.891 6.822 50.251 ;
     RECT  7.815 49.517 8.097 50.251 ;
     RECT  36.108 50.161 36.126 50.251 ;
     RECT  61.815 49.528 62.73 50.251 ;
     RECT  2.304 49.783 3.726 50.279 ;
     RECT  35.856 50.251 36.126 50.279 ;
     RECT  34.815 49.739 35.097 50.287 ;
     RECT  35.856 50.279 35.874 50.287 ;
     RECT  64.44 49.819 67.986 50.315 ;
     RECT  5.076 50.251 7.074 50.323 ;
     RECT  67.215 50.315 67.986 50.323 ;
     RECT  69.48 50.153 70.11 50.351 ;
     RECT  69.48 50.351 69.57 50.423 ;
     RECT  4.5 50.323 7.074 50.431 ;
     RECT  7.815 50.251 8.154 50.431 ;
     RECT  61.815 50.251 62.802 50.431 ;
     RECT  2.304 50.279 3.294 50.477 ;
     RECT  4.5 50.431 8.154 50.549 ;
     RECT  34.815 50.287 35.874 50.549 ;
     RECT  64.44 50.315 66.042 50.549 ;
     RECT  10.515 43.169 10.797 50.557 ;
     RECT  34.815 50.549 35.694 50.557 ;
     RECT  61.815 50.431 63.09 50.585 ;
     RECT  64.44 50.549 65.826 50.585 ;
     RECT  67.215 50.323 68.274 50.621 ;
     RECT  10.515 50.557 10.854 50.657 ;
     RECT  14.832 50.557 14.85 50.657 ;
     RECT  34.776 50.557 35.694 50.657 ;
     RECT  4.5 50.549 8.097 50.665 ;
     RECT  13.215 2.413 13.497 50.665 ;
     RECT  18.615 10.229 18.897 50.665 ;
     RECT  21.315 10.157 21.597 50.665 ;
     RECT  34.776 50.657 35.097 50.701 ;
     RECT  61.815 50.585 62.802 50.729 ;
     RECT  15.915 2.413 16.197 50.731 ;
     RECT  18.504 50.665 18.897 50.765 ;
     RECT  21.204 50.665 21.597 50.765 ;
     RECT  13.104 50.665 13.497 50.813 ;
     RECT  11.592 50.779 11.61 50.819 ;
     RECT  34.416 50.701 35.097 50.819 ;
     RECT  70.704 50.539 70.722 50.827 ;
     RECT  15.804 50.731 16.197 50.855 ;
     RECT  64.44 50.585 65.754 50.863 ;
     RECT  10.515 50.657 10.818 50.891 ;
     RECT  38.772 50.791 38.79 50.891 ;
     RECT  14.868 50.863 14.886 50.963 ;
     RECT  30.78 50.971 30.798 51.061 ;
     RECT  67.215 50.621 68.166 51.061 ;
     RECT  13.14 50.813 13.497 51.149 ;
     RECT  22.824 50.731 22.842 51.149 ;
     RECT  30.78 51.061 30.87 51.161 ;
     RECT  69.516 50.423 69.57 51.161 ;
     RECT  70.704 50.827 70.758 51.163 ;
     RECT  4.212 50.665 8.097 51.197 ;
     RECT  34.524 50.819 35.097 51.233 ;
     RECT  2.415 50.477 3.294 51.259 ;
     RECT  30.78 51.161 30.798 51.269 ;
     RECT  61.815 50.729 62.766 51.269 ;
     RECT  66.672 51.061 68.166 51.269 ;
     RECT  69.588 51.163 70.758 51.431 ;
     RECT  0.54 50.521 0.558 51.437 ;
     RECT  37.515 38.669 37.797 51.439 ;
     RECT  34.815 51.233 35.097 51.475 ;
     RECT  63.972 50.863 65.754 51.511 ;
     RECT  2.304 51.259 3.294 51.601 ;
     RECT  4.212 51.197 5.397 51.601 ;
     RECT  2.304 51.601 5.397 51.629 ;
     RECT  6.264 51.197 8.097 51.629 ;
     RECT  34.815 51.475 35.658 51.629 ;
     RECT  36.828 51.439 37.797 51.629 ;
     RECT  67.215 51.269 68.166 51.673 ;
     RECT  63.972 51.511 66.474 51.869 ;
     RECT  36 51.781 36.018 51.899 ;
     RECT  69.588 51.431 70.722 51.979 ;
     RECT  34.815 51.629 35.19 52.015 ;
     RECT  38.736 51.907 38.754 52.043 ;
     RECT  59.115 49.649 59.397 52.051 ;
     RECT  63.972 51.869 65.97 52.051 ;
     RECT  0.216 51.979 0.234 52.109 ;
     RECT  6.336 51.629 8.097 52.141 ;
     RECT  61.815 51.269 62.097 52.141 ;
     RECT  63.144 51.871 63.162 52.141 ;
     RECT  67.215 51.673 68.526 52.141 ;
     RECT  34.776 52.015 35.19 52.169 ;
     RECT  58.716 52.051 59.397 52.169 ;
     RECT  61.815 52.141 63.162 52.169 ;
     RECT  30.96 52.051 30.978 52.213 ;
     RECT  67.212 52.141 68.526 52.249 ;
     RECT  69.372 51.979 70.722 52.249 ;
     RECT  67.212 52.249 70.722 52.285 ;
     RECT  30.78 52.213 30.978 52.349 ;
     RECT  38.772 52.141 38.79 52.349 ;
     RECT  2.415 51.629 5.397 52.411 ;
     RECT  59.115 52.169 59.397 52.411 ;
     RECT  63.936 52.051 65.97 52.411 ;
     RECT  2.304 52.411 5.454 52.439 ;
     RECT  30.78 52.349 30.906 52.439 ;
     RECT  63.72 52.411 65.97 52.439 ;
     RECT  66.744 52.285 70.722 52.439 ;
     RECT  6.336 52.141 8.154 52.445 ;
     RECT  4.536 52.439 5.454 52.498 ;
     RECT  69.408 52.439 70.722 52.511 ;
     RECT  4.752 52.498 5.454 52.591 ;
     RECT  6.768 52.445 8.154 52.591 ;
     RECT  34.815 52.169 35.19 52.591 ;
     RECT  35.928 52.483 35.946 52.591 ;
     RECT  59.115 52.411 59.886 52.619 ;
     RECT  2.304 52.439 3.654 52.709 ;
     RECT  4.752 52.591 5.85 52.709 ;
     RECT  3.492 52.709 3.654 52.745 ;
     RECT  2.304 52.709 2.754 52.781 ;
     RECT  66.744 52.439 68.49 52.781 ;
     RECT  3.564 52.745 3.654 52.853 ;
     RECT  69.408 52.511 70.11 52.889 ;
     RECT  9.072 52.789 9.09 52.979 ;
     RECT  34.815 52.591 35.946 52.979 ;
     RECT  61.815 52.169 62.802 52.979 ;
     RECT  63.72 52.439 65.826 53.015 ;
     RECT  3.636 52.853 3.654 53.221 ;
     RECT  4.752 52.709 5.778 53.221 ;
     RECT  66.744 52.781 68.418 53.221 ;
     RECT  6.768 52.591 8.262 53.249 ;
     RECT  30.78 52.439 30.798 53.321 ;
     RECT  69.516 52.889 70.11 53.323 ;
     RECT  3.636 53.221 5.778 53.357 ;
     RECT  7.38 53.249 8.262 53.401 ;
     RECT  66.708 53.221 68.418 53.491 ;
     RECT  34.815 52.979 35.838 53.519 ;
     RECT  63.72 53.015 65.61 53.527 ;
     RECT  6.624 53.401 6.642 53.591 ;
     RECT  7.38 53.401 8.334 53.591 ;
     RECT  3.78 53.357 5.778 53.597 ;
     RECT  69.516 53.323 70.722 53.611 ;
     RECT  2.304 52.781 2.697 53.671 ;
     RECT  4.752 53.597 5.778 53.671 ;
     RECT  66.672 53.491 68.418 53.699 ;
     RECT  62.82 53.527 65.61 53.755 ;
     RECT  34.815 53.519 35.097 53.797 ;
     RECT  37.515 51.629 37.797 53.797 ;
     RECT  61.815 52.979 62.097 53.797 ;
     RECT  62.82 53.755 65.754 53.797 ;
     RECT  35.82 53.519 35.838 53.869 ;
     RECT  36.828 53.797 37.797 53.869 ;
     RECT  59.115 52.619 59.397 53.905 ;
     RECT  61.815 53.797 65.754 53.905 ;
     RECT  66.672 53.699 68.382 53.905 ;
     RECT  4.752 53.671 5.814 53.933 ;
     RECT  69.444 53.611 70.722 53.933 ;
     RECT  2.304 53.671 2.862 53.941 ;
     RECT  10.515 50.891 10.797 53.941 ;
     RECT  58.788 53.905 59.397 53.941 ;
     RECT  3.78 53.597 3.942 54.059 ;
     RECT  35.82 53.869 37.797 54.059 ;
     RECT  38.736 53.941 38.754 54.059 ;
     RECT  7.38 53.591 8.097 54.067 ;
     RECT  3.924 54.059 3.942 54.131 ;
     RECT  58.716 53.941 59.397 54.131 ;
     RECT  35.82 54.059 36.558 54.167 ;
     RECT  69.516 53.933 70.722 54.203 ;
     RECT  61.815 53.905 68.382 54.329 ;
     RECT  4.752 53.933 5.742 54.331 ;
     RECT  30.852 54.301 30.87 54.337 ;
     RECT  4.392 54.331 5.742 54.401 ;
     RECT  30.78 54.337 30.87 54.401 ;
     RECT  69.516 54.203 70.11 54.401 ;
     RECT  8.856 53.761 8.91 54.409 ;
     RECT  2.304 53.941 2.97 54.445 ;
     RECT  7.236 54.067 8.097 54.445 ;
     RECT  34.776 53.797 35.097 54.445 ;
     RECT  10.515 53.941 10.818 54.509 ;
     RECT  2.304 54.445 3.186 54.599 ;
     RECT  8.856 54.409 9.054 54.599 ;
     RECT  34.776 54.445 35.298 54.599 ;
     RECT  36.468 54.167 36.558 54.599 ;
     RECT  7.236 54.445 8.118 54.607 ;
     RECT  6.912 54.607 8.118 54.635 ;
     RECT  30.78 54.401 30.798 54.671 ;
     RECT  69.516 54.401 70.074 54.671 ;
     RECT  63.612 54.329 68.382 54.749 ;
     RECT  66.564 54.749 68.382 54.751 ;
     RECT  4.464 54.401 5.742 54.841 ;
     RECT  63.612 54.749 65.682 54.869 ;
     RECT  66.564 54.751 68.526 54.869 ;
     RECT  4.464 54.841 6.102 54.893 ;
     RECT  69.516 54.671 69.714 54.955 ;
     RECT  7.815 54.635 8.118 55.099 ;
     RECT  69.3 54.955 69.714 55.099 ;
     RECT  69.264 55.099 69.714 55.211 ;
     RECT  34.776 54.599 35.262 55.219 ;
     RECT  34.416 55.219 35.262 55.247 ;
     RECT  69.3 55.211 69.714 55.247 ;
     RECT  0.252 55.003 0.27 55.277 ;
     RECT  34.416 55.247 35.097 55.291 ;
     RECT  61.815 54.329 62.802 55.291 ;
     RECT  2.304 54.599 2.898 55.381 ;
     RECT  34.272 55.291 35.097 55.409 ;
     RECT  61.815 55.291 63.414 55.409 ;
     RECT  7.815 55.099 8.334 55.417 ;
     RECT  10.515 54.509 10.797 55.48 ;
     RECT  10.515 55.48 10.818 55.489 ;
     RECT  64.44 54.869 65.682 55.489 ;
     RECT  66.564 54.869 68.454 55.489 ;
     RECT  2.304 55.381 2.934 55.553 ;
     RECT  69.516 55.247 69.714 55.579 ;
     RECT  70.704 55.243 70.722 55.579 ;
     RECT  10.476 55.489 10.818 55.589 ;
     RECT  7.815 55.417 8.442 55.651 ;
     RECT  9.396 55.417 9.414 55.651 ;
     RECT  36 55.561 36.018 55.679 ;
     RECT  61.815 55.409 63.054 55.679 ;
     RECT  10.515 55.589 10.818 55.687 ;
     RECT  34.524 55.409 35.097 55.715 ;
     RECT  7.815 55.651 9.414 55.751 ;
     RECT  69.516 55.579 70.722 55.751 ;
     RECT  64.44 55.489 68.454 55.757 ;
     RECT  69.66 55.751 70.722 55.771 ;
     RECT  7.815 55.751 9.126 55.859 ;
     RECT  10.515 55.687 10.926 55.859 ;
     RECT  4.5 54.893 6.102 55.921 ;
     RECT  66.744 55.757 68.454 55.993 ;
     RECT  4.464 55.921 6.102 56.029 ;
     RECT  6.912 54.635 6.93 56.029 ;
     RECT  69.66 55.771 70.758 56.093 ;
     RECT  59.115 54.131 59.397 56.101 ;
     RECT  69.66 56.093 70.722 56.129 ;
     RECT  4.464 56.029 6.93 56.191 ;
     RECT  58.716 56.101 59.397 56.255 ;
     RECT  4.032 56.191 6.93 56.291 ;
     RECT  69.66 56.129 70.686 56.291 ;
     RECT  38.772 56.227 38.79 56.327 ;
     RECT  69.66 56.291 69.93 56.327 ;
     RECT  34.815 55.715 35.097 56.371 ;
     RECT  66.744 55.993 68.598 56.399 ;
     RECT  6.624 56.291 6.93 56.443 ;
     RECT  7.815 55.859 8.097 56.443 ;
     RECT  64.44 55.757 65.898 56.443 ;
     RECT  2.304 55.553 2.697 56.461 ;
     RECT  67.176 56.399 68.598 56.461 ;
     RECT  30.816 56.461 30.834 56.497 ;
     RECT  4.032 56.291 5.598 56.525 ;
     RECT  58.788 56.255 59.397 56.561 ;
     RECT  2.304 56.461 2.826 56.569 ;
     RECT  2.304 56.569 2.862 56.605 ;
     RECT  9.108 55.859 9.126 56.641 ;
     RECT  34.815 56.371 35.154 56.641 ;
     RECT  67.176 56.461 68.814 56.731 ;
     RECT  69.66 56.327 69.678 56.731 ;
     RECT  9.036 56.641 9.126 56.759 ;
     RECT  64.044 56.443 65.898 56.767 ;
     RECT  9.108 56.759 9.126 56.867 ;
     RECT  70.668 56.291 70.686 56.923 ;
     RECT  61.815 55.679 62.874 57.001 ;
     RECT  64.044 56.767 66.402 57.001 ;
     RECT  2.304 56.605 3.114 57.019 ;
     RECT  4.032 56.525 5.562 57.019 ;
     RECT  36.432 56.731 36.45 57.029 ;
     RECT  67.176 56.731 69.678 57.064 ;
     RECT  70.668 56.923 70.722 57.064 ;
     RECT  34.596 56.641 35.154 57.181 ;
     RECT  2.304 57.019 5.562 57.299 ;
     RECT  61.815 57.001 66.402 57.299 ;
     RECT  67.176 57.064 70.722 57.299 ;
     RECT  30.78 56.497 30.834 57.307 ;
     RECT  6.624 56.443 8.097 57.379 ;
     RECT  10.515 55.859 10.797 57.379 ;
     RECT  38.88 57.145 38.898 57.403 ;
     RECT  45.615 47.213 45.897 57.403 ;
     RECT  53.715 47.213 53.997 57.403 ;
     RECT  6.624 57.379 8.37 57.445 ;
     RECT  10.515 57.379 10.854 57.479 ;
     RECT  30.78 57.307 30.87 57.479 ;
     RECT  38.664 57.403 38.898 57.479 ;
     RECT  32.115 45.059 32.397 57.541 ;
     RECT  9.144 57.451 9.162 57.569 ;
     RECT  36.648 57.379 36.738 57.569 ;
     RECT  38.664 57.479 38.826 57.569 ;
     RECT  65.592 57.299 66.402 57.569 ;
     RECT  67.176 57.299 68.13 57.569 ;
     RECT  68.976 57.299 70.722 57.569 ;
     RECT  38.664 57.569 38.79 57.581 ;
     RECT  45.615 57.403 45.99 57.581 ;
     RECT  46.764 57.403 46.782 57.581 ;
     RECT  53.715 57.403 54.738 57.581 ;
     RECT  67.176 57.569 67.95 57.595 ;
     RECT  6.48 57.445 8.37 57.649 ;
     RECT  6.408 57.649 8.37 57.685 ;
     RECT  32.115 57.541 33.102 57.839 ;
     RECT  34.596 57.181 35.586 57.883 ;
     RECT  61.815 57.299 64.797 57.911 ;
     RECT  6.408 57.685 9.126 57.991 ;
     RECT  59.115 56.561 59.397 57.991 ;
     RECT  34.596 57.883 36.306 58.109 ;
     RECT  38.736 57.581 38.754 58.109 ;
     RECT  58.716 57.991 59.397 58.109 ;
     RECT  63.108 57.911 64.797 58.109 ;
     RECT  69.48 57.569 70.722 58.145 ;
     RECT  63.108 58.109 63.306 58.157 ;
     RECT  0.216 58.123 0.234 58.253 ;
     RECT  6.372 57.991 9.126 58.379 ;
     RECT  2.304 57.299 5.454 58.387 ;
     RECT  6.372 58.379 8.298 58.387 ;
     RECT  34.815 58.109 36.306 58.423 ;
     RECT  66.492 57.595 67.95 58.423 ;
     RECT  68.688 58.351 68.706 58.423 ;
     RECT  9.036 58.379 9.126 58.451 ;
     RECT  66.492 58.423 68.706 58.451 ;
     RECT  38.772 58.387 38.79 58.487 ;
     RECT  65.592 57.569 65.682 58.495 ;
     RECT  66.492 58.451 68.454 58.495 ;
     RECT  2.304 58.387 8.298 58.649 ;
     RECT  34.815 58.423 36.486 58.649 ;
     RECT  2.304 58.649 8.154 58.691 ;
     RECT  2.304 58.691 8.097 58.721 ;
     RECT  69.588 58.145 70.722 58.828 ;
     RECT  69.588 58.828 70.758 58.991 ;
     RECT  69.588 58.991 70.686 59.035 ;
     RECT  69.516 59.035 70.686 59.063 ;
     RECT  59.115 58.109 59.397 59.071 ;
     RECT  2.304 58.721 2.697 59.189 ;
     RECT  63.108 58.157 63.27 59.189 ;
     RECT  64.044 58.109 64.797 59.189 ;
     RECT  30.852 59.071 30.87 59.261 ;
     RECT  59.115 59.071 59.886 59.269 ;
     RECT  61.815 57.911 62.097 59.275 ;
     RECT  58.716 59.269 59.886 59.297 ;
     RECT  63.108 59.189 63.126 59.309 ;
     RECT  61.815 59.275 62.37 59.341 ;
     RECT  64.368 59.189 64.797 59.341 ;
     RECT  65.592 58.495 68.454 59.341 ;
     RECT  4.212 58.721 8.097 59.459 ;
     RECT  34.815 58.649 35.838 59.459 ;
     RECT  64.368 59.341 68.526 59.459 ;
     RECT  2.376 59.189 2.697 59.467 ;
     RECT  4.356 59.459 8.097 59.495 ;
     RECT  69.516 59.063 70.11 59.515 ;
     RECT  2.376 59.467 3.006 59.539 ;
     RECT  2.376 59.539 3.078 59.611 ;
     RECT  34.815 59.459 35.226 59.611 ;
     RECT  4.356 59.495 7.038 59.729 ;
     RECT  34.812 59.611 35.226 59.729 ;
     RECT  4.356 59.729 5.778 59.837 ;
     RECT  64.368 59.459 68.274 59.837 ;
     RECT  69.444 59.515 70.11 59.851 ;
     RECT  6.66 59.729 7.038 59.873 ;
     RECT  61.815 59.341 63.054 59.885 ;
     RECT  38.772 59.431 38.79 59.971 ;
     RECT  0.54 59.773 0.558 59.981 ;
     RECT  63.036 59.885 63.054 59.999 ;
     RECT  30.78 59.701 30.798 60.007 ;
     RECT  64.368 59.837 67.662 60.035 ;
     RECT  2.376 59.611 3.294 60.079 ;
     RECT  30.78 60.007 30.87 60.179 ;
     RECT  38.664 59.971 38.79 60.179 ;
     RECT  58.716 59.297 59.397 60.179 ;
     RECT  69.336 59.851 70.11 60.187 ;
     RECT  2.376 60.079 3.51 60.241 ;
     RECT  2.304 60.241 3.51 60.269 ;
     RECT  64.368 60.035 65.826 60.269 ;
     RECT  4.356 59.837 4.374 60.317 ;
     RECT  68.472 60.241 68.49 60.341 ;
     RECT  36.072 59.971 36.09 60.377 ;
     RECT  34.812 59.729 35.097 60.385 ;
     RECT  8.892 60.151 8.91 60.421 ;
     RECT  64.368 60.269 64.797 60.421 ;
     RECT  7.815 59.495 8.097 60.427 ;
     RECT  8.892 60.421 8.946 60.427 ;
     RECT  7.815 60.427 8.946 60.611 ;
     RECT  30.78 60.179 30.798 60.683 ;
     RECT  69.3 60.187 70.11 60.683 ;
     RECT  34.416 60.385 35.097 60.691 ;
     RECT  66.672 60.035 67.662 60.691 ;
     RECT  61.815 59.885 62.097 60.763 ;
     RECT  63.468 60.421 64.797 60.781 ;
     RECT  61.815 60.763 62.226 60.809 ;
     RECT  63.18 60.781 64.797 60.881 ;
     RECT  69.516 60.683 70.11 60.881 ;
     RECT  5.115 59.837 5.778 60.961 ;
     RECT  34.416 60.691 35.298 60.961 ;
     RECT  4.5 60.961 5.778 61.051 ;
     RECT  63.828 60.881 64.797 61.051 ;
     RECT  65.52 60.269 65.826 61.051 ;
     RECT  4.428 61.051 5.778 61.087 ;
     RECT  60.984 60.961 61.002 61.115 ;
     RECT  4.428 61.087 5.814 61.123 ;
     RECT  2.304 60.269 2.934 61.195 ;
     RECT  3.708 61.123 5.814 61.195 ;
     RECT  6.84 60.655 6.858 61.195 ;
     RECT  37.515 54.059 37.797 61.195 ;
     RECT  63.828 61.051 65.826 61.195 ;
     RECT  66.672 60.691 67.734 61.195 ;
     RECT  63.828 61.195 67.734 61.229 ;
     RECT  2.304 61.195 6.858 61.231 ;
     RECT  7.815 60.611 8.37 61.231 ;
     RECT  34.2 60.961 35.298 61.231 ;
     RECT  36.036 61.159 36.054 61.231 ;
     RECT  34.2 61.231 36.054 61.259 ;
     RECT  66.348 61.229 67.734 61.321 ;
     RECT  2.304 61.231 8.37 61.349 ;
     RECT  2.304 61.349 5.814 61.385 ;
     RECT  2.304 61.385 5.706 61.421 ;
     RECT  69.516 60.881 69.714 61.421 ;
     RECT  34.776 61.259 36.054 61.493 ;
     RECT  9.36 61.051 9.378 61.529 ;
     RECT  36.792 61.195 37.797 61.529 ;
     RECT  2.304 61.421 5.598 61.655 ;
     RECT  63.828 61.229 65.61 61.663 ;
     RECT  37.008 61.529 37.797 61.691 ;
     RECT  10.515 57.479 10.797 61.735 ;
     RECT  6.696 61.349 8.37 61.771 ;
     RECT  30.816 61.735 30.834 61.861 ;
     RECT  63.252 61.663 65.61 61.867 ;
     RECT  6.696 61.771 8.874 61.889 ;
     RECT  63.108 61.867 65.61 61.925 ;
     RECT  3.672 61.655 5.598 61.949 ;
     RECT  30.78 61.861 30.834 61.961 ;
     RECT  69.588 61.421 69.714 61.963 ;
     RECT  10.515 61.735 10.854 62.033 ;
     RECT  63.504 61.925 65.61 62.107 ;
     RECT  66.348 61.321 68.166 62.107 ;
     RECT  63.504 62.107 68.166 62.131 ;
     RECT  2.304 61.655 2.826 62.189 ;
     RECT  60.984 62.005 61.002 62.195 ;
     RECT  34.776 61.493 35.37 62.203 ;
     RECT  6.696 61.889 8.478 62.339 ;
     RECT  5.115 61.949 5.598 62.401 ;
     RECT  6.696 62.339 8.406 62.401 ;
     RECT  5.115 62.401 8.406 62.429 ;
     RECT  63.504 62.131 68.706 62.429 ;
     RECT  69.588 61.963 70.11 62.443 ;
     RECT  69.552 62.443 70.11 62.501 ;
     RECT  3.672 61.949 4.374 62.545 ;
     RECT  34.704 62.203 35.37 62.609 ;
     RECT  2.412 62.189 2.826 62.635 ;
     RECT  3.6 62.545 4.374 62.635 ;
     RECT  5.115 62.429 8.097 62.699 ;
     RECT  30.78 61.961 30.798 62.699 ;
     RECT  63.504 62.429 64.797 62.699 ;
     RECT  6.732 62.699 8.097 62.717 ;
     RECT  0.216 62.671 0.234 62.765 ;
     RECT  69.552 62.501 69.678 62.77 ;
     RECT  65.556 62.429 68.706 62.941 ;
     RECT  69.516 62.77 69.678 62.941 ;
     RECT  63.972 62.699 64.797 62.969 ;
     RECT  65.556 62.941 69.678 62.969 ;
     RECT  2.412 62.635 4.374 63.005 ;
     RECT  3.744 63.005 4.374 63.013 ;
     RECT  5.115 62.699 5.994 63.013 ;
     RECT  38.736 62.941 38.754 63.041 ;
     RECT  61.815 60.809 62.097 63.121 ;
     RECT  6.768 62.717 8.097 63.205 ;
     RECT  2.412 63.005 2.97 63.211 ;
     RECT  2.304 63.211 2.97 63.239 ;
     RECT  9.144 62.977 9.162 63.239 ;
     RECT  66.6 62.969 69.678 63.239 ;
     RECT  66.6 63.239 68.598 63.275 ;
     RECT  34.815 62.609 35.37 63.283 ;
     RECT  64.116 62.969 64.797 63.391 ;
     RECT  65.556 62.969 65.826 63.391 ;
     RECT  70.704 62.635 70.722 63.419 ;
     RECT  0.54 63.013 0.558 63.437 ;
     RECT  69.516 63.239 69.678 63.451 ;
     RECT  61.815 63.121 62.766 63.589 ;
     RECT  3.744 63.013 5.994 63.625 ;
     RECT  6.768 63.205 8.226 63.625 ;
     RECT  61.815 63.589 62.802 63.689 ;
     RECT  64.116 63.391 65.826 63.739 ;
     RECT  66.6 63.275 67.698 63.739 ;
     RECT  3.744 63.625 8.226 63.751 ;
     RECT  34.815 63.283 35.514 63.751 ;
     RECT  3.672 63.751 8.226 63.895 ;
     RECT  34.776 63.751 35.514 63.895 ;
     RECT  64.116 63.739 67.698 63.895 ;
     RECT  2.304 63.239 2.862 64.021 ;
     RECT  3.672 63.895 8.37 64.049 ;
     RECT  63.72 63.895 67.698 64.057 ;
     RECT  68.508 63.275 68.598 64.057 ;
     RECT  63.72 64.057 68.598 64.085 ;
     RECT  2.304 64.021 2.934 64.129 ;
     RECT  3.672 64.049 5.994 64.129 ;
     RECT  64.368 64.085 68.598 64.129 ;
     RECT  69.516 63.451 70.11 64.129 ;
     RECT  34.776 63.895 35.838 64.201 ;
     RECT  6.804 64.049 6.822 64.229 ;
     RECT  64.368 64.129 70.11 64.301 ;
     RECT  2.304 64.129 5.994 64.319 ;
     RECT  34.776 64.201 35.946 64.319 ;
     RECT  64.368 64.301 68.706 64.319 ;
     RECT  30.852 64.201 30.87 64.355 ;
     RECT  66.672 64.319 68.706 64.355 ;
     RECT  34.776 64.319 35.097 64.391 ;
     RECT  65.52 64.319 65.79 64.391 ;
     RECT  66.672 64.355 67.806 64.391 ;
     RECT  69.516 64.301 70.11 64.411 ;
     RECT  59.115 60.179 59.397 64.561 ;
     RECT  61.815 63.689 62.73 64.561 ;
     RECT  68.688 64.355 68.706 64.589 ;
     RECT  7.815 64.049 8.19 64.697 ;
     RECT  61.815 64.561 62.802 64.769 ;
     RECT  9 64.705 9.018 64.831 ;
     RECT  38.736 64.165 38.754 64.867 ;
     RECT  4.104 64.319 5.994 64.931 ;
     RECT  9 64.831 9.09 64.931 ;
     RECT  38.736 64.867 38.79 64.967 ;
     RECT  64.368 64.319 64.797 64.975 ;
     RECT  66.708 64.391 67.806 65.101 ;
     RECT  30.78 64.975 30.798 65.129 ;
     RECT  35.892 64.319 35.91 65.129 ;
     RECT  58.716 64.561 59.397 65.129 ;
     RECT  64.008 64.975 64.797 65.131 ;
     RECT  65.556 64.391 65.79 65.131 ;
     RECT  69.516 64.411 70.722 65.227 ;
     RECT  6.84 65.137 6.858 65.245 ;
     RECT  34.815 64.391 35.097 65.245 ;
     RECT  64.008 65.131 65.826 65.281 ;
     RECT  2.304 64.319 3.366 65.308 ;
     RECT  6.84 65.245 6.966 65.371 ;
     RECT  63.936 65.281 65.826 65.371 ;
     RECT  66.708 65.101 67.842 65.371 ;
     RECT  68.616 65.101 68.634 65.371 ;
     RECT  6.768 65.371 6.966 65.407 ;
     RECT  7.815 64.697 8.097 65.407 ;
     RECT  63.936 65.371 65.898 65.435 ;
     RECT  8.856 65.137 8.91 65.471 ;
     RECT  2.268 65.308 3.366 65.515 ;
     RECT  69.48 65.227 70.722 65.543 ;
     RECT  6.768 65.407 8.097 65.551 ;
     RECT  64.26 65.435 65.898 65.563 ;
     RECT  66.708 65.371 68.634 65.563 ;
     RECT  63 64.939 63.018 65.641 ;
     RECT  34.815 65.245 35.838 65.669 ;
     RECT  63 65.641 63.306 65.693 ;
     RECT  2.268 65.515 3.978 65.713 ;
     RECT  4.716 64.931 5.994 65.713 ;
     RECT  2.268 65.713 5.994 65.785 ;
     RECT  6.768 65.551 8.298 65.785 ;
     RECT  2.268 65.785 8.298 65.789 ;
     RECT  61.815 64.769 62.097 65.821 ;
     RECT  3.96 65.789 8.298 65.849 ;
     RECT  2.268 65.789 2.934 65.885 ;
     RECT  2.304 65.885 2.934 65.939 ;
     RECT  34.815 65.669 35.298 65.939 ;
     RECT  64.26 65.563 68.634 65.975 ;
     RECT  64.44 65.975 68.634 65.983 ;
     RECT  61.815 65.821 62.766 66.011 ;
     RECT  30.78 66.019 30.798 66.119 ;
     RECT  38.736 64.967 38.754 66.119 ;
     RECT  3.96 65.849 6.498 66.209 ;
     RECT  64.44 65.983 68.706 66.209 ;
     RECT  7.344 65.849 8.298 66.235 ;
     RECT  69.516 65.543 70.722 66.235 ;
     RECT  7.344 66.235 8.478 66.269 ;
     RECT  69.516 66.235 70.758 66.353 ;
     RECT  9.468 66.289 9.486 66.361 ;
     RECT  36.252 65.983 36.27 66.361 ;
     RECT  3.96 66.209 6.354 66.389 ;
     RECT  4.068 66.389 6.354 66.479 ;
     RECT  9.396 66.361 9.486 66.479 ;
     RECT  36.252 66.361 36.45 66.479 ;
     RECT  34.815 65.939 35.097 66.487 ;
     RECT  5.115 66.479 5.886 66.515 ;
     RECT  7.452 66.269 8.478 66.515 ;
     RECT  7.452 66.515 8.097 66.551 ;
     RECT  2.415 65.939 2.934 66.571 ;
     RECT  34.776 66.487 35.097 66.659 ;
     RECT  63.108 66.715 63.126 66.721 ;
     RECT  2.415 66.571 3.258 66.749 ;
     RECT  64.44 66.209 68.274 66.785 ;
     RECT  2.415 66.749 2.97 66.811 ;
     RECT  4.068 66.479 4.374 66.821 ;
     RECT  61.815 66.011 62.097 66.829 ;
     RECT  63.108 66.721 63.63 66.829 ;
     RECT  69.516 66.353 70.11 66.859 ;
     RECT  2.304 66.811 2.97 66.901 ;
     RECT  34.815 66.659 35.097 66.901 ;
     RECT  66.672 66.785 68.274 66.991 ;
     RECT  2.268 66.901 2.97 67.037 ;
     RECT  34.815 66.901 35.874 67.127 ;
     RECT  38.772 67.027 38.79 67.127 ;
     RECT  69.408 66.859 70.11 67.163 ;
     RECT  70.092 67.163 70.11 67.195 ;
     RECT  4.356 66.821 4.374 67.261 ;
     RECT  5.115 66.515 5.397 67.261 ;
     RECT  64.44 66.785 65.718 67.277 ;
     RECT  6.804 66.991 6.822 67.297 ;
     RECT  6.804 67.297 6.966 67.339 ;
     RECT  7.815 66.551 8.097 67.339 ;
     RECT  6.696 67.339 6.966 67.369 ;
     RECT  7.815 67.339 8.154 67.369 ;
     RECT  33.624 67.099 33.642 67.369 ;
     RECT  33.624 67.369 33.714 67.397 ;
     RECT  10.515 62.033 10.797 67.405 ;
     RECT  0.216 66.571 0.234 67.421 ;
     RECT  34.815 67.127 35.37 67.433 ;
     RECT  10.515 67.405 10.818 67.441 ;
     RECT  4.356 67.261 5.397 67.531 ;
     RECT  61.815 66.829 63.63 67.531 ;
     RECT  64.44 67.277 64.797 67.531 ;
     RECT  10.515 67.441 10.926 67.559 ;
     RECT  33.696 67.397 33.714 67.559 ;
     RECT  34.815 67.433 35.298 67.559 ;
     RECT  37.515 61.691 37.797 67.603 ;
     RECT  66.672 66.991 68.382 67.603 ;
     RECT  70.092 67.195 70.722 67.666 ;
     RECT  30.852 67.567 30.87 67.667 ;
     RECT  59.115 65.129 59.397 67.675 ;
     RECT  6.696 67.369 8.154 67.703 ;
     RECT  4.356 67.531 5.67 67.801 ;
     RECT  34.815 67.559 35.154 67.801 ;
     RECT  66.672 67.603 68.418 67.864 ;
     RECT  70.092 67.666 70.758 67.901 ;
     RECT  2.304 67.037 2.97 67.909 ;
     RECT  4.32 67.801 5.67 67.909 ;
     RECT  2.304 67.909 5.67 67.945 ;
     RECT  6.696 67.703 6.858 67.945 ;
     RECT  7.596 67.703 8.154 67.945 ;
     RECT  36.792 67.603 37.797 67.981 ;
     RECT  66.6 67.864 68.418 67.981 ;
     RECT  69.336 67.387 69.354 67.981 ;
     RECT  34.2 67.801 35.154 68.009 ;
     RECT  66.6 67.981 69.354 68.011 ;
     RECT  70.092 67.901 70.722 68.011 ;
     RECT  34.524 68.009 35.097 68.099 ;
     RECT  66.6 68.011 70.722 68.099 ;
     RECT  61.815 67.531 64.797 68.203 ;
     RECT  65.52 67.277 65.718 68.203 ;
     RECT  10.515 67.559 10.818 68.243 ;
     RECT  61.815 68.203 65.718 68.251 ;
     RECT  66.6 68.099 68.418 68.251 ;
     RECT  58.716 67.675 59.397 68.279 ;
     RECT  2.304 67.945 6.858 68.369 ;
     RECT  36.324 67.981 37.797 68.369 ;
     RECT  69.48 68.099 70.722 68.381 ;
     RECT  69.48 68.381 70.11 68.405 ;
     RECT  59.115 68.279 59.397 68.485 ;
     RECT  36.324 68.369 36.486 68.521 ;
     RECT  59.115 68.485 59.886 68.521 ;
     RECT  59.115 68.521 59.922 68.639 ;
     RECT  35.964 68.521 36.486 68.719 ;
     RECT  7.596 67.945 8.19 68.755 ;
     RECT  2.415 68.369 6.858 68.791 ;
     RECT  7.596 68.755 8.226 68.791 ;
     RECT  69.516 68.405 70.11 68.861 ;
     RECT  38.844 68.719 38.862 68.881 ;
     RECT  2.415 68.791 8.226 68.909 ;
     RECT  35.892 68.719 36.486 68.909 ;
     RECT  61.815 68.251 68.418 68.909 ;
     RECT  61.815 68.909 63.234 68.915 ;
     RECT  38.772 68.881 38.862 68.981 ;
     RECT  0.54 68.251 0.558 69.005 ;
     RECT  3.888 68.909 8.226 69.053 ;
     RECT  34.815 68.099 35.097 69.061 ;
     RECT  59.115 68.639 59.886 69.089 ;
     RECT  2.415 68.909 2.862 69.115 ;
     RECT  61.815 68.915 62.73 69.179 ;
     RECT  69.66 68.861 70.11 69.223 ;
     RECT  7.488 69.053 8.226 69.331 ;
     RECT  9.108 69.061 9.126 69.331 ;
     RECT  34.815 69.061 35.478 69.359 ;
     RECT  64.296 68.909 68.418 69.421 ;
     RECT  3.888 69.053 6.75 69.449 ;
     RECT  7.488 69.331 9.126 69.449 ;
     RECT  64.296 69.421 68.526 69.521 ;
     RECT  7.488 69.449 8.19 69.533 ;
     RECT  69.66 69.223 70.722 69.643 ;
     RECT  3.888 69.449 6.57 69.691 ;
     RECT  64.296 69.521 68.022 69.691 ;
     RECT  61.815 69.179 62.154 69.719 ;
     RECT  63.54 69.691 68.022 69.719 ;
     RECT  3.6 69.691 6.57 69.989 ;
     RECT  9.18 69.871 9.198 70.025 ;
     RECT  1.152 69.931 1.17 70.061 ;
     RECT  3.6 69.989 4.23 70.061 ;
     RECT  2.304 69.115 2.862 70.069 ;
     RECT  3.6 70.061 3.978 70.069 ;
     RECT  34.815 69.359 35.37 70.105 ;
     RECT  5.076 69.989 6.57 70.259 ;
     RECT  34.272 70.105 35.37 70.259 ;
     RECT  63.54 69.719 64.797 70.295 ;
     RECT  65.592 69.719 68.022 70.295 ;
     RECT  69.516 69.643 70.722 70.331 ;
     RECT  7.815 69.533 8.19 70.375 ;
     RECT  64.404 70.295 64.797 70.501 ;
     RECT  65.592 70.295 65.79 70.501 ;
     RECT  66.6 70.295 68.022 70.501 ;
     RECT  7.815 70.375 8.37 70.529 ;
     RECT  9.144 70.411 9.162 70.529 ;
     RECT  64.404 70.501 65.79 70.589 ;
     RECT  34.272 70.259 35.298 70.609 ;
     RECT  7.815 70.529 8.298 70.673 ;
     RECT  2.304 70.069 3.978 70.681 ;
     RECT  7.815 70.673 8.19 70.685 ;
     RECT  66.6 70.501 68.094 70.771 ;
     RECT  2.268 70.681 3.978 70.781 ;
     RECT  2.304 70.781 3.978 70.795 ;
     RECT  5.076 70.259 6.066 70.795 ;
     RECT  69.516 70.331 69.678 70.795 ;
     RECT  66.6 70.771 68.526 70.799 ;
     RECT  7.815 70.685 8.097 70.843 ;
     RECT  68.256 70.799 68.526 70.871 ;
     RECT  30.852 70.267 30.87 70.906 ;
     RECT  30.852 70.906 30.906 70.907 ;
     RECT  69.372 70.795 69.678 70.943 ;
     RECT  34.092 70.609 35.298 70.979 ;
     RECT  36.432 70.915 36.45 71.069 ;
     RECT  2.304 70.795 6.066 71.083 ;
     RECT  6.984 70.915 7.002 71.083 ;
     RECT  2.304 71.083 7.002 71.128 ;
     RECT  30.888 70.907 30.906 71.141 ;
     RECT  62.964 70.915 62.982 71.149 ;
     RECT  5.115 71.128 7.002 71.185 ;
     RECT  7.812 70.843 8.097 71.185 ;
     RECT  69.66 70.943 69.678 71.213 ;
     RECT  38.736 70.951 38.754 71.249 ;
     RECT  62.964 71.149 63.018 71.249 ;
     RECT  0.252 71.131 0.27 71.261 ;
     RECT  70.704 70.331 70.722 71.275 ;
     RECT  33.624 71.041 33.642 71.339 ;
     RECT  34.815 70.979 35.298 71.383 ;
     RECT  34.815 71.383 35.334 71.455 ;
     RECT  34.815 71.455 35.694 71.491 ;
     RECT  34.815 71.491 36.018 71.609 ;
     RECT  64.44 70.589 65.79 71.609 ;
     RECT  64.44 71.609 64.797 71.611 ;
     RECT  64.296 71.611 64.797 71.651 ;
     RECT  61.815 69.719 62.097 71.689 ;
     RECT  5.115 71.185 8.097 71.707 ;
     RECT  66.6 70.799 67.497 71.725 ;
     RECT  68.256 70.871 68.346 71.725 ;
     RECT  34.815 71.609 35.442 71.761 ;
     RECT  0.216 71.659 0.234 71.789 ;
     RECT  66.6 71.725 68.346 71.789 ;
     RECT  65.592 71.609 65.79 71.803 ;
     RECT  66.6 71.789 67.698 71.803 ;
     RECT  5.115 71.707 8.19 71.915 ;
     RECT  9.108 71.383 9.126 71.923 ;
     RECT  34.776 71.761 35.442 71.923 ;
     RECT  70.092 71.275 70.722 71.947 ;
     RECT  9.072 71.923 9.126 72.031 ;
     RECT  63.648 71.923 63.666 72.031 ;
     RECT  69.948 71.947 70.722 72.091 ;
     RECT  9.072 72.031 9.234 72.149 ;
     RECT  34.524 71.923 35.442 72.149 ;
     RECT  61.815 71.689 62.73 72.229 ;
     RECT  5.115 71.915 8.097 72.257 ;
     RECT  9.072 72.149 9.162 72.257 ;
     RECT  9.072 72.257 9.126 72.293 ;
     RECT  63.612 72.031 63.666 72.293 ;
     RECT  69.588 72.091 70.722 72.293 ;
     RECT  38.736 72.157 38.754 72.329 ;
     RECT  68.58 72.031 68.634 72.329 ;
     RECT  61.815 72.229 62.766 72.331 ;
     RECT  65.592 71.803 67.698 72.365 ;
     RECT  64.44 71.651 64.797 72.379 ;
     RECT  2.304 71.128 4.374 72.391 ;
     RECT  5.115 72.257 6.21 72.391 ;
     RECT  10.515 68.243 10.797 72.391 ;
     RECT  10.515 72.391 10.818 72.491 ;
     RECT  64.44 72.379 64.818 72.535 ;
     RECT  34.776 72.149 35.442 72.571 ;
     RECT  36.504 72.535 36.522 72.571 ;
     RECT  30.852 72.571 30.87 72.661 ;
     RECT  66.636 72.365 67.698 72.661 ;
     RECT  68.796 72.571 68.814 72.689 ;
     RECT  30.78 72.661 30.87 72.725 ;
     RECT  34.776 72.571 36.522 72.725 ;
     RECT  64.368 72.535 64.818 72.725 ;
     RECT  9.108 72.293 9.126 72.869 ;
     RECT  2.304 72.391 6.21 72.959 ;
     RECT  64.44 72.725 64.818 73.039 ;
     RECT  65.592 72.365 65.754 73.039 ;
     RECT  69.696 72.293 70.722 73.067 ;
     RECT  69.696 73.067 70.11 73.099 ;
     RECT  34.776 72.725 36.162 73.111 ;
     RECT  64.44 73.039 65.754 73.201 ;
     RECT  66.636 72.661 67.806 73.201 ;
     RECT  6.984 72.257 8.097 73.229 ;
     RECT  34.56 73.111 36.162 73.229 ;
     RECT  61.815 72.331 63.414 73.277 ;
     RECT  2.304 72.959 4.122 73.387 ;
     RECT  2.268 73.387 4.122 73.499 ;
     RECT  63.684 73.309 63.702 73.499 ;
     RECT  30.78 72.725 30.798 73.535 ;
     RECT  68.724 73.381 68.742 73.535 ;
     RECT  0.54 72.805 0.558 73.565 ;
     RECT  6.984 73.229 7.074 73.579 ;
     RECT  64.44 73.201 67.806 73.651 ;
     RECT  33.624 73.471 33.642 73.679 ;
     RECT  5.115 72.959 5.526 73.741 ;
     RECT  6.804 73.579 7.074 73.813 ;
     RECT  38.736 73.741 38.754 73.841 ;
     RECT  2.304 73.499 4.122 73.921 ;
     RECT  5.076 73.741 5.526 73.921 ;
     RECT  34.704 73.229 36.162 73.921 ;
     RECT  34.704 73.921 36.486 74.039 ;
     RECT  2.304 73.921 5.526 74.047 ;
     RECT  6.732 73.813 7.074 74.047 ;
     RECT  2.304 74.047 7.074 74.093 ;
     RECT  6.732 74.093 7.074 74.111 ;
     RECT  64.152 73.651 68.706 74.111 ;
     RECT  6.912 74.111 7.074 74.219 ;
     RECT  69.516 73.099 70.11 74.251 ;
     RECT  64.152 74.111 68.382 74.309 ;
     RECT  7.815 73.229 8.097 74.317 ;
     RECT  69.516 74.251 70.722 74.425 ;
     RECT  9.036 74.317 9.054 74.461 ;
     RECT  8.964 74.461 9.054 74.489 ;
     RECT  69.444 74.425 70.722 74.489 ;
     RECT  8.964 74.489 8.982 74.579 ;
     RECT  7.704 74.317 8.097 74.651 ;
     RECT  64.152 74.309 68.202 74.659 ;
     RECT  61.815 73.277 62.73 74.683 ;
     RECT  63.72 74.659 68.202 74.683 ;
     RECT  0.216 74.011 0.234 74.717 ;
     RECT  36.324 74.039 36.342 74.821 ;
     RECT  61.815 74.683 68.202 74.885 ;
     RECT  69.444 74.489 70.11 74.993 ;
     RECT  8.892 74.929 8.91 75.001 ;
     RECT  2.304 74.093 5.742 75.091 ;
     RECT  6.912 74.219 6.93 75.091 ;
     RECT  7.815 74.651 8.097 75.091 ;
     RECT  8.82 75.001 8.91 75.091 ;
     RECT  34.815 74.039 35.586 75.091 ;
     RECT  36.324 74.821 36.414 75.091 ;
     RECT  34.815 75.091 36.414 75.119 ;
     RECT  65.7 74.885 68.202 75.127 ;
     RECT  2.304 75.091 6.93 75.155 ;
     RECT  7.815 75.091 8.91 75.191 ;
     RECT  30.78 74.461 30.798 75.227 ;
     RECT  69.588 74.993 70.11 75.355 ;
     RECT  35.892 75.119 36.414 75.433 ;
     RECT  69.588 75.355 70.722 75.461 ;
     RECT  59.115 69.089 59.397 75.505 ;
     RECT  10.515 72.491 10.797 75.631 ;
     RECT  35.892 75.433 36.486 75.659 ;
     RECT  61.815 74.885 64.797 75.659 ;
     RECT  34.815 75.119 35.097 75.703 ;
     RECT  65.7 75.127 68.562 75.731 ;
     RECT  34.776 75.703 35.097 75.901 ;
     RECT  59.115 75.505 59.454 75.929 ;
     RECT  68.364 75.731 68.562 75.929 ;
     RECT  59.115 75.929 59.397 76.009 ;
     RECT  69.588 75.461 70.11 76.027 ;
     RECT  9.072 75.811 9.09 76.109 ;
     RECT  58.716 76.009 59.397 76.109 ;
     RECT  68.544 75.929 68.562 76.171 ;
     RECT  69.516 76.027 70.11 76.171 ;
     RECT  2.304 75.155 6.858 76.199 ;
     RECT  34.776 75.901 35.298 76.199 ;
     RECT  58.788 76.109 59.397 76.235 ;
     RECT  4.14 76.199 6.858 76.271 ;
     RECT  30.852 76.207 30.87 76.307 ;
     RECT  68.544 76.171 70.11 76.307 ;
     RECT  7.815 75.191 8.097 76.411 ;
     RECT  10.515 75.631 10.818 76.441 ;
     RECT  34.776 76.199 35.097 76.441 ;
     RECT  63.288 75.659 64.797 76.441 ;
     RECT  65.7 75.731 67.497 76.441 ;
     RECT  4.14 76.271 5.634 76.469 ;
     RECT  60.444 76.243 60.462 76.505 ;
     RECT  63.288 76.441 67.497 76.549 ;
     RECT  6.804 76.271 6.858 76.585 ;
     RECT  7.815 76.411 8.226 76.585 ;
     RECT  61.815 75.659 62.478 76.585 ;
     RECT  63.288 76.549 67.806 76.585 ;
     RECT  6.804 76.585 8.226 76.589 ;
     RECT  6.804 76.589 8.154 76.613 ;
     RECT  6.804 76.613 8.097 76.649 ;
     RECT  38.772 76.207 38.79 76.738 ;
     RECT  2.304 76.199 3.402 76.739 ;
     RECT  9.216 76.621 9.234 76.739 ;
     RECT  38.772 76.738 38.826 76.739 ;
     RECT  61.815 76.585 67.806 76.739 ;
     RECT  10.515 76.441 10.854 76.775 ;
     RECT  30.78 76.549 30.798 76.775 ;
     RECT  61.815 76.739 64.797 76.775 ;
     RECT  62.82 76.775 64.797 76.811 ;
     RECT  65.664 76.739 67.806 76.819 ;
     RECT  68.544 76.307 68.67 76.819 ;
     RECT  38.808 76.739 38.826 76.919 ;
     RECT  63.108 76.811 64.797 76.919 ;
     RECT  65.664 76.819 68.67 76.919 ;
     RECT  37.515 68.369 37.797 76.981 ;
     RECT  68.256 76.919 68.67 77.035 ;
     RECT  69.516 76.307 70.11 77.035 ;
     RECT  6.84 76.649 8.097 77.153 ;
     RECT  34.704 76.441 35.097 77.279 ;
     RECT  4.356 76.469 5.634 77.287 ;
     RECT  2.304 76.739 3.294 77.315 ;
     RECT  34.776 77.279 35.097 77.323 ;
     RECT  68.256 77.035 70.11 77.323 ;
     RECT  36.936 76.981 37.797 77.423 ;
     RECT  6.876 77.153 8.097 77.515 ;
     RECT  4.284 77.287 5.634 77.521 ;
     RECT  65.664 76.919 67.497 77.521 ;
     RECT  68.256 77.323 70.722 77.549 ;
     RECT  30.852 77.287 30.87 77.593 ;
     RECT  10.515 76.775 10.797 77.629 ;
     RECT  30.78 77.593 30.87 77.629 ;
     RECT  64.368 76.919 64.797 77.629 ;
     RECT  34.776 77.323 35.298 77.665 ;
     RECT  63.108 76.919 63.378 77.665 ;
     RECT  64.368 77.629 64.854 77.665 ;
     RECT  68.256 77.549 68.562 77.693 ;
     RECT  65.592 77.521 67.497 77.729 ;
     RECT  34.776 77.665 35.478 77.791 ;
     RECT  9.288 77.521 9.306 77.819 ;
     RECT  4.284 77.521 5.778 77.899 ;
     RECT  6.876 77.515 8.37 77.899 ;
     RECT  63.108 77.665 64.854 77.899 ;
     RECT  65.592 77.729 66.15 77.899 ;
     RECT  63.108 77.899 66.15 77.927 ;
     RECT  30.78 77.629 30.942 77.963 ;
     RECT  34.776 77.791 35.622 77.971 ;
     RECT  66.924 77.729 67.497 77.971 ;
     RECT  68.256 77.693 68.382 77.971 ;
     RECT  69.516 77.549 70.722 77.995 ;
     RECT  30.78 77.963 30.798 78.089 ;
     RECT  34.776 77.971 35.73 78.089 ;
     RECT  3.6 77.899 8.37 78.097 ;
     RECT  34.776 78.089 35.586 78.125 ;
     RECT  61.815 76.775 62.097 78.169 ;
     RECT  0.216 77.791 0.234 78.173 ;
     RECT  2.304 77.315 2.697 78.241 ;
     RECT  10.515 77.629 10.818 78.331 ;
     RECT  36.54 78.241 36.558 78.359 ;
     RECT  9.36 78.205 9.45 78.395 ;
     RECT  34.776 78.125 35.226 78.403 ;
     RECT  3.6 78.097 8.442 78.413 ;
     RECT  3.6 78.413 6.93 78.431 ;
     RECT  61.815 78.169 62.802 78.431 ;
     RECT  2.304 78.241 2.826 78.439 ;
     RECT  3.6 78.431 6.822 78.439 ;
     RECT  66.924 77.971 68.382 78.475 ;
     RECT  63.756 77.927 66.15 78.509 ;
     RECT  34.488 78.403 35.226 78.511 ;
     RECT  65.52 78.509 66.15 78.511 ;
     RECT  66.924 78.475 68.562 78.511 ;
     RECT  10.515 78.331 10.926 78.539 ;
     RECT  69.516 77.995 70.758 78.539 ;
     RECT  2.304 78.439 6.822 78.629 ;
     RECT  69.516 78.539 70.11 78.667 ;
     RECT  7.815 78.413 8.442 78.745 ;
     RECT  65.52 78.511 68.562 78.781 ;
     RECT  69.48 78.667 70.11 78.781 ;
     RECT  65.52 78.781 70.11 78.899 ;
     RECT  36.756 78.709 36.774 78.935 ;
     RECT  34.416 78.511 35.226 78.943 ;
     RECT  7.815 78.745 9.054 79.079 ;
     RECT  30.78 78.871 30.798 79.079 ;
     RECT  34.308 78.943 35.226 79.169 ;
     RECT  65.556 78.899 70.11 79.169 ;
     RECT  6.66 78.629 6.822 79.285 ;
     RECT  37.515 77.423 37.797 79.285 ;
     RECT  61.815 78.431 62.73 79.321 ;
     RECT  0.216 79.141 0.234 79.325 ;
     RECT  6.66 79.285 6.858 79.411 ;
     RECT  63.756 78.509 64.797 79.411 ;
     RECT  36.792 79.285 37.797 79.439 ;
     RECT  66.492 79.169 70.11 79.439 ;
     RECT  61.815 79.321 62.766 79.475 ;
     RECT  2.304 78.629 5.886 79.483 ;
     RECT  59.115 76.235 59.397 79.483 ;
     RECT  7.815 79.079 8.514 79.511 ;
     RECT  34.776 79.169 35.226 79.555 ;
     RECT  36.036 79.285 36.054 79.555 ;
     RECT  63.612 79.411 64.797 79.579 ;
     RECT  38.808 79.447 38.826 79.583 ;
     RECT  2.304 79.483 5.922 79.591 ;
     RECT  6.66 79.411 6.93 79.591 ;
     RECT  7.815 79.511 8.097 79.591 ;
     RECT  58.716 79.483 59.397 79.619 ;
     RECT  2.304 79.591 6.93 79.709 ;
     RECT  34.776 79.555 36.054 79.709 ;
     RECT  58.788 79.619 59.397 79.709 ;
     RECT  63.036 79.579 64.797 79.757 ;
     RECT  2.304 79.709 4.374 79.805 ;
     RECT  63.396 79.757 64.797 79.889 ;
     RECT  0.54 79.681 0.558 79.949 ;
     RECT  64.152 79.889 64.797 79.987 ;
     RECT  65.556 79.169 65.682 79.987 ;
     RECT  34.815 79.709 36.054 80.023 ;
     RECT  64.152 79.987 65.682 80.023 ;
     RECT  66.492 79.439 68.526 80.023 ;
     RECT  5.115 79.709 6.93 80.095 ;
     RECT  7.668 79.591 8.097 80.095 ;
     RECT  38.736 79.681 38.754 80.123 ;
     RECT  64.152 80.023 68.526 80.221 ;
     RECT  69.372 79.439 70.11 80.221 ;
     RECT  34.815 80.023 36.126 80.249 ;
     RECT  64.152 80.221 70.11 80.249 ;
     RECT  66.42 80.249 70.11 80.321 ;
     RECT  5.115 80.095 8.097 80.357 ;
     RECT  33.624 80.293 33.642 80.429 ;
     RECT  2.304 79.805 3.222 80.519 ;
     RECT  36.252 80.365 36.27 80.519 ;
     RECT  7.092 80.357 8.097 80.563 ;
     RECT  69.336 80.321 70.11 80.621 ;
     RECT  4.176 79.805 4.374 80.635 ;
     RECT  63.396 79.889 63.414 80.761 ;
     RECT  64.152 80.249 65.682 80.761 ;
     RECT  7.092 80.563 8.154 80.789 ;
     RECT  3.636 80.635 4.374 80.861 ;
     RECT  63.396 80.761 65.682 80.897 ;
     RECT  69.516 80.621 70.11 80.905 ;
     RECT  3.708 80.861 4.374 80.941 ;
     RECT  5.115 80.357 6.246 80.941 ;
     RECT  61.815 79.475 62.097 80.941 ;
     RECT  69.516 80.905 70.686 80.957 ;
     RECT  60.444 80.527 60.462 80.969 ;
     RECT  64.44 80.897 65.682 80.971 ;
     RECT  66.42 80.321 68.418 80.971 ;
     RECT  1.152 80.923 1.17 81.053 ;
     RECT  36.36 80.941 36.378 81.059 ;
     RECT  64.44 80.971 68.418 81.059 ;
     RECT  34.815 80.249 35.097 81.103 ;
     RECT  34.776 81.103 35.097 81.211 ;
     RECT  69.516 80.957 70.11 81.293 ;
     RECT  38.736 81.067 38.754 81.301 ;
     RECT  34.776 81.211 35.514 81.329 ;
     RECT  38.664 81.301 38.754 81.337 ;
     RECT  3.708 80.941 6.246 81.365 ;
     RECT  2.304 80.519 2.697 81.403 ;
     RECT  30.78 81.031 30.798 81.409 ;
     RECT  9.108 81.301 9.126 81.437 ;
     RECT  30.78 81.409 30.87 81.437 ;
     RECT  36.468 81.211 36.486 81.437 ;
     RECT  61.815 80.941 63.378 81.473 ;
     RECT  3.888 81.365 6.246 81.481 ;
     RECT  7.092 80.789 8.097 81.481 ;
     RECT  30.852 81.437 30.87 81.509 ;
     RECT  38.664 81.337 38.79 81.509 ;
     RECT  0.54 81.211 0.558 81.581 ;
     RECT  2.304 81.403 2.862 81.599 ;
     RECT  34.776 81.329 35.097 81.607 ;
     RECT  34.2 81.607 35.097 81.751 ;
     RECT  64.44 81.059 68.13 81.751 ;
     RECT  64.368 81.751 68.13 81.779 ;
     RECT  34.164 81.751 35.097 81.869 ;
     RECT  63.108 81.473 63.378 81.877 ;
     RECT  69.552 81.293 70.11 81.941 ;
     RECT  3.888 81.481 8.097 82.013 ;
     RECT  63.108 81.877 63.45 82.061 ;
     RECT  69.552 81.941 69.966 82.075 ;
     RECT  63.108 82.061 63.126 82.175 ;
     RECT  69.516 82.075 69.966 82.211 ;
     RECT  34.815 81.869 35.097 82.291 ;
     RECT  64.368 81.779 64.797 82.291 ;
     RECT  36.432 82.291 36.45 82.381 ;
     RECT  61.815 81.473 62.097 82.381 ;
     RECT  65.592 81.779 68.13 82.381 ;
     RECT  3.888 82.013 3.978 82.409 ;
     RECT  70.704 82.267 70.722 82.411 ;
     RECT  64.116 82.291 64.797 82.481 ;
     RECT  70.704 82.411 70.758 82.481 ;
     RECT  65.592 82.381 68.202 82.489 ;
     RECT  34.815 82.291 35.622 82.553 ;
     RECT  2.304 81.599 2.697 82.651 ;
     RECT  4.824 82.013 8.097 82.651 ;
     RECT  65.592 82.489 68.562 82.679 ;
     RECT  36.432 82.381 36.594 82.687 ;
     RECT  4.824 82.651 8.73 82.759 ;
     RECT  70.704 82.481 70.722 82.787 ;
     RECT  2.304 82.651 2.718 82.831 ;
     RECT  64.368 82.481 64.797 82.831 ;
     RECT  65.592 82.679 67.842 82.831 ;
     RECT  3.96 82.409 3.978 82.859 ;
     RECT  38.736 82.651 38.754 82.859 ;
     RECT  36.432 82.687 36.702 82.921 ;
     RECT  4.824 82.759 9.054 82.949 ;
     RECT  61.815 82.381 62.838 82.957 ;
     RECT  64.368 82.831 67.842 83.021 ;
     RECT  30.78 82.759 30.798 83.029 ;
     RECT  34.815 82.553 35.334 83.029 ;
     RECT  2.304 82.831 2.97 83.056 ;
     RECT  8.82 82.949 9.054 83.057 ;
     RECT  69.516 82.211 69.714 83.083 ;
     RECT  61.815 82.957 62.91 83.093 ;
     RECT  2.304 83.056 3.006 83.101 ;
     RECT  30.78 83.029 30.87 83.129 ;
     RECT  34.776 83.029 35.334 83.129 ;
     RECT  7.452 82.949 8.097 83.219 ;
     RECT  30.78 83.129 30.798 83.219 ;
     RECT  36.144 82.921 36.702 83.219 ;
     RECT  2.304 83.101 3.078 83.263 ;
     RECT  2.304 83.263 3.15 83.335 ;
     RECT  4.824 82.949 6.606 83.371 ;
     RECT  4.032 83.371 6.606 83.399 ;
     RECT  65.592 83.021 67.842 83.533 ;
     RECT  0.54 83.101 0.558 83.549 ;
     RECT  59.115 79.709 59.397 83.569 ;
     RECT  64.368 83.021 64.797 83.569 ;
     RECT  65.592 83.533 68.202 83.569 ;
     RECT  2.304 83.335 3.294 83.605 ;
     RECT  4.032 83.399 5.778 83.605 ;
     RECT  34.815 83.129 35.334 83.605 ;
     RECT  63.684 83.569 64.797 83.641 ;
     RECT  69.516 83.083 70.11 83.641 ;
     RECT  63.612 83.641 64.797 83.669 ;
     RECT  63.612 83.669 63.63 83.759 ;
     RECT  8.82 83.057 8.838 83.795 ;
     RECT  69.3 83.641 70.11 83.795 ;
     RECT  34.815 83.605 35.406 83.803 ;
     RECT  61.815 83.093 62.874 83.851 ;
     RECT  61.815 83.851 63.27 83.885 ;
     RECT  64.368 83.669 64.797 83.911 ;
     RECT  65.592 83.569 68.346 83.911 ;
     RECT  69.3 83.795 69.714 83.911 ;
     RECT  9.108 83.803 9.126 84.029 ;
     RECT  34.815 83.803 35.514 84.029 ;
     RECT  36.324 83.219 36.414 84.029 ;
     RECT  38.772 84.001 38.79 84.101 ;
     RECT  6.804 83.839 6.894 84.173 ;
     RECT  58.716 83.569 59.397 84.173 ;
     RECT  2.304 83.605 5.778 84.181 ;
     RECT  32.115 57.839 32.397 84.181 ;
     RECT  34.815 84.029 35.334 84.181 ;
     RECT  2.268 84.181 6.786 84.221 ;
     RECT  2.304 84.221 6.786 84.299 ;
     RECT  34.776 84.181 35.334 84.299 ;
     RECT  38.736 84.181 38.754 84.299 ;
     RECT  63.108 83.885 63.27 84.335 ;
     RECT  64.368 83.911 69.714 84.371 ;
     RECT  31.932 84.181 32.397 84.569 ;
     RECT  64.368 84.371 68.814 84.649 ;
     RECT  69.66 84.371 69.714 84.715 ;
     RECT  70.704 84.073 70.722 84.715 ;
     RECT  59.115 84.173 59.397 84.721 ;
     RECT  64.116 84.649 68.814 84.721 ;
     RECT  64.044 84.721 68.814 84.811 ;
     RECT  6.768 84.299 6.786 84.839 ;
     RECT  2.304 84.299 5.994 84.911 ;
     RECT  63.972 84.811 68.814 84.911 ;
     RECT  7.815 83.219 8.097 84.919 ;
     RECT  34.815 84.299 35.334 84.919 ;
     RECT  59.115 84.721 59.886 84.955 ;
     RECT  6.984 84.919 8.097 84.991 ;
     RECT  61.815 83.885 62.097 84.991 ;
     RECT  63.108 84.335 63.126 84.991 ;
     RECT  58.788 84.955 59.886 85.019 ;
     RECT  34.815 84.919 35.622 85.081 ;
     RECT  61.815 84.991 63.126 85.081 ;
     RECT  34.815 85.081 35.694 85.181 ;
     RECT  34.815 85.181 35.586 85.217 ;
     RECT  58.788 85.019 59.454 85.253 ;
     RECT  34.815 85.217 35.226 85.261 ;
     RECT  58.824 85.253 59.454 85.289 ;
     RECT  64.332 84.911 68.814 85.339 ;
     RECT  69.66 84.715 70.722 85.339 ;
     RECT  6.984 84.991 8.154 85.379 ;
     RECT  64.332 85.339 70.722 85.421 ;
     RECT  61.815 85.081 63.522 85.451 ;
     RECT  30.78 84.145 30.798 85.487 ;
     RECT  34.776 85.261 35.226 85.487 ;
     RECT  64.44 85.421 70.722 85.649 ;
     RECT  2.304 84.911 5.778 85.657 ;
     RECT  68.508 85.649 70.722 85.685 ;
     RECT  38.736 85.081 38.754 85.721 ;
     RECT  2.304 85.657 5.814 85.729 ;
     RECT  6.984 85.379 8.097 85.805 ;
     RECT  59.115 85.289 59.454 85.829 ;
     RECT  6.984 85.805 7.038 85.891 ;
     RECT  68.688 85.685 70.722 85.919 ;
     RECT  36.504 85.801 36.522 85.955 ;
     RECT  2.304 85.729 5.85 86.027 ;
     RECT  34.815 85.487 35.226 86.071 ;
     RECT  0.54 85.963 0.558 86.189 ;
     RECT  34.815 86.071 35.622 86.189 ;
     RECT  59.115 85.829 59.397 86.269 ;
     RECT  64.44 85.649 67.497 86.269 ;
     RECT  58.716 86.269 59.397 86.369 ;
     RECT  4.824 86.027 5.85 86.459 ;
     RECT  64.26 86.269 67.497 86.459 ;
     RECT  5.076 86.459 5.85 86.467 ;
     RECT  64.332 86.459 67.497 86.467 ;
     RECT  30.852 85.927 30.87 86.495 ;
     RECT  68.94 85.919 70.722 86.531 ;
     RECT  61.815 85.451 63.306 86.621 ;
     RECT  5.076 86.467 6.066 86.635 ;
     RECT  6.804 85.891 7.038 86.635 ;
     RECT  7.815 85.805 8.097 86.635 ;
     RECT  5.076 86.635 8.097 86.669 ;
     RECT  36.648 86.431 36.666 86.729 ;
     RECT  64.332 86.467 67.698 86.773 ;
     RECT  64.332 86.773 67.914 86.809 ;
     RECT  58.788 86.369 59.397 86.909 ;
     RECT  5.076 86.669 5.778 86.999 ;
     RECT  61.815 86.621 62.91 86.999 ;
     RECT  64.332 86.809 68.094 86.999 ;
     RECT  34.815 86.189 35.097 87.043 ;
     RECT  5.076 86.999 5.454 87.107 ;
     RECT  38.736 87.007 38.754 87.107 ;
     RECT  2.304 86.027 4.05 87.143 ;
     RECT  70.704 86.531 70.722 87.163 ;
     RECT  36.72 86.881 36.738 87.179 ;
     RECT  64.332 86.999 67.806 87.197 ;
     RECT  68.94 86.531 69.678 87.241 ;
     RECT  68.904 87.241 69.678 87.307 ;
     RECT  66.708 87.197 67.806 87.341 ;
     RECT  68.904 87.307 69.714 87.385 ;
     RECT  35.892 86.971 35.91 87.449 ;
     RECT  68.544 87.385 69.714 87.499 ;
     RECT  70.704 87.163 70.758 87.499 ;
     RECT  34.815 87.043 35.154 87.539 ;
     RECT  68.544 87.499 70.758 87.539 ;
     RECT  34.815 87.539 35.097 87.583 ;
     RECT  68.544 87.539 68.562 87.611 ;
     RECT  6.66 86.669 8.097 87.685 ;
     RECT  64.332 87.197 65.754 87.773 ;
     RECT  61.815 86.999 62.802 87.781 ;
     RECT  34.632 87.583 35.097 87.809 ;
     RECT  66.744 87.341 67.806 87.853 ;
     RECT  2.304 87.143 3.078 87.889 ;
     RECT  3.996 87.143 4.05 87.889 ;
     RECT  5.115 87.107 5.454 87.889 ;
     RECT  6.516 87.685 8.097 87.889 ;
     RECT  2.304 87.889 4.05 87.925 ;
     RECT  5.115 87.889 5.778 87.925 ;
     RECT  2.304 87.925 5.778 87.953 ;
     RECT  30.78 87.547 30.798 88.123 ;
     RECT  36.216 87.781 36.234 88.151 ;
     RECT  65.592 87.773 65.754 88.159 ;
     RECT  64.332 87.773 64.797 88.195 ;
     RECT  4.356 87.953 5.778 88.219 ;
     RECT  6.516 87.889 8.154 88.219 ;
     RECT  30.78 88.123 30.87 88.223 ;
     RECT  59.115 86.909 59.397 88.231 ;
     RECT  66.744 87.853 68.202 88.231 ;
     RECT  35.964 88.195 36.054 88.321 ;
     RECT  4.356 88.219 8.19 88.349 ;
     RECT  35.928 88.321 36.054 88.349 ;
     RECT  58.788 88.231 59.397 88.349 ;
     RECT  61.815 87.781 62.838 88.363 ;
     RECT  63.756 88.195 64.797 88.363 ;
     RECT  61.815 88.363 64.797 88.385 ;
     RECT  61.815 88.385 63.486 88.397 ;
     RECT  35.928 88.349 35.982 88.421 ;
     RECT  65.592 88.159 65.826 88.465 ;
     RECT  66.6 88.231 68.202 88.465 ;
     RECT  35.928 88.421 35.946 88.493 ;
     RECT  69.552 87.539 70.758 88.493 ;
     RECT  34.815 87.809 35.097 88.501 ;
     RECT  2.304 87.953 3.546 88.603 ;
     RECT  69.552 88.493 70.11 88.603 ;
     RECT  4.356 88.349 6.858 88.619 ;
     RECT  30.78 88.223 30.798 88.619 ;
     RECT  2.268 88.603 3.546 88.691 ;
     RECT  38.736 88.087 38.754 88.691 ;
     RECT  7.776 88.349 8.19 88.699 ;
     RECT  34.815 88.501 35.19 88.735 ;
     RECT  69.372 88.603 70.11 88.763 ;
     RECT  7.776 88.699 8.298 88.771 ;
     RECT  64.26 88.385 64.797 88.771 ;
     RECT  65.592 88.465 68.202 88.771 ;
     RECT  7.776 88.771 8.838 88.889 ;
     RECT  63.072 88.397 63.486 88.889 ;
     RECT  64.26 88.771 68.382 88.889 ;
     RECT  7.776 88.889 8.097 88.925 ;
     RECT  63.072 88.889 63.342 88.925 ;
     RECT  64.368 88.889 66.474 88.925 ;
     RECT  34.2 88.735 35.19 88.969 ;
     RECT  33.624 88.969 35.19 89.005 ;
     RECT  33.624 89.005 35.73 89.159 ;
     RECT  61.815 88.397 62.097 89.167 ;
     RECT  63.072 88.925 63.234 89.167 ;
     RECT  33.624 89.159 35.097 89.339 ;
     RECT  38.772 89.167 38.79 89.339 ;
     RECT  69.408 88.763 70.11 89.339 ;
     RECT  2.304 88.691 3.546 89.401 ;
     RECT  4.356 88.619 6.786 89.429 ;
     RECT  6.696 89.429 6.786 89.509 ;
     RECT  7.815 88.925 8.097 89.659 ;
     RECT  2.304 89.401 3.582 89.671 ;
     RECT  4.356 89.429 5.778 89.671 ;
     RECT  35.82 89.509 36.45 89.671 ;
     RECT  67.215 88.889 68.382 89.699 ;
     RECT  9.144 89.509 9.306 89.735 ;
     RECT  9.144 89.735 9.27 89.771 ;
     RECT  35.82 89.671 36.522 89.771 ;
     RECT  64.368 88.925 66.402 89.941 ;
     RECT  9.252 89.771 9.27 89.969 ;
     RECT  64.296 89.941 66.402 90.013 ;
     RECT  7.815 89.659 8.262 90.029 ;
     RECT  64.296 90.013 66.438 90.085 ;
     RECT  67.215 89.699 68.202 90.085 ;
     RECT  69.516 89.339 70.11 90.091 ;
     RECT  61.815 89.167 63.234 90.121 ;
     RECT  64.296 90.085 68.202 90.211 ;
     RECT  34.236 89.339 35.097 90.239 ;
     RECT  6.696 89.509 6.894 90.283 ;
     RECT  2.304 89.671 5.778 90.311 ;
     RECT  30.852 90.247 30.87 90.391 ;
     RECT  34.815 90.239 35.097 90.391 ;
     RECT  35.82 89.771 36.09 90.391 ;
     RECT  61.815 90.121 63.27 90.391 ;
     RECT  64.044 90.211 68.202 90.391 ;
     RECT  30.78 90.391 30.87 90.419 ;
     RECT  30.78 90.419 30.798 90.509 ;
     RECT  34.815 90.391 36.09 90.509 ;
     RECT  61.815 90.391 68.202 90.509 ;
     RECT  69.3 90.091 70.11 90.553 ;
     RECT  69.264 90.553 70.11 90.617 ;
     RECT  4.032 90.311 5.778 90.625 ;
     RECT  6.552 90.283 6.894 90.625 ;
     RECT  7.815 90.029 8.097 90.625 ;
     RECT  67.215 90.509 68.202 90.661 ;
     RECT  61.815 90.509 66.114 90.689 ;
     RECT  4.032 90.625 6.894 90.751 ;
     RECT  33.624 90.589 33.642 90.779 ;
     RECT  60.984 90.481 61.002 90.779 ;
     RECT  7.668 90.625 8.097 90.895 ;
     RECT  36.288 90.823 36.306 90.931 ;
     RECT  4.032 90.751 6.93 90.955 ;
     RECT  7.668 90.895 8.37 90.955 ;
     RECT  4.032 90.955 8.37 91.021 ;
     RECT  9.18 90.751 9.198 91.021 ;
     RECT  4.032 91.021 9.234 91.049 ;
     RECT  6.804 91.049 9.234 91.157 ;
     RECT  2.304 90.311 3.114 91.201 ;
     RECT  59.115 88.349 59.397 91.201 ;
     RECT  2.304 91.201 3.15 91.319 ;
     RECT  69.588 90.617 70.11 91.387 ;
     RECT  69.516 91.387 70.11 91.391 ;
     RECT  36.288 90.931 36.378 91.435 ;
     RECT  61.815 90.689 64.797 91.435 ;
     RECT  65.592 90.689 66.114 91.435 ;
     RECT  38.772 90.751 38.79 91.471 ;
     RECT  58.788 91.201 59.397 91.471 ;
     RECT  67.215 90.661 68.634 91.471 ;
     RECT  69.516 91.391 69.966 91.471 ;
     RECT  4.032 91.049 5.778 91.561 ;
     RECT  35.856 91.435 36.378 91.589 ;
     RECT  58.716 91.471 59.397 91.589 ;
     RECT  61.815 91.435 66.114 91.589 ;
     RECT  38.664 91.471 38.79 91.625 ;
     RECT  61.815 91.589 62.982 91.625 ;
     RECT  2.415 91.319 3.15 91.627 ;
     RECT  34.815 90.509 35.097 91.633 ;
     RECT  64.08 91.589 66.114 91.661 ;
     RECT  64.188 91.661 66.114 91.669 ;
     RECT  35.964 91.589 36.378 91.697 ;
     RECT  64.188 91.669 66.222 91.697 ;
     RECT  0.252 91.627 0.27 91.757 ;
     RECT  9.144 91.157 9.162 91.769 ;
     RECT  38.736 91.625 38.79 91.769 ;
     RECT  61.815 91.625 62.766 91.769 ;
     RECT  70.704 91.723 70.722 91.769 ;
     RECT  2.415 91.627 3.186 91.831 ;
     RECT  60.984 91.669 61.002 91.895 ;
     RECT  2.415 91.831 3.258 91.903 ;
     RECT  3.996 91.561 5.778 91.903 ;
     RECT  67.215 91.471 69.966 91.931 ;
     RECT  38.808 91.867 38.826 91.967 ;
     RECT  7.092 91.157 8.097 92.011 ;
     RECT  6.552 92.011 8.097 92.059 ;
     RECT  65.592 91.697 66.222 92.101 ;
     RECT  65.592 92.101 66.258 92.155 ;
     RECT  2.415 91.903 5.778 92.165 ;
     RECT  34.2 91.633 35.097 92.165 ;
     RECT  68.364 91.931 69.966 92.203 ;
     RECT  6.552 92.059 8.226 92.273 ;
     RECT  65.592 92.155 66.294 92.281 ;
     RECT  2.415 92.165 5.742 92.371 ;
     RECT  2.304 92.371 5.742 92.399 ;
     RECT  67.215 91.931 67.626 92.407 ;
     RECT  2.304 92.399 5.67 92.429 ;
     RECT  35.964 91.697 35.982 92.434 ;
     RECT  35.928 92.434 35.982 92.515 ;
     RECT  64.188 91.697 64.797 92.515 ;
     RECT  65.592 92.281 66.366 92.515 ;
     RECT  35.892 92.515 35.982 92.551 ;
     RECT  61.815 91.769 62.097 92.551 ;
     RECT  62.82 92.371 62.838 92.551 ;
     RECT  68.364 92.203 70.11 92.573 ;
     RECT  67.14 92.407 67.626 92.579 ;
     RECT  6.696 92.273 8.226 92.669 ;
     RECT  9.18 92.641 9.27 92.713 ;
     RECT  8.964 92.713 9.342 92.813 ;
     RECT  9.18 92.813 9.198 92.849 ;
     RECT  0.216 92.779 0.234 92.909 ;
     RECT  64.188 92.515 66.366 92.909 ;
     RECT  67.215 92.579 67.626 92.983 ;
     RECT  68.364 92.573 68.706 92.983 ;
     RECT  61.815 92.551 62.838 93.055 ;
     RECT  69.588 92.573 70.11 93.083 ;
     RECT  34.776 92.165 35.097 93.091 ;
     RECT  35.892 92.551 36.27 93.091 ;
     RECT  2.415 92.429 5.67 93.208 ;
     RECT  6.696 92.669 8.097 93.208 ;
     RECT  34.776 93.091 36.27 93.209 ;
     RECT  70.056 93.083 70.11 93.211 ;
     RECT  2.415 93.208 8.097 93.245 ;
     RECT  64.404 92.909 66.366 93.245 ;
     RECT  30.78 93.055 30.798 93.281 ;
     RECT  70.056 93.211 70.722 93.281 ;
     RECT  59.115 91.589 59.397 93.289 ;
     RECT  35.82 93.209 36.27 93.325 ;
     RECT  70.092 93.281 70.722 93.353 ;
     RECT  1.152 93.259 1.17 93.389 ;
     RECT  35.82 93.325 36.63 93.451 ;
     RECT  67.215 92.983 68.706 93.451 ;
     RECT  58.716 93.289 59.397 93.479 ;
     RECT  61.815 93.055 63.27 93.479 ;
     RECT  0.54 93.451 0.558 93.533 ;
     RECT  67.104 93.451 68.706 93.547 ;
     RECT  35.82 93.451 36.702 93.623 ;
     RECT  64.404 93.245 64.797 93.721 ;
     RECT  65.592 93.245 66.366 93.721 ;
     RECT  67.104 93.547 69.318 93.721 ;
     RECT  35.82 93.623 36.558 93.749 ;
     RECT  65.592 93.721 69.318 93.857 ;
     RECT  6.804 93.245 8.097 93.893 ;
     RECT  2.415 93.245 6.066 93.991 ;
     RECT  6.84 93.893 8.097 94.019 ;
     RECT  63.684 93.721 64.797 94.063 ;
     RECT  65.592 93.857 68.994 94.063 ;
     RECT  9.144 94.063 9.162 94.289 ;
     RECT  35.928 93.749 36.558 94.289 ;
     RECT  63.684 94.063 68.994 94.289 ;
     RECT  70.092 93.353 70.11 94.363 ;
     RECT  2.304 93.991 6.066 94.369 ;
     RECT  61.815 93.479 62.73 94.441 ;
     RECT  63.972 94.289 68.994 94.469 ;
     RECT  2.268 94.369 6.066 94.541 ;
     RECT  2.304 94.541 6.066 94.595 ;
     RECT  61.815 94.441 62.766 94.651 ;
     RECT  70.092 94.363 70.722 94.651 ;
     RECT  0.216 94.531 0.234 94.877 ;
     RECT  6.912 94.019 8.097 94.909 ;
     RECT  34.776 93.209 35.097 94.909 ;
     RECT  35.928 94.289 36.27 94.909 ;
     RECT  38.772 94.873 38.79 94.973 ;
     RECT  2.304 94.595 5.706 95.009 ;
     RECT  63.972 94.469 68.67 95.099 ;
     RECT  34.776 94.909 36.27 95.107 ;
     RECT  0.54 94.981 0.558 95.213 ;
     RECT  34.776 95.107 36.486 95.279 ;
     RECT  34.815 95.279 36.486 95.369 ;
     RECT  69.408 94.651 70.722 95.477 ;
     RECT  4.212 95.009 5.706 95.521 ;
     RECT  6.588 94.909 8.097 95.521 ;
     RECT  61.815 94.651 63.198 95.549 ;
     RECT  64.044 95.099 68.67 95.647 ;
     RECT  69.408 95.477 70.11 95.647 ;
     RECT  64.044 95.647 70.11 95.675 ;
     RECT  65.628 95.675 70.11 95.747 ;
     RECT  4.212 95.521 8.097 95.783 ;
     RECT  2.304 95.009 3.438 95.791 ;
     RECT  4.212 95.783 5.778 95.791 ;
     RECT  59.115 93.479 59.397 95.791 ;
     RECT  58.716 95.791 59.397 95.909 ;
     RECT  64.044 95.675 64.797 95.909 ;
     RECT  68.364 95.747 70.11 95.909 ;
     RECT  68.904 95.909 70.11 96.179 ;
     RECT  34.815 95.369 35.946 96.215 ;
     RECT  6.624 95.783 8.097 96.251 ;
     RECT  1.152 96.139 1.17 96.269 ;
     RECT  2.304 95.791 5.778 96.323 ;
     RECT  35.928 96.215 35.946 96.331 ;
     RECT  69.372 96.179 70.11 96.331 ;
     RECT  35.928 96.331 36.666 96.449 ;
     RECT  2.304 96.323 5.598 96.485 ;
     RECT  63.036 95.549 63.198 96.485 ;
     RECT  69.372 96.331 70.722 96.521 ;
     RECT  34.815 96.215 35.097 96.529 ;
     RECT  61.815 95.549 62.262 96.529 ;
     RECT  38.736 95.881 38.754 96.557 ;
     RECT  6.768 96.251 8.097 96.601 ;
     RECT  9.144 95.755 9.162 96.601 ;
     RECT  64.44 95.909 64.797 96.601 ;
     RECT  70.668 96.521 70.722 96.619 ;
     RECT  2.304 96.485 5.397 96.629 ;
     RECT  34.776 96.529 35.097 96.629 ;
     RECT  61.815 96.529 62.73 96.629 ;
     RECT  65.628 95.747 67.497 96.629 ;
     RECT  61.815 96.629 62.37 96.719 ;
     RECT  64.44 96.601 64.818 96.719 ;
     RECT  6.768 96.601 9.162 96.755 ;
     RECT  7.668 96.755 9.162 96.791 ;
     RECT  38.772 96.727 38.79 96.827 ;
     RECT  6.768 96.755 6.93 96.863 ;
     RECT  69.372 96.521 69.39 96.863 ;
     RECT  6.912 96.863 6.93 96.899 ;
     RECT  9.144 96.791 9.162 96.899 ;
     RECT  3.924 96.629 5.397 96.989 ;
     RECT  64.44 96.719 64.797 97.169 ;
     RECT  2.304 96.629 2.697 97.259 ;
     RECT  4.536 96.989 5.397 97.259 ;
     RECT  68.22 97.141 68.238 97.259 ;
     RECT  65.736 96.629 67.497 97.295 ;
     RECT  65.916 97.295 67.497 97.331 ;
     RECT  70.668 96.619 70.758 97.331 ;
     RECT  65.916 97.331 66.438 97.367 ;
     RECT  69.3 96.955 69.318 97.403 ;
     RECT  70.668 97.331 70.722 97.565 ;
     RECT  70.704 97.565 70.722 97.637 ;
     RECT  68.328 97.681 68.346 97.799 ;
     RECT  66.42 97.367 66.438 97.979 ;
     RECT  2.415 97.259 2.697 99.107 ;
     RECT  5.115 97.259 5.397 99.107 ;
     RECT  7.815 96.791 8.097 99.107 ;
     RECT  10.515 78.539 10.797 99.107 ;
     RECT  13.215 51.149 13.497 99.107 ;
     RECT  15.915 50.855 16.197 99.107 ;
     RECT  18.615 50.765 18.897 99.107 ;
     RECT  21.315 50.765 21.597 99.107 ;
     RECT  24.015 2.413 24.297 99.107 ;
     RECT  26.715 2.413 26.997 99.107 ;
     RECT  29.415 25.313 29.697 99.107 ;
     RECT  32.115 84.569 32.397 99.107 ;
     RECT  34.815 96.629 35.097 99.107 ;
     RECT  37.515 79.439 37.797 99.107 ;
     RECT  40.215 2.413 40.497 99.107 ;
     RECT  42.915 4.829 43.197 99.107 ;
     RECT  45.615 57.581 45.897 99.107 ;
     RECT  48.315 7.619 48.597 99.107 ;
     RECT  51.015 2.413 51.297 99.107 ;
     RECT  53.715 57.581 53.997 99.107 ;
     RECT  56.415 2.413 56.697 99.107 ;
     RECT  59.115 95.909 59.397 99.107 ;
     RECT  61.815 96.719 62.097 99.107 ;
     RECT  64.515 97.169 64.797 99.107 ;
     RECT  67.215 97.331 67.497 99.107 ;
     RECT  2.415 99.107 2.505 99.377 ;
     RECT  5.115 99.107 5.205 99.377 ;
     RECT  7.815 99.107 7.905 99.377 ;
     RECT  10.515 99.107 10.605 99.377 ;
     RECT  13.215 99.107 13.305 99.377 ;
     RECT  15.915 99.107 16.005 99.377 ;
     RECT  18.615 99.107 18.705 99.377 ;
     RECT  21.315 99.107 21.405 99.377 ;
     RECT  24.015 99.107 24.105 99.377 ;
     RECT  26.715 99.107 26.805 99.377 ;
     RECT  29.415 99.107 29.505 99.377 ;
     RECT  32.115 99.107 32.205 99.377 ;
     RECT  34.815 99.107 34.905 99.377 ;
     RECT  37.515 99.107 37.605 99.377 ;
     RECT  40.215 99.107 40.305 99.377 ;
     RECT  42.915 99.107 43.005 99.377 ;
     RECT  45.615 99.107 45.705 99.377 ;
     RECT  48.315 99.107 48.405 99.377 ;
     RECT  51.015 99.107 51.105 99.377 ;
     RECT  53.715 99.107 53.805 99.377 ;
     RECT  56.415 99.107 56.505 99.377 ;
     RECT  59.115 99.107 59.205 99.377 ;
     RECT  61.815 99.107 61.905 99.377 ;
     RECT  64.515 99.107 64.605 99.377 ;
     RECT  67.215 99.107 67.305 99.377 ;
    LAYER M4 ;
     RECT  0.156 4.416 2.408 97.176 ;
     RECT  2.408 2.148 2.512 99.372 ;
     RECT  2.512 2.418 2.704 99.102 ;
     RECT  2.704 4.944 2.729 14.76 ;
     RECT  2.704 39.216 2.729 45.72 ;
     RECT  2.704 82.704 2.729 89.448 ;
     RECT  2.729 4.944 2.765 12.792 ;
     RECT  2.704 16.032 2.765 31.224 ;
     RECT  2.704 32.256 2.765 38.184 ;
     RECT  2.729 39.216 2.765 43.416 ;
     RECT  2.704 47.904 2.765 56.52 ;
     RECT  2.729 83.04 2.765 89.448 ;
     RECT  2.765 50.112 2.801 56.52 ;
     RECT  2.765 7.2 2.837 12.792 ;
     RECT  2.765 16.032 2.837 22.728 ;
     RECT  2.765 28.512 2.837 31.224 ;
     RECT  2.765 32.256 2.837 37.944 ;
     RECT  2.765 39.216 2.837 39.816 ;
     RECT  2.765 40.944 2.837 43.416 ;
     RECT  2.729 44.4 2.837 45.72 ;
     RECT  2.801 51.744 2.837 56.52 ;
     RECT  2.704 57.648 2.837 60.6 ;
     RECT  2.704 64.368 2.837 72.744 ;
     RECT  2.704 73.872 2.837 74.376 ;
     RECT  2.704 75.504 2.837 77.304 ;
     RECT  2.704 78.432 2.837 81.432 ;
     RECT  2.765 83.856 2.837 89.448 ;
     RECT  2.704 90.576 2.837 96.84 ;
     RECT  2.837 8.304 2.873 12.792 ;
     RECT  2.837 16.032 2.873 16.056 ;
     RECT  2.837 28.512 2.873 30.168 ;
     RECT  2.837 31.2 2.873 31.224 ;
     RECT  2.837 40.944 2.873 43.08 ;
     RECT  2.801 50.112 2.873 50.616 ;
     RECT  2.837 78.96 2.873 79.8 ;
     RECT  2.837 81.072 2.873 81.432 ;
     RECT  2.729 13.92 2.909 14.76 ;
     RECT  2.873 41.088 2.909 43.08 ;
     RECT  2.837 64.368 2.909 68.088 ;
     RECT  2.909 64.416 3.089 68.088 ;
     RECT  2.765 23.712 3.107 27.384 ;
     RECT  2.837 90.576 3.125 94.68 ;
     RECT  2.909 41.088 3.233 42.648 ;
     RECT  2.837 51.744 3.269 53.592 ;
     RECT  2.837 58.128 3.269 59.304 ;
     RECT  3.089 65.76 3.269 68.088 ;
     RECT  3.125 90.912 3.269 94.68 ;
     RECT  2.873 50.592 3.305 50.616 ;
     RECT  2.837 76.56 3.413 77.304 ;
     RECT  3.107 23.712 3.443 23.928 ;
     RECT  2.765 47.904 3.443 49.032 ;
     RECT  2.837 69.264 3.449 71.832 ;
     RECT  3.269 65.76 3.484 65.832 ;
     RECT  3.107 25.632 3.485 27.384 ;
     RECT  2.873 79.776 3.521 79.8 ;
     RECT  3.269 92.784 3.521 94.68 ;
     RECT  3.443 47.904 3.665 48.456 ;
     RECT  2.837 54.864 3.805 56.232 ;
     RECT  2.837 17.664 3.913 17.688 ;
     RECT  2.837 18.816 3.973 18.888 ;
     RECT  2.837 32.256 3.973 34.776 ;
     RECT  3.973 18.768 4.019 18.888 ;
     RECT  2.765 4.944 4.025 5.736 ;
     RECT  4.019 18.768 4.025 18.84 ;
     RECT  2.837 44.4 4.025 45.576 ;
     RECT  2.837 73.872 4.025 74.088 ;
     RECT  2.837 84.336 4.025 87.432 ;
     RECT  3.521 92.784 4.025 93.384 ;
     RECT  2.837 96.24 4.025 96.84 ;
     RECT  4.025 5.04 4.061 5.736 ;
     RECT  2.909 14.736 4.061 14.76 ;
     RECT  3.973 32.208 4.061 34.776 ;
     RECT  4.025 84.336 4.061 87.144 ;
     RECT  4.061 33.264 4.097 34.776 ;
     RECT  3.485 25.632 4.129 25.656 ;
     RECT  2.837 19.968 4.133 22.728 ;
     RECT  2.837 36.336 4.133 37.944 ;
     RECT  4.025 44.4 4.133 45.48 ;
     RECT  3.269 52.224 4.133 53.592 ;
     RECT  4.061 84.336 4.133 85.704 ;
     RECT  2.704 61.584 4.237 63.24 ;
     RECT  3.089 64.416 4.237 64.728 ;
     RECT  4.273 51.168 4.345 51.192 ;
     RECT  3.269 59.28 4.345 59.304 ;
     RECT  3.413 77.136 4.345 77.304 ;
     RECT  4.133 52.464 4.381 53.592 ;
     RECT  3.805 54.864 4.381 57.048 ;
     RECT  2.837 39.216 4.405 39.336 ;
     RECT  2.873 8.304 4.453 12.504 ;
     RECT  3.485 26.784 4.453 27.384 ;
     RECT  2.873 28.512 4.453 29.928 ;
     RECT  3.269 90.912 4.453 91.608 ;
     RECT  3.233 41.088 4.481 41.928 ;
     RECT  4.213 43.296 4.481 43.32 ;
     RECT  4.453 8.256 4.489 12.504 ;
     RECT  4.345 15.408 4.489 15.432 ;
     RECT  4.481 41.088 4.501 43.32 ;
     RECT  4.133 84.336 4.525 85.368 ;
     RECT  2.837 88.944 4.525 88.968 ;
     RECT  3.484 65.808 4.561 65.832 ;
     RECT  3.443 23.904 4.7 23.928 ;
     RECT  2.873 81.072 4.705 81.096 ;
     RECT  4.7 23.856 4.741 23.928 ;
     RECT  4.129 25.104 4.741 25.656 ;
     RECT  4.061 32.208 4.993 32.232 ;
     RECT  4.061 5.04 5.108 5.064 ;
     RECT  4.489 6.096 5.108 6.12 ;
     RECT  4.489 7.44 5.108 12.504 ;
     RECT  4.309 14.208 5.108 14.232 ;
     RECT  4.489 15.408 5.108 15.96 ;
     RECT  3.913 17.616 5.108 17.688 ;
     RECT  4.025 18.768 5.108 18.792 ;
     RECT  4.133 19.968 5.108 19.992 ;
     RECT  4.133 20.976 5.108 22.728 ;
     RECT  4.741 23.856 5.108 25.656 ;
     RECT  4.453 26.784 5.108 29.928 ;
     RECT  4.993 31.392 5.108 32.232 ;
     RECT  4.097 33.264 5.108 33.288 ;
     RECT  4.097 34.464 5.108 34.776 ;
     RECT  4.133 36.912 5.108 37.176 ;
     RECT  4.405 38.16 5.108 39.336 ;
     RECT  4.501 41.088 5.108 43.368 ;
     RECT  4.133 44.64 5.108 45.48 ;
     RECT  2.704 46.704 5.108 46.728 ;
     RECT  3.665 47.904 5.108 47.928 ;
     RECT  4.345 51.12 5.108 51.192 ;
     RECT  4.381 52.464 5.108 57.048 ;
     RECT  3.269 58.128 5.108 58.248 ;
     RECT  4.345 59.232 5.108 59.304 ;
     RECT  3.925 60.288 5.108 60.312 ;
     RECT  4.237 61.584 5.108 64.728 ;
     RECT  4.561 65.808 5.108 65.976 ;
     RECT  3.269 67.152 5.108 68.088 ;
     RECT  3.449 69.264 5.108 71.736 ;
     RECT  4.669 72.768 5.108 72.792 ;
     RECT  4.025 74.064 5.108 74.088 ;
     RECT  2.837 75.504 5.108 75.528 ;
     RECT  4.345 77.136 5.108 78.216 ;
     RECT  4.705 81.072 5.108 81.72 ;
     RECT  4.525 84.048 5.108 85.368 ;
     RECT  4.061 87.12 5.108 87.144 ;
     RECT  4.525 88.656 5.108 88.968 ;
     RECT  4.453 90.912 5.108 91.848 ;
     RECT  4.025 93.264 5.108 93.384 ;
     RECT  3.521 94.656 5.108 94.68 ;
     RECT  4.025 96.24 5.108 96.312 ;
     RECT  5.108 2.148 5.212 99.372 ;
     RECT  5.212 2.418 5.404 99.102 ;
     RECT  5.404 36.912 5.465 37.128 ;
     RECT  5.404 60.288 5.465 61.368 ;
     RECT  5.404 78.192 5.465 79.176 ;
     RECT  5.404 86.64 5.465 88.68 ;
     RECT  5.404 54.336 5.537 54.456 ;
     RECT  5.404 65.952 5.555 66.792 ;
     RECT  5.404 23.232 5.573 24.504 ;
     RECT  5.537 54.432 5.573 54.456 ;
     RECT  5.404 10.128 5.609 10.152 ;
     RECT  5.404 16.416 5.609 17.64 ;
     RECT  5.404 21.12 5.609 21.96 ;
     RECT  5.404 38.16 5.609 38.184 ;
     RECT  5.465 87.696 5.609 88.68 ;
     RECT  5.465 37.008 5.681 37.128 ;
     RECT  5.404 63.84 5.681 64.92 ;
     RECT  5.573 23.232 5.699 23.976 ;
     RECT  5.404 95.136 5.699 96.312 ;
     RECT  5.609 16.416 5.74 17.064 ;
     RECT  5.404 74.064 5.753 75.96 ;
     RECT  5.404 27.696 5.789 28.584 ;
     RECT  5.404 39.84 5.789 41.784 ;
     RECT  5.465 60.336 5.789 61.368 ;
     RECT  5.404 84.048 5.789 84.072 ;
     RECT  5.699 95.376 5.789 96.312 ;
     RECT  5.789 60.384 5.795 61.368 ;
     RECT  5.404 12.48 5.825 13.032 ;
     RECT  5.404 46.752 5.825 48.696 ;
     RECT  5.795 61.344 5.836 61.368 ;
     RECT  5.404 82.848 5.843 82.872 ;
     RECT  5.404 44.448 5.861 45.48 ;
     RECT  5.404 62.496 5.861 62.808 ;
     RECT  5.681 63.84 5.884 64.584 ;
     RECT  5.404 81.696 5.897 81.72 ;
     RECT  5.404 58.656 5.969 58.776 ;
     RECT  5.404 18.768 6.005 18.792 ;
     RECT  5.753 74.064 6.041 74.712 ;
     RECT  5.825 46.752 6.083 47.352 ;
     RECT  5.789 39.84 6.105 41.592 ;
     RECT  6.083 47.328 6.113 47.352 ;
     RECT  5.404 70.992 6.131 71.832 ;
     RECT  5.753 75.936 6.131 75.96 ;
     RECT  5.789 27.888 6.179 28.536 ;
     RECT  5.404 35.088 6.179 35.112 ;
     RECT  5.404 92.256 6.323 94.104 ;
     RECT  5.825 12.576 6.329 13.032 ;
     RECT  6.105 41.568 6.365 41.592 ;
     RECT  5.404 52.176 6.365 52.44 ;
     RECT  5.884 63.84 6.38 63.864 ;
     RECT  6.38 63.792 6.381 63.864 ;
     RECT  6.105 39.84 6.401 40.44 ;
     RECT  6.131 71.088 6.437 71.832 ;
     RECT  6.428 57.456 6.441 57.48 ;
     RECT  5.969 58.656 6.441 58.68 ;
     RECT  6.441 57.456 6.467 58.68 ;
     RECT  6.381 63.792 6.467 63.816 ;
     RECT  5.404 15.408 6.581 15.432 ;
     RECT  6.421 55.824 6.613 55.848 ;
     RECT  5.555 65.952 6.649 66.168 ;
     RECT  6.365 52.416 6.659 52.44 ;
     RECT  6.541 19.92 6.685 19.944 ;
     RECT  5.404 67.968 6.685 68.376 ;
     RECT  5.404 8.256 6.689 8.76 ;
     RECT  5.825 48.384 6.689 48.696 ;
     RECT  5.404 31.344 6.757 32.472 ;
     RECT  6.467 57.456 6.761 58.152 ;
     RECT  6.685 19.344 6.797 19.944 ;
     RECT  5.789 95.376 6.797 95.4 ;
     RECT  5.861 62.688 6.829 62.808 ;
     RECT  6.829 61.872 6.833 62.808 ;
     RECT  6.649 65.808 6.833 66.168 ;
     RECT  5.404 90.96 6.86 90.984 ;
     RECT  6.685 11.424 6.865 11.448 ;
     RECT  6.397 34.08 6.865 34.104 ;
     RECT  6.865 11.136 6.901 11.448 ;
     RECT  6.865 22.176 6.937 22.2 ;
     RECT  6.179 27.888 6.937 28.44 ;
     RECT  5.699 23.952 6.973 23.976 ;
     RECT  5.465 86.64 6.973 86.664 ;
     RECT  5.609 87.696 6.973 88.248 ;
     RECT  6.433 81.984 7.052 82.008 ;
     RECT  5.861 44.448 7.081 45.192 ;
     RECT  6.973 86.64 7.081 88.248 ;
     RECT  6.689 8.256 7.093 8.28 ;
     RECT  6.86 9.648 7.093 9.672 ;
     RECT  6.901 10.848 7.093 11.448 ;
     RECT  7.052 81.984 7.093 82.584 ;
     RECT  6.577 17.664 7.117 17.688 ;
     RECT  5.681 37.008 7.141 37.032 ;
     RECT  6.613 55.536 7.297 56.472 ;
     RECT  6.833 66.144 7.333 66.168 ;
     RECT  5.74 16.416 7.477 16.44 ;
     RECT  7.117 17.616 7.477 17.688 ;
     RECT  6.797 19.344 7.621 19.368 ;
     RECT  7.477 16.416 7.669 17.688 ;
     RECT  7.621 18.816 7.669 19.368 ;
     RECT  5.609 21.12 7.669 21.144 ;
     RECT  6.937 22.176 7.669 22.584 ;
     RECT  6.973 23.616 7.669 23.976 ;
     RECT  6.685 67.344 7.693 68.376 ;
     RECT  7.081 85.776 7.765 88.248 ;
     RECT  5.404 5.04 7.808 5.064 ;
     RECT  5.404 6.048 7.808 6.072 ;
     RECT  7.093 7.392 7.808 8.28 ;
     RECT  7.093 9.648 7.808 11.448 ;
     RECT  6.329 13.008 7.808 13.032 ;
     RECT  7.669 16.416 7.808 19.368 ;
     RECT  7.669 21.12 7.808 23.976 ;
     RECT  6.937 27.168 7.808 28.44 ;
     RECT  6.793 29.664 7.808 29.688 ;
     RECT  6.757 30.768 7.808 32.472 ;
     RECT  6.865 34.08 7.808 34.488 ;
     RECT  7.297 35.808 7.808 35.832 ;
     RECT  7.141 37.008 7.808 37.608 ;
     RECT  6.901 38.736 7.808 38.76 ;
     RECT  6.401 39.84 7.808 39.864 ;
     RECT  5.404 43.008 7.808 43.032 ;
     RECT  7.081 44.352 7.808 45.192 ;
     RECT  6.901 46.224 7.808 46.248 ;
     RECT  6.689 48.384 7.808 48.408 ;
     RECT  6.901 49.488 7.808 49.512 ;
     RECT  5.404 51.168 7.808 51.192 ;
     RECT  7.081 52.464 7.808 52.488 ;
     RECT  7.369 53.568 7.808 53.592 ;
     RECT  7.297 55.536 7.808 56.856 ;
     RECT  6.761 58.128 7.808 58.152 ;
     RECT  7.117 59.28 7.808 59.304 ;
     RECT  6.833 61.872 7.808 62.712 ;
     RECT  7.333 66.144 7.808 66.264 ;
     RECT  7.693 67.344 7.808 68.424 ;
     RECT  7.477 69.504 7.808 69.528 ;
     RECT  6.437 71.712 7.808 71.736 ;
     RECT  6.041 74.592 7.808 74.712 ;
     RECT  5.465 78.336 7.808 79.176 ;
     RECT  5.404 80.256 7.808 80.28 ;
     RECT  7.093 81.984 7.808 83.064 ;
     RECT  7.765 85.776 7.808 88.92 ;
     RECT  6.86 90.384 7.808 90.984 ;
     RECT  6.323 92.256 7.808 93.24 ;
     RECT  7.808 2.148 7.912 99.372 ;
     RECT  7.912 2.418 8.104 99.102 ;
     RECT  8.104 31.44 8.165 32.472 ;
     RECT  8.104 58.128 8.165 59.304 ;
     RECT  8.104 9.648 8.201 11.16 ;
     RECT  8.104 23.376 8.201 23.688 ;
     RECT  8.104 27.168 8.201 27.912 ;
     RECT  8.104 35.808 8.201 35.832 ;
     RECT  8.104 49.488 8.201 49.512 ;
     RECT  8.104 69.504 8.201 69.528 ;
     RECT  8.104 88.224 8.201 90.024 ;
     RECT  8.104 44.352 8.237 45.192 ;
     RECT  8.104 46.224 8.237 46.248 ;
     RECT  8.104 76.416 8.237 77.544 ;
     RECT  8.201 9.648 8.243 11.016 ;
     RECT  8.104 12.912 8.243 12.936 ;
     RECT  8.104 39.456 8.243 39.48 ;
     RECT  8.104 53.568 8.243 53.592 ;
     RECT  8.165 58.656 8.243 59.304 ;
     RECT  8.104 63.216 8.243 63.24 ;
     RECT  8.104 70.656 8.243 70.68 ;
     RECT  8.201 88.896 8.243 90.024 ;
     RECT  8.104 71.712 8.265 71.736 ;
     RECT  8.243 89.664 8.273 90.024 ;
     RECT  8.237 76.416 8.281 76.44 ;
     RECT  8.104 91.008 8.281 91.032 ;
     RECT  8.104 92.064 8.281 92.808 ;
     RECT  8.273 89.664 8.284 89.688 ;
     RECT  8.104 66.24 8.291 67.368 ;
     RECT  8.237 45.168 8.309 45.192 ;
     RECT  8.291 66.24 8.339 66.744 ;
     RECT  8.104 74.64 8.339 74.664 ;
     RECT  8.104 55.104 8.345 55.128 ;
     RECT  8.104 60.432 8.381 60.456 ;
     RECT  8.237 77.52 8.381 77.544 ;
     RECT  8.104 14.256 8.417 14.28 ;
     RECT  8.339 66.24 8.489 66.264 ;
     RECT  8.165 32.448 8.641 32.472 ;
     RECT  8.165 31.44 8.669 31.464 ;
     RECT  8.104 41.616 8.705 41.64 ;
     RECT  8.104 50.736 8.819 51.144 ;
     RECT  8.104 68.4 8.819 68.424 ;
     RECT  8.281 92.784 8.993 92.808 ;
     RECT  8.201 23.376 9.101 23.4 ;
     RECT  8.243 10.032 10.508 10.344 ;
     RECT  8.201 27.888 10.508 27.912 ;
     RECT  8.819 51.12 10.508 51.144 ;
     RECT  10.508 2.148 10.612 99.372 ;
     RECT  10.612 2.418 10.804 99.102 ;
     RECT  10.804 55.488 10.829 55.512 ;
     RECT  12.092 0.144 12.179 0.168 ;
     RECT  10.804 10.032 13.208 10.344 ;
     RECT  10.804 27.888 13.208 27.912 ;
     RECT  10.804 50.784 13.208 51.144 ;
     RECT  13.208 2.148 13.312 99.372 ;
     RECT  13.312 2.418 13.504 99.102 ;
     RECT  13.504 10.032 14.861 10.344 ;
     RECT  14.861 10.128 15.908 10.344 ;
     RECT  13.504 27.888 15.908 27.912 ;
     RECT  13.504 50.736 15.908 50.904 ;
     RECT  15.908 2.148 16.012 99.372 ;
     RECT  16.012 2.418 16.204 99.102 ;
     RECT  16.204 10.128 18.608 10.344 ;
     RECT  16.204 27.888 18.608 27.912 ;
     RECT  16.204 50.736 18.608 50.904 ;
     RECT  18.608 2.148 18.712 99.372 ;
     RECT  18.712 2.418 18.904 99.102 ;
     RECT  18.904 10.224 19.043 10.344 ;
     RECT  19.043 10.224 19.973 10.248 ;
     RECT  20.149 10.128 21.308 10.152 ;
     RECT  18.904 27.888 21.308 27.912 ;
     RECT  18.904 50.736 21.308 50.904 ;
     RECT  21.308 2.148 21.412 99.372 ;
     RECT  21.412 2.418 21.604 99.102 ;
     RECT  21.604 10.032 21.701 10.152 ;
     RECT  21.701 10.032 22.813 10.056 ;
     RECT  21.604 50.736 22.813 50.904 ;
     RECT  22.813 10.032 22.853 10.152 ;
     RECT  22.813 50.736 22.853 51.144 ;
     RECT  22.853 10.128 24.008 10.152 ;
     RECT  21.604 27.888 24.008 27.912 ;
     RECT  22.853 50.88 24.008 51.144 ;
     RECT  24.008 2.148 24.112 99.372 ;
     RECT  24.112 2.418 24.304 99.102 ;
     RECT  24.304 10.128 26.708 10.152 ;
     RECT  24.304 27.888 26.708 27.912 ;
     RECT  24.304 50.88 26.708 51.144 ;
     RECT  26.708 2.148 26.812 99.372 ;
     RECT  26.812 2.418 27.004 99.102 ;
     RECT  27.004 50.88 27.827 51.144 ;
     RECT  27.004 10.128 29.408 10.152 ;
     RECT  27.004 27.888 29.408 27.912 ;
     RECT  27.827 50.88 29.408 50.904 ;
     RECT  29.408 2.148 29.512 99.372 ;
     RECT  29.512 2.418 29.704 99.102 ;
     RECT  29.704 10.032 29.801 10.152 ;
     RECT  29.801 10.032 30.769 10.056 ;
     RECT  30.769 10.032 30.809 10.152 ;
     RECT  30.809 10.128 32.108 10.152 ;
     RECT  29.704 27.888 32.108 27.912 ;
     RECT  29.704 50.88 32.108 50.904 ;
     RECT  32.108 2.148 32.212 99.372 ;
     RECT  32.212 2.418 32.404 99.102 ;
     RECT  32.404 10.128 34.808 10.152 ;
     RECT  32.404 27.888 34.808 27.912 ;
     RECT  32.404 50.88 34.808 50.904 ;
     RECT  34.765 57.408 34.808 57.432 ;
     RECT  34.808 2.148 34.912 99.372 ;
     RECT  34.912 2.418 35.104 99.102 ;
     RECT  35.104 27.888 35.309 27.912 ;
     RECT  35.104 85.152 35.705 85.176 ;
     RECT  35.104 10.128 37.508 10.152 ;
     RECT  36.241 16.32 37.508 16.344 ;
     RECT  35.104 47.088 37.508 47.112 ;
     RECT  35.104 50.88 37.508 50.904 ;
     RECT  35.104 57.408 37.508 57.432 ;
     RECT  37.508 2.148 37.612 99.372 ;
     RECT  37.612 2.418 37.804 99.102 ;
     RECT  37.804 10.032 38.801 10.152 ;
     RECT  37.804 47.088 38.801 47.208 ;
     RECT  37.804 57.408 38.801 57.576 ;
     RECT  38.801 10.128 40.208 10.152 ;
     RECT  37.804 16.32 40.208 16.344 ;
     RECT  38.801 47.088 40.208 47.112 ;
     RECT  37.804 50.88 40.208 50.904 ;
     RECT  38.801 57.408 40.208 57.432 ;
     RECT  40.208 2.148 40.312 99.372 ;
     RECT  40.312 2.418 40.504 99.102 ;
     RECT  40.504 10.128 42.908 10.152 ;
     RECT  40.504 16.32 42.908 16.344 ;
     RECT  40.504 47.088 42.908 47.112 ;
     RECT  40.504 50.88 42.908 50.904 ;
     RECT  40.504 57.408 42.908 57.432 ;
     RECT  42.908 2.148 43.012 99.372 ;
     RECT  43.012 2.418 43.204 99.102 ;
     RECT  45.493 4.128 45.608 4.152 ;
     RECT  43.204 10.128 45.608 10.152 ;
     RECT  43.204 16.32 45.608 16.344 ;
     RECT  43.204 47.088 45.608 47.112 ;
     RECT  43.204 50.88 45.608 50.904 ;
     RECT  43.204 57.408 45.608 57.432 ;
     RECT  45.608 2.148 45.712 99.372 ;
     RECT  45.712 2.418 45.904 99.102 ;
     RECT  45.904 10.032 46.793 10.152 ;
     RECT  45.904 47.088 46.793 47.208 ;
     RECT  45.904 57.408 46.793 57.576 ;
     RECT  45.904 4.128 48.308 4.152 ;
     RECT  46.793 10.128 48.308 10.152 ;
     RECT  45.904 16.32 48.308 16.344 ;
     RECT  46.793 47.088 48.308 47.112 ;
     RECT  45.904 50.88 48.308 50.904 ;
     RECT  46.793 57.408 48.308 57.432 ;
     RECT  48.308 2.148 48.412 99.372 ;
     RECT  48.412 2.418 48.604 99.102 ;
     RECT  48.604 4.128 51.008 4.152 ;
     RECT  48.604 10.128 51.008 10.152 ;
     RECT  48.604 16.32 51.008 16.344 ;
     RECT  48.604 47.088 51.008 47.112 ;
     RECT  48.604 50.88 51.008 50.904 ;
     RECT  48.604 57.408 51.008 57.432 ;
     RECT  51.008 2.148 51.112 99.372 ;
     RECT  51.112 2.418 51.304 99.102 ;
     RECT  51.304 4.128 53.708 4.152 ;
     RECT  51.304 10.128 53.708 10.152 ;
     RECT  51.304 16.32 53.708 16.344 ;
     RECT  51.304 47.088 53.708 47.112 ;
     RECT  51.304 50.88 53.708 50.904 ;
     RECT  51.304 57.408 53.708 57.432 ;
     RECT  53.708 2.148 53.812 99.372 ;
     RECT  53.812 2.418 54.004 99.102 ;
     RECT  54.004 9.888 54.101 10.152 ;
     RECT  54.101 9.888 54.749 10.056 ;
     RECT  54.004 47.088 54.749 47.208 ;
     RECT  54.004 57.408 54.749 57.576 ;
     RECT  54.004 4.128 56.408 4.152 ;
     RECT  54.749 9.888 56.408 9.912 ;
     RECT  54.004 16.32 56.408 16.344 ;
     RECT  54.749 47.088 56.408 47.112 ;
     RECT  54.004 50.88 56.408 50.904 ;
     RECT  54.749 57.408 56.408 57.432 ;
     RECT  56.408 2.148 56.512 99.372 ;
     RECT  56.512 2.418 56.704 99.102 ;
     RECT  58.165 2.832 58.357 2.856 ;
     RECT  56.704 4.128 58.357 4.152 ;
     RECT  59.065 1.728 59.108 1.752 ;
     RECT  58.357 2.832 59.108 4.152 ;
     RECT  56.704 9.888 59.108 9.912 ;
     RECT  56.704 16.32 59.108 16.344 ;
     RECT  56.704 47.088 59.108 47.112 ;
     RECT  56.704 50.88 59.108 50.904 ;
     RECT  56.704 57.408 59.108 57.432 ;
     RECT  59.108 1.728 59.171 99.372 ;
     RECT  59.171 2.148 59.212 99.372 ;
     RECT  59.212 2.418 59.404 99.102 ;
     RECT  61.657 9.792 61.801 9.816 ;
     RECT  59.404 4.128 61.808 4.152 ;
     RECT  61.801 9.792 61.808 9.864 ;
     RECT  59.404 16.32 61.808 16.344 ;
     RECT  61.669 44.976 61.808 45 ;
     RECT  59.404 47.088 61.808 47.112 ;
     RECT  61.669 48.768 61.808 49.512 ;
     RECT  59.404 50.88 61.808 50.904 ;
     RECT  59.404 57.408 61.808 57.432 ;
     RECT  61.669 69.84 61.808 69.864 ;
     RECT  61.669 71.088 61.808 71.112 ;
     RECT  61.808 2.148 61.912 99.372 ;
     RECT  61.912 2.418 62.104 99.102 ;
     RECT  62.104 29.184 62.387 29.928 ;
     RECT  62.104 31.344 62.417 31.56 ;
     RECT  62.417 31.536 62.435 31.56 ;
     RECT  62.104 53.808 62.483 54.408 ;
     RECT  62.104 81.024 62.483 81.048 ;
     RECT  62.104 55.392 62.524 55.416 ;
     RECT  62.104 83.232 62.597 83.88 ;
     RECT  62.104 5.712 62.627 6.12 ;
     RECT  62.104 8.496 62.627 8.712 ;
     RECT  62.104 9.84 62.627 10.488 ;
     RECT  62.104 25.152 62.627 26.76 ;
     RECT  62.104 27.84 62.627 27.864 ;
     RECT  62.387 29.184 62.627 29.208 ;
     RECT  62.104 59.28 62.627 60.792 ;
     RECT  62.104 36.672 62.668 36.696 ;
     RECT  62.104 4.128 62.675 4.152 ;
     RECT  62.104 22.8 62.675 22.824 ;
     RECT  62.627 25.152 62.675 26.232 ;
     RECT  62.104 52.8 62.705 52.824 ;
     RECT  62.483 53.808 62.705 54.12 ;
     RECT  62.104 32.736 62.741 32.904 ;
     RECT  62.104 47.088 62.741 47.208 ;
     RECT  62.104 34.464 62.771 35.16 ;
     RECT  62.741 32.88 62.785 32.904 ;
     RECT  62.771 34.464 62.785 34.488 ;
     RECT  62.627 10.176 63.029 10.488 ;
     RECT  62.104 64.08 63.029 65.304 ;
     RECT  62.627 5.712 63.065 5.736 ;
     RECT  62.627 8.496 63.097 8.52 ;
     RECT  62.104 57.408 63.097 57.576 ;
     RECT  62.104 67.44 63.097 68.568 ;
     RECT  62.104 75.792 63.097 76.68 ;
     RECT  62.104 82.128 63.097 82.152 ;
     RECT  62.104 43.968 63.101 44.472 ;
     RECT  63.097 61.872 63.109 61.896 ;
     RECT  62.104 49.488 63.137 49.512 ;
     RECT  62.627 59.28 63.137 59.304 ;
     RECT  63.097 82.032 63.137 82.152 ;
     RECT  62.597 83.856 63.137 83.88 ;
     RECT  63.029 10.464 63.155 10.488 ;
     RECT  63.068 11.712 63.155 11.736 ;
     RECT  62.104 13.008 63.155 13.8 ;
     RECT  63.068 18.72 63.155 18.744 ;
     RECT  62.104 19.728 63.155 19.752 ;
     RECT  63.029 64.08 63.155 64.104 ;
     RECT  62.104 93.984 63.169 94.008 ;
     RECT  63.029 65.28 63.205 65.304 ;
     RECT  63.097 66.72 63.205 68.568 ;
     RECT  62.104 95.904 63.209 95.928 ;
     RECT  63.097 8.16 63.245 8.52 ;
     RECT  62.104 56.4 63.251 56.424 ;
     RECT  63.205 65.28 63.251 65.688 ;
     RECT  63.205 66.72 63.251 68.904 ;
     RECT  62.104 85.104 63.277 85.272 ;
     RECT  62.104 86.736 63.277 86.76 ;
     RECT  63.097 75.792 63.299 76.968 ;
     RECT  63.155 13.776 63.317 13.8 ;
     RECT  63.133 23.664 63.317 23.688 ;
     RECT  63.097 57.408 63.317 58.152 ;
     RECT  63.251 65.664 63.317 65.688 ;
     RECT  63.251 68.352 63.317 68.904 ;
     RECT  63.277 85.104 63.317 85.416 ;
     RECT  63.317 68.544 63.349 68.904 ;
     RECT  62.104 72.336 63.385 72.36 ;
     RECT  62.104 79.728 63.385 79.752 ;
     RECT  63.277 86.592 63.395 86.76 ;
     RECT  62.104 88.368 63.395 88.392 ;
     RECT  63.317 85.248 63.425 85.416 ;
     RECT  63.317 57.408 63.461 57.864 ;
     RECT  63.349 68.544 63.461 69.72 ;
     RECT  63.137 82.032 63.461 82.056 ;
     RECT  62.627 60.768 63.497 60.792 ;
     RECT  62.104 17.568 63.533 17.592 ;
     RECT  63.109 61.872 63.533 62.664 ;
     RECT  62.104 41.568 63.539 41.592 ;
     RECT  63.101 44.304 63.539 44.328 ;
     RECT  63.385 72.336 63.539 73.272 ;
     RECT  62.104 14.88 63.637 14.904 ;
     RECT  62.104 16.32 63.637 16.344 ;
     RECT  63.493 42.96 63.637 42.984 ;
     RECT  63.461 57.408 63.673 57.432 ;
     RECT  63.533 61.872 63.781 61.896 ;
     RECT  63.277 33.264 63.817 33.288 ;
     RECT  62.675 25.152 63.829 26.136 ;
     RECT  63.277 74.688 63.884 74.712 ;
     RECT  63.299 75.792 63.884 76.488 ;
     RECT  63.884 74.688 64.141 76.488 ;
     RECT  63.097 40.32 64.172 40.344 ;
     RECT  64.172 40.272 64.177 40.344 ;
     RECT  62.104 38.4 64.213 38.424 ;
     RECT  64.177 40.272 64.213 41.016 ;
     RECT  63.637 42.816 64.213 42.984 ;
     RECT  63.245 8.16 64.22 8.184 ;
     RECT  63.277 6.816 64.261 6.84 ;
     RECT  64.22 7.824 64.261 8.184 ;
     RECT  63.539 72.336 64.268 72.36 ;
     RECT  63.097 91.44 64.285 91.464 ;
     RECT  63.461 69.696 64.309 69.72 ;
     RECT  64.285 90.576 64.316 91.464 ;
     RECT  64.177 92.88 64.357 92.904 ;
     RECT  63.169 93.984 64.357 94.68 ;
     RECT  64.213 42.384 64.429 42.984 ;
     RECT  63.637 27.312 64.501 27.336 ;
     RECT  64.429 42.384 64.501 43.416 ;
     RECT  63.277 5.088 64.508 5.112 ;
     RECT  64.261 6.144 64.508 8.184 ;
     RECT  64.285 9.792 64.508 9.816 ;
     RECT  64.357 11.952 64.508 11.976 ;
     RECT  63.637 14.4 64.508 16.344 ;
     RECT  64.177 17.664 64.508 18.216 ;
     RECT  64.177 20.592 64.508 20.616 ;
     RECT  63.097 21.648 64.508 21.672 ;
     RECT  63.829 25.056 64.508 26.232 ;
     RECT  64.501 27.312 64.508 27.432 ;
     RECT  63.817 33.264 64.508 34.248 ;
     RECT  64.177 35.904 64.508 35.928 ;
     RECT  64.213 38.4 64.508 41.016 ;
     RECT  64.501 42.384 64.508 43.56 ;
     RECT  63.709 45.6 64.508 45.624 ;
     RECT  62.741 47.088 64.508 47.112 ;
     RECT  62.104 50.88 64.508 50.904 ;
     RECT  62.705 54.096 64.508 54.12 ;
     RECT  63.673 56.448 64.508 57.432 ;
     RECT  63.781 61.728 64.508 61.896 ;
     RECT  64.357 64.368 64.508 65.16 ;
     RECT  63.461 68.544 64.508 68.568 ;
     RECT  64.309 69.696 64.508 70.584 ;
     RECT  64.268 71.616 64.508 72.36 ;
     RECT  64.141 74.64 64.508 76.488 ;
     RECT  63.745 78.48 64.508 78.504 ;
     RECT  63.385 79.584 64.508 80.424 ;
     RECT  63.425 85.392 64.508 85.416 ;
     RECT  63.395 86.736 64.508 86.76 ;
     RECT  64.393 88.944 64.508 88.968 ;
     RECT  64.316 90.576 64.508 91.848 ;
     RECT  64.357 92.88 64.508 94.68 ;
     RECT  64.465 95.664 64.508 95.688 ;
     RECT  64.508 2.148 64.612 99.372 ;
     RECT  64.612 2.418 64.804 99.102 ;
     RECT  64.804 45.12 64.901 45.72 ;
     RECT  64.804 20.592 64.931 22.728 ;
     RECT  64.804 81.552 64.931 81.576 ;
     RECT  64.804 95.664 64.931 95.688 ;
     RECT  64.804 97.008 64.931 97.032 ;
     RECT  64.804 41.664 64.937 43.56 ;
     RECT  64.804 33.648 64.972 34.344 ;
     RECT  64.931 20.592 65.045 22.2 ;
     RECT  64.804 24.624 65.117 27.432 ;
     RECT  64.804 64.992 65.153 68.424 ;
     RECT  65.153 66.72 65.197 68.424 ;
     RECT  65.045 21.504 65.225 22.2 ;
     RECT  64.804 74.64 65.225 74.664 ;
     RECT  64.804 86.784 65.225 88.968 ;
     RECT  64.804 7.728 65.297 9.672 ;
     RECT  65.297 7.872 65.363 9.672 ;
     RECT  64.804 11.376 65.405 11.4 ;
     RECT  64.972 33.648 65.441 34.2 ;
     RECT  64.804 50.496 65.459 51 ;
     RECT  64.804 49.008 65.513 49.032 ;
     RECT  64.804 12.384 65.555 14.424 ;
     RECT  64.804 70.8 65.555 72.408 ;
     RECT  64.804 76.464 65.555 76.488 ;
     RECT  65.363 7.872 65.657 9.144 ;
     RECT  65.225 86.784 65.657 88.344 ;
     RECT  64.804 80.496 65.693 80.52 ;
     RECT  64.804 4.512 65.699 5.16 ;
     RECT  64.804 35.664 65.699 36.84 ;
     RECT  65.657 86.784 65.699 87.192 ;
     RECT  65.699 36.48 65.729 36.84 ;
     RECT  65.197 68.112 65.729 68.424 ;
     RECT  64.804 84.96 65.74 85.8 ;
     RECT  64.804 53.76 65.765 54.648 ;
     RECT  65.153 64.992 65.765 65.64 ;
     RECT  64.804 77.952 65.765 78.696 ;
     RECT  65.117 24.624 65.795 26.808 ;
     RECT  64.804 31.248 65.797 31.944 ;
     RECT  64.804 52.08 65.797 52.488 ;
     RECT  65.795 26.64 65.801 26.808 ;
     RECT  65.555 70.8 65.801 70.824 ;
     RECT  64.804 29.568 65.833 29.592 ;
     RECT  64.804 17.664 65.836 18.408 ;
     RECT  65.459 50.496 65.837 50.568 ;
     RECT  65.765 54.144 65.837 54.648 ;
     RECT  65.797 51.84 65.843 52.488 ;
     RECT  65.765 65.136 65.843 65.64 ;
     RECT  64.804 39.36 65.869 39.384 ;
     RECT  65.797 75.168 65.905 75.192 ;
     RECT  65.801 26.64 65.909 26.664 ;
     RECT  64.804 56.16 65.909 57.48 ;
     RECT  65.699 86.832 65.909 87.192 ;
     RECT  65.797 15.168 65.945 15.192 ;
     RECT  65.797 31.248 65.945 32.472 ;
     RECT  65.836 17.664 65.977 17.688 ;
     RECT  65.869 39.36 65.989 40.056 ;
     RECT  65.945 31.92 66.013 32.472 ;
     RECT  65.977 17.472 66.017 17.688 ;
     RECT  66.013 31.92 66.053 33.048 ;
     RECT  65.837 50.496 66.053 50.52 ;
     RECT  64.804 69.408 66.053 69.432 ;
     RECT  65.765 78.048 66.053 78.696 ;
     RECT  64.804 91.44 66.053 92.664 ;
     RECT  65.197 66.72 66.076 66.744 ;
     RECT  65.837 54.432 66.085 54.648 ;
     RECT  65.909 56.88 66.133 57.48 ;
     RECT  65.555 12.384 66.161 13.704 ;
     RECT  65.905 75.168 66.161 75.816 ;
     RECT  66.053 92.16 66.161 92.664 ;
     RECT  65.657 88.32 66.179 88.344 ;
     RECT  65.555 71.808 66.197 72.408 ;
     RECT  65.797 63.744 66.229 63.768 ;
     RECT  66.197 72.336 66.229 72.408 ;
     RECT  65.833 74.064 66.229 74.088 ;
     RECT  65.729 36.816 66.265 36.84 ;
     RECT  66.193 82.992 66.265 83.016 ;
     RECT  66.229 80.976 66.277 81 ;
     RECT  66.265 82.656 66.277 83.016 ;
     RECT  64.901 45.12 66.284 45.144 ;
     RECT  65.797 19.968 66.301 19.992 ;
     RECT  66.013 43.872 66.301 43.896 ;
     RECT  66.284 45.12 66.325 45.576 ;
     RECT  64.804 47.088 66.325 47.112 ;
     RECT  66.325 45.12 66.469 47.112 ;
     RECT  66.428 48.624 66.469 48.648 ;
     RECT  66.085 54.432 66.589 54.744 ;
     RECT  66.133 55.728 66.589 55.752 ;
     RECT  64.804 61.2 66.589 62.136 ;
     RECT  66.161 75.168 66.589 75.192 ;
     RECT  66.301 43.872 66.613 44.088 ;
     RECT  66.469 45.12 66.613 48.648 ;
     RECT  66.161 13.008 66.625 13.704 ;
     RECT  66.133 56.88 66.661 57.624 ;
     RECT  64.804 58.656 66.661 59.544 ;
     RECT  66.229 72.336 67.021 74.088 ;
     RECT  66.589 75.12 67.021 75.192 ;
     RECT  65.699 4.512 67.208 4.536 ;
     RECT  65.869 6.816 67.208 6.84 ;
     RECT  65.657 7.872 67.208 8.568 ;
     RECT  66.625 13.008 67.208 14.088 ;
     RECT  64.804 16.32 67.208 16.344 ;
     RECT  66.017 17.472 67.208 17.496 ;
     RECT  66.301 19.968 67.208 20.28 ;
     RECT  65.225 21.504 67.208 21.528 ;
     RECT  65.795 24.624 67.208 24.936 ;
     RECT  65.833 28.992 67.208 29.592 ;
     RECT  66.053 32.448 67.208 33.048 ;
     RECT  65.441 34.128 67.208 34.2 ;
     RECT  66.265 36.816 67.208 37.032 ;
     RECT  64.804 38.208 67.208 38.232 ;
     RECT  65.989 39.36 67.208 40.152 ;
     RECT  64.937 41.664 67.208 42.84 ;
     RECT  66.613 43.872 67.208 48.648 ;
     RECT  65.843 51.84 67.208 51.864 ;
     RECT  66.589 54.432 67.208 55.752 ;
     RECT  66.661 56.88 67.208 59.544 ;
     RECT  66.589 61.2 67.208 62.712 ;
     RECT  66.229 63.744 67.208 63.816 ;
     RECT  65.843 65.568 67.208 65.64 ;
     RECT  66.589 67.872 67.208 67.896 ;
     RECT  66.301 69.504 67.208 69.528 ;
     RECT  67.021 72.336 67.208 75.192 ;
     RECT  66.053 78.624 67.208 78.696 ;
     RECT  66.277 80.976 67.208 83.016 ;
     RECT  65.74 84.96 67.208 84.984 ;
     RECT  65.909 87.024 67.208 87.192 ;
     RECT  66.161 92.16 67.208 92.184 ;
     RECT  64.804 94.656 67.208 94.68 ;
     RECT  65.797 95.712 67.208 95.736 ;
     RECT  66.697 96.912 67.208 96.936 ;
     RECT  67.208 2.148 67.312 99.372 ;
     RECT  67.312 2.418 67.504 99.102 ;
     RECT  67.504 54.432 67.529 55.128 ;
     RECT  67.504 74.592 67.565 74.616 ;
     RECT  67.504 46.464 67.745 47.88 ;
     RECT  67.504 72.816 67.781 72.84 ;
     RECT  67.504 16.32 67.853 17.016 ;
     RECT  67.504 57.408 67.853 57.432 ;
     RECT  67.745 46.464 67.889 46.488 ;
     RECT  67.504 71.76 67.925 71.784 ;
     RECT  67.504 33.552 68.069 33.576 ;
     RECT  67.504 42.72 68.177 42.744 ;
     RECT  67.529 55.104 68.213 55.128 ;
     RECT  67.504 78.336 68.321 78.36 ;
     RECT  67.745 47.856 68.393 47.88 ;
     RECT  67.504 37.008 68.465 37.032 ;
     RECT  67.504 58.608 68.465 58.632 ;
     RECT  68.965 94.176 69.253 94.2 ;
     RECT  69.253 55.104 69.289 55.128 ;
     RECT  69.253 90.576 69.289 90.6 ;
     RECT  69.253 93.696 69.289 94.2 ;
     RECT  67.504 11.952 69.325 11.976 ;
     RECT  68.569 33.024 69.325 33.048 ;
     RECT  69.289 37.104 69.325 37.32 ;
     RECT  69.289 38.592 69.325 38.616 ;
     RECT  69.289 60.192 69.325 60.504 ;
     RECT  68.497 79.776 69.325 79.8 ;
     RECT  69.253 30.24 69.361 30.264 ;
     RECT  68.965 42.336 69.361 42.36 ;
     RECT  69.325 47.568 69.361 47.592 ;
     RECT  69.289 76.176 69.361 76.2 ;
     RECT  69.289 96.96 69.361 96.984 ;
     RECT  69.361 9.312 69.397 9.336 ;
     RECT  69.361 51.984 69.397 52.008 ;
     RECT  69.325 67.392 69.397 67.416 ;
     RECT  69.289 86.688 69.397 86.712 ;
     RECT  69.361 88.608 69.397 88.632 ;
     RECT  69.289 90.096 69.397 90.6 ;
     RECT  69.289 93.552 69.397 94.2 ;
     RECT  69.397 6.72 69.433 6.744 ;
     RECT  69.325 11.952 69.433 12.456 ;
     RECT  69.397 22.752 69.433 22.776 ;
     RECT  69.361 42.336 69.433 42.696 ;
     RECT  69.397 49.872 69.433 49.896 ;
     RECT  69.397 51.984 69.433 52.824 ;
     RECT  69.325 59.856 69.433 60.504 ;
     RECT  68.677 74.064 69.433 74.088 ;
     RECT  67.504 84.864 69.433 84.888 ;
     RECT  69.397 86.16 69.433 86.712 ;
     RECT  68.965 92.544 69.433 92.568 ;
     RECT  69.397 93.552 69.433 94.68 ;
     RECT  69.433 25.68 69.469 25.704 ;
     RECT  69.433 49.728 69.469 49.896 ;
     RECT  69.289 64.272 69.469 64.296 ;
     RECT  69.397 66.864 69.469 67.416 ;
     RECT  69.433 6.384 69.505 6.744 ;
     RECT  68.677 7.824 69.505 7.848 ;
     RECT  69.397 9.312 69.505 9.816 ;
     RECT  69.433 11.952 69.505 13.752 ;
     RECT  67.853 16.992 69.505 17.016 ;
     RECT  69.361 18.624 69.505 18.648 ;
     RECT  69.433 21.888 69.505 23.4 ;
     RECT  69.469 25.2 69.505 25.704 ;
     RECT  69.361 29.76 69.505 30.936 ;
     RECT  69.325 33.024 69.505 33.528 ;
     RECT  69.397 35.328 69.505 35.352 ;
     RECT  69.325 37.104 69.505 38.616 ;
     RECT  68.677 40.56 69.505 40.584 ;
     RECT  69.433 42.336 69.505 42.888 ;
     RECT  69.433 45.6 69.505 46.296 ;
     RECT  69.361 47.424 69.505 47.592 ;
     RECT  69.469 49.728 69.505 50.376 ;
     RECT  69.433 51.984 69.505 53.64 ;
     RECT  69.289 54.96 69.505 55.128 ;
     RECT  69.469 57.888 69.505 57.912 ;
     RECT  69.433 59.52 69.505 60.504 ;
     RECT  69.469 64.272 69.505 65.256 ;
     RECT  69.469 66.864 69.505 68.232 ;
     RECT  69.361 70.8 69.505 70.824 ;
     RECT  69.433 74.064 69.505 74.76 ;
     RECT  69.361 76.176 69.505 77.064 ;
     RECT  69.469 78.672 69.505 78.696 ;
     RECT  69.325 79.776 69.505 80.616 ;
     RECT  69.289 83.712 69.505 83.736 ;
     RECT  69.433 84.864 69.505 86.712 ;
     RECT  69.397 88.608 69.505 90.6 ;
     RECT  69.433 92.4 69.505 92.568 ;
     RECT  69.505 5.232 69.541 5.256 ;
     RECT  69.505 6.384 69.541 9.816 ;
     RECT  69.505 11.136 69.541 14.424 ;
     RECT  69.505 21.888 69.541 27 ;
     RECT  69.505 28.272 69.541 30.936 ;
     RECT  69.505 47.424 69.541 48.744 ;
     RECT  69.505 49.728 69.541 55.464 ;
     RECT  69.505 62.784 69.541 70.824 ;
     RECT  69.505 76.032 69.541 86.712 ;
     RECT  69.505 88.608 69.541 92.568 ;
     RECT  69.433 93.552 69.541 95.352 ;
     RECT  69.361 96.48 69.541 96.984 ;
     RECT  69.541 4.416 69.577 5.256 ;
     RECT  69.541 19.968 69.577 19.992 ;
     RECT  69.541 21.6 69.577 31.416 ;
     RECT  69.505 36.48 69.577 39.576 ;
     RECT  69.505 40.56 69.577 41.064 ;
     RECT  69.541 47.424 69.577 55.464 ;
     RECT  69.505 57.744 69.577 57.912 ;
     RECT  69.505 59.04 69.577 61.32 ;
     RECT  69.541 62.448 69.577 70.824 ;
     RECT  69.505 73.104 69.577 74.76 ;
     RECT  69.541 76.032 69.577 92.568 ;
     RECT  69.541 93.552 69.577 96.984 ;
     RECT  69.577 4.416 69.649 5.4 ;
     RECT  69.541 6.384 69.649 14.424 ;
     RECT  69.361 15.84 69.649 15.864 ;
     RECT  69.505 16.992 69.649 18.984 ;
     RECT  69.577 19.968 69.649 31.416 ;
     RECT  69.577 36.48 69.649 41.064 ;
     RECT  69.505 42.336 69.649 46.296 ;
     RECT  69.577 47.28 69.649 55.464 ;
     RECT  69.505 56.736 69.649 56.76 ;
     RECT  69.577 57.744 69.649 70.824 ;
     RECT  69.505 34.848 69.685 35.352 ;
     RECT  69.649 36.48 69.685 46.296 ;
     RECT  69.577 72.096 69.685 72.12 ;
     RECT  69.577 73.104 69.685 96.984 ;
     RECT  69.685 34.848 69.937 46.296 ;
     RECT  69.649 47.28 69.937 70.968 ;
     RECT  69.685 72.096 69.937 96.984 ;
     RECT  69.649 4.416 70.045 31.416 ;
     RECT  69.505 32.688 70.045 33.864 ;
     RECT  70.045 4.416 70.081 33.864 ;
     RECT  69.937 34.848 70.081 70.968 ;
     RECT  69.937 71.952 70.081 96.984 ;
     RECT  70.081 4.416 70.657 96.984 ;
     RECT  70.657 4.416 71.1 97.176 ;
    LAYER M5 ;
     RECT  2.4 2.137 2.52 2.151 ;
     RECT  5.1 2.137 5.22 2.151 ;
     RECT  7.8 2.137 7.92 2.151 ;
     RECT  10.5 2.137 10.62 2.151 ;
     RECT  13.2 2.137 13.32 2.151 ;
     RECT  15.9 2.137 16.02 2.151 ;
     RECT  18.6 2.137 18.72 2.151 ;
     RECT  21.3 2.137 21.42 2.151 ;
     RECT  24 2.137 24.12 2.151 ;
     RECT  26.7 2.137 26.82 2.151 ;
     RECT  29.4 2.137 29.52 2.151 ;
     RECT  32.1 2.137 32.22 2.151 ;
     RECT  34.8 2.137 34.92 2.151 ;
     RECT  37.5 2.137 37.62 2.151 ;
     RECT  40.2 2.137 40.32 2.151 ;
     RECT  42.9 2.137 43.02 2.151 ;
     RECT  45.6 2.137 45.72 2.151 ;
     RECT  48.3 2.137 48.42 2.151 ;
     RECT  51 2.137 51.12 2.151 ;
     RECT  53.7 2.137 53.82 2.151 ;
     RECT  56.4 2.137 56.52 2.151 ;
     RECT  59.1 2.137 59.22 2.151 ;
     RECT  61.8 2.137 61.92 2.151 ;
     RECT  64.5 2.137 64.62 2.151 ;
     RECT  67.2 2.137 67.32 2.151 ;
     RECT  59.1 2.151 59.412 2.821 ;
     RECT  61.8 2.151 62.112 4.117 ;
     RECT  64.5 2.151 64.812 4.501 ;
     RECT  2.4 2.151 2.712 5.029 ;
     RECT  5.1 2.151 5.412 5.029 ;
     RECT  7.8 2.151 8.112 5.029 ;
     RECT  64.5 4.501 65.688 5.171 ;
     RECT  2.256 5.029 2.712 5.219 ;
     RECT  6.864 5.029 8.112 6.083 ;
     RECT  64.5 5.171 64.812 6.133 ;
     RECT  7.8 6.083 8.112 7.381 ;
     RECT  4.512 5.029 5.412 7.475 ;
     RECT  64.272 6.133 64.812 7.859 ;
     RECT  64.5 7.859 64.812 7.909 ;
     RECT  64.5 7.909 65.688 8.579 ;
     RECT  5.1 7.475 5.412 9.589 ;
     RECT  7.104 7.381 8.112 9.637 ;
     RECT  64.5 8.579 64.812 9.637 ;
     RECT  58.368 2.821 59.412 9.923 ;
     RECT  4.704 9.589 5.412 9.925 ;
     RECT  18.6 2.151 18.912 10.213 ;
     RECT  18.6 10.213 19.032 10.355 ;
     RECT  61.8 4.117 62.664 10.453 ;
     RECT  4.128 9.925 5.412 10.883 ;
     RECT  6.912 9.637 8.232 10.883 ;
     RECT  7.104 10.883 8.232 11.027 ;
     RECT  2.4 5.219 2.712 11.605 ;
     RECT  2.256 11.605 2.712 11.747 ;
     RECT  64.5 9.637 65.352 12.373 ;
     RECT  7.104 11.027 8.112 12.901 ;
     RECT  5.1 10.883 5.412 12.997 ;
     RECT  7.104 12.901 8.232 13.043 ;
     RECT  7.8 13.043 8.232 14.291 ;
     RECT  64.5 12.373 65.544 14.435 ;
     RECT  61.8 10.453 63.144 14.915 ;
     RECT  7.8 14.291 8.112 16.645 ;
     RECT  61.8 14.915 62.664 17.557 ;
     RECT  64.5 14.435 64.92 17.653 ;
     RECT  64.5 17.653 65.784 18.419 ;
     RECT  7.68 16.645 8.112 18.851 ;
     RECT  3.984 18.757 4.008 18.899 ;
     RECT  61.8 17.557 63.144 19.763 ;
     RECT  2.4 11.747 2.712 20.821 ;
     RECT  2.4 20.821 2.808 20.963 ;
     RECT  5.1 12.997 5.688 20.965 ;
     RECT  7.8 18.851 8.112 21.493 ;
     RECT  4.896 20.965 5.688 21.971 ;
     RECT  2.4 20.963 2.712 22.597 ;
     RECT  61.8 19.763 62.664 22.835 ;
     RECT  5.1 21.971 5.688 23.267 ;
     RECT  7.68 21.493 8.112 23.699 ;
     RECT  2.4 22.597 3.432 23.747 ;
     RECT  5.1 23.267 5.592 23.845 ;
     RECT  4.752 23.845 5.592 24.515 ;
     RECT  64.5 18.419 64.92 25.045 ;
     RECT  61.8 22.835 62.568 25.141 ;
     RECT  63.84 25.045 64.92 25.573 ;
     RECT  2.4 23.747 3.096 25.667 ;
     RECT  61.8 25.141 62.76 25.667 ;
     RECT  63.84 25.573 65.784 26.243 ;
     RECT  64.5 26.243 65.784 26.819 ;
     RECT  5.1 24.515 5.592 28.501 ;
     RECT  5.1 28.501 6.168 30.757 ;
     RECT  7.8 23.699 8.112 30.757 ;
     RECT  0.192 30.757 0.216 30.899 ;
     RECT  5.1 30.757 8.112 30.899 ;
     RECT  64.5 26.819 64.92 31.669 ;
     RECT  64.5 31.669 65.448 31.861 ;
     RECT  7.8 30.899 8.112 32.437 ;
     RECT  3.984 32.197 4.008 32.869 ;
     RECT  61.8 25.667 62.664 32.869 ;
     RECT  3.744 32.869 4.008 32.915 ;
     RECT  3.744 32.915 3.768 33.635 ;
     RECT  64.5 31.861 65.544 34.117 ;
     RECT  5.1 30.899 6.168 35.123 ;
     RECT  61.8 32.869 62.76 35.171 ;
     RECT  64.5 34.117 65.688 35.699 ;
     RECT  7.8 32.437 8.616 37.573 ;
     RECT  5.1 35.123 5.928 38.581 ;
     RECT  7.152 37.573 8.616 38.771 ;
     RECT  64.5 35.699 65.544 39.301 ;
     RECT  4.416 38.581 5.928 39.347 ;
     RECT  64.224 39.301 65.544 39.349 ;
     RECT  64.224 39.349 66.024 40.163 ;
     RECT  61.8 35.171 62.664 40.309 ;
     RECT  64.224 40.163 65.544 40.309 ;
     RECT  5.1 39.347 5.928 41.029 ;
     RECT  61.8 40.309 65.544 42.419 ;
     RECT  5.1 41.029 6.072 42.709 ;
     RECT  67.2 2.151 67.512 42.805 ;
     RECT  64.5 42.419 65.544 42.851 ;
     RECT  4.512 42.709 6.072 43.285 ;
     RECT  61.8 42.419 63.528 44.339 ;
     RECT  4.224 43.285 6.072 44.675 ;
     RECT  61.8 44.339 62.664 44.965 ;
     RECT  64.5 42.851 65.448 45.541 ;
     RECT  66.624 42.805 67.512 45.541 ;
     RECT  64.5 45.541 67.512 46.499 ;
     RECT  5.1 44.675 6.072 46.787 ;
     RECT  67.2 46.499 67.512 47.845 ;
     RECT  2.4 25.667 2.712 48.421 ;
     RECT  66.48 47.845 67.512 48.659 ;
     RECT  2.4 48.421 3.432 49.043 ;
     RECT  7.8 38.771 8.616 50.725 ;
     RECT  12.144 0.133 12.168 50.915 ;
     RECT  26.7 2.151 27.816 51.155 ;
     RECT  64.5 46.499 65.448 51.829 ;
     RECT  64.5 51.829 65.832 52.499 ;
     RECT  2.4 49.043 2.712 52.981 ;
     RECT  64.5 52.499 65.544 54.611 ;
     RECT  2.4 52.981 2.808 55.187 ;
     RECT  5.1 46.787 5.412 55.285 ;
     RECT  64.5 54.611 65.448 55.717 ;
     RECT  6.624 52.405 6.648 55.813 ;
     RECT  6.432 55.813 6.648 55.859 ;
     RECT  61.68 44.965 62.664 56.389 ;
     RECT  4.512 55.285 5.412 57.059 ;
     RECT  6.432 55.859 6.456 57.445 ;
     RECT  64.5 55.717 66.168 57.635 ;
     RECT  61.68 56.389 63.24 57.875 ;
     RECT  6.432 57.445 6.504 58.163 ;
     RECT  64.5 57.635 65.448 58.691 ;
     RECT  5.1 57.059 5.412 60.373 ;
     RECT  6.432 58.163 6.456 60.373 ;
     RECT  5.1 60.373 6.456 61.379 ;
     RECT  3.936 60.277 3.96 61.619 ;
     RECT  64.5 58.691 65.352 61.619 ;
     RECT  2.4 55.187 2.712 62.005 ;
     RECT  2.304 62.005 2.712 62.195 ;
     RECT  6.432 61.379 6.456 62.581 ;
     RECT  7.8 50.725 8.808 62.581 ;
     RECT  61.68 57.875 62.664 62.629 ;
     RECT  6.432 62.581 8.808 62.723 ;
     RECT  64.5 61.619 65.256 63.733 ;
     RECT  5.1 61.379 5.412 63.829 ;
     RECT  6.432 62.723 6.456 63.829 ;
     RECT  61.68 62.629 63.144 64.115 ;
     RECT  64.5 63.733 65.832 64.357 ;
     RECT  5.1 63.829 6.456 64.595 ;
     RECT  64.368 64.357 65.832 65.171 ;
     RECT  61.68 64.115 62.76 65.269 ;
     RECT  64.5 65.171 65.832 65.557 ;
     RECT  2.4 62.195 2.712 65.749 ;
     RECT  5.1 64.595 5.412 65.941 ;
     RECT  6.432 64.595 6.456 65.941 ;
     RECT  64.5 65.557 66.024 66.755 ;
     RECT  5.1 65.941 6.456 66.803 ;
     RECT  61.68 65.269 63.24 67.475 ;
     RECT  2.4 65.749 3.432 68.099 ;
     RECT  5.1 66.803 5.412 68.341 ;
     RECT  6.432 66.803 6.456 68.341 ;
     RECT  5.1 68.341 6.456 68.387 ;
     RECT  7.8 62.723 8.808 68.435 ;
     RECT  61.68 67.475 62.76 68.773 ;
     RECT  64.5 66.755 65.256 69.397 ;
     RECT  61.68 68.773 63.384 69.731 ;
     RECT  64.5 69.397 65.544 70.549 ;
     RECT  61.68 69.731 62.664 71.123 ;
     RECT  4.032 69.493 4.056 71.747 ;
     RECT  64.32 70.549 65.544 71.797 ;
     RECT  64.32 71.797 65.592 72.371 ;
     RECT  64.5 72.371 65.592 72.419 ;
     RECT  61.8 71.123 62.664 73.237 ;
     RECT  7.8 68.435 8.328 74.675 ;
     RECT  61.8 73.237 63.528 74.723 ;
     RECT  64.5 72.419 65.544 75.109 ;
     RECT  61.8 74.723 62.664 75.781 ;
     RECT  63.936 75.109 65.544 75.781 ;
     RECT  61.8 75.781 65.544 76.259 ;
     RECT  61.8 76.259 63.288 76.979 ;
     RECT  7.8 74.675 8.232 77.555 ;
     RECT  67.2 48.659 67.512 78.613 ;
     RECT  64.5 76.259 65.544 78.661 ;
     RECT  66.672 78.613 67.512 78.661 ;
     RECT  64.5 78.661 67.512 78.707 ;
     RECT  5.1 68.387 6.12 79.187 ;
     RECT  64.5 78.707 64.812 80.485 ;
     RECT  64.5 80.485 64.92 81.587 ;
     RECT  7.8 77.555 8.112 82.549 ;
     RECT  7.104 82.549 8.112 83.075 ;
     RECT  61.8 76.979 62.472 83.267 ;
     RECT  7.8 83.075 8.112 85.765 ;
     RECT  64.5 81.587 64.812 85.765 ;
     RECT  66.288 78.707 67.512 85.765 ;
     RECT  7.152 85.765 8.112 86.675 ;
     RECT  64.5 85.765 67.512 86.819 ;
     RECT  5.1 79.187 5.832 87.685 ;
     RECT  5.1 87.685 6.552 87.731 ;
     RECT  66.144 86.819 67.512 88.355 ;
     RECT  63.36 86.581 63.384 88.403 ;
     RECT  7.8 86.675 8.112 88.885 ;
     RECT  6.528 87.731 6.552 90.373 ;
     RECT  7.8 88.885 8.232 90.373 ;
     RECT  64.5 86.819 64.812 90.565 ;
     RECT  6.528 90.373 8.232 90.995 ;
     RECT  5.1 87.731 5.412 91.141 ;
     RECT  4.464 91.141 5.412 91.859 ;
     RECT  64.368 90.565 64.812 91.859 ;
     RECT  7.8 90.995 8.232 92.099 ;
     RECT  66.288 88.355 67.512 92.195 ;
     RECT  5.1 91.859 5.412 92.245 ;
     RECT  6.528 90.995 6.552 92.245 ;
     RECT  5.1 92.245 6.552 92.291 ;
     RECT  64.5 91.859 64.812 92.869 ;
     RECT  64.368 92.869 64.812 94.019 ;
     RECT  5.1 92.291 6.312 94.115 ;
     RECT  63.264 93.973 63.288 94.691 ;
     RECT  5.1 94.115 5.412 95.125 ;
     RECT  64.5 94.019 64.812 95.653 ;
     RECT  5.1 95.125 5.688 96.323 ;
     RECT  64.5 95.653 64.92 97.043 ;
     RECT  2.4 68.099 2.712 99.369 ;
     RECT  5.1 96.323 5.412 99.369 ;
     RECT  7.8 92.099 8.112 99.369 ;
     RECT  10.5 2.151 10.812 99.369 ;
     RECT  13.2 2.151 13.512 99.369 ;
     RECT  15.9 2.151 16.212 99.369 ;
     RECT  18.6 10.355 18.912 99.369 ;
     RECT  21.3 2.151 21.612 99.369 ;
     RECT  24 2.151 24.312 99.369 ;
     RECT  26.7 51.155 27.012 99.369 ;
     RECT  29.4 2.151 29.712 99.369 ;
     RECT  32.1 2.151 32.412 99.369 ;
     RECT  34.8 2.151 35.112 99.369 ;
     RECT  37.5 2.151 37.812 99.369 ;
     RECT  40.2 2.151 40.512 99.369 ;
     RECT  42.9 2.151 43.212 99.369 ;
     RECT  45.6 2.151 45.912 99.369 ;
     RECT  48.3 2.151 48.612 99.369 ;
     RECT  51 2.151 51.312 99.369 ;
     RECT  53.7 2.151 54.012 99.369 ;
     RECT  56.4 2.151 56.712 99.369 ;
     RECT  59.1 9.923 59.412 99.369 ;
     RECT  61.8 83.267 62.112 99.369 ;
     RECT  64.5 97.043 64.812 99.369 ;
     RECT  67.2 92.195 67.512 99.369 ;
     RECT  2.4 99.369 2.52 99.383 ;
     RECT  5.1 99.369 5.22 99.383 ;
     RECT  7.8 99.369 7.92 99.383 ;
     RECT  10.5 99.369 10.62 99.383 ;
     RECT  13.2 99.369 13.32 99.383 ;
     RECT  15.9 99.369 16.02 99.383 ;
     RECT  18.6 99.369 18.72 99.383 ;
     RECT  21.3 99.369 21.42 99.383 ;
     RECT  24 99.369 24.12 99.383 ;
     RECT  26.7 99.369 26.82 99.383 ;
     RECT  29.4 99.369 29.52 99.383 ;
     RECT  32.1 99.369 32.22 99.383 ;
     RECT  34.8 99.369 34.92 99.383 ;
     RECT  37.5 99.369 37.62 99.383 ;
     RECT  40.2 99.369 40.32 99.383 ;
     RECT  42.9 99.369 43.02 99.383 ;
     RECT  45.6 99.369 45.72 99.383 ;
     RECT  48.3 99.369 48.42 99.383 ;
     RECT  51 99.369 51.12 99.383 ;
     RECT  53.7 99.369 53.82 99.383 ;
     RECT  56.4 99.369 56.52 99.383 ;
     RECT  59.1 99.369 59.22 99.383 ;
     RECT  61.8 99.369 61.92 99.383 ;
     RECT  64.5 99.369 64.62 99.383 ;
     RECT  67.2 99.369 67.32 99.383 ;
     RECT  10.62 2.137 12.144 2.151 ;
     RECT  12.168 2.137 13.2 50.915 ;
     RECT  10.812 2.151 12.144 50.915 ;
     RECT  65.688 4.501 67.2 5.171 ;
     RECT  5.412 5.029 6.864 6.083 ;
     RECT  7.104 6.083 7.8 7.381 ;
     RECT  65.688 7.909 67.2 8.579 ;
     RECT  64.812 8.579 65.352 9.637 ;
     RECT  5.412 9.637 6.912 10.883 ;
     RECT  2.712 9.925 4.128 10.883 ;
     RECT  63.144 10.453 64.5 14.915 ;
     RECT  5.688 12.997 7.104 13.043 ;
     RECT  63.144 17.557 64.5 19.763 ;
     RECT  65.784 17.653 67.2 18.419 ;
     RECT  2.712 18.757 3.984 18.899 ;
     RECT  4.008 18.757 5.1 18.899 ;
     RECT  62.568 25.045 63.84 25.141 ;
     RECT  62.76 25.141 63.84 25.667 ;
     RECT  65.784 25.573 67.2 26.819 ;
     RECT  62.664 25.667 63.84 26.243 ;
     RECT  2.712 32.197 3.984 32.869 ;
     RECT  4.008 32.197 5.1 32.915 ;
     RECT  2.712 32.869 3.744 33.635 ;
     RECT  3.768 32.915 5.1 33.635 ;
     RECT  65.688 34.117 67.2 35.699 ;
     RECT  5.928 37.573 7.152 38.771 ;
     RECT  66.024 39.349 67.2 40.163 ;
     RECT  63.528 42.419 64.5 44.339 ;
     RECT  65.544 42.805 66.624 42.851 ;
     RECT  65.448 42.851 66.624 45.541 ;
     RECT  2.712 43.285 4.224 44.675 ;
     RECT  65.448 46.499 67.2 47.845 ;
     RECT  65.448 47.845 66.48 48.659 ;
     RECT  65.832 51.829 67.2 52.499 ;
     RECT  5.412 52.405 6.624 55.813 ;
     RECT  6.648 52.405 7.8 55.859 ;
     RECT  65.448 54.611 65.544 55.717 ;
     RECT  66.168 55.717 67.2 57.635 ;
     RECT  5.412 55.813 6.432 60.373 ;
     RECT  6.456 55.859 7.8 57.445 ;
     RECT  63.24 56.389 64.5 57.875 ;
     RECT  6.504 57.445 7.8 58.163 ;
     RECT  6.456 58.163 7.8 62.581 ;
     RECT  2.712 60.277 3.936 61.619 ;
     RECT  3.96 60.277 5.1 61.619 ;
     RECT  5.412 61.379 6.432 63.829 ;
     RECT  63.144 62.629 64.5 64.115 ;
     RECT  6.456 62.723 7.8 68.387 ;
     RECT  65.832 63.733 67.2 65.557 ;
     RECT  62.76 64.115 64.5 64.357 ;
     RECT  62.76 64.357 64.368 65.171 ;
     RECT  5.412 64.595 6.432 65.941 ;
     RECT  62.76 65.171 64.5 65.269 ;
     RECT  63.24 65.269 64.5 67.475 ;
     RECT  66.024 65.557 67.2 66.755 ;
     RECT  5.412 66.803 6.432 68.341 ;
     RECT  62.76 67.475 64.5 68.773 ;
     RECT  2.712 68.099 3.432 69.493 ;
     RECT  63.384 68.773 64.5 69.731 ;
     RECT  2.712 69.493 4.032 71.747 ;
     RECT  4.056 69.493 5.1 71.747 ;
     RECT  64.32 69.731 64.5 70.549 ;
     RECT  64.32 72.371 64.5 73.237 ;
     RECT  63.528 73.237 64.5 74.723 ;
     RECT  62.664 74.723 64.5 75.109 ;
     RECT  62.664 75.109 63.936 75.781 ;
     RECT  63.288 76.259 64.5 76.979 ;
     RECT  65.544 78.613 66.672 78.661 ;
     RECT  64.812 78.707 66.288 80.485 ;
     RECT  64.92 80.485 66.288 81.587 ;
     RECT  64.812 81.587 66.288 85.765 ;
     RECT  5.832 82.549 7.104 83.075 ;
     RECT  5.832 85.765 7.152 86.675 ;
     RECT  62.112 86.581 63.36 88.403 ;
     RECT  63.384 86.581 64.5 88.403 ;
     RECT  5.832 86.675 7.8 87.685 ;
     RECT  64.812 86.819 66.144 88.355 ;
     RECT  6.552 87.685 7.8 90.373 ;
     RECT  5.412 87.731 6.528 92.245 ;
     RECT  64.812 88.355 66.288 92.195 ;
     RECT  6.552 90.995 7.8 92.291 ;
     RECT  64.368 91.859 64.5 92.869 ;
     RECT  6.312 92.291 7.8 94.115 ;
     RECT  62.112 93.973 63.264 94.691 ;
     RECT  63.288 93.973 64.368 94.019 ;
     RECT  63.288 94.019 64.5 94.691 ;
     RECT  5.412 94.115 5.688 95.125 ;
  END
END dsfd_l2r_vr_564x1__hx_W
END LIBRARY
